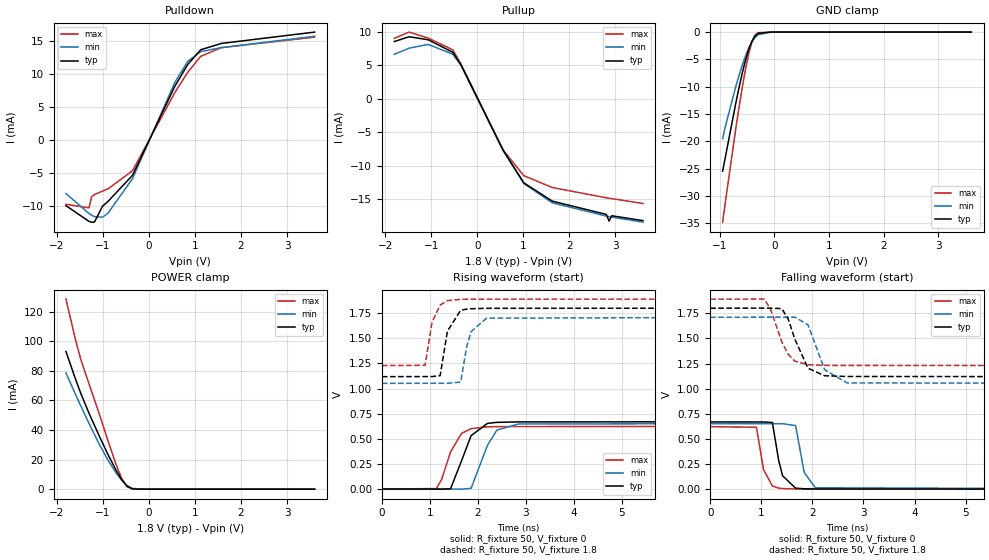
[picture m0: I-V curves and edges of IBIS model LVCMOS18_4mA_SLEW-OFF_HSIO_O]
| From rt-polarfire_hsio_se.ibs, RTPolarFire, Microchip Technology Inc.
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|   Model LVCMOS18_4mA_SLEW-OFF_HSIO_O
[Model]   LVCMOS18_4mA_SLEW-OFF_HSIO_O
Model_type   Output
Polarity   Non-Inverting
Enable   Active-High
Vmeas =   0.9
Cref =   5p
Rref =   1M
|   typ   min   max
C_comp_pullup   1.335e-12   1.335e-12   1.380e-12
C_comp_pulldown  1.335e-12   1.335e-12   1.380e-12
[Temperature Range]  25C   125C   -55C
[Voltage Range]  1.8   1.71   1.89
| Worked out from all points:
|   slope of the pulldown table from 0 to 0.27 V, typ, clamps not added: 66.5 ohm
|   slope of the pullup table from 0 to 0.27 V, typ, clamps not added: 70.9 ohm
|   GND clamp passes 1 mA (typ) near -0.37 V on its own axis
|   POWER clamp passes 1 mA (typ) near -0.43 V on its own axis
|   rising waveform, R_fixture 50, V_fixture 0: 20-80 % time 293ps typ, 300ps min, 297ps max; typ from 0 V to 0.669 V
|   rising waveform, R_fixture 50, V_fixture 1.8: 20-80 % time 171ps typ, 177ps min, 165ps max; typ from 1.12 V to 1.8 V
|   falling waveform, R_fixture 50, V_fixture 0: 20-80 % time 141ps typ, 145ps min, 133ps max; typ from 0.669 V to 0 V
|   falling waveform, R_fixture 50, V_fixture 1.8: 20-80 % time 296ps typ, 286ps min, 299ps max; typ from 1.8 V to 1.12 V
[GND Clamp]
| Voltage   I(typ)   I(min)   I(max)
-945mV    -25.47mA   -19.54mA   -34.82mA
-885.9mV  -22.44mA   -16.92mA   -30.49mA
-708.7mV  -13.24mA   -10.14mA   -17.96mA
-649.7mV  -10.37mA   -8.095mA   -14.06mA
-590.6mV  -7.705mA   -6.193mA   -10.39mA
-531.6mV  -5.322mA   -4.488mA   -7.054mA
-472.5mV  -3.308mA   -3.028mA   -4.171mA
-413.4mV  -1.757mA   -1.859mA   -1.935mA
-354.4mV  -739.5uA   -1.008mA   -580.7uA
-295.3mV  -232.3uA   -469.6uA   -100.4uA
-59.06mV  -489.8nA   -5.037uA   -176.4nA
3.6V      0A         0A         0A
[POWER Clamp]
| Voltage   I(typ)   I(min)   I(max)
-1.8V     93.11mA    78.62mA    128.6mA
-1.595V   74.64mA    64.3mA     101.3mA
-1.477V   64.73mA    56.26mA    87.68mA
-1.299V   51.32mA    44.43mA    71.22mA
-1.063V   35.01mA    29.59mA    49.65mA
-885.9mV  23.32mA    19.56mA    32.61mA
-708.7mV  12.62mA    10.87mA    16.4mA
-590.6mV  6.476mA    6.104mA    7.295mA
-472.5mV  1.932mA    2.452mA    1.539mA
-354.4mV  154uA      480.4uA    74.19uA
-59.06mV  800.7nA    2.877uA    466.9nA
3.6V      0A         0A         0A
[Pullup]
| Voltage   I(typ)   I(min)   I(max)
-1.8V     8.524mA    6.626mA    9.002mA
-1.477V   9.241mA    7.533mA    9.935mA
-1.063V   8.786mA    8.089mA    9.033mA
-531.6mV  6.927mA    6.646mA    7.296mA
-354.4mV  5.074mA    4.991mA    5.191mA
562.5mV   -7.703mA   -7.718mA   -7.67mA
1.012V    -12.57mA   -12.68mA   -11.51mA
1.631V    -15.31mA   -15.56mA   -13.27mA
2.804V    -17.29mA   -17.54mA   -14.81mA
2.863V    -18.28mA   -17.61mA   -14.87mA
2.922V    -17.49mA   -17.68mA   -14.93mA
3.6V      -18.22mA   -18.45mA   -15.66mA
[Pulldown]
| Voltage   I(typ)   I(min)   I(max)
-1.8V     -9.983mA   -8.14mA    -9.768mA
-1.299V   -12.37mA   -11.18mA   -10.32mA
-1.24V    -12.49mA   -11.44mA   -8.582mA
-1.181V   -12.47mA   -11.65mA   -8.302mA
-1.004V   -10.04mA   -11.73mA   -7.754mA
-885.9mV  -9.33mA    -11.1mA    -7.432mA
-354.4mV  -5.371mA   -5.881mA   -4.677mA
562.5mV   8.106mA    8.705mA    7.155mA
843.8mV   11.43mA    11.9mA     10.25mA
1.125V    13.67mA    13.39mA    12.67mA
1.575V    14.63mA    13.99mA    13.99mA
3.6V      16.35mA    15.72mA    15.58mA
[Ramp]
dV/dt_r   0.40141/0.293307n  0.391132/0.300125n  0.373348/0.296926n
dV/dt_f   0.408948/0.296334n  0.395259/0.285722n  0.396889/0.299047n
R_load = 50
[Rising Waveform]
R_fixture = 50
V_fixture = 0
V_fixture_min = 0
V_fixture_max = 0
| Time   V(typ)   V(min)   V(max)
0s        2.834uV    4.926uV    4.656uV
1.134ns   -858.8uV   -562.9uV   4.476mV
1.244ns   -1.435mV   -617.9uV   93.34mV
1.431ns   2.946mV    -711.6uV   369.2mV
1.659ns   280.3mV    -1.164mV   553.5mV
1.858ns   530.8mV    6.611mV    600.3mV
2.2ns     653.1mV    435.3mV    619.1mV
2.398ns   663.3mV    586.8mV    620.6mV
2.849ns   667.8mV    647.1mV    621.4mV
10ns      669mV      651.9mV    622.3mV
[Rising Waveform]
R_fixture = 50
V_fixture = 1.8
V_fixture_min = 1.71
V_fixture_max = 1.89
| Time   V(typ)   V(min)   V(max)
0s        1.118V     1.051V     1.228V
901ps     1.119V     1.052V     1.231V
1.046ns   1.119V     1.052V     1.66V
1.214ns   1.128V     1.052V     1.831V
1.365ns   1.57V      1.052V     1.875V
1.641ns   1.778V     1.064V     1.887V
1.766ns   1.79V      1.413V     1.888V
1.858ns   1.794V     1.566V     1.888V
2.181ns   1.798V     1.7V       1.889V
10ns      1.8V       1.71V      1.89V
[Falling Waveform]
R_fixture = 50
V_fixture = 0
V_fixture_min = 0
V_fixture_max = 0
| Time   V(typ)   V(min)   V(max)
0s        669mV      651.9mV    622.3mV
905ps     668.3mV    651.4mV    615.5mV
1.044ns   668.2mV    651.3mV    193.5mV
1.217ns   663.2mV    651.2mV    32.36mV
1.342ns   282.6mV    651.1mV    9.647mV
1.417ns   133.4mV    651.1mV    5.982mV
1.672ns   9.708mV    632.6mV    1.905mV
1.839ns   4.008mV    167.9mV    1.255mV
2.057ns   1.717mV    14mV       994uV
10ns      4.577uV    6.953uV    5.786uV
[Falling Waveform]
R_fixture = 50
V_fixture = 1.8
V_fixture_min = 1.71
V_fixture_max = 1.89
| Time   V(typ)   V(min)   V(max)
0s        1.8V       1.71V      1.89V
1.054ns   1.801V     1.711V     1.891V
1.18ns    1.801V     1.711V     1.794V
1.4ns     1.796V     1.711V     1.467V
1.525ns   1.695V     1.711V     1.343V
1.658ns   1.49V      1.711V     1.273V
1.915ns   1.203V     1.634V     1.238V
2.241ns   1.128V     1.187V     1.231V
2.677ns   1.121V     1.057V     1.23V
10ns      1.118V     1.051V     1.228V
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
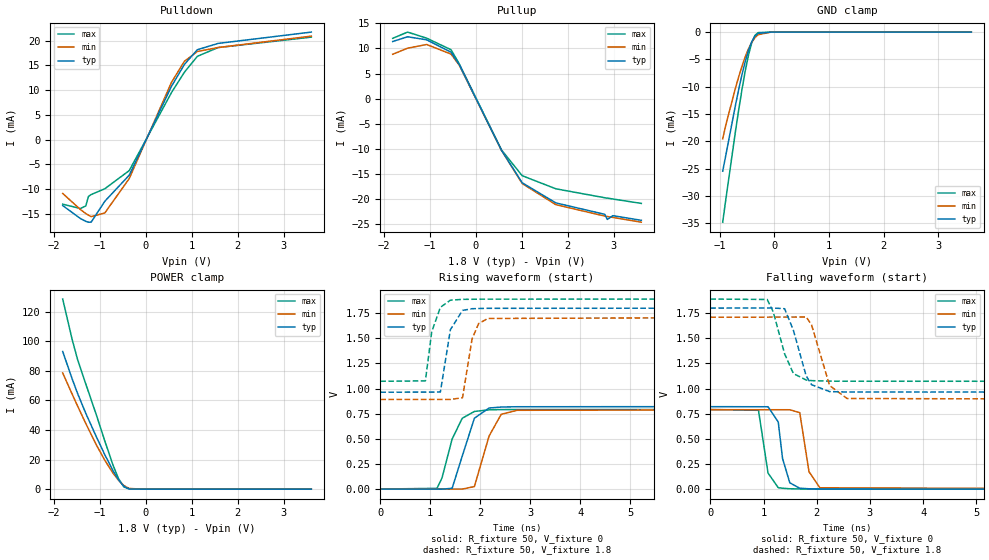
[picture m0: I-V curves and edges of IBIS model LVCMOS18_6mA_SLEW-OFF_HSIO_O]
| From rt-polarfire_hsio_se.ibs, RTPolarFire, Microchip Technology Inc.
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|   Model LVCMOS18_6mA_SLEW-OFF_HSIO_O
[Model]   LVCMOS18_6mA_SLEW-OFF_HSIO_O
Model_type   Output
Polarity   Non-Inverting
Enable   Active-High
Vmeas =   0.9
Cref =   5p
Rref =   1M
|   typ   min   max
C_comp_pullup   1.335e-12   1.335e-12   1.380e-12
C_comp_pulldown  1.335e-12   1.335e-12   1.380e-12
[Temperature Range]  25C   125C   -55C
[Voltage Range]  1.8   1.71   1.89
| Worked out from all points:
|   slope of the pulldown table from 0 to 0.27 V, typ, clamps not added: 50 ohm
|   slope of the pullup table from 0 to 0.27 V, typ, clamps not added: 53.2 ohm
|   GND clamp passes 1 mA (typ) near -0.37 V on its own axis
|   POWER clamp passes 1 mA (typ) near -0.43 V on its own axis
|   rising waveform, R_fixture 50, V_fixture 0: 20-80 % time 275ps typ, 279ps min, 286ps max; typ from 0 V to 0.82 V
|   rising waveform, R_fixture 50, V_fixture 1.8: 20-80 % time 170ps typ, 176ps min, 165ps max; typ from 0.964 V to 1.8 V
|   falling waveform, R_fixture 50, V_fixture 0: 20-80 % time 139ps typ, 141ps min, 131ps max; typ from 0.82 V to 0 V
|   falling waveform, R_fixture 50, V_fixture 1.8: 20-80 % time 262ps typ, 265ps min, 269ps max; typ from 1.8 V to 0.964 V
[GND Clamp]
| Voltage   I(typ)   I(min)   I(max)
-945mV    -25.47mA   -19.54mA   -34.82mA
-885.9mV  -22.44mA   -16.92mA   -30.49mA
-708.7mV  -13.24mA   -10.14mA   -17.96mA
-649.7mV  -10.37mA   -8.095mA   -14.06mA
-590.6mV  -7.705mA   -6.193mA   -10.39mA
-531.6mV  -5.322mA   -4.488mA   -7.054mA
-472.5mV  -3.308mA   -3.028mA   -4.171mA
-413.4mV  -1.757mA   -1.859mA   -1.935mA
-354.4mV  -739.5uA   -1.008mA   -580.7uA
-295.3mV  -232.3uA   -469.6uA   -100.4uA
-59.06mV  -489.8nA   -5.037uA   -176.4nA
3.6V      0A         0A         0A
[POWER Clamp]
| Voltage   I(typ)   I(min)   I(max)
-1.8V     93.11mA    78.62mA    128.6mA
-1.595V   74.64mA    64.3mA     101.3mA
-1.477V   64.73mA    56.26mA    87.68mA
-1.299V   51.32mA    44.43mA    71.22mA
-1.063V   35.01mA    29.59mA    49.65mA
-885.9mV  23.32mA    19.56mA    32.61mA
-708.7mV  12.62mA    10.87mA    16.4mA
-590.6mV  6.476mA    6.104mA    7.295mA
-472.5mV  1.932mA    2.452mA    1.539mA
-354.4mV  154uA      480.4uA    74.19uA
-59.06mV  800.7nA    2.877uA    466.9nA
3.6V      0A         0A         0A
[Pullup]
| Voltage   I(typ)   I(min)   I(max)
-1.8V     11.37mA    8.835mA    12.01mA
-1.477V   12.32mA    10.04mA    13.25mA
-1.063V   11.71mA    10.78mA    12.04mA
-531.6mV  9.235mA    8.86mA     9.725mA
-354.4mV  6.764mA    6.653mA    6.919mA
562.5mV   -10.27mA   -10.29mA   -10.22mA
1.012V    -16.76mA   -16.91mA   -15.35mA
1.744V    -20.77mA   -21.12mA   -17.96mA
2.804V    -23.04mA   -23.39mA   -19.74mA
2.863V    -24.06mA   -23.48mA   -19.82mA
2.981V    -23.31mA   -23.66mA   -19.99mA
3.6V      -24.24mA   -24.61mA   -20.87mA
[Pulldown]
| Voltage   I(typ)   I(min)   I(max)
-1.8V     -13.3mA    -10.85mA   -13.02mA
-1.417V   -15.91mA   -14.09mA   -13.9mA
-1.299V   -16.49mA   -14.91mA   -13.38mA
-1.24V    -16.66mA   -15.25mA   -11.45mA
-1.181V   -16.64mA   -15.53mA   -11.07mA
-885.9mV  -12.44mA   -14.8mA    -9.908mA
-354.4mV  -7.151mA   -7.834mA   -6.231mA
562.5mV   10.79mA    11.6mA     9.529mA
843.8mV   15.22mA    15.85mA    13.65mA
1.125V    18.19mA    17.83mA    16.86mA
1.575V    19.46mA    18.63mA    18.62mA
3.6V      21.75mA    20.93mA    20.73mA
[Ramp]
dV/dt_r   0.492094/0.274729n  0.474071/0.279483n  0.475189/0.286025n
dV/dt_f   0.501814/0.262317n  0.491173/0.265053n  0.490889/0.268969n
R_load = 50
[Rising Waveform]
R_fixture = 50
V_fixture = 0
V_fixture_min = 0
V_fixture_max = 0
| Time   V(typ)   V(min)   V(max)
0s        2.644uV    4.433uV    4.313uV
1.135ns   -889.7uV   -659.8uV   6.848mV
1.235ns   -1.315mV   -718.3uV   109.9mV
1.438ns   7.438mV    -837.1uV   496.9mV
1.64ns    326.7mV    -955.3uV   703.9mV
1.884ns   704.7mV    24.98mV    771.8mV
2.178ns   805.9mV    527.5mV    788.2mV
2.421ns   815.9mV    743.7mV    790.3mV
2.737ns   818.8mV    783.4mV    791mV
10ns      820.2mV    790.1mV    792mV
[Rising Waveform]
R_fixture = 50
V_fixture = 1.8
V_fixture_min = 1.71
V_fixture_max = 1.89
| Time   V(typ)   V(min)   V(max)
0s        963.6mV    891.3mV    1.072V
903ps     964.1mV    891.2mV    1.076V
1.03ns    964.1mV    891.2mV    1.564V
1.203ns   966mV      891.2mV    1.808V
1.404ns   1.586V     891.2mV    1.879V
1.646ns   1.777V     908.6mV    1.887V
1.838ns   1.794V     1.495V     1.888V
1.969ns   1.796V     1.646V     1.889V
2.153ns   1.798V     1.697V     1.889V
10ns      1.8V       1.71V      1.89V
[Falling Waveform]
R_fixture = 50
V_fixture = 0
V_fixture_min = 0
V_fixture_max = 0
| Time   V(typ)   V(min)   V(max)
0s        820.2mV    790.2mV    792mV
906ps     819.5mV    789.8mV    784mV
1.085ns   819.4mV    789.7mV    160.5mV
1.277ns   667.8mV    789.6mV    14.76mV
1.358ns   304.5mV    789.6mV    9.173mV
1.494ns   63.29mV    789.5mV    4.2mV
1.681ns   9.213mV    760.7mV    1.995mV
1.855ns   3.886mV    173mV      1.426mV
2.06ns    1.824mV    13.65mV    970.8uV
10ns      4.001uV    6.073uV    4.556uV
[Falling Waveform]
R_fixture = 50
V_fixture = 1.8
V_fixture_min = 1.71
V_fixture_max = 1.89
| Time   V(typ)   V(min)   V(max)
0s        1.8V       1.71V      1.89V
1.07ns    1.801V     1.71V      1.886V
1.182ns   1.801V     1.711V     1.764V
1.397ns   1.794V     1.711V     1.345V
1.561ns   1.581V     1.711V     1.15V
1.801ns   1.127V     1.712V     1.085V
1.902ns   1.039V     1.635V     1.079V
2.242ns   970mV      1.03V      1.074V
2.569ns   966mV      901.4mV    1.073V
10ns      963.6mV    891.3mV    1.072V
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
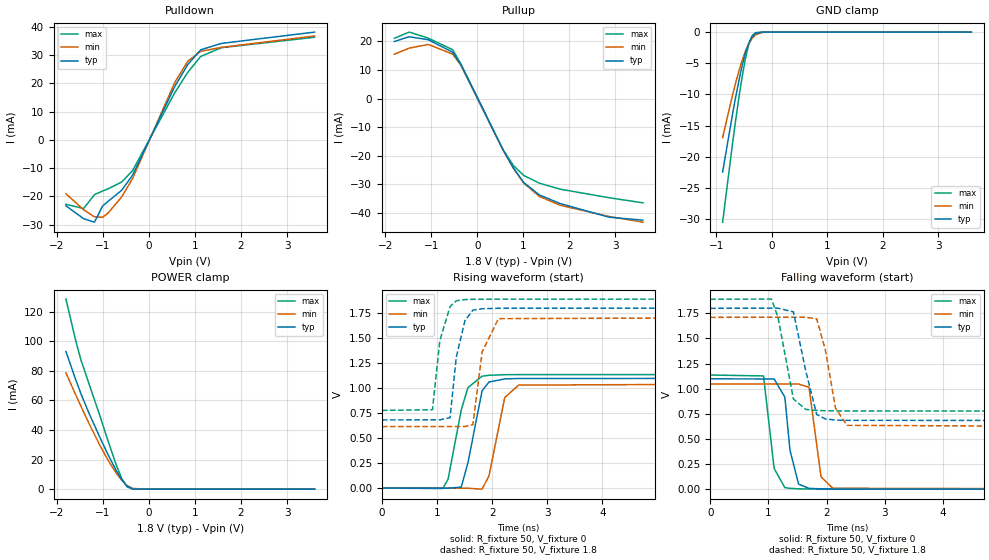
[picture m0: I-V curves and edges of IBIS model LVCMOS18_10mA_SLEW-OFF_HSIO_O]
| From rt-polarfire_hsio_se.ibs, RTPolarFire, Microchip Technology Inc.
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|   Model LVCMOS18_10mA_SLEW-OFF_HSIO_O
[Model]   LVCMOS18_10mA_SLEW-OFF_HSIO_O
Model_type   Output
Polarity   Non-Inverting
Enable   Active-High
Vmeas =   0.9
Cref =   5p
Rref =   1M
|   typ   min   max
C_comp_pullup   1.335e-12   1.335e-12   1.380e-12
C_comp_pulldown  1.335e-12   1.335e-12   1.380e-12
[Temperature Range]  25C   125C   -55C
[Voltage Range]  1.8   1.71   1.89
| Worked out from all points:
|   slope of the pulldown table from 0 to 0.27 V, typ, clamps not added: 28.6 ohm
|   slope of the pullup table from 0 to 0.27 V, typ, clamps not added: 30.4 ohm
|   GND clamp passes 1 mA (typ) near -0.37 V on its own axis
|   POWER clamp passes 1 mA (typ) near -0.43 V on its own axis
|   rising waveform, R_fixture 50, V_fixture 0: 20-80 % time 214ps typ, 219ps min, 240ps max; typ from 0 V to 1.1 V
|   rising waveform, R_fixture 50, V_fixture 1.8: 20-80 % time 168ps typ, 177ps min, 162ps max; typ from 0.682 V to 1.8 V
|   falling waveform, R_fixture 50, V_fixture 0: 20-80 % time 136ps typ, 131ps min, 128ps max; typ from 1.1 V to 0 V
|   falling waveform, R_fixture 50, V_fixture 1.8: 20-80 % time 204ps typ, 204ps min, 201ps max; typ from 1.8 V to 0.682 V
[GND Clamp]
| Voltage   I(typ)   I(min)   I(max)
-885.9mV  -22.44mA   -16.92mA   -30.49mA
-708.7mV  -13.24mA   -10.14mA   -17.96mA
-649.7mV  -10.37mA   -8.095mA   -14.06mA
-590.6mV  -7.705mA   -6.193mA   -10.39mA
-531.6mV  -5.322mA   -4.488mA   -7.054mA
-472.5mV  -3.308mA   -3.028mA   -4.171mA
-413.4mV  -1.757mA   -1.859mA   -1.935mA
-354.4mV  -739.5uA   -1.008mA   -580.7uA
-295.3mV  -232.3uA   -469.6uA   -100.4uA
-177.2mV  -12.01uA   -62.89uA   -1.688uA
-59.06mV  -489.8nA   -5.037uA   -176.4nA
3.6V      0A         0A         0A
[POWER Clamp]
| Voltage   I(typ)   I(min)   I(max)
-1.8V     93.11mA    78.62mA    128.6mA
-1.595V   74.64mA    64.3mA     101.3mA
-1.477V   64.73mA    56.26mA    87.68mA
-1.299V   51.32mA    44.43mA    71.22mA
-1.063V   35.01mA    29.59mA    49.65mA
-885.9mV  23.32mA    19.56mA    32.61mA
-708.7mV  12.62mA    10.87mA    16.4mA
-590.6mV  6.476mA    6.104mA    7.295mA
-472.5mV  1.932mA    2.452mA    1.539mA
-354.4mV  154uA      480.4uA    74.19uA
-59.06mV  800.7nA    2.877uA    466.9nA
3.6V      0A         0A         0A
[Pullup]
| Voltage   I(typ)   I(min)   I(max)
-1.8V     19.89mA    15.46mA    21.01mA
-1.477V   21.56mA    17.58mA    23.18mA
-1.063V   20.5mA     18.87mA    21.07mA
-531.6mV  16.16mA    15.5mA     17.02mA
-354.4mV  11.83mA    11.64mA    12.11mA
562.5mV   -17.97mA   -18mA      -17.89mA
787.5mV   -24.28mA   -24.39mA   -23.42mA
1.012V    -29.33mA   -29.58mA   -26.86mA
1.35V     -33.66mA   -34.16mA   -29.55mA
1.8V      -36.65mA   -37.26mA   -31.64mA
2.863V    -41.43mA   -41.17mA   -34.63mA
3.6V      -42.46mA   -43.17mA   -36.42mA
[Pulldown]
| Voltage   I(typ)   I(min)   I(max)
-1.8V     -23.31mA   -19.03mA   -22.78mA
-1.417V   -27.87mA   -24.7mA    -24.28mA
-1.181V   -29.1mA    -27.2mA    -19.36mA
-1.004V   -23.39mA   -27.37mA   -18.08mA
-885.9mV  -21.75mA   -25.88mA   -17.32mA
-590.6mV  -17.83mA   -20.19mA   -14.91mA
-354.4mV  -12.5mA    -13.7mA    -10.89mA
562.5mV   18.87mA    20.3mA     16.65mA
843.8mV   26.62mA    27.77mA    23.87mA
1.125V    31.84mA    31.3mA     29.49mA
1.575V    34.1mA     32.71mA    32.59mA
3.6V      38.11mA    36.73mA    36.29mA
[Ramp]
dV/dt_r   0.658922/0.213813n  0.628223/0.218901n  0.681794/0.239976n
dV/dt_f   0.670748/0.204446n  0.656902/0.204355n  0.667707/0.200974n
R_load = 50
[Rising Waveform]
R_fixture = 50
V_fixture = 0
V_fixture_min = 0
V_fixture_max = 0
| Time   V(typ)   V(min)   V(max)
0s        2.283uV    3.514uV    3.645uV
1.106ns   -434.6uV   -629.6uV   -3.435mV
1.201ns   -472.1uV   -684uV     90.45mV
1.439ns   10.04mV    -820.3uV   781.4mV
1.561ns   254.2mV    -890.1uV   1.005V
1.816ns   971.4mV    -10.12mV   1.119V
1.942ns   1.061V     121.6mV    1.128V
2.228ns   1.092V     905.6mV    1.134V
2.48ns    1.096V     1.03V      1.135V
10ns      1.098V     1.047V     1.136V
[Rising Waveform]
R_fixture = 50
V_fixture = 1.8
V_fixture_min = 1.71
V_fixture_max = 1.89
| Time   V(typ)   V(min)   V(max)
0s        682.1mV    615.1mV    777.1mV
917ps     682.7mV    615.7mV    783.7mV
1.052ns   682.8mV    615.8mV    1.477V
1.237ns   704.6mV    615.9mV    1.816V
1.349ns   1.309V     616mV      1.873V
1.507ns   1.675V     616.1mV    1.885V
1.65ns    1.779V     635.2mV    1.888V
1.819ns   1.794V     1.362V     1.888V
2.113ns   1.798V     1.694V     1.889V
10ns      1.8V       1.71V      1.89V
[Falling Waveform]
R_fixture = 50
V_fixture = 0
V_fixture_min = 0
V_fixture_max = 0
| Time   V(typ)   V(min)   V(max)
0s        1.098V     1.047V     1.136V
916ps     1.097V     1.047V     1.127V
1.098ns   1.097V     1.046V     206.6mV
1.282ns   916.9mV    1.046V     15.19mV
1.37ns    389.1mV    1.046V     8.193mV
1.518ns   49.98mV    1.046V     3.269mV
1.697ns   8.152mV    1.014V     2.002mV
1.904ns   2.7mV      121.6mV    1.338mV
2.106ns   1.578mV    8.953mV    973.5uV
10ns      3.433uV    4.527uV    4.326uV
[Falling Waveform]
R_fixture = 50
V_fixture = 1.8
V_fixture_min = 1.71
V_fixture_max = 1.89
| Time   V(typ)   V(min)   V(max)
0s        1.8V       1.71V      1.89V
1.052ns   1.801V     1.711V     1.892V
1.163ns   1.801V     1.711V     1.714V
1.429ns   1.765V     1.711V     897.9mV
1.64ns    1.18V      1.711V     794.1mV
1.829ns   743.2mV    1.695V     783.4mV
1.977ns   698.9mV    1.388V     780.7mV
2.153ns   688mV      805.5mV    779.1mV
2.349ns   685mV      635.1mV    778.3mV
10ns      682.1mV    615.1mV    777.1mV
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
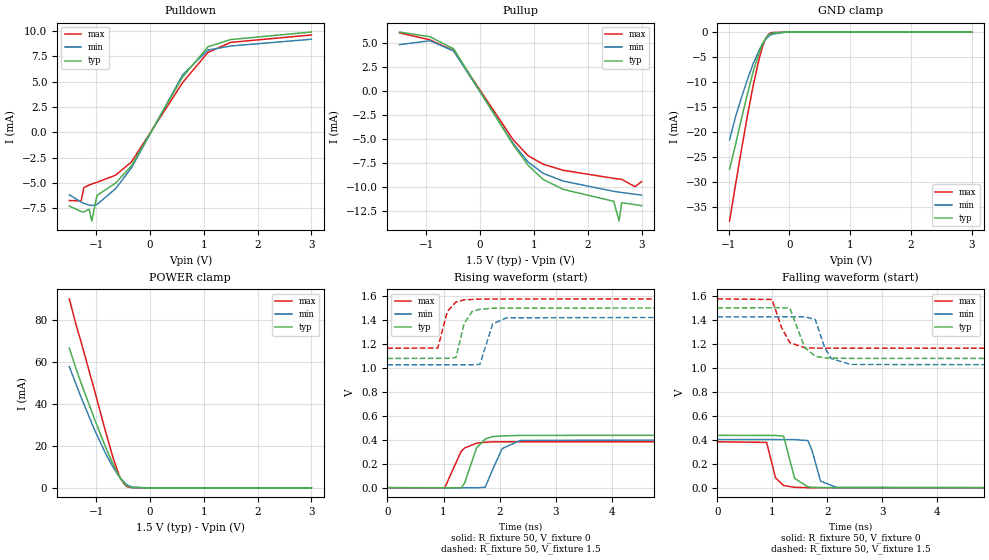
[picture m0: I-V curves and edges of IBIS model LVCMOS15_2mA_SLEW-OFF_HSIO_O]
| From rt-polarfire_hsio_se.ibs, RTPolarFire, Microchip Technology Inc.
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|   Model LVCMOS15_2mA_SLEW-OFF_HSIO_O
[Model]   LVCMOS15_2mA_SLEW-OFF_HSIO_O
Model_type   Output
Polarity   Non-Inverting
Enable   Active-High
Vmeas =   0.75
Cref =   5p
Rref =   1M
|   typ   min   max
C_comp_pullup   1.335e-12   1.335e-12   1.380e-12
C_comp_pulldown  1.335e-12   1.335e-12   1.380e-12
[Temperature Range]  25C   125C   -55C
[Voltage Range]  1.5   1.425   1.575
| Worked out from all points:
|   slope of the pulldown table from 0 to 0.225 V, typ, clamps not added: 105 ohm
|   slope of the pullup table from 0 to 0.225 V, typ, clamps not added: 106 ohm
|   GND clamp passes 1 mA (typ) near -0.37 V on its own axis
|   POWER clamp passes 1 mA (typ) near -0.43 V on its own axis
|   rising waveform, R_fixture 50, V_fixture 0: 20-80 % time 207ps typ, 213ps min, 212ps max; typ from 0 V to 0.438 V
|   rising waveform, R_fixture 50, V_fixture 1.5: 20-80 % time 141ps typ, 144ps min, 142ps max; typ from 1.08 V to 1.5 V
|   falling waveform, R_fixture 50, V_fixture 0: 20-80 % time 127ps typ, 132ps min, 115ps max; typ from 0.438 V to 0 V
|   falling waveform, R_fixture 50, V_fixture 1.5: 20-80 % time 195ps typ, 196ps min, 190ps max; typ from 1.5 V to 1.08 V
[GND Clamp]
| Voltage   I(typ)   I(min)   I(max)
-984.4mV  -27.37mA   -21.52mA   -37.7mA
-885.9mV  -22.43mA   -16.92mA   -30.48mA
-787.5mV  -17.27mA   -13.04mA   -23.4mA
-689.1mV  -12.26mA   -9.44mA    -16.62mA
-590.6mV  -7.7mA     -6.188mA   -10.38mA
-492.2mV  -3.93mA    -3.481mA   -5.066mA
-443mV    -2.467mA   -2.402mA   -2.955mA
-393.7mV  -1.355mA   -1.538mA   -1.375mA
-344.5mV  -621.9uA   -897uA     -448.3uA
-295.3mV  -232uA     -469.2uA   -100.1uA
-49.22mV  -334.5nA   -3.793uA   -95.68nA
3V        0A         0A         0A
[POWER Clamp]
| Voltage   I(typ)   I(min)   I(max)
-1.5V     66.64mA    57.8mA     90.1mA
-1.378V   57.06mA    49.6mA     78.07mA
-1.28V    49.9mA     43.13mA    69.49mA
-1.034V   32.99mA    27.83mA    46.7mA
-836.7mV  20.16mA    16.97mA    27.85mA
-689.1mV  11.42mA    9.956mA    14.55mA
-590.6mV  6.331mA    6.012mA    7.055mA
-541.4mV  4.184mA    4.318mA    4.125mA
-443mV    1.134mA    1.688mA    703.5uA
-344.5mV  93.53uA    432.5uA    21.45uA
-49.22mV  620.3nA    2.506uA    250nA
3V        0A         0A         0A
[Pullup]
| Voltage   I(typ)   I(min)   I(max)
-1.5V     6.18mA     4.859mA    6.094mA
-935.2mV  5.694mA    5.27mA     5.37mA
-492.2mV  4.426mA    4.2mA      4.229mA
609.4mV   -5.56mA    -5.419mA   -5.05mA
890.6mV   -7.739mA   -7.402mA   -6.741mA
1.172V    -9.231mA   -8.587mA   -7.636mA
1.549V    -10.27mA   -9.403mA   -8.272mA
2.484V    -11.51mA   -10.47mA   -9.113mA
2.583V    -13.57mA   -10.55mA   -9.182mA
2.632V    -11.66mA   -10.59mA   -9.217mA
2.878V    -11.86mA   -10.77mA   -9.983mA
3V        -11.96mA   -10.86mA   -9.459mA
[Pulldown]
| Voltage   I(typ)   I(min)   I(max)
-1.5V     -7.275mA   -6.165mA   -6.733mA
-1.28V    -7.812mA   -6.883mA   -6.77mA
-1.23V    -7.866mA   -7.008mA   -5.46mA
-1.132V   -7.585mA   -7.185mA   -5.202mA
-1.083V   -8.754mA   -7.219mA   -5.104mA
-984.4mV  -6.223mA   -7.118mA   -4.928mA
-639.8mV  -5.015mA   -5.561mA   -4.231mA
-344.5mV  -3.295mA   -3.502mA   -2.921mA
609.4mV   5.478mA    5.693mA    4.927mA
1.078V    8.442mA    8.118mA    7.888mA
1.5V      9.156mA    8.521mA    8.875mA
3V        9.898mA    9.184mA    9.609mA
[Ramp]
dV/dt_r   0.262503/0.206641n  0.241619/0.213308n  0.230354/0.211881n
dV/dt_f   0.253149/0.195296n  0.24003/0.195581n  0.247252/0.190015n
R_load = 50
[Rising Waveform]
R_fixture = 50
V_fixture = 0
V_fixture_min = 0
V_fixture_max = 0
| Time   V(typ)   V(min)   V(max)
0s        1.828uV    3.945uV    2.886uV
1.021ns   -815.1uV   -330.3uV   -631.2uV
1.314ns   -1.271mV   -426.3uV   303.6mV
1.376ns   39.81mV    -446.6uV   331.5mV
1.588ns   332.5mV    -516uV     371.4mV
1.741ns   406mV      3.314mV    378.6mV
1.87ns    425.8mV    147mV      382.5mV
2.043ns   432.2mV    326.2mV    382.8mV
2.369ns   436.3mV    394.4mV    383.3mV
10ns      437.5mV    402.7mV    383.9mV
[Rising Waveform]
R_fixture = 50
V_fixture = 1.5
V_fixture_min = 1.425
V_fixture_max = 1.575
| Time   V(typ)   V(min)   V(max)
0s        1.078V     1.025V     1.163V
898ps     1.079V     1.025V     1.165V
1.069ns   1.079V     1.025V     1.471V
1.221ns   1.086V     1.025V     1.549V
1.366ns   1.367V     1.025V     1.567V
1.507ns   1.469V     1.025V     1.57V
1.647ns   1.488V     1.029V     1.573V
1.874ns   1.497V     1.365V     1.574V
2.119ns   1.498V     1.417V     1.574V
10ns      1.5V       1.425V     1.575V
[Falling Waveform]
R_fixture = 50
V_fixture = 0
V_fixture_min = 0
V_fixture_max = 0
| Time   V(typ)   V(min)   V(max)
0s        437.5mV    402.7mV    383.9mV
895ps     436.8mV    402.3mV    378.9mV
1.056ns   436.6mV    402.2mV    83.72mV
1.203ns   431.2mV    402.2mV    19.36mV
1.404ns   78.46mV    402.1mV    4.495mV
1.645ns   8.743mV    393.9mV    1.562mV
1.72ns    4.849mV    312.2mV    1.152mV
1.876ns   2.366mV    55.73mV    772.1uV
2.163ns   1.039mV    4.457mV    745uV
10ns      3.065uV    5.321uV    3.238uV
[Falling Waveform]
R_fixture = 50
V_fixture = 1.5
V_fixture_min = 1.425
V_fixture_max = 1.575
| Time   V(typ)   V(min)   V(max)
0s        1.5V       1.425V     1.575V
992ps     1.501V     1.425V     1.57V
1.169ns   1.501V     1.426V     1.333V
1.318ns   1.497V     1.426V     1.21V
1.586ns   1.17V      1.426V     1.168V
1.779ns   1.097V     1.404V     1.165V
1.954ns   1.083V     1.164V     1.164V
2.074ns   1.081V     1.077V     1.164V
2.422ns   1.079V     1.028V     1.164V
10ns      1.078V     1.025V     1.163V
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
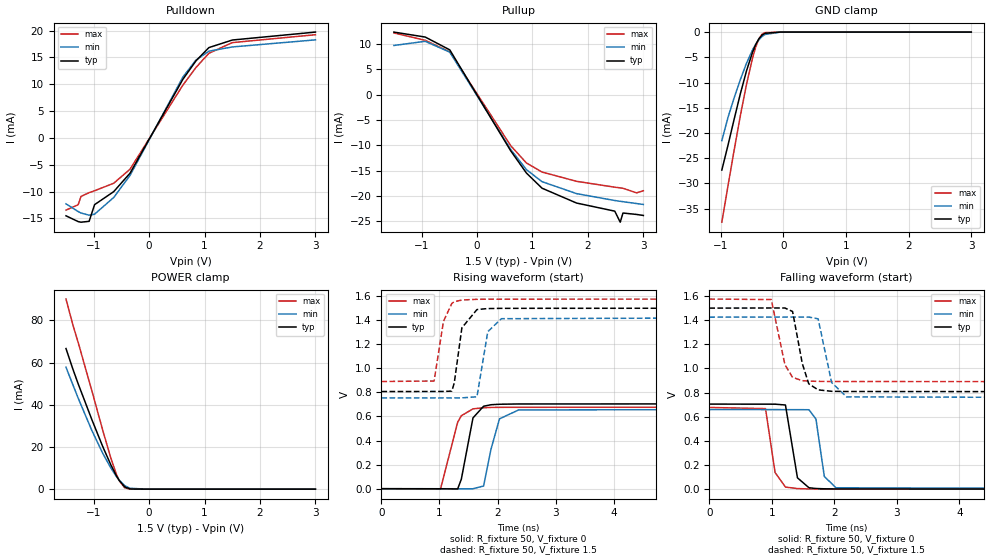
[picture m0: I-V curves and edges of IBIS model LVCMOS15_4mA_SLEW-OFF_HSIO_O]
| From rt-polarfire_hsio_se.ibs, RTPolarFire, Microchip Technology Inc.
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|   Model LVCMOS15_4mA_SLEW-OFF_HSIO_O
[Model]   LVCMOS15_4mA_SLEW-OFF_HSIO_O
Model_type   Output
Polarity   Non-Inverting
Enable   Active-High
Vmeas =   0.75
Cref =   5p
Rref =   1M
|   typ   min   max
C_comp_pullup   1.335e-12   1.335e-12   1.380e-12
C_comp_pulldown  1.335e-12   1.335e-12   1.380e-12
[Temperature Range]  25C   125C   -55C
[Voltage Range]  1.5   1.425   1.575
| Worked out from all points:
|   slope of the pulldown table from 0 to 0.225 V, typ, clamps not added: 52.7 ohm
|   slope of the pullup table from 0 to 0.225 V, typ, clamps not added: 52.8 ohm
|   GND clamp passes 1 mA (typ) near -0.37 V on its own axis
|   POWER clamp passes 1 mA (typ) near -0.43 V on its own axis
|   rising waveform, R_fixture 50, V_fixture 0: 20-80 % time 164ps typ, 178ps min, 191ps max; typ from 0 V to 0.705 V
|   rising waveform, R_fixture 50, V_fixture 1.5: 20-80 % time 125ps typ, 124ps min, 134ps max; typ from 0.807 V to 1.5 V
|   falling waveform, R_fixture 50, V_fixture 0: 20-80 % time 107ps typ, 106ps min, 104ps max; typ from 0.705 V to 0 V
|   falling waveform, R_fixture 50, V_fixture 1.5: 20-80 % time 151ps typ, 150ps min, 150ps max; typ from 1.5 V to 0.807 V
[GND Clamp]
| Voltage   I(typ)   I(min)   I(max)
-984.4mV  -27.37mA   -21.52mA   -37.7mA
-885.9mV  -22.43mA   -16.92mA   -30.48mA
-787.5mV  -17.27mA   -13.04mA   -23.4mA
-689.1mV  -12.26mA   -9.44mA    -16.62mA
-590.6mV  -7.7mA     -6.188mA   -10.38mA
-492.2mV  -3.93mA    -3.481mA   -5.066mA
-443mV    -2.467mA   -2.402mA   -2.955mA
-393.7mV  -1.355mA   -1.538mA   -1.375mA
-344.5mV  -621.9uA   -897uA     -448.3uA
-295.3mV  -232uA     -469.2uA   -100.1uA
-49.22mV  -334.5nA   -3.793uA   -95.68nA
3V        0A         0A         0A
[POWER Clamp]
| Voltage   I(typ)   I(min)   I(max)
-1.5V     66.64mA    57.8mA     90.1mA
-1.378V   57.06mA    49.6mA     78.07mA
-1.28V    49.9mA     43.13mA    69.49mA
-1.034V   32.99mA    27.83mA    46.7mA
-836.7mV  20.16mA    16.97mA    27.85mA
-689.1mV  11.42mA    9.956mA    14.55mA
-590.6mV  6.331mA    6.012mA    7.055mA
-541.4mV  4.184mA    4.318mA    4.125mA
-443mV    1.134mA    1.688mA    703.5uA
-344.5mV  93.53uA    432.5uA    21.45uA
-49.22mV  620.3nA    2.506uA    250nA
3V        0A         0A         0A
[Pullup]
| Voltage   I(typ)   I(min)   I(max)
-1.5V     12.36mA    9.717mA    12.19mA
-935.2mV  11.38mA    10.54mA    10.74mA
-492.2mV  8.849mA    8.399mA    8.457mA
609.4mV   -11.12mA   -10.84mA   -10.1mA
890.6mV   -15.47mA   -14.8mA    -13.48mA
1.172V    -18.46mA   -17.17mA   -15.27mA
1.795V    -21.39mA   -19.53mA   -17.1mA
2.484V    -22.99mA   -20.89mA   -18.26mA
2.583V    -25.17mA   -21.05mA   -18.4mA
2.632V    -23.36mA   -21.12mA   -18.47mA
2.878V    -23.64mA   -21.49mA   -19.38mA
3V        -23.84mA   -21.67mA   -18.96mA
[Pulldown]
| Voltage   I(typ)   I(min)   I(max)
-1.5V     -14.53mA   -12.3mA    -13.47mA
-1.28V    -15.61mA   -13.74mA   -12.46mA
-1.23V    -15.72mA   -14mA      -10.92mA
-1.083V   -15.56mA   -14.42mA   -10.21mA
-984.4mV  -12.45mA   -14.23mA   -9.857mA
-639.8mV  -10.03mA   -11.12mA   -8.463mA
-344.5mV  -6.581mA   -6.994mA   -5.838mA
609.4mV   10.93mA    11.35mA    9.846mA
843.8mV   14.35mA    14.5mA     13.11mA
1.078V    16.83mA    16.16mA    15.77mA
1.5V      18.24mA    16.95mA    17.76mA
3V        19.72mA    18.27mA    19.23mA
[Ramp]
dV/dt_r   0.422899/0.163829n  0.395776/0.178187n  0.40623/0.190688n
dV/dt_f   0.41579/0.151302n  0.402688/0.149868n  0.410802/0.149714n
R_load = 50
[Rising Waveform]
R_fixture = 50
V_fixture = 0
V_fixture_min = 0
V_fixture_max = 0
| Time   V(typ)   V(min)   V(max)
0s        1.706uV    3.25uV     2.624uV
1.017ns   -625.9uV   -471.9uV   -3.943mV
1.313ns   -2.092mV   -610.2uV   551.2mV
1.376ns   77.69mV    -639.6uV   605.5mV
1.577ns   587.7mV    -733.6uV   663.2mV
1.76ns    684.9mV    22.34mV    672.2mV
1.889ns   697.4mV    330.6mV    675mV
2.034ns   701.4mV    580mV      675.6mV
2.364ns   703.7mV    654.3mV    676.1mV
10ns      704.8mV    659.6mV    677.1mV
[Rising Waveform]
R_fixture = 50
V_fixture = 1.5
V_fixture_min = 1.425
V_fixture_max = 1.575
| Time   V(typ)   V(min)   V(max)
0s        807mV      753.8mV    890.3mV
907ps     807.6mV    754mV      894.5mV
1.069ns   807.7mV    754.1mV    1.39V
1.213ns   810.5mV    754.1mV    1.539V
1.255ns   879mV      754.1mV    1.553V
1.386ns   1.336V     754.2mV    1.567V
1.646ns   1.488V     763.5mV    1.573V
1.832ns   1.496V     1.304V     1.574V
2.066ns   1.498V     1.412V     1.574V
10ns      1.5V       1.425V     1.575V
[Falling Waveform]
R_fixture = 50
V_fixture = 0
V_fixture_min = 0
V_fixture_max = 0
| Time   V(typ)   V(min)   V(max)
0s        704.8mV    659.6mV    677mV
899ps     704.2mV    659.2mV    667.3mV
1.052ns   704.1mV    659.1mV    137.7mV
1.218ns   697.3mV    659mV      17.4mV
1.41ns    94mV       658.9mV    4.811mV
1.594ns   11.97mV    658mV      1.955mV
1.706ns   5.467mV    581.3mV    1.549mV
1.84ns    3.07mV     105.6mV    1.192mV
2.026ns   1.57mV     11.52mV    849.7uV
10ns      2.863uV    5.171uV    3.165uV
[Falling Waveform]
R_fixture = 50
V_fixture = 1.5
V_fixture_min = 1.425
V_fixture_max = 1.575
| Time   V(typ)   V(min)   V(max)
0s        1.5V       1.425V     1.575V
991ps     1.501V     1.426V     1.571V
1.209ns   1.501V     1.426V     1.032V
1.332ns   1.472V     1.426V     926mV
1.488ns   1.04V      1.426V     898.9mV
1.591ns   872.7mV    1.426V     895.1mV
1.741ns   822.8mV    1.411V     893.1mV
1.957ns   810.7mV    883.4mV    892.2mV
2.196ns   809mV      764.6mV    891.7mV
10ns      807mV      753.8mV    890.3mV
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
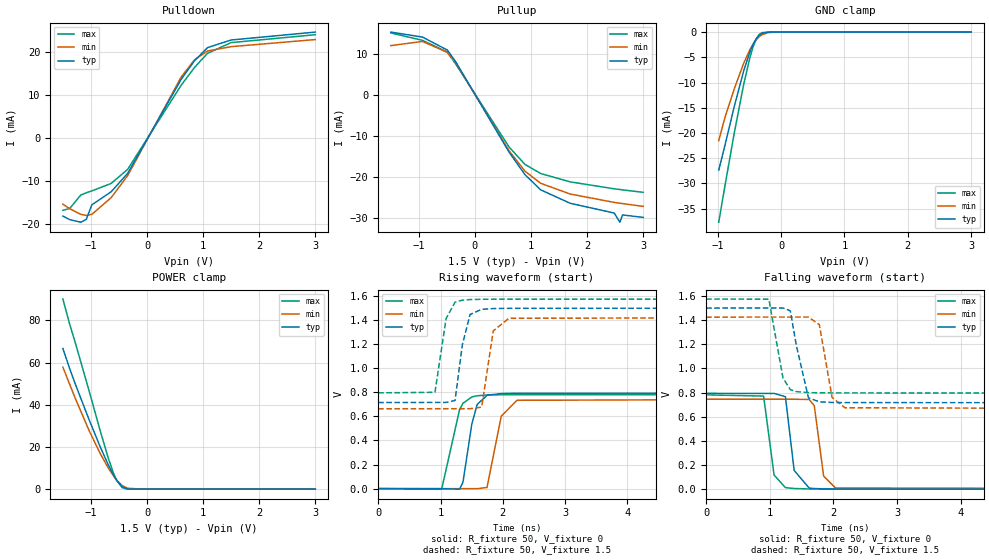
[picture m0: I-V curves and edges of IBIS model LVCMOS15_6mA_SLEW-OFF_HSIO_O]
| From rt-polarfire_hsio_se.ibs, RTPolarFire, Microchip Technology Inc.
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|   Model LVCMOS15_6mA_SLEW-OFF_HSIO_O
[Model]   LVCMOS15_6mA_SLEW-OFF_HSIO_O
Model_type   Output
Polarity   Non-Inverting
Enable   Active-High
Vmeas =   0.75
Cref =   5p
Rref =   1M
|   typ   min   max
C_comp_pullup   1.335e-12   1.335e-12   1.380e-12
C_comp_pulldown  1.335e-12   1.335e-12   1.380e-12
[Temperature Range]  25C   125C   -55C
[Voltage Range]  1.5   1.425   1.575
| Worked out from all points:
|   slope of the pulldown table from 0 to 0.225 V, typ, clamps not added: 42.2 ohm
|   slope of the pullup table from 0 to 0.225 V, typ, clamps not added: 42.2 ohm
|   GND clamp passes 1 mA (typ) near -0.37 V on its own axis
|   POWER clamp passes 1 mA (typ) near -0.43 V on its own axis
|   rising waveform, R_fixture 50, V_fixture 0: 20-80 % time 147ps typ, 156ps min, 177ps max; typ from 0 V to 0.794 V
|   rising waveform, R_fixture 50, V_fixture 1.5: 20-80 % time 120ps typ, 114ps min, 128ps max; typ from 0.715 V to 1.5 V
|   falling waveform, R_fixture 50, V_fixture 0: 20-80 % time 97.4ps typ, 100ps min, 98.9ps max; typ from 0.794 V to 0 V
|   falling waveform, R_fixture 50, V_fixture 1.5: 20-80 % time 133ps typ, 137ps min, 136ps max; typ from 1.5 V to 0.715 V
[GND Clamp]
| Voltage   I(typ)   I(min)   I(max)
-984.4mV  -27.37mA   -21.52mA   -37.7mA
-885.9mV  -22.43mA   -16.92mA   -30.48mA
-738.3mV  -14.72mA   -11.21mA   -19.96mA
-590.6mV  -7.7mA     -6.188mA   -10.38mA
-492.2mV  -3.93mA    -3.481mA   -5.066mA
-443mV    -2.467mA   -2.402mA   -2.955mA
-393.7mV  -1.355mA   -1.538mA   -1.375mA
-344.5mV  -621.9uA   -897uA     -448.3uA
-295.3mV  -232uA     -469.2uA   -100.1uA
-196.9mV  -20.29uA   -91.32uA   -3.19uA
-49.22mV  -334.5nA   -3.793uA   -95.68nA
3V        0A         0A         0A
[POWER Clamp]
| Voltage   I(typ)   I(min)   I(max)
-1.5V     66.64mA    57.8mA     90.1mA
-1.378V   57.06mA    49.6mA     78.07mA
-1.28V    49.9mA     43.13mA    69.49mA
-1.034V   32.99mA    27.83mA    46.7mA
-836.7mV  20.16mA    16.97mA    27.85mA
-689.1mV  11.42mA    9.956mA    14.55mA
-590.6mV  6.331mA    6.012mA    7.055mA
-541.4mV  4.184mA    4.318mA    4.125mA
-443mV    1.134mA    1.688mA    703.5uA
-344.5mV  93.53uA    432.5uA    21.45uA
-49.22mV  620.3nA    2.506uA    250nA
3V        0A         0A         0A
[Pullup]
| Voltage   I(typ)   I(min)   I(max)
-1.5V     15.45mA    12.15mA    15.24mA
-935.2mV  14.23mA    13.17mA    13.43mA
-492.2mV  11.06mA    10.5mA     10.57mA
-344.5mV  8.249mA    8.003mA    7.689mA
609.4mV   -13.89mA   -13.55mA   -12.62mA
890.6mV   -19.34mA   -18.5mA    -16.85mA
1.172V    -23.07mA   -21.47mA   -19.09mA
1.697V    -26.35mA   -24.09mA   -21.12mA
2.484V    -28.74mA   -26.14mA   -22.82mA
2.583V    -30.97mA   -26.33mA   -22.99mA
2.632V    -29.2mA    -26.43mA   -23.08mA
3V        -29.8mA    -27.11mA   -23.68mA
[Pulldown]
| Voltage   I(typ)   I(min)   I(max)
-1.5V     -18.17mA   -15.4mA    -16.84mA
-1.378V   -19.01mA   -16.46mA   -16.4mA
-1.181V   -19.6mA    -17.77mA   -13.28mA
-1.083V   -18.95mA   -18.04mA   -12.76mA
-984.4mV  -15.56mA   -17.78mA   -12.32mA
-639.8mV  -12.53mA   -13.89mA   -10.58mA
-344.5mV  -8.226mA   -8.742mA   -7.293mA
609.4mV   13.66mA    14.2mA     12.3mA
843.8mV   17.94mA    18.15mA    16.37mA
1.078V    21.04mA    20.25mA    19.71mA
1.5V      22.81mA    21.26mA    22.2mA
3V        24.65mA    22.91mA    24.04mA
[Ramp]
dV/dt_r   0.476308/0.146527n  0.447392/0.156415n  0.468728/0.177438n
dV/dt_f   0.470826/0.133009n  0.45688/0.137142n  0.46748/0.135758n
R_load = 50
[Rising Waveform]
R_fixture = 50
V_fixture = 0
V_fixture_min = 0
V_fixture_max = 0
| Time   V(typ)   V(min)   V(max)
0s        1.665uV    3.019uV    2.534uV
1.019ns   -567.5uV   -423.3uV   -3.944mV
1.306ns   -4.646mV   -543.4uV   655.7mV
1.361ns   54.26mV    -566.4uV   709mV
1.502ns   534.4mV    -625.4uV   761.6mV
1.588ns   698.8mV    -661.3uV   771.6mV
1.747ns   775.7mV    9.356mV    777.9mV
1.975ns   789.8mV    601.8mV    779.8mV
2.228ns   792.4mV    734mV      780.1mV
10ns      793.8mV    745.7mV    781.2mV
[Rising Waveform]
R_fixture = 50
V_fixture = 1.5
V_fixture_min = 1.425
V_fixture_max = 1.575
| Time   V(typ)   V(min)   V(max)
0s        715.3mV    663.5mV    795.9mV
911ps     715.9mV    663.8mV    800.1mV
1.09ns    716mV      663.9mV    1.413V
1.233ns   731.8mV    663.9mV    1.549V
1.351ns   1.197V     664mV      1.566V
1.475ns   1.447V     664mV      1.571V
1.661ns   1.49V      677.2mV    1.573V
1.846ns   1.496V     1.31V      1.574V
2.097ns   1.498V     1.415V     1.574V
10ns      1.5V       1.425V     1.575V
[Falling Waveform]
R_fixture = 50
V_fixture = 0
V_fixture_min = 0
V_fixture_max = 0
| Time   V(typ)   V(min)   V(max)
0s        793.9mV    745.7mV    781.2mV
903ps     793.2mV    745.2mV    771.4mV
1.068ns   793mV      745.1mV    117.2mV
1.246ns   766.2mV    745mV      12.7mV
1.383ns   155.6mV    744.9mV    5.472mV
1.619ns   9.107mV    743.4mV    1.861mV
1.7ns     5.316mV    691mV      1.603mV
1.846ns   2.554mV    108.7mV    1.267mV
2.031ns   1.61mV     10.39mV    882.3uV
10ns      2.92uV     4.781uV    3.699uV
[Falling Waveform]
R_fixture = 50
V_fixture = 1.5
V_fixture_min = 1.425
V_fixture_max = 1.575
| Time   V(typ)   V(min)   V(max)
0s        1.5V       1.425V     1.575V
986ps     1.501V     1.426V     1.574V
1.208ns   1.501V     1.426V     920.3mV
1.323ns   1.478V     1.426V     825.4mV
1.418ns   1.19V      1.426V     808.2mV
1.608ns   756.4mV    1.426V     799.9mV
1.779ns   724mV      1.363V     798.4mV
1.979ns   718.3mV    759.7mV    797.8mV
2.181ns   717.3mV    674.4mV    797.3mV
10ns      715.3mV    663.5mV    795.9mV
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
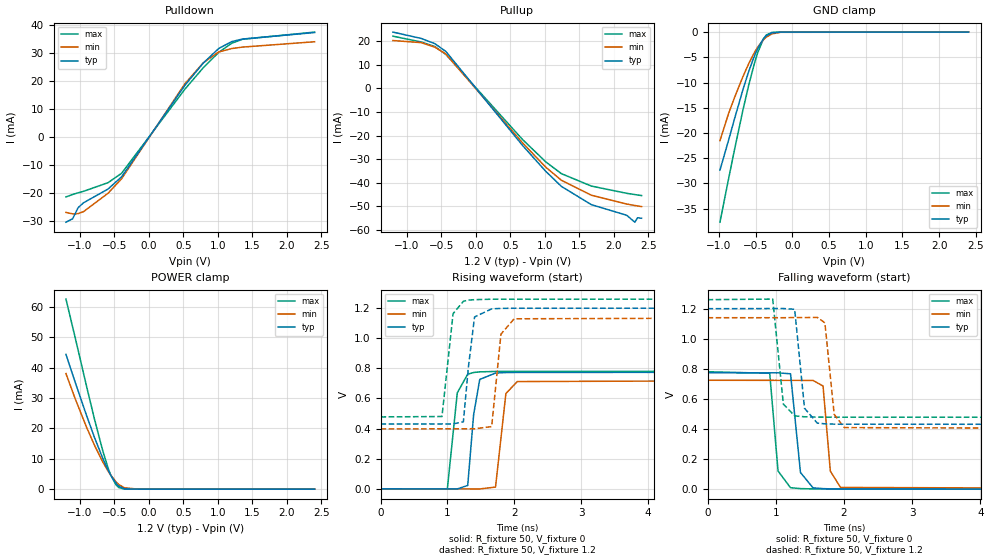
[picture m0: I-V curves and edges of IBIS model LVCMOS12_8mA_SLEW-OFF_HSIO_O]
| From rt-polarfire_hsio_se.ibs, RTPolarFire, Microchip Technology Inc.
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|   Model LVCMOS12_8mA_SLEW-OFF_HSIO_O
[Model]   LVCMOS12_8mA_SLEW-OFF_HSIO_O
Model_type   Output
Polarity   Non-Inverting
Enable   Active-High
Vmeas =   0.6
Cref =   5p
Rref =   1M
|   typ   min   max
C_comp_pullup   1.335e-12   1.335e-12   1.380e-12
C_comp_pulldown  1.335e-12   1.335e-12   1.380e-12
[Temperature Range]  25C   125C   -55C
[Voltage Range]  1.2   1.14   1.26
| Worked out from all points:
|   slope of the pulldown table from 0 to 0.18 V, typ, clamps not added: 27.1 ohm
|   slope of the pullup table from 0 to 0.18 V, typ, clamps not added: 27.2 ohm
|   GND clamp passes 1 mA (typ) near -0.37 V on its own axis
|   POWER clamp passes 1 mA (typ) near -0.44 V on its own axis
|   rising waveform, R_fixture 50, V_fixture 0: 20-80 % time 82.1ps typ, 88.1ps min, 92.1ps max; typ from 0 V to 0.774 V
|   rising waveform, R_fixture 50, V_fixture 1.2: 20-80 % time 79.7ps typ, 81.2ps min, 92ps max; typ from 0.43 V to 1.2 V
|   falling waveform, R_fixture 50, V_fixture 0: 20-80 % time 72ps typ, 71.1ps min, 70.6ps max; typ from 0.774 V to 0 V
|   falling waveform, R_fixture 50, V_fixture 1.2: 20-80 % time 83ps typ, 83.9ps min, 78.9ps max; typ from 1.2 V to 0.43 V
[GND Clamp]
| Voltage   I(typ)   I(min)   I(max)
-984.4mV  -27.36mA   -21.51mA   -37.68mA
-866.2mV  -21.39mA   -16.1mA    -29.03mA
-787.5mV  -17.26mA   -13.03mA   -23.38mA
-669.4mV  -11.29mA   -8.751mA   -15.31mA
-590.6mV  -7.694mA   -6.183mA   -10.37mA
-511.9mV  -4.598mA   -3.964mA   -6.023mA
-472.5mV  -3.303mA   -3.022mA   -4.164mA
-393.7mV  -1.354mA   -1.536mA   -1.373mA
-354.4mV  -738.1uA   -1.006mA   -579.2uA
-275.6mV  -148.2uA   -350.2uA   -51.36uA
-157.5mV  -6.952uA   -42.62uA   -774.1nA
2.4V      0A         0A         0A
[POWER Clamp]
| Voltage   I(typ)   I(min)   I(max)
-1.2V     44.33mA    38.01mA    62.52mA
-1.063V   34.96mA    29.56mA    49.5mA
-905.6mV  24.47mA    20.57mA    34.21mA
-787.5mV  17.03mA    14.47mA    23.07mA
-669.4mV  10.26mA    9.06mA     12.82mA
-590.6mV  6.299mA    5.966mA    6.995mA
-551.3mV  4.569mA    4.604mA    4.604mA
-472.5mV  1.839mA    2.331mA    1.325mA
-433.1mV  941.2uA    1.473mA    512.6uA
-354.4mV  127.4uA    466.4uA    28.07uA
-157.5mV  613.8nA    9.044uA    471.7nA
2.4V      0A         0A         0A
[Pullup]
| Voltage   I(typ)   I(min)   I(max)
-1.2V     23.79mA    20.22mA    22.06mA
-787.5mV  21.07mA    19.32mA    19.58mA
-590.6mV  18.85mA    17.36mA    17.65mA
-433.1mV  15.57mA    14.5mA     14.29mA
675mV     -24.15mA   -23.08mA   -21.65mA
1.012V    -35.15mA   -33.38mA   -31.15mA
1.239V    -41.55mA   -38.95mA   -36.15mA
1.673V    -49.28mA   -45.28mA   -41.4mA
2.184V    -53.76mA   -49.01mA   -44.47mA
2.303V    -56.7mA    -49.63mA   -45.01mA
2.342V    -54.83mA   -49.83mA   -45.18mA
2.4V      -55.03mA   -50.11mA   -45.43mA
[Pulldown]
| Voltage   I(typ)   I(min)   I(max)
-1.2V     -30.46mA   -26.97mA   -21.45mA
-1.103V   -29.23mA   -27.49mA   -20.56mA
-1.024V   -25.27mA   -27.4mA    -19.98mA
-945mV    -23.52mA   -26.68mA   -19.43mA
-590.6mV  -18.62mA   -20.13mA   -16.35mA
-393.7mV  -14.25mA   -14.94mA   -12.98mA
525mV     18.52mA    19.06mA    17.12mA
787.5mV   26.35mA    26.44mA    24.68mA
1.012V    31.57mA    30.33mA    30.18mA
1.2V      34.04mA    31.55mA    33.45mA
1.357V    34.95mA    32.07mA    34.86mA
2.4V      37.27mA    33.98mA    37.43mA
[Ramp]
dV/dt_r   0.464353/82.0884p  0.434435/88.0602p  0.468448/92.1205p
dV/dt_f   0.461868/83.0501p  0.445155/83.8688p  0.469595/78.8901p
R_load = 50
[Rising Waveform]
R_fixture = 50
V_fixture = 0
V_fixture_min = 0
V_fixture_max = 0
| Time   V(typ)   V(min)   V(max)
0s        1.22uV     2.136uV    1.693uV
999ps     -596.8uV   -608.2uV   -2.395mV
1.148ns   -685.9uV   -699.2uV   637.6mV
1.304ns   22.36mV    -794.5uV   761mV
1.392ns   490.6mV    -848.3uV   772.3mV
1.484ns   726.5mV    -904.5uV   776.6mV
1.72ns    768.6mV    11.49mV    779.4mV
1.875ns   772mV      632.8mV    779.7mV
2.045ns   772.9mV    712.2mV    780mV
10ns      773.9mV    724.1mV    780.7mV
[Rising Waveform]
R_fixture = 50
V_fixture = 1.2
V_fixture_min = 1.14
V_fixture_max = 1.26
| Time   V(typ)   V(min)   V(max)
0s        430.2mV    398mV      477.3mV
919ps     430.7mV    398.3mV    480.1mV
1.085ns   430.8mV    398.3mV    1.163V
1.239ns   445mV      398.3mV    1.245V
1.315ns   811.6mV    398.4mV    1.253V
1.406ns   1.141V     398.4mV    1.256V
1.662ns   1.195V     413.2mV    1.259V
1.801ns   1.198V     1.027V     1.259V
1.998ns   1.199V     1.129V     1.259V
10ns      1.2V       1.14V      1.26V
[Falling Waveform]
R_fixture = 50
V_fixture = 0
V_fixture_min = 0
V_fixture_max = 0
| Time   V(typ)   V(min)   V(max)
0s        773.9mV    724.1mV    780.7mV
912ps     773.5mV    723.6mV    770.6mV
1.034ns   773.4mV    723.5mV    120.6mV
1.217ns   767.2mV    723.4mV    9.583mV
1.363ns   110.6mV    723.3mV    3.732mV
1.547ns   8.856mV    723.2mV    1.762mV
1.694ns   3.51mV     685.6mV    1.096mV
1.801ns   2.105mV    119.9mV    1.007mV
1.95ns    1.196mV    11.38mV    883.4uV
10ns      1.896uV    3.757uV    2.216uV
[Falling Waveform]
R_fixture = 50
V_fixture = 1.2
V_fixture_min = 1.14
V_fixture_max = 1.26
| Time   V(typ)   V(min)   V(max)
0s        1.2V       1.14V      1.26V
956ps     1.201V     1.14V      1.264V
1.112ns   1.201V     1.14V      565.5mV
1.278ns   1.196V     1.141V     487.1mV
1.422ns   538.1mV    1.141V     481.2mV
1.61ns    439.1mV    1.142V     479.2mV
1.721ns   434.4mV    1.106V     479mV
1.857ns   432.4mV    498mV      478.7mV
2.005ns   431.9mV    409.4mV    478.5mV
10ns      430.2mV    398mV      477.3mV
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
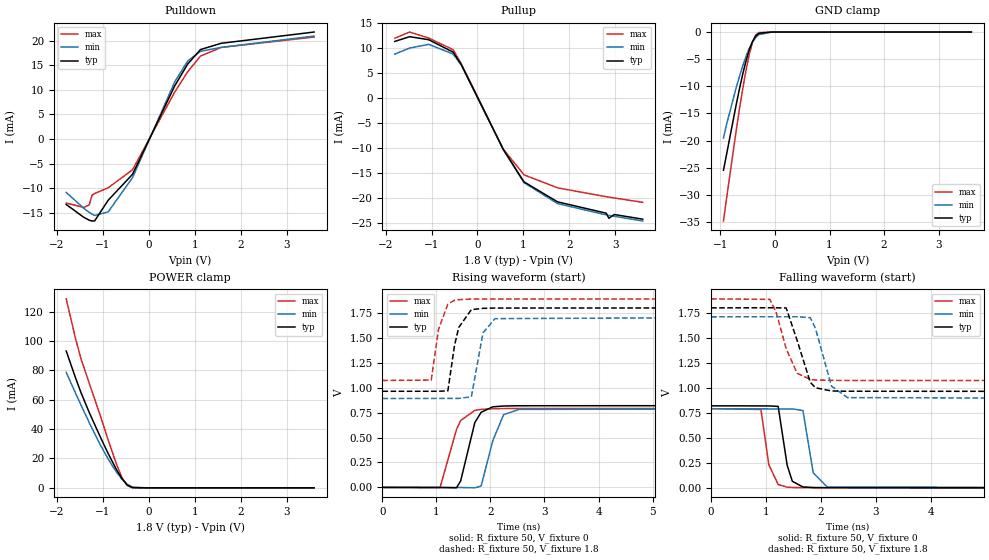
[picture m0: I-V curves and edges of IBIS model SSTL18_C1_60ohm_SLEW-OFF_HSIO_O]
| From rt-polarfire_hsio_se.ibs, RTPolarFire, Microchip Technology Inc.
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|   Model SSTL18_C1_60ohm_SLEW-OFF_HSIO_O
[Model]   SSTL18_C1_60ohm_SLEW-OFF_HSIO_O
Model_type   Output
Polarity   Non-Inverting
Enable   Active-High
Vmeas =   0.9
Cref =   5p
Rref =   50
Vref =   0.9
|   typ   min   max
C_comp_pullup   1.335e-12   1.335e-12   1.380e-12
C_comp_pulldown  1.335e-12   1.335e-12   1.380e-12
[Temperature Range]  25C   125C   -55C
[Voltage Range]  1.8   1.71   1.89
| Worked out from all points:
|   slope of the pulldown table from 0 to 0.27 V, typ, clamps not added: 50 ohm
|   slope of the pullup table from 0 to 0.27 V, typ, clamps not added: 53.2 ohm
|   GND clamp passes 1 mA (typ) near -0.37 V on its own axis
|   POWER clamp passes 1 mA (typ) near -0.43 V on its own axis
|   rising waveform, R_fixture 50, V_fixture 0: 20-80 % time 221ps typ, 224ps min, 232ps max; typ from 0 V to 0.82 V
|   rising waveform, R_fixture 50, V_fixture 1.8: 20-80 % time 161ps typ, 163ps min, 156ps max; typ from 0.964 V to 1.8 V
|   falling waveform, R_fixture 50, V_fixture 0: 20-80 % time 132ps typ, 133ps min, 132ps max; typ from 0.82 V to 0 V
|   falling waveform, R_fixture 50, V_fixture 1.8: 20-80 % time 237ps typ, 242ps min, 269ps max; typ from 1.8 V to 0.964 V
[GND Clamp]
| Voltage   I(typ)   I(min)   I(max)
-945mV    -25.47mA   -19.54mA   -34.82mA
-885.9mV  -22.44mA   -16.92mA   -30.49mA
-708.7mV  -13.24mA   -10.14mA   -17.96mA
-649.7mV  -10.37mA   -8.095mA   -14.06mA
-590.6mV  -7.705mA   -6.193mA   -10.39mA
-531.6mV  -5.322mA   -4.488mA   -7.054mA
-472.5mV  -3.308mA   -3.028mA   -4.171mA
-413.4mV  -1.757mA   -1.859mA   -1.935mA
-354.4mV  -739.5uA   -1.008mA   -580.7uA
-295.3mV  -232.3uA   -469.6uA   -100.4uA
-59.06mV  -489.8nA   -5.037uA   -176.4nA
3.6V      0A         0A         0A
[POWER Clamp]
| Voltage   I(typ)   I(min)   I(max)
-1.8V     93.11mA    78.62mA    128.6mA
-1.595V   74.64mA    64.3mA     101.3mA
-1.477V   64.73mA    56.26mA    87.68mA
-1.299V   51.32mA    44.43mA    71.22mA
-1.063V   35.01mA    29.59mA    49.65mA
-885.9mV  23.32mA    19.56mA    32.61mA
-708.7mV  12.62mA    10.87mA    16.4mA
-590.6mV  6.476mA    6.104mA    7.295mA
-472.5mV  1.932mA    2.452mA    1.539mA
-354.4mV  154uA      480.4uA    74.19uA
-59.06mV  800.7nA    2.877uA    466.9nA
3.6V      0A         0A         0A
[Pullup]
| Voltage   I(typ)   I(min)   I(max)
-1.8V     11.37mA    8.836mA    12.01mA
-1.477V   12.32mA    10.04mA    13.25mA
-1.063V   11.71mA    10.78mA    12.04mA
-531.6mV  9.235mA    8.86mA     9.725mA
-354.4mV  6.764mA    6.653mA    6.919mA
562.5mV   -10.27mA   -10.29mA   -10.22mA
1.012V    -16.76mA   -16.91mA   -15.35mA
1.744V    -20.77mA   -21.12mA   -17.96mA
2.804V    -23.04mA   -23.39mA   -19.74mA
2.863V    -24.06mA   -23.48mA   -19.82mA
2.981V    -23.31mA   -23.66mA   -19.99mA
3.6V      -24.24mA   -24.61mA   -20.87mA
[Pulldown]
| Voltage   I(typ)   I(min)   I(max)
-1.8V     -13.3mA    -10.85mA   -13.02mA
-1.417V   -15.91mA   -14.09mA   -13.9mA
-1.299V   -16.49mA   -14.91mA   -13.38mA
-1.24V    -16.66mA   -15.25mA   -11.45mA
-1.181V   -16.64mA   -15.53mA   -11.07mA
-885.9mV  -12.44mA   -14.8mA    -9.908mA
-354.4mV  -7.151mA   -7.834mA   -6.231mA
562.5mV   10.79mA    11.6mA     9.529mA
843.8mV   15.22mA    15.85mA    13.65mA
1.125V    18.19mA    17.83mA    16.86mA
1.575V    19.46mA    18.63mA    18.62mA
3.6V      21.75mA    20.93mA    20.73mA
[Ramp]
dV/dt_r   0.492097/0.221385n  0.474078/0.224193n  0.475197/0.232186n
dV/dt_f   0.501817/0.237243n  0.491177/0.242423n  0.490889/0.269n
R_load = 50
[Rising Waveform]
R_fixture = 50
V_fixture = 0
V_fixture_min = 0
V_fixture_max = 0
| Time   V(typ)   V(min)   V(max)
0s        2.644uV    4.433uV    4.313uV
1.066ns   -830.6uV   -614.3uV   -1.669mV
1.371ns   -4.033mV   -791.3uV   580.6mV
1.448ns   65.67mV    -836uV     670.5mV
1.71ns    649.9mV    -4.389mV   772.3mV
1.827ns   753mV      13.94mV    781.9mV
2.042ns   807.9mV    467.2mV    789.1mV
2.242ns   815.8mV    728.4mV    790.3mV
2.524ns   818.6mV    782mV      790.8mV
10ns      820.2mV    790.1mV    792mV
[Rising Waveform]
R_fixture = 50
V_fixture = 1.8
V_fixture_min = 1.71
V_fixture_max = 1.89
| Time   V(typ)   V(min)   V(max)
0s        963.6mV    891.3mV    1.072V
903ps     963.8mV    891.8mV    1.076V
1.038ns   963.8mV    891.9mV    1.585V
1.211ns   967.8mV    892mV      1.838V
1.333ns   1.42V      892mV      1.875V
1.412ns   1.603V     892.1mV    1.882V
1.646ns   1.782V     908.1mV    1.888V
1.861ns   1.795V     1.549V     1.888V
2.084ns   1.798V     1.692V     1.889V
10ns      1.8V       1.71V      1.89V
[Falling Waveform]
R_fixture = 50
V_fixture = 0
V_fixture_min = 0
V_fixture_max = 0
| Time   V(typ)   V(min)   V(max)
0s        820.2mV    790.2mV    792mV
909ps     819.5mV    789.8mV    783.8mV
1.053ns   819.4mV    789.7mV    230.8mV
1.223ns   814.4mV    789.7mV    33.65mV
1.387ns   225.8mV    789.6mV    6.746mV
1.481ns   65.48mV    789.6mV    3.996mV
1.674ns   9.13mV     773.2mV    2.028mV
1.862ns   3.498mV    150.9mV    1.361mV
2.116ns   1.643mV    8.988mV    881.8uV
10ns      3.992uV    6.295uV    5.503uV
[Falling Waveform]
R_fixture = 50
V_fixture = 1.8
V_fixture_min = 1.71
V_fixture_max = 1.89
| Time   V(typ)   V(min)   V(max)
0s        1.8V       1.71V      1.89V
1.071ns   1.801V     1.711V     1.885V
1.184ns   1.801V     1.711V     1.761V
1.369ns   1.799V     1.711V     1.391V
1.568ns   1.475V     1.711V     1.146V
1.808ns   1.056V     1.702V     1.085V
1.902ns   1.001V     1.596V     1.079V
2.195ns   969mV      1.018V     1.075V
2.485ns   966.1mV    902.4mV    1.074V
10ns      963.6mV    891.3mV    1.072V
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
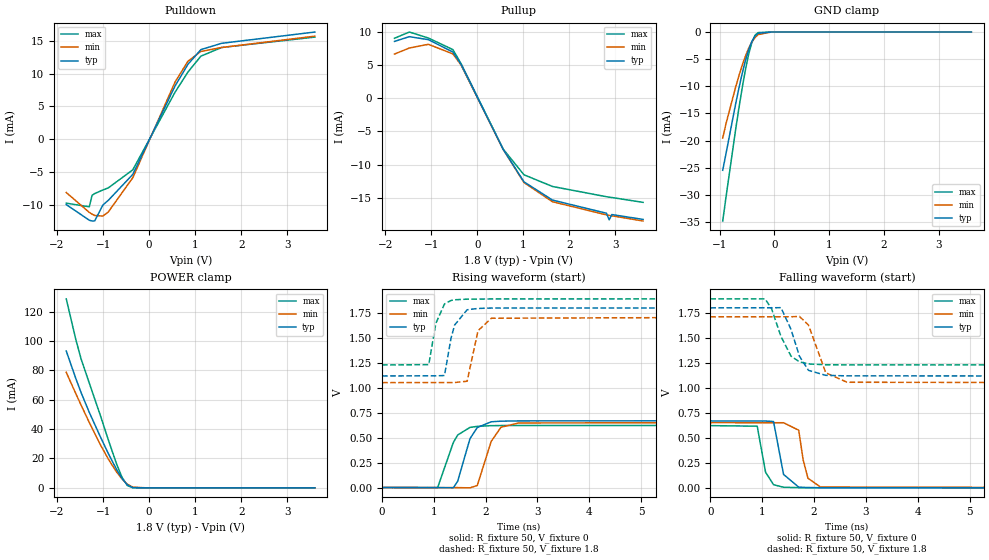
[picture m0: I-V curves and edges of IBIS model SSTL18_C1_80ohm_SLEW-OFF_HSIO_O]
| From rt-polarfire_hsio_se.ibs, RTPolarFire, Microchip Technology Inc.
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|   Model SSTL18_C1_80ohm_SLEW-OFF_HSIO_O
[Model]   SSTL18_C1_80ohm_SLEW-OFF_HSIO_O
Model_type   Output
Polarity   Non-Inverting
Enable   Active-High
Vmeas =   0.9
Cref =   5p
Rref =   50
Vref =   0.9
|   typ   min   max
C_comp_pullup   1.335e-12   1.335e-12   1.380e-12
C_comp_pulldown  1.335e-12   1.335e-12   1.380e-12
[Temperature Range]  25C   125C   -55C
[Voltage Range]  1.8   1.71   1.89
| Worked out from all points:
|   slope of the pulldown table from 0 to 0.27 V, typ, clamps not added: 66.5 ohm
|   slope of the pullup table from 0 to 0.27 V, typ, clamps not added: 70.9 ohm
|   GND clamp passes 1 mA (typ) near -0.37 V on its own axis
|   POWER clamp passes 1 mA (typ) near -0.43 V on its own axis
|   rising waveform, R_fixture 50, V_fixture 0: 20-80 % time 244ps typ, 250ps min, 241ps max; typ from 0 V to 0.669 V
|   rising waveform, R_fixture 50, V_fixture 1.8: 20-80 % time 162ps typ, 165ps min, 158ps max; typ from 1.12 V to 1.8 V
|   falling waveform, R_fixture 50, V_fixture 0: 20-80 % time 136ps typ, 139ps min, 133ps max; typ from 0.669 V to 0 V
|   falling waveform, R_fixture 50, V_fixture 1.8: 20-80 % time 269ps typ, 266ps min, 299ps max; typ from 1.8 V to 1.12 V
[GND Clamp]
| Voltage   I(typ)   I(min)   I(max)
-945mV    -25.47mA   -19.54mA   -34.82mA
-885.9mV  -22.44mA   -16.92mA   -30.49mA
-708.7mV  -13.24mA   -10.14mA   -17.96mA
-649.7mV  -10.37mA   -8.095mA   -14.06mA
-590.6mV  -7.705mA   -6.193mA   -10.39mA
-531.6mV  -5.322mA   -4.488mA   -7.054mA
-472.5mV  -3.308mA   -3.028mA   -4.171mA
-413.4mV  -1.757mA   -1.859mA   -1.935mA
-354.4mV  -739.5uA   -1.008mA   -580.7uA
-295.3mV  -232.3uA   -469.6uA   -100.4uA
-59.06mV  -489.8nA   -5.037uA   -176.4nA
3.6V      0A         0A         0A
[POWER Clamp]
| Voltage   I(typ)   I(min)   I(max)
-1.8V     93.11mA    78.62mA    128.6mA
-1.595V   74.64mA    64.3mA     101.3mA
-1.477V   64.73mA    56.26mA    87.68mA
-1.299V   51.32mA    44.43mA    71.22mA
-1.063V   35.01mA    29.59mA    49.65mA
-885.9mV  23.32mA    19.56mA    32.61mA
-708.7mV  12.62mA    10.87mA    16.4mA
-590.6mV  6.476mA    6.104mA    7.295mA
-472.5mV  1.932mA    2.452mA    1.539mA
-354.4mV  154uA      480.4uA    74.19uA
-59.06mV  800.7nA    2.877uA    466.9nA
3.6V      0A         0A         0A
[Pullup]
| Voltage   I(typ)   I(min)   I(max)
-1.8V     8.524mA    6.626mA    9.003mA
-1.477V   9.241mA    7.533mA    9.935mA
-1.063V   8.786mA    8.089mA    9.033mA
-531.6mV  6.927mA    6.646mA    7.296mA
-354.4mV  5.074mA    4.991mA    5.192mA
562.5mV   -7.703mA   -7.718mA   -7.67mA
1.012V    -12.57mA   -12.68mA   -11.51mA
1.631V    -15.31mA   -15.56mA   -13.27mA
2.804V    -17.29mA   -17.54mA   -14.81mA
2.863V    -18.28mA   -17.61mA   -14.87mA
2.922V    -17.49mA   -17.68mA   -14.93mA
3.6V      -18.22mA   -18.46mA   -15.66mA
[Pulldown]
| Voltage   I(typ)   I(min)   I(max)
-1.8V     -9.983mA   -8.14mA    -9.768mA
-1.299V   -12.37mA   -11.18mA   -10.32mA
-1.24V    -12.49mA   -11.44mA   -8.582mA
-1.181V   -12.47mA   -11.65mA   -8.302mA
-1.004V   -10.04mA   -11.73mA   -7.754mA
-885.9mV  -9.33mA    -11.1mA    -7.432mA
-354.4mV  -5.371mA   -5.881mA   -4.677mA
562.5mV   8.107mA    8.705mA    7.155mA
843.8mV   11.43mA    11.9mA     10.25mA
1.125V    13.67mA    13.39mA    12.67mA
1.575V    14.63mA    13.99mA    13.99mA
3.6V      16.35mA    15.72mA    15.58mA
[Ramp]
dV/dt_r   0.401415/0.244279n  0.391143/0.250193n  0.373356/0.241318n
dV/dt_f   0.408955/0.26874n  0.395263/0.265806n  0.3969/0.298837n
R_load = 50
[Rising Waveform]
R_fixture = 50
V_fixture = 0
V_fixture_min = 0
V_fixture_max = 0
| Time   V(typ)   V(min)   V(max)
0s        2.834uV    4.926uV    4.656uV
1.073ns   -839.1uV   -552.8uV   420.8uV
1.377ns   -2.273mV   -710.9uV   452.8mV
1.46ns    63.88mV    -754uV     526.4mV
1.697ns   489.5mV    -2.998mV   602.4mV
1.838ns   601.1mV    21.03mV    612.9mV
2.107ns   658.8mV    462.8mV    620.1mV
2.296ns   665mV      604.5mV    621mV
2.639ns   667.6mV    647mV      621.5mV
10ns      669mV      651.9mV    622.3mV
[Rising Waveform]
R_fixture = 50
V_fixture = 1.8
V_fixture_min = 1.71
V_fixture_max = 1.89
| Time   V(typ)   V(min)   V(max)
0s        1.118V     1.051V     1.228V
901ps     1.119V     1.052V     1.231V
1.038ns   1.119V     1.052V     1.644V
1.205ns   1.122V     1.052V     1.839V
1.331ns   1.496V     1.052V     1.874V
1.401ns   1.628V     1.052V     1.881V
1.642ns   1.781V     1.065V     1.887V
1.852ns   1.794V     1.571V     1.888V
2.11ns    1.798V     1.696V     1.889V
10ns      1.8V       1.71V      1.89V
[Falling Waveform]
R_fixture = 50
V_fixture = 0
V_fixture_min = 0
V_fixture_max = 0
| Time   V(typ)   V(min)   V(max)
0s        669mV      651.9mV    622.3mV
905ps     668.3mV    651.4mV    616.7mV
1.066ns   668.2mV    651.4mV    156.4mV
1.22ns    663.3mV    651.3mV    31.29mV
1.413ns   134.3mV    651.2mV    5.899mV
1.705ns   7.35mV     576.7mV    1.775mV
1.791ns   4.733mV    280.1mV    1.323mV
1.883ns   2.907mV    96.4mV     1.171mV
2.125ns   1.371mV    8.433mV    890.7uV
10ns      4.04uV     5.159uV    5.747uV
[Falling Waveform]
R_fixture = 50
V_fixture = 1.8
V_fixture_min = 1.71
V_fixture_max = 1.89
| Time   V(typ)   V(min)   V(max)
0s        1.8V       1.71V      1.89V
1.057ns   1.801V     1.71V      1.89V
1.183ns   1.801V     1.711V     1.79V
1.363ns   1.802V     1.711V     1.514V
1.556ns   1.586V     1.711V     1.318V
1.72ns    1.316V     1.714V     1.26V
1.894ns   1.175V     1.628V     1.239V
2.227ns   1.125V     1.151V     1.231V
2.637ns   1.12V      1.056V     1.23V
10ns      1.118V     1.051V     1.228V
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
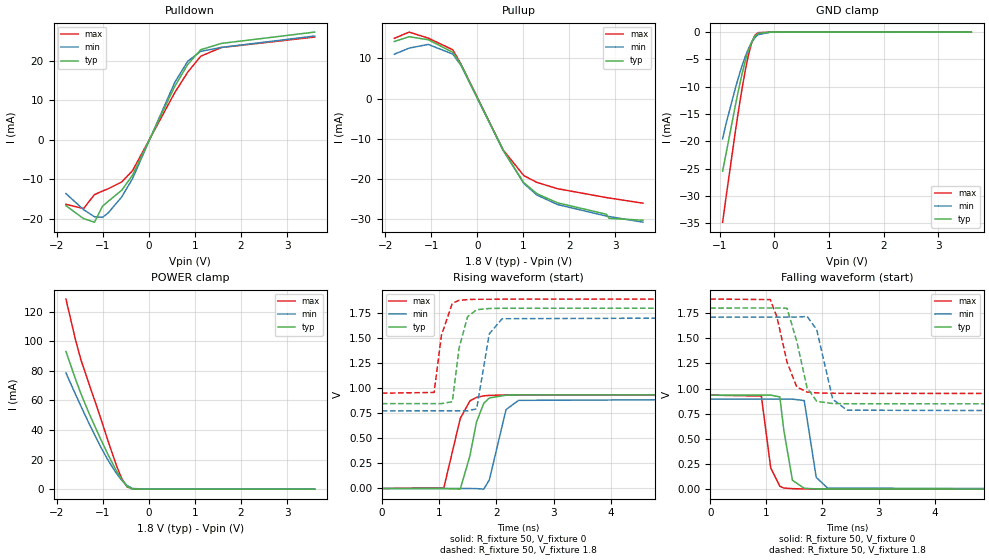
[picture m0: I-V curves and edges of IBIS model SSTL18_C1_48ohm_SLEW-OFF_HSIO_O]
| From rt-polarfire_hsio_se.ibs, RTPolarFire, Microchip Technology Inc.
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|   Model SSTL18_C1_48ohm_SLEW-OFF_HSIO_O
[Model]   SSTL18_C1_48ohm_SLEW-OFF_HSIO_O
Model_type   Output
Polarity   Non-Inverting
Enable   Active-High
Vmeas =   0.9
Cref =   5p
Rref =   50
Vref =   0.9
|   typ   min   max
C_comp_pullup   1.335e-12   1.335e-12   1.380e-12
C_comp_pulldown  1.335e-12   1.335e-12   1.380e-12
[Temperature Range]  25C   125C   -55C
[Voltage Range]  1.8   1.71   1.89
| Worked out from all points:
|   slope of the pulldown table from 0 to 0.27 V, typ, clamps not added: 40 ohm
|   slope of the pullup table from 0 to 0.27 V, typ, clamps not added: 42.5 ohm
|   GND clamp passes 1 mA (typ) near -0.37 V on its own axis
|   POWER clamp passes 1 mA (typ) near -0.43 V on its own axis
|   rising waveform, R_fixture 50, V_fixture 0: 20-80 % time 208ps typ, 208ps min, 222ps max; typ from 0 V to 0.936 V
|   rising waveform, R_fixture 50, V_fixture 1.8: 20-80 % time 159ps typ, 161ps min, 153ps max; typ from 0.847 V to 1.8 V
|   falling waveform, R_fixture 50, V_fixture 0: 20-80 % time 131ps typ, 131ps min, 131ps max; typ from 0.936 V to 0 V
|   falling waveform, R_fixture 50, V_fixture 1.8: 20-80 % time 216ps typ, 221ps min, 239ps max; typ from 1.8 V to 0.847 V
[GND Clamp]
| Voltage   I(typ)   I(min)   I(max)
-945mV    -25.47mA   -19.54mA   -34.82mA
-885.9mV  -22.44mA   -16.92mA   -30.49mA
-708.7mV  -13.24mA   -10.14mA   -17.96mA
-649.7mV  -10.37mA   -8.095mA   -14.06mA
-590.6mV  -7.705mA   -6.193mA   -10.39mA
-531.6mV  -5.322mA   -4.488mA   -7.054mA
-472.5mV  -3.308mA   -3.028mA   -4.171mA
-413.4mV  -1.757mA   -1.859mA   -1.935mA
-354.4mV  -739.5uA   -1.008mA   -580.7uA
-295.3mV  -232.3uA   -469.6uA   -100.4uA
-59.06mV  -489.8nA   -5.037uA   -176.4nA
3.6V      0A         0A         0A
[POWER Clamp]
| Voltage   I(typ)   I(min)   I(max)
-1.8V     93.11mA    78.62mA    128.6mA
-1.595V   74.64mA    64.3mA     101.3mA
-1.477V   64.73mA    56.26mA    87.68mA
-1.299V   51.32mA    44.43mA    71.22mA
-1.063V   35.01mA    29.59mA    49.65mA
-885.9mV  23.32mA    19.56mA    32.61mA
-708.7mV  12.62mA    10.87mA    16.4mA
-590.6mV  6.476mA    6.104mA    7.295mA
-472.5mV  1.932mA    2.452mA    1.539mA
-354.4mV  154uA      480.4uA    74.19uA
-59.06mV  800.7nA    2.877uA    466.9nA
3.6V      0A         0A         0A
[Pullup]
| Voltage   I(typ)   I(min)   I(max)
-1.8V     14.21mA    11.04mA    15mA
-1.477V   15.4mA     12.56mA    16.55mA
-1.063V   14.64mA    13.48mA    15.05mA
-531.6mV  11.54mA    11.08mA    12.16mA
-354.4mV  8.453mA    8.316mA    8.652mA
562.5mV   -12.83mA   -12.86mA   -12.78mA
1.012V    -20.95mA   -21.14mA   -19.19mA
1.294V    -23.67mA   -24mA      -20.87mA
1.744V    -25.97mA   -26.4mA    -22.45mA
2.804V    -28.8mA    -29.26mA   -24.66mA
2.863V    -29.84mA   -29.37mA   -24.76mA
3.6V      -30.3mA    -30.79mA   -26.06mA
[Pulldown]
| Voltage   I(typ)   I(min)   I(max)
-1.8V     -16.63mA   -13.58mA   -16.28mA
-1.417V   -19.89mA   -17.63mA   -17.35mA
-1.181V   -20.79mA   -19.42mA   -13.83mA
-1.004V   -16.72mA   -19.55mA   -12.92mA
-885.9mV  -15.55mA   -18.49mA   -12.38mA
-590.6mV  -12.74mA   -14.43mA   -10.65mA
-354.4mV  -8.939mA   -9.791mA   -7.787mA
562.5mV   13.49mA    14.5mA     11.91mA
843.8mV   19.02mA    19.82mA    17.07mA
1.125V    22.73mA    22.32mA    21.09mA
1.575V    24.33mA    23.32mA    23.3mA
3.6V      27.19mA    26.2mA     25.94mA
[Ramp]
dV/dt_r   0.561322/0.207829n  0.537473/0.207693n  0.560938/0.22177n
dV/dt_f   0.571986/0.216238n  0.561266/0.220725n  0.563382/0.239337n
R_load = 50
[Rising Waveform]
R_fixture = 50
V_fixture = 0
V_fixture_min = 0
V_fixture_max = 0
| Time   V(typ)   V(min)   V(max)
0s        2.497uV    4.055uV    4.043uV
1.082ns   -648.1uV   -316.8uV   6.393mV
1.369ns   -6.137mV   -401.9uV   699mV
1.538ns   327.5mV    -452uV     874.6mV
1.652ns   663.4mV    -1.103mV   908.8mV
1.78ns    850.4mV    -6.803mV   924.6mV
1.877ns   903.2mV    86.78mV    928.8mV
2.168ns   931.1mV    787.5mV    932.9mV
2.388ns   933.5mV    879.4mV    933.5mV
10ns      935.5mV    895.8mV    934.9mV
[Rising Waveform]
R_fixture = 50
V_fixture = 1.8
V_fixture_min = 1.71
V_fixture_max = 1.89
| Time   V(typ)   V(min)   V(max)
0s        846.7mV    774.5mV    951mV
912ps     846.8mV    774.8mV    958.3mV
1.04ns    846.8mV    774.8mV    1.529V
1.23ns    865.8mV    774.9mV    1.848V
1.348ns   1.401V     775mV      1.877V
1.496ns   1.713V     775mV      1.885V
1.655ns   1.784V     794.6mV    1.888V
1.875ns   1.796V     1.542V     1.888V
2.1ns     1.798V     1.694V     1.889V
10ns      1.8V       1.71V      1.89V
[Falling Waveform]
R_fixture = 50
V_fixture = 0
V_fixture_min = 0
V_fixture_max = 0
| Time   V(typ)   V(min)   V(max)
0s        935.6mV    895.8mV    934.9mV
912ps     935.1mV    895.4mV    926mV
1.079ns   935mV      895.3mV    211.2mV
1.241ns   917.1mV    895.2mV    29.06mV
1.312ns   587.4mV    895.2mV    11.24mV
1.466ns   88.26mV    895.1mV    5.107mV
1.676ns   9.205mV    881.1mV    2.127mV
1.89ns    2.492mV    117.2mV    1.379mV
2.093ns   1.643mV    10.33mV    1.05mV
10ns      3.234uV    5.632uV    4.653uV
[Falling Waveform]
R_fixture = 50
V_fixture = 1.8
V_fixture_min = 1.71
V_fixture_max = 1.89
| Time   V(typ)   V(min)   V(max)
0s        1.8V       1.71V      1.89V
1.07ns    1.801V     1.711V     1.885V
1.189ns   1.801V     1.711V     1.714V
1.369ns   1.799V     1.711V     1.264V
1.544ns   1.469V     1.711V     1.015V
1.728ns   1.006V     1.717V     966mV
1.899ns   873.4mV    1.586V     957.2mV
2.184ns   851.2mV    894mV      953.7mV
2.438ns   849.2mV    785.2mV    952.5mV
10ns      846.7mV    774.5mV    951mV
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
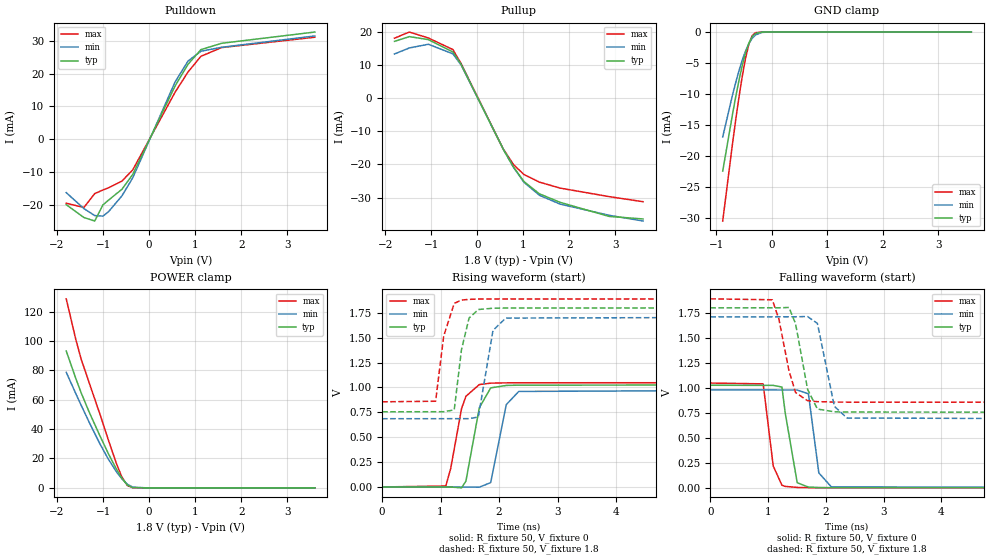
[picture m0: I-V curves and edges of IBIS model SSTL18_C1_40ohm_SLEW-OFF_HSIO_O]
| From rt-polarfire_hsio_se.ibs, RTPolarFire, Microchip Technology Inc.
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|   Model SSTL18_C1_40ohm_SLEW-OFF_HSIO_O
[Model]   SSTL18_C1_40ohm_SLEW-OFF_HSIO_O
Model_type   Output
Polarity   Non-Inverting
Enable   Active-High
Vmeas =   0.9
Cref =   5p
Rref =   50
Vref =   0.9
|   typ   min   max
C_comp_pullup   1.335e-12   1.335e-12   1.380e-12
C_comp_pulldown  1.335e-12   1.335e-12   1.380e-12
[Temperature Range]  25C   125C   -55C
[Voltage Range]  1.8   1.71   1.89
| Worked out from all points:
|   slope of the pulldown table from 0 to 0.27 V, typ, clamps not added: 33.3 ohm
|   slope of the pullup table from 0 to 0.27 V, typ, clamps not added: 35.4 ohm
|   GND clamp passes 1 mA (typ) near -0.37 V on its own axis
|   POWER clamp passes 1 mA (typ) near -0.43 V on its own axis
|   rising waveform, R_fixture 50, V_fixture 0: 20-80 % time 187ps typ, 186ps min, 208ps max; typ from 0 V to 1.03 V
|   rising waveform, R_fixture 50, V_fixture 1.8: 20-80 % time 156ps typ, 165ps min, 152ps max; typ from 0.755 V to 1.8 V
|   falling waveform, R_fixture 50, V_fixture 0: 20-80 % time 131ps typ, 126ps min, 129ps max; typ from 1.03 V to 0 V
|   falling waveform, R_fixture 50, V_fixture 1.8: 20-80 % time 198ps typ, 193ps min, 218ps max; typ from 1.8 V to 0.755 V
[GND Clamp]
| Voltage   I(typ)   I(min)   I(max)
-885.9mV  -22.44mA   -16.92mA   -30.49mA
-708.7mV  -13.24mA   -10.14mA   -17.96mA
-649.7mV  -10.37mA   -8.095mA   -14.06mA
-590.6mV  -7.705mA   -6.193mA   -10.39mA
-531.6mV  -5.322mA   -4.488mA   -7.054mA
-472.5mV  -3.308mA   -3.028mA   -4.171mA
-413.4mV  -1.757mA   -1.859mA   -1.935mA
-354.4mV  -739.5uA   -1.008mA   -580.7uA
-295.3mV  -232.3uA   -469.6uA   -100.4uA
-177.2mV  -12.01uA   -62.89uA   -1.688uA
-59.06mV  -489.8nA   -5.037uA   -176.4nA
3.6V      0A         0A         0A
[POWER Clamp]
| Voltage   I(typ)   I(min)   I(max)
-1.8V     93.11mA    78.62mA    128.6mA
-1.595V   74.64mA    64.3mA     101.3mA
-1.477V   64.73mA    56.26mA    87.68mA
-1.299V   51.32mA    44.43mA    71.22mA
-1.063V   35.01mA    29.59mA    49.65mA
-885.9mV  23.32mA    19.56mA    32.61mA
-708.7mV  12.62mA    10.87mA    16.4mA
-590.6mV  6.476mA    6.104mA    7.295mA
-472.5mV  1.932mA    2.452mA    1.539mA
-354.4mV  154uA      480.4uA    74.19uA
-59.06mV  800.7nA    2.877uA    466.9nA
3.6V      0A         0A         0A
[Pullup]
| Voltage   I(typ)   I(min)   I(max)
-1.8V     17.05mA    13.25mA    18.01mA
-1.477V   18.48mA    15.07mA    19.86mA
-1.063V   17.57mA    16.18mA    18.06mA
-531.6mV  13.85mA    13.29mA    14.59mA
-354.4mV  10.14mA    9.979mA    10.38mA
562.5mV   -15.4mA    -15.43mA   -15.33mA
787.5mV   -20.82mA   -20.9mA    -20.08mA
1.012V    -25.14mA   -25.36mA   -23.02mA
1.35V     -28.85mA   -29.28mA   -25.33mA
1.8V      -31.41mA   -31.94mA   -27.12mA
2.863V    -35.64mA   -35.3mA    -29.68mA
3.6V      -36.4mA    -37.02mA   -31.21mA
[Pulldown]
| Voltage   I(typ)   I(min)   I(max)
-1.8V     -19.98mA   -16.31mA   -19.53mA
-1.417V   -23.89mA   -21.17mA   -20.83mA
-1.181V   -24.96mA   -23.31mA   -16.6mA
-1.004V   -20.05mA   -23.46mA   -15.5mA
-885.9mV  -18.64mA   -22.18mA   -14.85mA
-590.6mV  -15.28mA   -17.3mA    -12.78mA
-354.4mV  -10.72mA   -11.75mA   -9.335mA
562.5mV   16.17mA    17.4mA     14.28mA
843.8mV   22.82mA    23.8mA     20.46mA
1.125V    27.3mA     26.81mA    25.27mA
1.575V    29.24mA    28.02mA    27.93mA
3.6V      32.67mA    31.47mA    31.09mA
[Ramp]
dV/dt_r   0.61537/0.186847n  0.58758/0.186377n  0.628961/0.208232n
dV/dt_f   0.62673/0.197632n  0.614627/0.193232n  0.620624/0.217863n
R_load = 50
[Rising Waveform]
R_fixture = 50
V_fixture = 0
V_fixture_min = 0
V_fixture_max = 0
| Time   V(typ)   V(min)   V(max)
0s        2.38uV     3.756uV    3.825uV
1.089ns   -738.7uV   -564.1uV   9.38mV
1.173ns   -795.8uV   -607.9uV   186.4mV
1.358ns   -8.972mV   -704.4uV   787.2mV
1.433ns   58.73mV    -743.5uV   911.2mV
1.662ns   796.6mV    -2.329mV   1.029V
1.856ns   995.5mV    43.7mV     1.043V
2.122ns   1.02V      827.1mV    1.046V
2.336ns   1.023V     959.9mV    1.047V
10ns      1.026V     979.3mV    1.048V
[Rising Waveform]
R_fixture = 50
V_fixture = 1.8
V_fixture_min = 1.71
V_fixture_max = 1.89
| Time   V(typ)   V(min)   V(max)
0s        755.4mV    685.6mV    855.6mV
915ps     756.1mV    686mV      861.3mV
1.053ns   756.2mV    686.1mV    1.515V
1.233ns   774.1mV    686.2mV    1.845V
1.357ns   1.38V      686.3mV    1.878V
1.486ns   1.696V     686.3mV    1.885V
1.645ns   1.783V     702.9mV    1.888V
1.895ns   1.796V     1.573V     1.889V
2.114ns   1.798V     1.697V     1.889V
10ns      1.8V       1.71V      1.89V
[Falling Waveform]
R_fixture = 50
V_fixture = 0
V_fixture_min = 0
V_fixture_max = 0
| Time   V(typ)   V(min)   V(max)
0s        1.026V     979.4mV    1.048V
915ps     1.025V     978.8mV    1.04V
1.089ns   1.025V     978.7mV    218.5mV
1.24ns    1.008V     978.6mV    26.19mV
1.296ns   751.5mV    978.6mV    14.61mV
1.504ns   51.33mV    978.4mV    4.109mV
1.698ns   7.516mV    940.6mV    2.006mV
1.878ns   2.937mV    149.8mV    1.522mV
2.094ns   1.582mV    9.782mV    980.1uV
10ns      3.459uV    5.154uV    4.27uV
[Falling Waveform]
R_fixture = 50
V_fixture = 1.8
V_fixture_min = 1.71
V_fixture_max = 1.89
| Time   V(typ)   V(min)   V(max)
0s        1.8V       1.71V      1.89V
1.073ns   1.801V     1.71V      1.881V
1.187ns   1.801V     1.711V     1.688V
1.362ns   1.804V     1.711V     1.169V
1.476ns   1.641V     1.711V     953.5mV
1.684ns   984.1mV    1.713V     871.3mV
1.854ns   788.2mV    1.644V     862mV
2.147ns   760.2mV    815.3mV    858.1mV
2.366ns   758mV      698.2mV    857.1mV
10ns      755.4mV    685.6mV    855.6mV
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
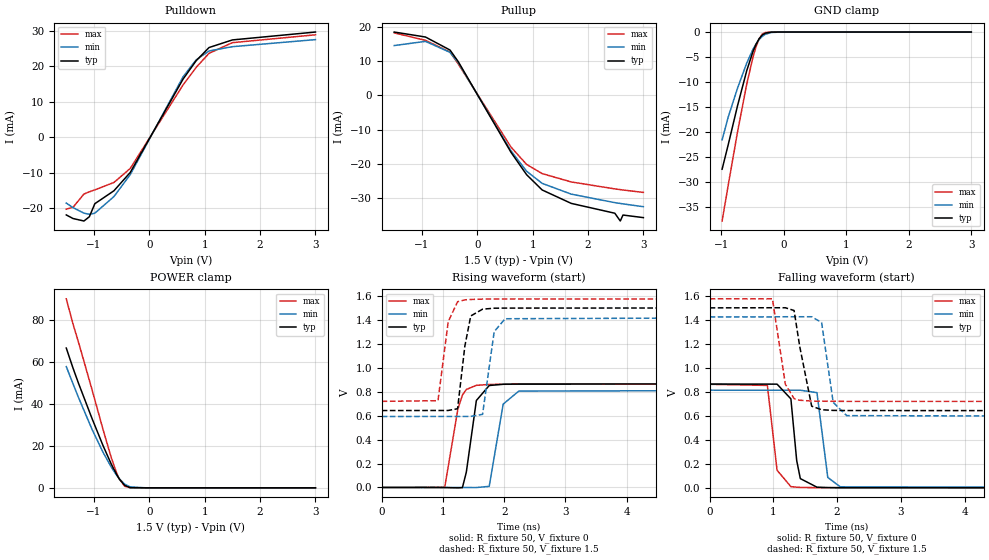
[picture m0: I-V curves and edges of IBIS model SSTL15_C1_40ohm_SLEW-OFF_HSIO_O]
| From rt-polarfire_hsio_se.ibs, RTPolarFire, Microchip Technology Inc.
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|   Model SSTL15_C1_40ohm_SLEW-OFF_HSIO_O
[Model]   SSTL15_C1_40ohm_SLEW-OFF_HSIO_O
Model_type   Output
Polarity   Non-Inverting
Enable   Active-High
Vmeas =   0.75
Cref =   5p
Rref =   50
Vref =   0.75
|   typ   min   max
C_comp_pullup   1.335e-12   1.335e-12   1.380e-12
C_comp_pulldown  1.335e-12   1.335e-12   1.380e-12
[Temperature Range]  25C   125C   -55C
[Voltage Range]  1.5   1.425   1.575
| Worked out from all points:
|   slope of the pulldown table from 0 to 0.225 V, typ, clamps not added: 35.2 ohm
|   slope of the pullup table from 0 to 0.225 V, typ, clamps not added: 35.2 ohm
|   GND clamp passes 1 mA (typ) near -0.37 V on its own axis
|   POWER clamp passes 1 mA (typ) near -0.43 V on its own axis
|   rising waveform, R_fixture 50, V_fixture 0: 20-80 % time 136ps typ, 145ps min, 162ps max; typ from 0 V to 0.865 V
|   rising waveform, R_fixture 50, V_fixture 1.5: 20-80 % time 113ps typ, 123ps min, 123ps max; typ from 0.642 V to 1.5 V
|   falling waveform, R_fixture 50, V_fixture 0: 20-80 % time 96ps typ, 88.5ps min, 94.7ps max; typ from 0.865 V to 0 V
|   falling waveform, R_fixture 50, V_fixture 1.5: 20-80 % time 123ps typ, 123ps min, 123ps max; typ from 1.5 V to 0.642 V
[GND Clamp]
| Voltage   I(typ)   I(min)   I(max)
-984.4mV  -27.37mA   -21.52mA   -37.7mA
-885.9mV  -22.43mA   -16.92mA   -30.48mA
-738.3mV  -14.72mA   -11.21mA   -19.96mA
-590.6mV  -7.7mA     -6.188mA   -10.38mA
-492.2mV  -3.93mA    -3.481mA   -5.066mA
-443mV    -2.467mA   -2.402mA   -2.955mA
-393.7mV  -1.355mA   -1.538mA   -1.375mA
-344.5mV  -621.9uA   -897uA     -448.3uA
-295.3mV  -232uA     -469.2uA   -100.1uA
-196.9mV  -20.29uA   -91.32uA   -3.19uA
-49.22mV  -334.5nA   -3.793uA   -95.68nA
3V        0A         0A         0A
[POWER Clamp]
| Voltage   I(typ)   I(min)   I(max)
-1.5V     66.64mA    57.8mA     90.1mA
-1.378V   57.06mA    49.6mA     78.07mA
-1.28V    49.9mA     43.13mA    69.49mA
-1.034V   32.99mA    27.83mA    46.7mA
-836.7mV  20.16mA    16.97mA    27.85mA
-689.1mV  11.42mA    9.956mA    14.55mA
-590.6mV  6.331mA    6.012mA    7.055mA
-541.4mV  4.184mA    4.318mA    4.125mA
-443mV    1.134mA    1.688mA    703.5uA
-344.5mV  93.53uA    432.5uA    21.45uA
-49.22mV  620.3nA    2.506uA    250nA
3V        0A         0A         0A
[Pullup]
| Voltage   I(typ)   I(min)   I(max)
-1.5V     18.54mA    14.58mA    18.29mA
-935.2mV  17.08mA    15.81mA    16.11mA
-492.2mV  13.27mA    12.6mA     12.68mA
-344.5mV  9.899mA    9.602mA    9.224mA
609.4mV   -16.67mA   -16.25mA   -15.14mA
890.6mV   -23.21mA   -22.2mA    -20.21mA
1.172V    -27.69mA   -25.76mA   -22.9mA
1.697V    -31.62mA   -28.91mA   -25.34mA
2.484V    -34.5mA    -31.4mA    -27.38mA
2.583V    -36.78mA   -31.64mA   -27.59mA
2.632V    -35.03mA   -31.76mA   -27.69mA
3V        -35.79mA   -32.59mA   -28.42mA
[Pulldown]
| Voltage   I(typ)   I(min)   I(max)
-1.5V     -21.82mA   -18.49mA   -20.2mA
-1.378V   -22.83mA   -19.76mA   -19.67mA
-1.181V   -23.53mA   -21.32mA   -15.94mA
-1.083V   -22.32mA   -21.64mA   -15.31mA
-984.4mV  -18.66mA   -21.33mA   -14.78mA
-639.8mV  -15.03mA   -16.66mA   -12.69mA
-344.5mV  -9.863mA   -10.48mA   -8.746mA
609.4mV   16.39mA    17.04mA    14.75mA
843.8mV   21.52mA    21.78mA    19.64mA
1.078V    25.26mA    24.3mA     23.64mA
1.5V      27.4mA     25.5mA     26.63mA
3V        29.62mA    27.49mA    28.84mA
[Ramp]
dV/dt_r   0.519086/0.136291n  0.488502/0.144831n  0.51781/0.161797n
dV/dt_f   0.514683/0.12276n  0.499258/0.122793n  0.513484/0.123433n
R_load = 50
[Rising Waveform]
R_fixture = 50
V_fixture = 0
V_fixture_min = 0
V_fixture_max = 0
| Time   V(typ)   V(min)   V(max)
0s        1.633uV    2.836uV    2.461uV
1.03ns    -638.4uV   -470uV     3.02mV
1.243ns   -3.165mV   -567.8uV   653mV
1.318ns   -1.07mV    -602.2uV   772.1mV
1.382ns   128.1mV    -631.6uV   818.3mV
1.546ns   726.3mV    -706.9uV   852.9mV
1.756ns   851.4mV    9.271mV    860.5mV
1.984ns   861.9mV    696mV      861.7mV
2.239ns   863.9mV    804.9mV    862.1mV
10ns      865.1mV    814.2mV    863mV
[Rising Waveform]
R_fixture = 50
V_fixture = 1.5
V_fixture_min = 1.425
V_fixture_max = 1.575
| Time   V(typ)   V(min)   V(max)
0s        642.2mV    592.9mV    719.2mV
919ps     642.9mV    593.1mV    724.5mV
1.086ns   643mV      593.2mV    1.384V
1.239ns   657.7mV    593.2mV    1.551V
1.358ns   1.181V     593.3mV    1.567V
1.454ns   1.432V     593.3mV    1.57V
1.647ns   1.489V     610.6mV    1.573V
1.837ns   1.497V     1.301V     1.574V
2.015ns   1.498V     1.409V     1.574V
10ns      1.5V       1.425V     1.575V
[Falling Waveform]
R_fixture = 50
V_fixture = 0
V_fixture_min = 0
V_fixture_max = 0
| Time   V(typ)   V(min)   V(max)
0s        865.2mV    814.2mV    863mV
906ps     864.4mV    813.8mV    853.7mV
1.058ns   864.3mV    813.7mV    146.8mV
1.275ns   741.6mV    813.6mV    9.969mV
1.366ns   228.2mV    813.6mV    5.839mV
1.423ns   77.08mV    813.5mV    3.595mV
1.684ns   5.54mV     793.5mV    1.685mV
1.854ns   2.334mV    86.79mV    1.171mV
2.051ns   1.43mV     7.978mV    893.3uV
10ns      2.632uV    4.35uV     3.262uV
[Falling Waveform]
R_fixture = 50
V_fixture = 1.5
V_fixture_min = 1.425
V_fixture_max = 1.575
| Time   V(typ)   V(min)   V(max)
0s        1.5V       1.425V     1.575V
985ps     1.501V     1.425V     1.575V
1.188ns   1.501V     1.426V     863.4mV
1.325ns   1.478V     1.426V     743.6mV
1.413ns   1.18V      1.426V     730.3mV
1.601ns   680.8mV    1.426V     723mV
1.757ns   650.9mV    1.378V     721.9mV
1.939ns   645.4mV    712mV      721.2mV
2.151ns   644.3mV    601.8mV    720.6mV
10ns      642.2mV    592.9mV    719.2mV
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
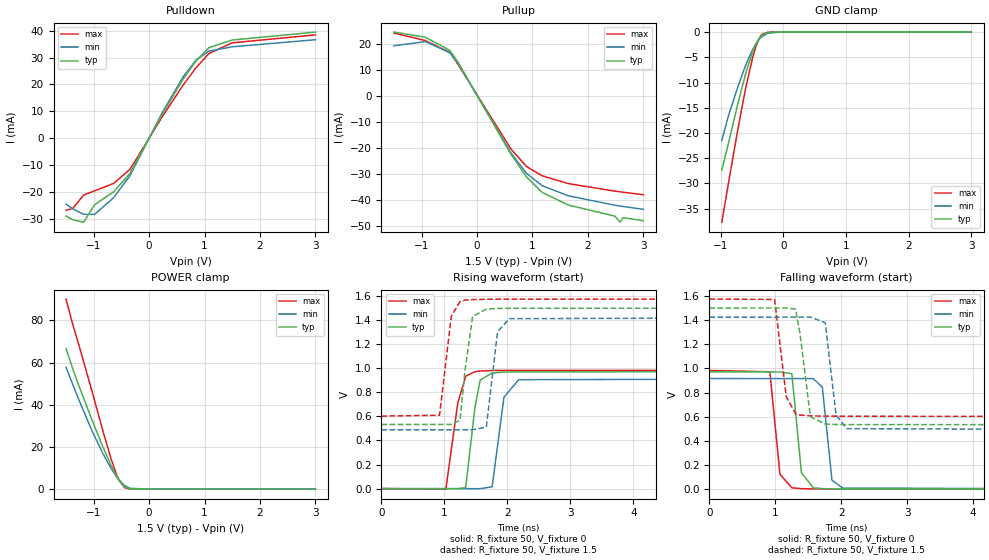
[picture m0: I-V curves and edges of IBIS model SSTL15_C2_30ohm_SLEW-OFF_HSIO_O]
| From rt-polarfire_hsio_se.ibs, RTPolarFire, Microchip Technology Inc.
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|   Model SSTL15_C2_30ohm_SLEW-OFF_HSIO_O
[Model]   SSTL15_C2_30ohm_SLEW-OFF_HSIO_O
Model_type   Output
Polarity   Non-Inverting
Enable   Active-High
Vmeas =   0.75
Cref =   5p
Rref =   50
Vref =   0.75
|   typ   min   max
C_comp_pullup   1.335e-12   1.335e-12   1.380e-12
C_comp_pulldown  1.335e-12   1.335e-12   1.380e-12
[Temperature Range]  25C   125C   -55C
[Voltage Range]  1.5   1.425   1.575
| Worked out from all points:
|   slope of the pulldown table from 0 to 0.225 V, typ, clamps not added: 26.4 ohm
|   slope of the pullup table from 0 to 0.225 V, typ, clamps not added: 26.4 ohm
|   GND clamp passes 1 mA (typ) near -0.37 V on its own axis
|   POWER clamp passes 1 mA (typ) near -0.43 V on its own axis
|   rising waveform, R_fixture 50, V_fixture 0: 20-80 % time 117ps typ, 124ps min, 139ps max; typ from 0 V to 0.972 V
|   rising waveform, R_fixture 50, V_fixture 1.5: 20-80 % time 111ps typ, 107ps min, 119ps max; typ from 0.533 V to 1.5 V
|   falling waveform, R_fixture 50, V_fixture 0: 20-80 % time 83.1ps typ, 82ps min, 87.3ps max; typ from 0.972 V to 0 V
|   falling waveform, R_fixture 50, V_fixture 1.5: 20-80 % time 105ps typ, 105ps min, 106ps max; typ from 1.5 V to 0.533 V
[GND Clamp]
| Voltage   I(typ)   I(min)   I(max)
-984.4mV  -27.37mA   -21.52mA   -37.7mA
-885.9mV  -22.43mA   -16.92mA   -30.48mA
-738.3mV  -14.72mA   -11.21mA   -19.96mA
-639.8mV  -9.903mA   -7.76mA    -13.42mA
-590.6mV  -7.7mA     -6.188mA   -10.38mA
-492.2mV  -3.93mA    -3.481mA   -5.066mA
-443mV    -2.467mA   -2.402mA   -2.955mA
-393.7mV  -1.355mA   -1.538mA   -1.375mA
-344.5mV  -621.9uA   -897uA     -448.3uA
-246.1mV  -72.57uA   -218.4uA   -18.4uA
-49.22mV  -334.5nA   -3.793uA   -95.68nA
3V        0A         0A         0A
[POWER Clamp]
| Voltage   I(typ)   I(min)   I(max)
-1.5V     66.64mA    57.8mA     90.1mA
-1.378V   57.06mA    49.6mA     78.07mA
-1.28V    49.9mA     43.13mA    69.49mA
-1.034V   32.99mA    27.83mA    46.7mA
-836.7mV  20.16mA    16.97mA    27.85mA
-689.1mV  11.42mA    9.956mA    14.55mA
-590.6mV  6.331mA    6.012mA    7.055mA
-541.4mV  4.184mA    4.318mA    4.125mA
-443mV    1.134mA    1.688mA    703.5uA
-344.5mV  93.53uA    432.5uA    21.45uA
-49.22mV  620.3nA    2.506uA    250nA
3V        0A         0A         0A
[Pullup]
| Voltage   I(typ)   I(min)   I(max)
-1.5V     24.72mA    19.44mA    24.38mA
-935.2mV  22.77mA    21.08mA    21.48mA
-492.2mV  17.69mA    16.8mA     16.91mA
-344.5mV  13.2mA     12.8mA     12.29mA
609.4mV   -22.23mA   -21.67mA   -20.19mA
890.6mV   -30.94mA   -29.6mA    -26.95mA
1.172V    -36.92mA   -34.34mA   -30.53mA
1.648V    -41.82mA   -38.26mA   -33.56mA
2.484V    -46.05mA   -41.86mA   -36.45mA
2.583V    -48.4mA    -42.18mA   -36.73mA
2.632V    -46.65mA   -42.34mA   -36.86mA
3V        -47.83mA   -43.44mA   -37.84mA
[Pulldown]
| Voltage   I(typ)   I(min)   I(max)
-1.5V     -29.1mA    -24.66mA   -26.94mA
-1.378V   -30.44mA   -26.35mA   -26.22mA
-1.181V   -31.37mA   -28.44mA   -21.24mA
-984.4mV  -24.86mA   -28.45mA   -19.7mA
-639.8mV  -20.03mA   -22.21mA   -16.91mA
-344.5mV  -13.14mA   -13.98mA   -11.65mA
234.4mV   8.875mA    9.433mA    7.89mA
609.4mV   21.84mA    22.71mA    19.65mA
843.8mV   28.69mA    29.04mA    26.16mA
1.078V    33.68mA    32.41mA    31.5mA
1.5V      36.55mA    34.02mA    35.5mA
3V        39.5mA     36.66mA    38.45mA
[Ramp]
dV/dt_r   0.583141/0.116851n  0.55004/0.123519n  0.590051/0.13934n
dV/dt_f   0.580324/0.105261n  0.562059/0.104943n  0.583377/0.106335n
R_load = 50
[Rising Waveform]
R_fixture = 50
V_fixture = 0
V_fixture_min = 0
V_fixture_max = 0
| Time   V(typ)   V(min)   V(max)
0s        1.583uV    2.561uV    2.349uV
1.023ns   -620.7uV   -369.7uV   -4.631mV
1.212ns   -735.6uV   -438.5uV   709.7mV
1.338ns   8.747mV    -484.3uV   933.8mV
1.486ns   678.5mV    -538.2uV   972.1mV
1.568ns   902mV      -568uV     977.1mV
1.758ns   960.6mV    14.84mV    981.3mV
1.946ns   968.3mV    759.6mV    982.1mV
2.179ns   970.3mV    904.6mV    982.3mV
10ns      971.9mV    916.7mV    983.4mV
[Rising Waveform]
R_fixture = 50
V_fixture = 1.5
V_fixture_min = 1.425
V_fixture_max = 1.575
| Time   V(typ)   V(min)   V(max)
0s        532.8mV    488.2mV    602.7mV
923ps     533.3mV    488.4mV    609.7mV
1.109ns   533.4mV    488.4mV    1.431V
1.248ns   568.1mV    488.5mV    1.555V
1.327ns   981.5mV    488.5mV    1.566V
1.448ns   1.43V      488.5mV    1.571V
1.666ns   1.492V     511.6mV    1.573V
1.844ns   1.497V     1.304V     1.574V
2.032ns   1.498V     1.412V     1.574V
10ns      1.5V       1.425V     1.575V
[Falling Waveform]
R_fixture = 50
V_fixture = 0
V_fixture_min = 0
V_fixture_max = 0
| Time   V(typ)   V(min)   V(max)
0s        971.9mV    916.8mV    983.4mV
917ps     971.2mV    916.2mV    972.6mV
1.07ns    971.1mV    916.1mV    123.9mV
1.25ns    957mV      916mV      11.28mV
1.396ns   135.9mV    915.9mV    4.405mV
1.577ns   10.8mV     915.8mV    2.044mV
1.713ns   4.609mV    843.9mV    1.546mV
1.859ns   2.245mV    73.82mV    1.244mV
2.022ns   1.472mV    8.88mV     906.5uV
10ns      2.616uV    3.333uV    3.013uV
[Falling Waveform]
R_fixture = 50
V_fixture = 1.5
V_fixture_min = 1.425
V_fixture_max = 1.575
| Time   V(typ)   V(min)   V(max)
0s        1.5V       1.425V     1.575V
989ps     1.501V     1.425V     1.572V
1.166ns   1.501V     1.426V     765.5mV
1.308ns   1.492V     1.426V     624.4mV
1.374ns   1.289V     1.426V     614.5mV
1.532ns   600.6mV    1.426V     607mV
1.757ns   539.2mV    1.379V     605.1mV
1.921ns   535.7mV    616mV      604.4mV
2.08ns    534.9mV    501.1mV    604mV
10ns      532.8mV    488.2mV    602.7mV
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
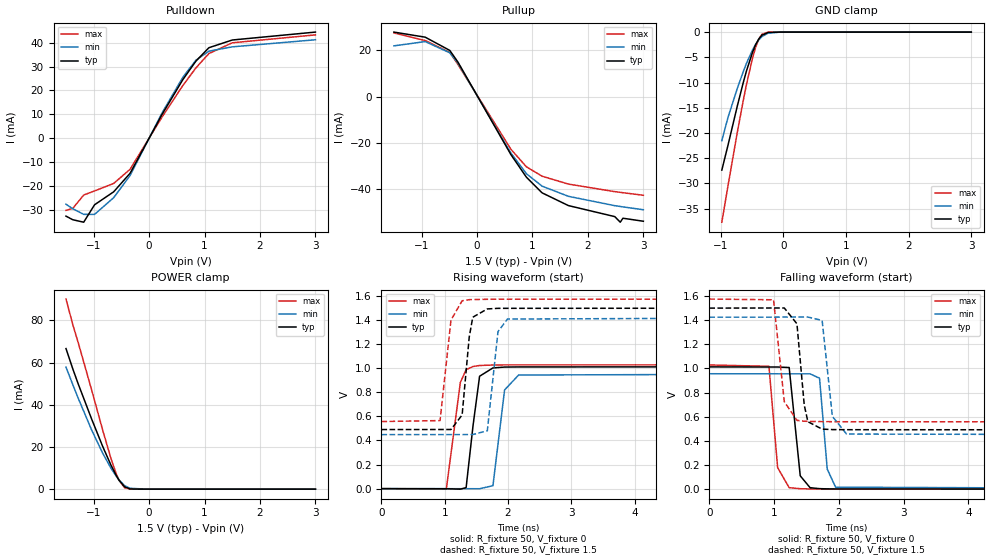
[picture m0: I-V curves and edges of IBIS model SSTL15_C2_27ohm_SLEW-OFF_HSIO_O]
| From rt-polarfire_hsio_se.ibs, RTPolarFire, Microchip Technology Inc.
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|   Model SSTL15_C2_27ohm_SLEW-OFF_HSIO_O
[Model]   SSTL15_C2_27ohm_SLEW-OFF_HSIO_O
Model_type   Output
Polarity   Non-Inverting
Enable   Active-High
Vmeas =   0.75
Cref =   5p
Rref =   50
Vref =   0.75
|   typ   min   max
C_comp_pullup   1.335e-12   1.335e-12   1.380e-12
C_comp_pulldown  1.335e-12   1.335e-12   1.380e-12
[Temperature Range]  25C   125C   -55C
[Voltage Range]  1.5   1.425   1.575
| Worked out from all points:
|   slope of the pulldown table from 0 to 0.225 V, typ, clamps not added: 23.5 ohm
|   slope of the pullup table from 0 to 0.225 V, typ, clamps not added: 23.5 ohm
|   GND clamp passes 1 mA (typ) near -0.37 V on its own axis
|   POWER clamp passes 1 mA (typ) near -0.43 V on its own axis
|   rising waveform, R_fixture 50, V_fixture 0: 20-80 % time 110ps typ, 119ps min, 130ps max; typ from 0 V to 1.01 V
|   rising waveform, R_fixture 50, V_fixture 1.5: 20-80 % time 108ps typ, 104ps min, 115ps max; typ from 0.491 V to 1.5 V
|   falling waveform, R_fixture 50, V_fixture 0: 20-80 % time 79.6ps typ, 77.2ps min, 83.9ps max; typ from 1.01 V to 0 V
|   falling waveform, R_fixture 50, V_fixture 1.5: 20-80 % time 97.7ps typ, 98.8ps min, 100ps max; typ from 1.5 V to 0.491 V
[GND Clamp]
| Voltage   I(typ)   I(min)   I(max)
-984.4mV  -27.37mA   -21.52mA   -37.7mA
-885.9mV  -22.43mA   -16.92mA   -30.48mA
-738.3mV  -14.72mA   -11.21mA   -19.96mA
-639.8mV  -9.903mA   -7.76mA    -13.42mA
-590.6mV  -7.7mA     -6.188mA   -10.38mA
-492.2mV  -3.93mA    -3.481mA   -5.066mA
-443mV    -2.467mA   -2.402mA   -2.955mA
-393.7mV  -1.355mA   -1.538mA   -1.375mA
-344.5mV  -621.9uA   -897uA     -448.3uA
-246.1mV  -72.57uA   -218.4uA   -18.4uA
-49.22mV  -334.5nA   -3.793uA   -95.68nA
3V        0A         0A         0A
[POWER Clamp]
| Voltage   I(typ)   I(min)   I(max)
-1.5V     66.64mA    57.8mA     90.1mA
-1.378V   57.06mA    49.6mA     78.07mA
-1.28V    49.9mA     43.13mA    69.49mA
-1.034V   32.99mA    27.83mA    46.7mA
-836.7mV  20.16mA    16.97mA    27.85mA
-689.1mV  11.42mA    9.956mA    14.55mA
-590.6mV  6.331mA    6.012mA    7.055mA
-541.4mV  4.184mA    4.318mA    4.125mA
-443mV    1.134mA    1.688mA    703.5uA
-344.5mV  93.53uA    432.5uA    21.45uA
-49.22mV  620.3nA    2.506uA    250nA
3V        0A         0A         0A
[Pullup]
| Voltage   I(typ)   I(min)   I(max)
-1.5V     27.81mA    21.87mA    27.43mA
-935.2mV  25.61mA    23.71mA    24.17mA
-492.2mV  19.9mA     18.89mA    19.02mA
-344.5mV  14.84mA    14.4mA     13.83mA
609.4mV   -25mA      -24.37mA   -22.71mA
890.6mV   -34.81mA   -33.3mA    -30.32mA
1.172V    -41.53mA   -38.64mA   -34.35mA
1.648V    -47.04mA   -43.04mA   -37.76mA
2.484V    -51.79mA   -47.07mA   -41.02mA
2.583V    -54.2mA    -47.42mA   -41.33mA
2.632V    -52.49mA   -47.6mA    -41.48mA
3V        -53.79mA   -48.83mA   -42.58mA
[Pulldown]
| Voltage   I(typ)   I(min)   I(max)
-1.5V     -32.73mA   -27.73mA   -30.31mA
-1.378V   -34.24mA   -29.64mA   -29.49mA
-1.181V   -35.27mA   -31.99mA   -23.89mA
-984.4mV  -27.96mA   -32mA      -22.16mA
-639.8mV  -22.53mA   -24.99mA   -19.02mA
-344.5mV  -14.78mA   -15.72mA   -13.1mA
234.4mV   9.981mA    10.61mA    8.87mA
609.4mV   24.56mA    25.54mA    22.09mA
843.8mV   32.26mA    32.64mA    29.42mA
1.078V    37.88mA    36.43mA    35.43mA
1.5V      41.11mA    38.24mA    39.94mA
3V        44.43mA    41.21mA    43.26mA
[Ramp]
dV/dt_r   0.607763/0.110433n  0.57379/0.118834n  0.617547/0.129917n
dV/dt_f   0.605499/97.7243p  0.585729/98.805p  0.6105/0.100284n
R_load = 50
[Rising Waveform]
R_fixture = 50
V_fixture = 0
V_fixture_min = 0
V_fixture_max = 0
| Time   V(typ)   V(min)   V(max)
0s        1.564uV    2.456uV    2.305uV
1.025ns   -776.2uV   -531.5uV   -4.426mV
1.247ns   -4.41mV    -647.2uV   882.4mV
1.338ns   8.574mV    -694.6uV   988.2mV
1.448ns   526.6mV    -751.9uV   1.015V
1.551ns   933.8mV    -805.5uV   1.023V
1.762ns   1.003V     24.42mV    1.027V
1.946ns   1.01V      820.1mV    1.028V
2.168ns   1.011V     944mV      1.028V
10ns      1.013V     956.3mV    1.029V
[Rising Waveform]
R_fixture = 50
V_fixture = 1.5
V_fixture_min = 1.425
V_fixture_max = 1.575
| Time   V(typ)   V(min)   V(max)
0s        490.8mV    448.7mV    557.5mV
926ps     491.3mV    449mV      565.4mV
1.099ns   491.3mV    449.1mV    1.4V
1.275ns   612.1mV    449.1mV    1.561V
1.387ns   1.259V     449.2mV    1.57V
1.443ns   1.424V     449.2mV    1.571V
1.673ns   1.493V     480.6mV    1.573V
1.842ns   1.498V     1.305V     1.574V
1.992ns   1.498V     1.409V     1.574V
10ns      1.5V       1.425V     1.575V
[Falling Waveform]
R_fixture = 50
V_fixture = 0
V_fixture_min = 0
V_fixture_max = 0
| Time   V(typ)   V(min)   V(max)
0s        1.013V     956.3mV    1.029V
920ps     1.012V     955.8mV    1.018V
1.054ns   1.012V     955.7mV    178.4mV
1.232ns   1.008V     955.6mV    12.31mV
1.403ns   110.7mV    955.5mV    3.747mV
1.555ns   12.18mV    955.4mV    2.007mV
1.701ns   4.355mV    919.3mV    1.434mV
1.82ns    2.459mV    165.9mV    1.187mV
1.949ns   1.568mV    16.29mV    963.8uV
10ns      2uV        3.583uV    2.957uV
[Falling Waveform]
R_fixture = 50
V_fixture = 1.5
V_fixture_min = 1.425
V_fixture_max = 1.575
| Time   V(typ)   V(min)   V(max)
0s        1.5V       1.425V     1.575V
991ps     1.501V     1.425V     1.569V
1.157ns   1.501V     1.426V     724.8mV
1.352ns   1.37V      1.426V     570mV
1.465ns   696.2mV    1.426V     562.9mV
1.521ns   559.1mV    1.426V     561.7mV
1.741ns   497.4mV    1.398V     559.8mV
1.899ns   493.7mV    603mV      559.1mV
2.118ns   492.7mV    456.5mV    558.6mV
10ns      490.8mV    448.7mV    557.5mV
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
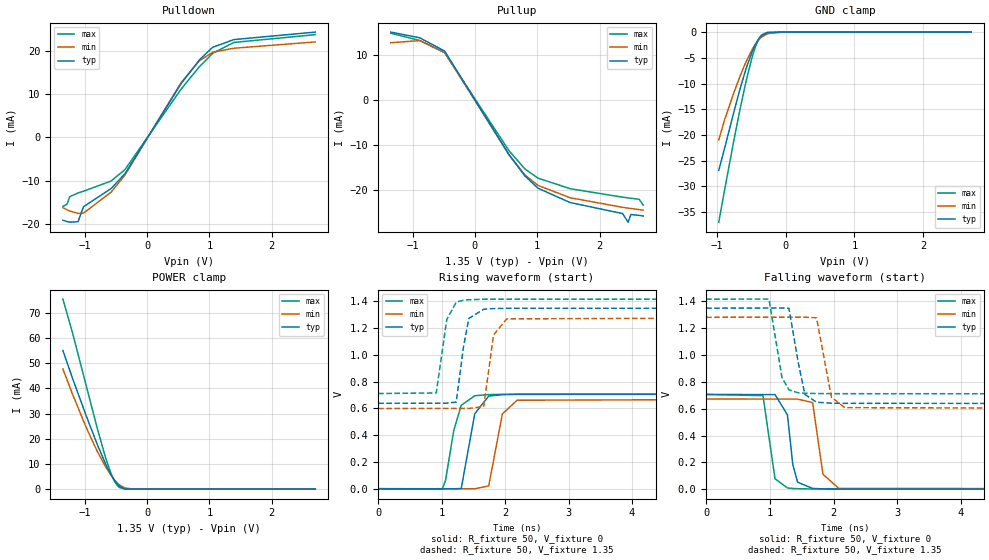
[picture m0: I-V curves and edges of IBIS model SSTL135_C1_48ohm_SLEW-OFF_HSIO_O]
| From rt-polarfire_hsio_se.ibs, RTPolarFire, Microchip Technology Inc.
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|   Model SSTL135_C1_48ohm_SLEW-OFF_HSIO_O
[Model]   SSTL135_C1_48ohm_SLEW-OFF_HSIO_O
Model_type   Output
Polarity   Non-Inverting
Enable   Active-High
Vmeas =   0.675
Cref =   5p
Rref =   50
Vref =   0.675
|   typ   min   max
C_comp_pullup   1.335e-12   1.335e-12   1.380e-12
C_comp_pulldown  1.335e-12   1.335e-12   1.380e-12
[Temperature Range]  25C   125C   -55C
[Voltage Range]  1.35   1.2825   1.4175
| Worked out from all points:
|   slope of the pulldown table from 0 to 0.203 V, typ, clamps not added: 42 ohm
|   slope of the pullup table from 0 to 0.203 V, typ, clamps not added: 42.9 ohm
|   GND clamp passes 1 mA (typ) near -0.37 V on its own axis
|   POWER clamp passes 1 mA (typ) near -0.43 V on its own axis
|   rising waveform, R_fixture 50, V_fixture 0: 20-80 % time 147ps typ, 152ps min, 169ps max; typ from 0 V to 0.706 V
|   rising waveform, R_fixture 50, V_fixture 1.35: 20-80 % time 108ps typ, 104ps min, 120ps max; typ from 0.638 V to 1.35 V
|   falling waveform, R_fixture 50, V_fixture 0: 20-80 % time 103ps typ, 105ps min, 102ps max; typ from 0.706 V to 0 V
|   falling waveform, R_fixture 50, V_fixture 1.35: 20-80 % time 125ps typ, 130ps min, 127ps max; typ from 1.35 V to 0.638 V
[GND Clamp]
| Voltage   I(typ)   I(min)   I(max)
-974.5mV  -26.9mA    -20.99mA   -36.97mA
-885.9mV  -22.43mA   -16.91mA   -30.47mA
-753mV    -15.48mA   -11.75mA   -20.97mA
-664.5mV  -11.06mA   -8.585mA   -15mA
-575.9mV  -7.072mA   -5.739mA   -9.511mA
-487.3mV  -3.767mA   -3.362mA   -4.833mA
-443mV    -2.466mA   -2.401mA   -2.954mA
-398.7mV  -1.449mA   -1.613mA   -1.504mA
-354.4mV  -738.4uA   -1.007mA   -579.6uA
-265.8mV  -117.5uA   -300.6uA   -36.61uA
-44.3mV   -274.4nA   -3.251uA   -69.5nA
2.7V      0A         0A         0A
[POWER Clamp]
| Voltage   I(typ)   I(min)   I(max)
-1.35V    55.07mA    47.72mA    75.49mA
-1.196V   44.05mA    37.75mA    62.13mA
-974.5mV  29.03mA    24.41mA    40.95mA
-797.3mV  17.68mA    14.97mA    24.06mA
-664.5mV  10.01mA    8.871mA    12.44mA
-575.9mV  5.63mA     5.451mA    6.064mA
-531.6mV  3.786mA    3.983mA    3.599mA
-487.3mV  2.262mA    2.712mA    1.789mA
-443mV    1.133mA    1.675mA    684.4uA
-354.4mV  127.5uA    473.3uA    30.46uA
-221.5mV  1.715uA    56.89uA    636.6nA
2.7V      0A         0A         0A
[Pullup]
| Voltage   I(typ)   I(min)   I(max)
-1.35V    15.04mA    12.67mA    14.78mA
-885.9mV  13.77mA    13.15mA    13.18mA
-487.3mV  10.84mA    10.55mA    10.45mA
548.4mV   -12.25mA   -12.26mA   -11.36mA
801.6mV   -16.95mA   -16.7mA    -15.39mA
1.012V    -19.67mA   -19.05mA   -17.43mA
1.527V    -22.85mA   -21.78mA   -19.77mA
2.369V    -25.31mA   -23.92mA   -21.66mA
2.457V    -27.22mA   -24.09mA   -21.82mA
2.502V    -25.52mA   -24.17mA   -21.9mA
2.635V    -25.71mA   -24.42mA   -22.13mA
2.7V      -25.84mA   -24.53mA   -23.41mA
[Pulldown]
| Voltage   I(typ)   I(min)   I(max)
-1.35V    -19.17mA   -16.29mA   -15.98mA
-1.285V   -19.49mA   -16.77mA   -15.5mA
-1.24V    -19.63mA   -17.05mA   -13.73mA
-1.107V   -19.5mA    -17.59mA   -12.88mA
-1.019V   -16.04mA   -17.53mA   -12.47mA
-575.9mV  -11.85mA   -12.68mA   -10.11mA
-354.4mV  -8.43mA    -8.749mA   -7.473mA
548.4mV   12.43mA    12.68mA    11.16mA
843.8mV   17.94mA    17.72mA    16.37mA
1.055V    20.81mA    19.66mA    19.42mA
1.394V    22.58mA    20.58mA    21.92mA
2.7V      24.31mA    22.04mA    23.72mA
[Ramp]
dV/dt_r   0.423838/0.146932n  0.403533/0.151581n  0.423762/0.169408n
dV/dt_f   0.426897/0.125151n  0.410013/0.130146n  0.423912/0.126696n
R_load = 50
[Rising Waveform]
R_fixture = 50
V_fixture = 0
V_fixture_min = 0
V_fixture_max = 0
| Time   V(typ)   V(min)   V(max)
0s        1.388uV    2.695uV    2.037uV
1.008ns   -579.9uV   -529.6uV   -3.505mV
1.061ns   -610.5uV   -557.6uV   60.42mV
1.191ns   -685.5uV   -626.2uV   434.7mV
1.309ns   1.649mV    -688.6uV   623.2mV
1.522ns   560mV      -801uV     694.5mV
1.742ns   692.3mV    21.31mV    703.4mV
1.957ns   702.8mV    558.2mV    705mV
2.188ns   705.1mV    661.1mV    705.3mV
10ns      706.4mV    672.6mV    706.3mV
[Rising Waveform]
R_fixture = 50
V_fixture = 1.35
V_fixture_min = 1.2825
V_fixture_max = 1.4175
| Time   V(typ)   V(min)   V(max)
0s        638.5mV    599.1mV    711mV
915ps     639.1mV    599.6mV    715.5mV
1.081ns   639.2mV    599.7mV    1.264V
1.23ns    647.2mV    599.8mV    1.394V
1.345ns   1.063V     599.9mV    1.409V
1.43ns    1.273V     599.9mV    1.412V
1.663ns   1.341V     614mV      1.416V
1.818ns   1.346V     1.148V     1.416V
2.025ns   1.348V     1.269V     1.416V
10ns      1.35V      1.282V     1.417V
[Falling Waveform]
R_fixture = 50
V_fixture = 0
V_fixture_min = 0
V_fixture_max = 0
| Time   V(typ)   V(min)   V(max)
0s        706.4mV    672.6mV    706.3mV
892ps     705.8mV    672.1mV    697.9mV
1.081ns   705.7mV    672mV      77.6mV
1.276ns   554.6mV    671.9mV    8.922mV
1.36ns    183.9mV    671.9mV    4.967mV
1.435ns   52.07mV    671.9mV    3.658mV
1.671ns   5.66mV     646mV      1.481mV
1.833ns   2.303mV    111.4mV    1.125mV
2.08ns    1.257mV    6.521mV    746uV
10ns      2.419uV    4.176uV    2.176uV
[Falling Waveform]
R_fixture = 50
V_fixture = 1.35
V_fixture_min = 1.2825
V_fixture_max = 1.4175
| Time   V(typ)   V(min)   V(max)
0s        1.35V      1.282V     1.417V
986ps     1.351V     1.283V     1.418V
1.19ns    1.351V     1.283V     833mV
1.299ns   1.35V      1.283V     740.9mV
1.443ns   950.6mV    1.283V     719.1mV
1.549ns   707.3mV    1.283V     715.4mV
1.732ns   648.7mV    1.278V     713.3mV
1.967ns   641.2mV    684.7mV    712.5mV
2.178ns   640.3mV    608mV      712.2mV
10ns      638.5mV    599.1mV    711mV
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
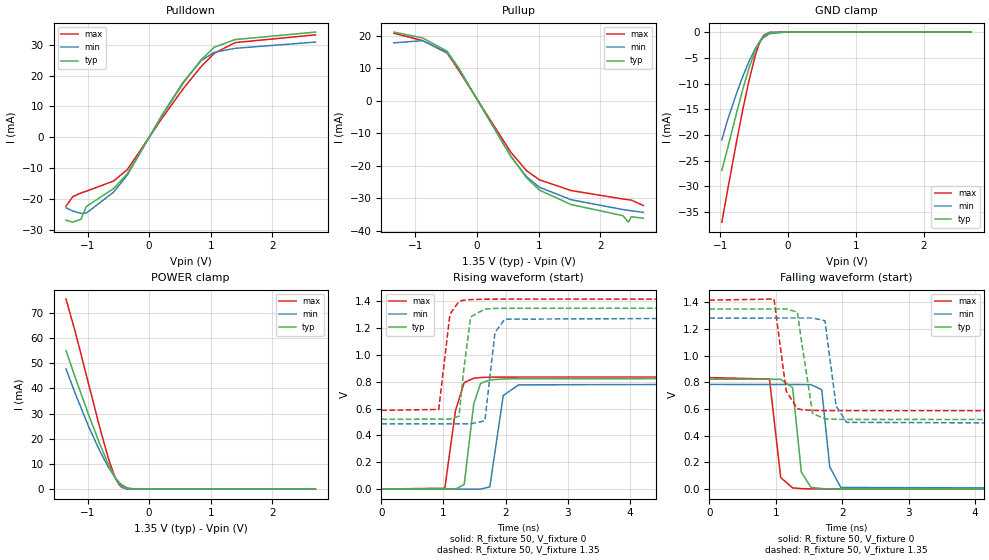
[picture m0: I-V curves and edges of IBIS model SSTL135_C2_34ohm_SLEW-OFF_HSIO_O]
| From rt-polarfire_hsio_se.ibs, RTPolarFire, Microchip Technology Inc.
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|   Model SSTL135_C2_34ohm_SLEW-OFF_HSIO_O
[Model]   SSTL135_C2_34ohm_SLEW-OFF_HSIO_O
Model_type   Output
Polarity   Non-Inverting
Enable   Active-High
Vmeas =   0.675
Cref =   5p
Rref =   50
Vref =   0.675
|   typ   min   max
C_comp_pullup   1.335e-12   1.335e-12   1.380e-12
C_comp_pulldown  1.335e-12   1.335e-12   1.380e-12
[Temperature Range]  25C   125C   -55C
[Voltage Range]  1.35   1.2825   1.4175
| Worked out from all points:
|   slope of the pulldown table from 0 to 0.203 V, typ, clamps not added: 30.1 ohm
|   slope of the pullup table from 0 to 0.203 V, typ, clamps not added: 30.7 ohm
|   GND clamp passes 1 mA (typ) near -0.37 V on its own axis
|   POWER clamp passes 1 mA (typ) near -0.43 V on its own axis
|   rising waveform, R_fixture 50, V_fixture 0: 20-80 % time 121ps typ, 127ps min, 142ps max; typ from 0 V to 0.824 V
|   rising waveform, R_fixture 50, V_fixture 1.35: 20-80 % time 97.1ps typ, 101ps min, 111ps max; typ from 0.521 V to 1.35 V
|   falling waveform, R_fixture 50, V_fixture 0: 20-80 % time 96.5ps typ, 88.6ps min, 91.3ps max; typ from 0.824 V to 0 V
|   falling waveform, R_fixture 50, V_fixture 1.35: 20-80 % time 107ps typ, 108ps min, 107ps max; typ from 1.35 V to 0.521 V
[GND Clamp]
| Voltage   I(typ)   I(min)   I(max)
-974.5mV  -26.9mA    -20.99mA   -36.97mA
-885.9mV  -22.43mA   -16.91mA   -30.47mA
-753mV    -15.48mA   -11.75mA   -20.97mA
-664.5mV  -11.06mA   -8.585mA   -15mA
-575.9mV  -7.072mA   -5.739mA   -9.511mA
-487.3mV  -3.767mA   -3.362mA   -4.833mA
-443mV    -2.466mA   -2.401mA   -2.954mA
-398.7mV  -1.449mA   -1.613mA   -1.504mA
-354.4mV  -738.4uA   -1.007mA   -579.6uA
-265.8mV  -117.5uA   -300.6uA   -36.61uA
-44.3mV   -274.4nA   -3.251uA   -69.5nA
2.7V      0A         0A         0A
[POWER Clamp]
| Voltage   I(typ)   I(min)   I(max)
-1.35V    55.07mA    47.72mA    75.49mA
-1.196V   44.05mA    37.75mA    62.13mA
-974.5mV  29.03mA    24.41mA    40.95mA
-797.3mV  17.68mA    14.97mA    24.06mA
-664.5mV  10.01mA    8.871mA    12.44mA
-575.9mV  5.63mA     5.451mA    6.064mA
-531.6mV  3.786mA    3.983mA    3.599mA
-487.3mV  2.262mA    2.712mA    1.789mA
-443mV    1.133mA    1.675mA    684.4uA
-354.4mV  127.5uA    473.3uA    30.46uA
-221.5mV  1.715uA    56.89uA    636.6nA
2.7V      0A         0A         0A
[Pullup]
| Voltage   I(typ)   I(min)   I(max)
-1.35V    21.05mA    17.74mA    20.68mA
-885.9mV  19.28mA    18.42mA    18.45mA
-487.3mV  15.17mA    14.76mA    14.62mA
-310.1mV  10.28mA    10.29mA    9.644mA
548.4mV   -17.15mA   -17.16mA   -15.9mA
801.6mV   -23.72mA   -23.38mA   -21.54mA
1.012V    -27.54mA   -26.67mA   -24.39mA
1.527V    -31.99mA   -30.5mA    -27.68mA
2.369V    -35.41mA   -33.53mA   -30.28mA
2.457V    -37.41mA   -33.77mA   -30.5mA
2.502V    -35.73mA   -33.89mA   -30.61mA
2.7V      -36.2mA    -34.39mA   -32.28mA
[Pulldown]
| Voltage   I(typ)   I(min)   I(max)
-1.35V    -26.85mA   -22.81mA   -22.34mA
-1.24V    -27.49mA   -23.87mA   -19.21mA
-1.107V   -26.54mA   -24.63mA   -18.02mA
-1.019V   -22.4mA    -24.53mA   -17.45mA
-575.9mV  -16.58mA   -17.74mA   -14.15mA
-354.4mV  -11.79mA   -12.24mA   -10.45mA
210.9mV   7.012mA    7.279mA    6.23mA
548.4mV   17.39mA    17.74mA    15.61mA
843.8mV   25.11mA    24.8mA     22.9mA
1.055V    29.14mA    27.51mA    27.17mA
1.394V    31.64mA    28.81mA    30.66mA
2.7V      34.07mA    30.84mA    33.18mA
[Ramp]
dV/dt_r   0.494545/0.121231n  0.470976/0.12674n  0.50187/0.141669n
dV/dt_f   0.497519/0.106713n  0.478022/0.108424n  0.498399/0.107316n
R_load = 50
[Rising Waveform]
R_fixture = 50
V_fixture = 0
V_fixture_min = 0
V_fixture_max = 0
| Time   V(typ)   V(min)   V(max)
0s        1.379uV    2.424uV    1.989uV
1.022ns   -833.9uV   -541uV     6.001mV
1.192ns   -972.8uV   -631.4uV   583.5mV
1.334ns   34.32mV    -706.9uV   793.6mV
1.487ns   633.8mV    -788.2uV   826.3mV
1.599ns   788.3mV    -847.8uV   832mV
1.747ns   814mV      16.4mV     834.3mV
1.963ns   821.4mV    697.7mV    835.3mV
2.211ns   823mV      777.2mV    835.5mV
10ns      824.2mV    785mV      836.5mV
[Rising Waveform]
R_fixture = 50
V_fixture = 1.35
V_fixture_min = 1.2825
V_fixture_max = 1.4175
| Time   V(typ)   V(min)   V(max)
0s        520.8mV    485.7mV    586.8mV
923ps     521.3mV    486.2mV    593.8mV
1.104ns   521.5mV    486.3mV    1.304V
1.25ns    543.3mV    486.4mV    1.4V
1.326ns   888.1mV    486.4mV    1.409V
1.438ns   1.284V     486.5mV    1.413V
1.667ns   1.343V     508.7mV    1.416V
1.83ns    1.347V     1.168V     1.416V
1.987ns   1.348V     1.267V     1.417V
10ns      1.35V      1.282V     1.417V
[Falling Waveform]
R_fixture = 50
V_fixture = 0
V_fixture_min = 0
V_fixture_max = 0
| Time   V(typ)   V(min)   V(max)
0s        824.2mV    785mV      836.4mV
905ps     823.6mV    784.5mV    825.4mV
1.075ns   823.4mV    784.4mV    86.66mV
1.254ns   760.7mV    784.3mV    9.613mV
1.385ns   128.2mV    784.2mV    4.166mV
1.529ns   14.2mV     784.1mV    2.233mV
1.692ns   4.282mV    745.2mV    1.45mV
1.813ns   2.297mV    166.8mV    1.223mV
1.979ns   1.521mV    12.83mV    911.5uV
10ns      2.102uV    4.144uV    2.76uV
[Falling Waveform]
R_fixture = 50
V_fixture = 1.35
V_fixture_min = 1.2825
V_fixture_max = 1.4175
| Time   V(typ)   V(min)   V(max)
0s        1.35V      1.282V     1.417V
973ps     1.351V     1.283V     1.425V
1.158ns   1.351V     1.283V     735.4mV
1.325ns   1.327V     1.283V     603.4mV
1.392ns   1.095V     1.283V     595.9mV
1.555ns   567.2mV    1.283V     590.3mV
1.74ns    527.8mV    1.263V     589.1mV
1.909ns   523.6mV    623.3mV    588.5mV
2.066ns   522.6mV    500.8mV    588.2mV
10ns      520.8mV    485.8mV    586.8mV
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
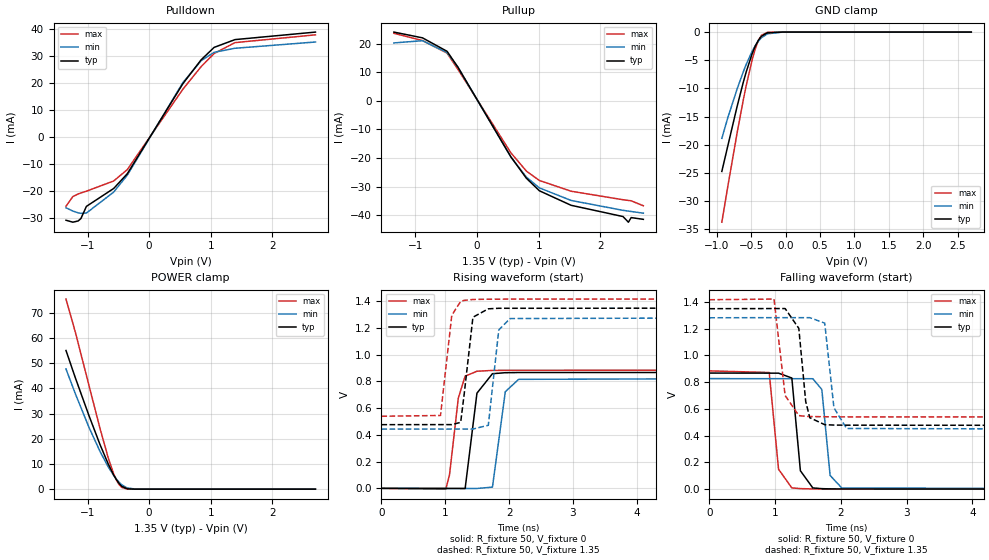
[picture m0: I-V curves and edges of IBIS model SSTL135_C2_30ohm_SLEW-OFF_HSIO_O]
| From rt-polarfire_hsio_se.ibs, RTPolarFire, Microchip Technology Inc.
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|   Model SSTL135_C2_30ohm_SLEW-OFF_HSIO_O
[Model]   SSTL135_C2_30ohm_SLEW-OFF_HSIO_O
Model_type   Output
Polarity   Non-Inverting
Enable   Active-High
Vmeas =   0.675
Cref =   5p
Rref =   50
Vref =   0.675
|   typ   min   max
C_comp_pullup   1.335e-12   1.335e-12   1.380e-12
C_comp_pulldown  1.335e-12   1.335e-12   1.380e-12
[Temperature Range]  25C   125C   -55C
[Voltage Range]  1.35   1.2825   1.4175
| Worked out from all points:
|   slope of the pulldown table from 0 to 0.203 V, typ, clamps not added: 26.3 ohm
|   slope of the pullup table from 0 to 0.203 V, typ, clamps not added: 26.8 ohm
|   GND clamp passes 1 mA (typ) near -0.37 V on its own axis
|   POWER clamp passes 1 mA (typ) near -0.43 V on its own axis
|   rising waveform, R_fixture 50, V_fixture 0: 20-80 % time 113ps typ, 118ps min, 134ps max; typ from 0 V to 0.868 V
|   rising waveform, R_fixture 50, V_fixture 1.35: 20-80 % time 98.7ps typ, 95.8ps min, 107ps max; typ from 0.477 V to 1.35 V
|   falling waveform, R_fixture 50, V_fixture 0: 20-80 % time 87.2ps typ, 84.1ps min, 90.8ps max; typ from 0.868 V to 0 V
|   falling waveform, R_fixture 50, V_fixture 1.35: 20-80 % time 101ps typ, 99.9ps min, 101ps max; typ from 1.35 V to 0.477 V
[GND Clamp]
| Voltage   I(typ)   I(min)   I(max)
-930.2mV  -24.71mA   -18.84mA   -33.71mA
-841.6mV  -20.1mA    -15.12mA   -27.26mA
-708.7mV  -13.23mA   -10.13mA   -17.94mA
-620.2mV  -8.998mA   -7.114mA   -12.18mA
-575.9mV  -7.072mA   -5.739mA   -9.511mA
-487.3mV  -3.767mA   -3.362mA   -4.833mA
-443mV    -2.466mA   -2.401mA   -2.954mA
-398.7mV  -1.449mA   -1.613mA   -1.504mA
-354.4mV  -738.4uA   -1.007mA   -579.6uA
-265.8mV  -117.5uA   -300.6uA   -36.61uA
-44.3mV   -274.4nA   -3.251uA   -69.5nA
2.7V      0A         0A         0A
[POWER Clamp]
| Voltage   I(typ)   I(min)   I(max)
-1.35V    55.07mA    47.72mA    75.49mA
-1.196V   44.05mA    37.75mA    62.13mA
-974.5mV  29.03mA    24.41mA    40.95mA
-797.3mV  17.68mA    14.97mA    24.06mA
-664.5mV  10.01mA    8.871mA    12.44mA
-575.9mV  5.63mA     5.451mA    6.064mA
-531.6mV  3.786mA    3.983mA    3.599mA
-487.3mV  2.262mA    2.712mA    1.789mA
-443mV    1.133mA    1.675mA    684.4uA
-354.4mV  127.5uA    473.3uA    30.46uA
-221.5mV  1.715uA    56.89uA    636.6nA
2.7V      0A         0A         0A
[Pullup]
| Voltage   I(typ)   I(min)   I(max)
-1.35V    24.06mA    20.27mA    23.64mA
-885.9mV  22.04mA    21.05mA    21.09mA
-487.3mV  17.34mA    16.87mA    16.71mA
-310.1mV  11.75mA    11.76mA    11.02mA
548.4mV   -19.59mA   -19.61mA   -18.17mA
801.6mV   -27.11mA   -26.72mA   -24.61mA
1.012V    -31.48mA   -30.47mA   -27.88mA
1.527V    -36.56mA   -34.86mA   -31.63mA
2.369V    -40.49mA   -38.32mA   -34.61mA
2.457V    -42.47mA   -38.59mA   -34.86mA
2.502V    -40.86mA   -38.73mA   -34.98mA
2.7V      -41.47mA   -39.31mA   -36.73mA
[Pulldown]
| Voltage   I(typ)   I(min)   I(max)
-1.35V    -30.69mA   -26.08mA   -25.52mA
-1.24V    -31.42mA   -27.29mA   -21.96mA
-1.152V   -30.96mA   -27.97mA   -20.96mA
-1.107V   -30.04mA   -28.15mA   -20.6mA
-1.019V   -25.57mA   -28.04mA   -19.94mA
-575.9mV  -18.94mA   -20.28mA   -16.17mA
-354.4mV  -13.47mA   -13.99mA   -11.94mA
548.4mV   19.87mA    20.28mA    17.83mA
843.8mV   28.69mA    28.36mA    26.16mA
1.055V    33.3mA     31.47mA    31.05mA
1.394V    36.18mA    32.97mA    35.06mA
2.7V      38.96mA    35.29mA    37.94mA
[Ramp]
dV/dt_r   0.521067/0.112898n  0.496233/0.117939n  0.530878/0.133918n
dV/dt_f   0.523964/0.100501n  0.503432/99.9274p  0.526733/0.10149n
R_load = 50
[Rising Waveform]
R_fixture = 50
V_fixture = 0
V_fixture_min = 0
V_fixture_max = 0
| Time   V(typ)   V(min)   V(max)
0s        1.375uV    2.322uV    1.97uV
1.008ns   -825.8uV   -550.6uV   -6.065mV
1.066ns   -873.4uV   -582.5uV   100.3mV
1.204ns   -986.7uV   -658.2uV   675.7mV
1.311ns   -1.471mV   -716.9uV   839.8mV
1.496ns   712.6mV    -818.4uV   876.7mV
1.739ns   858.3mV    9.205mV    882.9mV
1.94ns    865.7mV    723.5mV    883.5mV
2.149ns   867.1mV    816.1mV    883.9mV
10ns      868.4mV    827.1mV    884.8mV
[Rising Waveform]
R_fixture = 50
V_fixture = 1.35
V_fixture_min = 1.2825
V_fixture_max = 1.4175
| Time   V(typ)   V(min)   V(max)
0s        476.7mV    443.4mV    539.6mV
925ps     477.2mV    443.8mV    545.6mV
1.102ns   477.2mV    443.9mV    1.296V
1.241ns   494.2mV    443.9mV    1.4V
1.296ns   705.5mV    444mV      1.407V
1.433ns   1.281V     444mV      1.414V
1.674ns   1.344V     472.5mV    1.416V
1.838ns   1.348V     1.186V     1.416V
2.013ns   1.348V     1.271V     1.417V
10ns      1.35V      1.282V     1.417V
[Falling Waveform]
R_fixture = 50
V_fixture = 0
V_fixture_min = 0
V_fixture_max = 0
| Time   V(typ)   V(min)   V(max)
0s        868.5mV    827.1mV    884.8mV
910ps     867.9mV    826.5mV    872.7mV
1.052ns   867.8mV    826.5mV    148.9mV
1.254ns   831.5mV    826.3mV    9.405mV
1.384ns   137.9mV    826.3mV    4.099mV
1.573ns   9.225mV    826.1mV    1.847mV
1.71ns    3.838mV    745.7mV    1.399mV
1.836ns   2.156mV    102.5mV    1.192mV
2.014ns   1.405mV    8.694mV    900.6uV
10ns      2.191uV    3.888uV    3.022uV
[Falling Waveform]
R_fixture = 50
V_fixture = 1.35
V_fixture_min = 1.2825
V_fixture_max = 1.4175
| Time   V(typ)   V(min)   V(max)
0s        1.35V      1.282V     1.417V
983ps     1.351V     1.283V     1.422V
1.152ns   1.351V     1.283V     700.6mV
1.36ns    1.203V     1.283V     550.5mV
1.465ns   655.7mV    1.283V     544.7mV
1.527ns   534.5mV    1.283V     543.3mV
1.754ns   482.4mV    1.242V     541.7mV
1.894ns   479.5mV    609.2mV    541.3mV
2.086ns   478.5mV    453.9mV    540.7mV
10ns      476.7mV    443.4mV    539.6mV
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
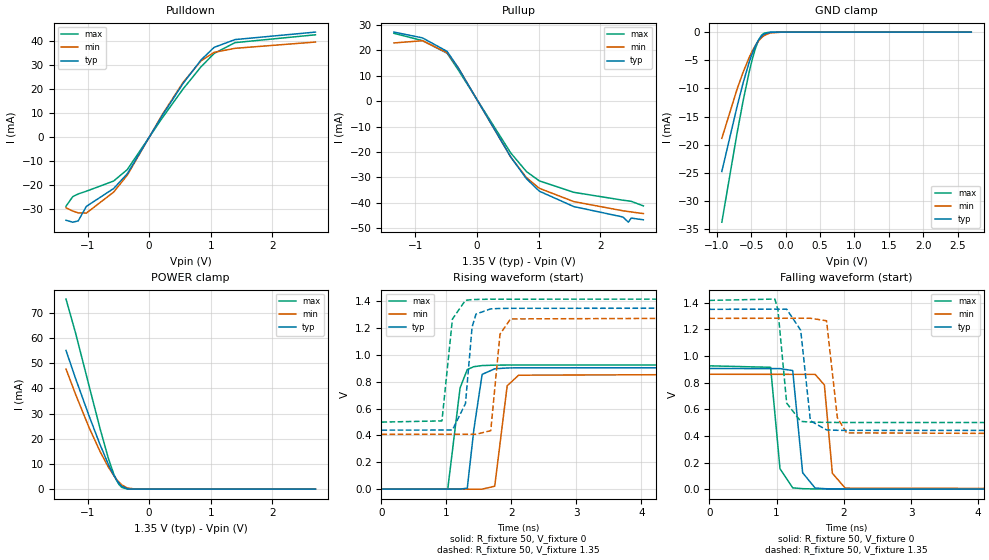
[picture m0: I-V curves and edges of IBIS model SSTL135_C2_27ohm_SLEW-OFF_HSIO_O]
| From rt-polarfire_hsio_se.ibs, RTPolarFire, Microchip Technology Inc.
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|   Model SSTL135_C2_27ohm_SLEW-OFF_HSIO_O
[Model]   SSTL135_C2_27ohm_SLEW-OFF_HSIO_O
Model_type   Output
Polarity   Non-Inverting
Enable   Active-High
Vmeas =   0.675
Cref =   5p
Rref =   50
Vref =   0.675
|   typ   min   max
C_comp_pullup   1.335e-12   1.335e-12   1.380e-12
C_comp_pulldown  1.335e-12   1.335e-12   1.380e-12
[Temperature Range]  25C   125C   -55C
[Voltage Range]  1.35   1.2825   1.4175
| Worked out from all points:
|   slope of the pulldown table from 0 to 0.203 V, typ, clamps not added: 23.4 ohm
|   slope of the pullup table from 0 to 0.203 V, typ, clamps not added: 23.9 ohm
|   GND clamp passes 1 mA (typ) near -0.37 V on its own axis
|   POWER clamp passes 1 mA (typ) near -0.43 V on its own axis
|   rising waveform, R_fixture 50, V_fixture 0: 20-80 % time 107ps typ, 111ps min, 123ps max; typ from 0 V to 0.906 V
|   rising waveform, R_fixture 50, V_fixture 1.35: 20-80 % time 95ps typ, 86.6ps min, 103ps max; typ from 0.439 V to 1.35 V
|   falling waveform, R_fixture 50, V_fixture 0: 20-80 % time 83.4ps typ, 82.4ps min, 87.7ps max; typ from 0.906 V to 0 V
|   falling waveform, R_fixture 50, V_fixture 1.35: 20-80 % time 95.1ps typ, 97ps min, 95.6ps max; typ from 1.35 V to 0.439 V
[GND Clamp]
| Voltage   I(typ)   I(min)   I(max)
-930.2mV  -24.71mA   -18.84mA   -33.71mA
-708.7mV  -13.23mA   -10.13mA   -17.94mA
-620.2mV  -8.998mA   -7.114mA   -12.18mA
-531.6mV  -5.316mA   -4.482mA   -7.044mA
-487.3mV  -3.767mA   -3.362mA   -4.833mA
-443mV    -2.466mA   -2.401mA   -2.954mA
-398.7mV  -1.449mA   -1.613mA   -1.504mA
-354.4mV  -738.4uA   -1.007mA   -579.6uA
-310.1mV  -318.4uA   -576.7uA   -161.6uA
-221.5mV  -38.75uA   -142.9uA   -7.637uA
-44.3mV   -274.4nA   -3.251uA   -69.5nA
2.7V      0A         0A         0A
[POWER Clamp]
| Voltage   I(typ)   I(min)   I(max)
-1.35V    55.07mA    47.72mA    75.49mA
-1.196V   44.05mA    37.75mA    62.13mA
-974.5mV  29.03mA    24.41mA    40.95mA
-797.3mV  17.68mA    14.97mA    24.06mA
-664.5mV  10.01mA    8.871mA    12.44mA
-575.9mV  5.63mA     5.451mA    6.064mA
-531.6mV  3.786mA    3.983mA    3.599mA
-487.3mV  2.262mA    2.712mA    1.789mA
-443mV    1.133mA    1.675mA    684.4uA
-354.4mV  127.5uA    473.3uA    30.46uA
-221.5mV  1.715uA    56.89uA    636.6nA
2.7V      0A         0A         0A
[Pullup]
| Voltage   I(typ)   I(min)   I(max)
-1.35V    27.07mA    22.81mA    26.59mA
-885.9mV  24.79mA    23.68mA    23.72mA
-487.3mV  19.51mA    18.98mA    18.8mA
-310.1mV  13.21mA    13.23mA    12.4mA
548.4mV   -22.04mA   -22.06mA   -20.44mA
801.6mV   -30.5mA    -30.06mA   -27.69mA
1.012V    -35.41mA   -34.28mA   -31.36mA
1.571V    -41.44mA   -39.49mA   -35.84mA
2.369V    -45.54mA   -43.09mA   -38.94mA
2.457V    -47.57mA   -43.39mA   -39.22mA
2.502V    -45.96mA   -43.54mA   -39.36mA
2.7V      -46.63mA   -44.19mA   -41.18mA
[Pulldown]
| Voltage   I(typ)   I(min)   I(max)
-1.35V    -34.53mA   -29.34mA   -28.69mA
-1.24V    -35.34mA   -30.69mA   -24.69mA
-1.152V   -34.81mA   -31.46mA   -23.58mA
-1.019V   -28.75mA   -31.54mA   -22.43mA
-575.9mV  -21.31mA   -22.8mA    -18.19mA
-354.4mV  -15.15mA   -15.74mA   -13.42mA
210.9mV   9.007mA    9.358mA    8.001mA
548.4mV   22.34mA    22.8mA     20.05mA
843.8mV   32.26mA    31.89mA    29.42mA
1.055V    37.46mA    35.38mA    34.91mA
1.394V    40.7mA     37.06mA    39.43mA
2.7V      43.82mA    39.68mA    42.69mA
[Ramp]
dV/dt_r   0.543411/0.106968n  0.517475/0.110649n  0.555498/0.12294n
dV/dt_f   0.546308/95.1117p  0.52465/97.028p  0.550933/95.5937p
R_load = 50
[Rising Waveform]
R_fixture = 50
V_fixture = 0
V_fixture_min = 0
V_fixture_max = 0
| Time   V(typ)   V(min)   V(max)
0s        1.372uV    2.236uV    1.954uV
1.021ns   -680.2uV   -545uV     2.332mV
1.21ns    -806.4uV   -646.3uV   754.7mV
1.321ns   7.099mV    -705.8uV   891.4mV
1.422ns   443.9mV    -760uV     912.8mV
1.549ns   855.2mV    -828.1uV   921mV
1.743ns   897.1mV    21.36mV    924.1mV
1.935ns   903.1mV    770.7mV    924.8mV
2.111ns   904.3mV    849.2mV    924.9mV
10ns      905.7mV    862.5mV    925.8mV
[Rising Waveform]
R_fixture = 50
V_fixture = 1.35
V_fixture_min = 1.2825
V_fixture_max = 1.4175
| Time   V(typ)   V(min)   V(max)
0s        439.5mV    408.1mV    499.3mV
931ps     440.2mV    408.5mV    508.3mV
1.092ns   440.3mV    408.5mV    1.268V
1.293ns   637.8mV    408.6mV    1.408V
1.395ns   1.209V     408.7mV    1.413V
1.455ns   1.305V     408.7mV    1.414V
1.682ns   1.344V     435.5mV    1.416V
1.824ns   1.347V     1.155V     1.416V
1.987ns   1.348V     1.269V     1.416V
10ns      1.35V      1.282V     1.417V
[Falling Waveform]
R_fixture = 50
V_fixture = 0
V_fixture_min = 0
V_fixture_max = 0
| Time   V(typ)   V(min)   V(max)
0s        905.7mV    862.5mV    925.8mV
911ps     905mV      862mV      914.8mV
1.051ns   904.9mV    861.9mV    153.3mV
1.24ns    890.3mV    861.8mV    9.969mV
1.388ns   122.9mV    861.8mV    3.624mV
1.573ns   8.775mV    861.7mV    1.731mV
1.711ns   3.69mV     782.7mV    1.39mV
1.83ns    2.066mV    119.3mV    1.096mV
2.021ns   1.282mV    7.722mV    745.6uV
10ns      2.222uV    3.818uV    2.69uV
[Falling Waveform]
R_fixture = 50
V_fixture = 1.35
V_fixture_min = 1.2825
V_fixture_max = 1.4175
| Time   V(typ)   V(min)   V(max)
0s        1.35V      1.282V     1.417V
975ps     1.351V     1.283V     1.427V
1.02ns    1.351V     1.283V     1.346V
1.15ns    1.351V     1.283V     646.2mV
1.359ns   1.193V     1.283V     509.1mV
1.503ns   513.4mV    1.283V     503.1mV
1.743ns   444.9mV    1.264V     501.3mV
1.904ns   441.9mV    537.1mV    500.8mV
2.041ns   441.3mV    422.7mV    500.5mV
10ns      439.5mV    408mV      499.3mV
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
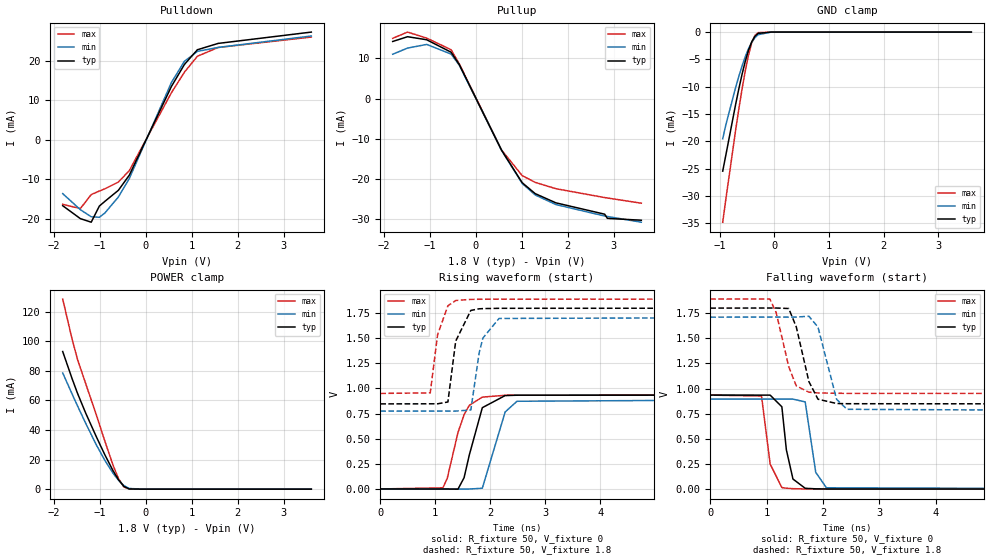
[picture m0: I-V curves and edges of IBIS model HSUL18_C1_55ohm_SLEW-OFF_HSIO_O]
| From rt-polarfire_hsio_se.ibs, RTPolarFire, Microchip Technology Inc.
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|   Model HSUL18_C1_55ohm_SLEW-OFF_HSIO_O
[Model]   HSUL18_C1_55ohm_SLEW-OFF_HSIO_O
Model_type   Output
Polarity   Non-Inverting
Enable   Active-High
Vmeas =   0.9
Cref =   5p
Rref =   50
Vref =   0.9
|   typ   min   max
C_comp_pullup   1.335e-12   1.335e-12   1.380e-12
C_comp_pulldown  1.335e-12   1.335e-12   1.380e-12
[Temperature Range]  25C   125C   -55C
[Voltage Range]  1.8   1.71   1.89
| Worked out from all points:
|   slope of the pulldown table from 0 to 0.27 V, typ, clamps not added: 40 ohm
|   slope of the pullup table from 0 to 0.27 V, typ, clamps not added: 42.5 ohm
|   GND clamp passes 1 mA (typ) near -0.37 V on its own axis
|   POWER clamp passes 1 mA (typ) near -0.43 V on its own axis
|   rising waveform, R_fixture 50, V_fixture 0: 20-80 % time 253ps typ, 256ps min, 275ps max; typ from 0 V to 0.936 V
|   rising waveform, R_fixture 50, V_fixture 1.8: 20-80 % time 170ps typ, 175ps min, 163ps max; typ from 0.847 V to 1.8 V
|   falling waveform, R_fixture 50, V_fixture 0: 20-80 % time 137ps typ, 138ps min, 130ps max; typ from 0.936 V to 0 V
|   falling waveform, R_fixture 50, V_fixture 1.8: 20-80 % time 241ps typ, 244ps min, 241ps max; typ from 1.8 V to 0.847 V
[GND Clamp]
| Voltage   I(typ)   I(min)   I(max)
-945mV    -25.47mA   -19.54mA   -34.82mA
-885.9mV  -22.44mA   -16.92mA   -30.49mA
-708.7mV  -13.24mA   -10.14mA   -17.96mA
-649.7mV  -10.37mA   -8.095mA   -14.06mA
-590.6mV  -7.705mA   -6.193mA   -10.39mA
-531.6mV  -5.322mA   -4.488mA   -7.054mA
-472.5mV  -3.308mA   -3.028mA   -4.171mA
-413.4mV  -1.757mA   -1.859mA   -1.935mA
-354.4mV  -739.5uA   -1.008mA   -580.7uA
-295.3mV  -232.3uA   -469.6uA   -100.4uA
-59.06mV  -489.8nA   -5.037uA   -176.4nA
3.6V      0A         0A         0A
[POWER Clamp]
| Voltage   I(typ)   I(min)   I(max)
-1.8V     93.11mA    78.62mA    128.6mA
-1.595V   74.64mA    64.3mA     101.3mA
-1.477V   64.73mA    56.26mA    87.68mA
-1.299V   51.32mA    44.43mA    71.22mA
-1.063V   35.01mA    29.59mA    49.65mA
-885.9mV  23.32mA    19.56mA    32.61mA
-708.7mV  12.62mA    10.87mA    16.4mA
-590.6mV  6.476mA    6.104mA    7.295mA
-472.5mV  1.932mA    2.452mA    1.539mA
-354.4mV  154uA      480.4uA    74.19uA
-59.06mV  800.7nA    2.877uA    466.9nA
3.6V      0A         0A         0A
[Pullup]
| Voltage   I(typ)   I(min)   I(max)
-1.8V     14.21mA    11.04mA    15mA
-1.477V   15.4mA     12.56mA    16.55mA
-1.063V   14.64mA    13.48mA    15.05mA
-531.6mV  11.54mA    11.08mA    12.16mA
-354.4mV  8.453mA    8.316mA    8.652mA
562.5mV   -12.83mA   -12.86mA   -12.78mA
1.012V    -20.95mA   -21.14mA   -19.19mA
1.294V    -23.67mA   -24mA      -20.87mA
1.744V    -25.97mA   -26.4mA    -22.45mA
2.804V    -28.8mA    -29.26mA   -24.66mA
2.863V    -29.84mA   -29.37mA   -24.76mA
3.6V      -30.3mA    -30.79mA   -26.06mA
[Pulldown]
| Voltage   I(typ)   I(min)   I(max)
-1.8V     -16.63mA   -13.58mA   -16.28mA
-1.417V   -19.89mA   -17.63mA   -17.35mA
-1.181V   -20.79mA   -19.42mA   -13.83mA
-1.004V   -16.72mA   -19.55mA   -12.92mA
-885.9mV  -15.55mA   -18.49mA   -12.38mA
-590.6mV  -12.74mA   -14.43mA   -10.65mA
-354.4mV  -8.939mA   -9.791mA   -7.787mA
562.5mV   13.49mA    14.5mA     11.91mA
843.8mV   19.02mA    19.82mA    17.07mA
1.125V    22.73mA    22.32mA    21.09mA
1.575V    24.33mA    23.32mA    23.3mA
3.6V      27.19mA    26.2mA     25.94mA
[Ramp]
dV/dt_r   0.561316/0.252913n  0.537467/0.256327n  0.560928/0.274704n
dV/dt_f   0.571987/0.241065n  0.561263/0.243673n  0.563385/0.240506n
R_load = 50
[Rising Waveform]
R_fixture = 50
V_fixture = 0
V_fixture_min = 0
V_fixture_max = 0
| Time   V(typ)   V(min)   V(max)
0s        2.497uV    4.055uV    4.043uV
1.139ns   -703.8uV   -443.3uV   11.29mV
1.218ns   -752.8uV   -474.3uV   105.9mV
1.413ns   -2.078mV   -550.9uV   561mV
1.524ns   111.7mV    -594.5uV   739mV
1.62ns    339.6mV    -632.2uV   833mV
1.856ns   809mV      7.38mV     914.1mV
2.271ns   929.4mV    766.1mV    932.2mV
2.487ns   933mV      872.8mV    933.3mV
10ns      935.5mV    895.8mV    934.9mV
[Rising Waveform]
R_fixture = 50
V_fixture = 1.8
V_fixture_min = 1.71
V_fixture_max = 1.89
| Time   V(typ)   V(min)   V(max)
0s        846.7mV    774.5mV    951mV
909ps     847.4mV    774.9mV    956.1mV
1.042ns   847.5mV    774.9mV    1.535V
1.23ns    865.9mV    775mV      1.823V
1.372ns   1.472V     775mV      1.876V
1.647ns   1.777V     785.9mV    1.887V
1.798ns   1.793V     1.354V     1.888V
1.867ns   1.795V     1.502V     1.888V
2.16ns    1.798V     1.697V     1.889V
10ns      1.8V       1.71V      1.89V
[Falling Waveform]
R_fixture = 50
V_fixture = 0
V_fixture_min = 0
V_fixture_max = 0
| Time   V(typ)   V(min)   V(max)
0s        935.6mV    895.8mV    934.9mV
909ps     935.1mV    895.3mV    926.4mV
1.062ns   935mV      895.2mV    250.9mV
1.27ns    819mV      895.1mV    15.71mV
1.35ns    391.3mV    895.1mV    9.517mV
1.467ns   100.7mV    895mV      5.078mV
1.684ns   8.802mV    867.8mV    2.063mV
1.871ns   3.343mV    167.5mV    1.393mV
2.061ns   1.769mV    13.64mV    1.098mV
10ns      4.439uV    5.632uV    5.008uV
[Falling Waveform]
R_fixture = 50
V_fixture = 1.8
V_fixture_min = 1.71
V_fixture_max = 1.89
| Time   V(typ)   V(min)   V(max)
0s        1.8V       1.71V      1.89V
1.058ns   1.801V     1.711V     1.89V
1.171ns   1.801V     1.711V     1.752V
1.392ns   1.796V     1.711V     1.217V
1.526ns   1.613V     1.711V     1.027V
1.75ns    1.069V     1.719V     964mV
1.911ns   894.3mV    1.611V     956.9mV
2.241ns   851.8mV    893.4mV    953.3mV
2.426ns   849.6mV    793.8mV    952.4mV
10ns      846.7mV    774.5mV    951mV
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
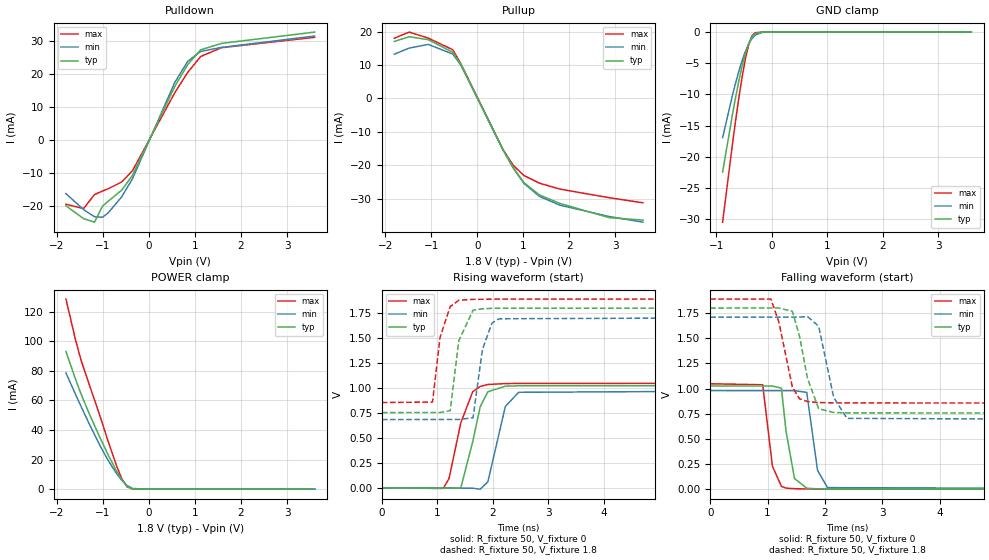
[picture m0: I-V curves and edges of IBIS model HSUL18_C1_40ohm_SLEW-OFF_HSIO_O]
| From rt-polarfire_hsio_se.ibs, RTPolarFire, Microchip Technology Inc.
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|   Model HSUL18_C1_40ohm_SLEW-OFF_HSIO_O
[Model]   HSUL18_C1_40ohm_SLEW-OFF_HSIO_O
Model_type   Output
Polarity   Non-Inverting
Enable   Active-High
Vmeas =   0.9
Cref =   5p
Rref =   50
Vref =   0.9
|   typ   min   max
C_comp_pullup   1.335e-12   1.335e-12   1.380e-12
C_comp_pulldown  1.335e-12   1.335e-12   1.380e-12
[Temperature Range]  25C   125C   -55C
[Voltage Range]  1.8   1.71   1.89
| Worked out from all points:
|   slope of the pulldown table from 0 to 0.27 V, typ, clamps not added: 33.3 ohm
|   slope of the pullup table from 0 to 0.27 V, typ, clamps not added: 35.4 ohm
|   GND clamp passes 1 mA (typ) near -0.37 V on its own axis
|   POWER clamp passes 1 mA (typ) near -0.43 V on its own axis
|   rising waveform, R_fixture 50, V_fixture 0: 20-80 % time 230ps typ, 232ps min, 258ps max; typ from 0 V to 1.03 V
|   rising waveform, R_fixture 50, V_fixture 1.8: 20-80 % time 169ps typ, 178ps min, 162ps max; typ from 0.755 V to 1.8 V
|   falling waveform, R_fixture 50, V_fixture 0: 20-80 % time 138ps typ, 132ps min, 129ps max; typ from 1.03 V to 0 V
|   falling waveform, R_fixture 50, V_fixture 1.8: 20-80 % time 221ps typ, 221ps min, 219ps max; typ from 1.8 V to 0.755 V
[GND Clamp]
| Voltage   I(typ)   I(min)   I(max)
-885.9mV  -22.44mA   -16.92mA   -30.49mA
-708.7mV  -13.24mA   -10.14mA   -17.96mA
-649.7mV  -10.37mA   -8.095mA   -14.06mA
-590.6mV  -7.705mA   -6.193mA   -10.39mA
-531.6mV  -5.322mA   -4.488mA   -7.054mA
-472.5mV  -3.308mA   -3.028mA   -4.171mA
-413.4mV  -1.757mA   -1.859mA   -1.935mA
-354.4mV  -739.5uA   -1.008mA   -580.7uA
-295.3mV  -232.3uA   -469.6uA   -100.4uA
-177.2mV  -12.01uA   -62.89uA   -1.688uA
-59.06mV  -489.8nA   -5.037uA   -176.4nA
3.6V      0A         0A         0A
[POWER Clamp]
| Voltage   I(typ)   I(min)   I(max)
-1.8V     93.11mA    78.62mA    128.6mA
-1.595V   74.64mA    64.3mA     101.3mA
-1.477V   64.73mA    56.26mA    87.68mA
-1.299V   51.32mA    44.43mA    71.22mA
-1.063V   35.01mA    29.59mA    49.65mA
-885.9mV  23.32mA    19.56mA    32.61mA
-708.7mV  12.62mA    10.87mA    16.4mA
-590.6mV  6.476mA    6.104mA    7.295mA
-472.5mV  1.932mA    2.452mA    1.539mA
-354.4mV  154uA      480.4uA    74.19uA
-59.06mV  800.7nA    2.877uA    466.9nA
3.6V      0A         0A         0A
[Pullup]
| Voltage   I(typ)   I(min)   I(max)
-1.8V     17.05mA    13.25mA    18.01mA
-1.477V   18.48mA    15.07mA    19.86mA
-1.063V   17.57mA    16.18mA    18.06mA
-531.6mV  13.85mA    13.29mA    14.59mA
-354.4mV  10.14mA    9.979mA    10.38mA
562.5mV   -15.4mA    -15.43mA   -15.33mA
787.5mV   -20.82mA   -20.9mA    -20.08mA
1.012V    -25.14mA   -25.36mA   -23.02mA
1.35V     -28.85mA   -29.28mA   -25.33mA
1.8V      -31.41mA   -31.94mA   -27.12mA
2.863V    -35.64mA   -35.3mA    -29.68mA
3.6V      -36.4mA    -37.01mA   -31.21mA
[Pulldown]
| Voltage   I(typ)   I(min)   I(max)
-1.8V     -19.98mA   -16.31mA   -19.53mA
-1.417V   -23.89mA   -21.16mA   -20.83mA
-1.181V   -24.96mA   -23.31mA   -16.6mA
-1.004V   -20.05mA   -23.46mA   -15.5mA
-885.9mV  -18.64mA   -22.18mA   -14.85mA
-590.6mV  -15.28mA   -17.3mA    -12.78mA
-354.4mV  -10.72mA   -11.75mA   -9.335mA
562.5mV   16.17mA    17.4mA     14.28mA
843.8mV   22.82mA    23.8mA     20.46mA
1.125V    27.3mA     26.81mA    25.27mA
1.575V    29.24mA    28.02mA    27.93mA
3.6V      32.67mA    31.47mA    31.09mA
[Ramp]
dV/dt_r   0.615373/0.229559n  0.587583/0.231665n  0.628941/0.258203n
dV/dt_f   0.626727/0.220526n  0.614625/0.221337n  0.620625/0.218793n
R_load = 50
[Rising Waveform]
R_fixture = 50
V_fixture = 0
V_fixture_min = 0
V_fixture_max = 0
| Time   V(typ)   V(min)   V(max)
0s        2.38uV     3.756uV    3.825uV
1.108ns   -758.4uV   -650.8uV   -2.721mV
1.212ns   -829.8uV   -712.3uV   96.25mV
1.425ns   3.307mV    -838.1uV   653.8mV
1.64ns    465.8mV    -1.127mV   964mV
1.775ns   814.1mV    -10.32mV   1.017V
1.913ns   963.8mV    62.86mV    1.036V
2.228ns   1.019V     816.5mV    1.045V
2.468ns   1.023V     958.1mV    1.047V
10ns      1.026V     979.3mV    1.048V
[Rising Waveform]
R_fixture = 50
V_fixture = 1.8
V_fixture_min = 1.71
V_fixture_max = 1.89
| Time   V(typ)   V(min)   V(max)
0s        755.4mV    685.6mV    855.6mV
914ps     756.1mV    686.1mV    860.7mV
1.05ns    756.2mV    686.2mV    1.507V
1.233ns   774.4mV    686.3mV    1.815V
1.388ns   1.473V     686.4mV    1.878V
1.645ns   1.778V     703.4mV    1.887V
1.815ns   1.793V     1.388V     1.888V
1.987ns   1.797V     1.65V      1.889V
2.116ns   1.798V     1.693V     1.889V
10ns      1.8V       1.71V      1.89V
[Falling Waveform]
R_fixture = 50
V_fixture = 0
V_fixture_min = 0
V_fixture_max = 0
| Time   V(typ)   V(min)   V(max)
0s        1.026V     979.4mV    1.048V
915ps     1.025V     978.9mV    1.038V
1.084ns   1.025V     978.8mV    228.5mV
1.241ns   1.004V     978.8mV    28.34mV
1.321ns   576.4mV    978.7mV    10.35mV
1.469ns   106mV      978.7mV    4.903mV
1.682ns   9.04mV     962.3mV    2.112mV
1.87ns    3.221mV    187.3mV    1.548mV
2.043ns   1.881mV    15.33mV    1.08mV
10ns      3.582uV    5.045uV    4.578uV
[Falling Waveform]
R_fixture = 50
V_fixture = 1.8
V_fixture_min = 1.71
V_fixture_max = 1.89
| Time   V(typ)   V(min)   V(max)
0s        1.8V       1.71V      1.89V
1.058ns   1.801V     1.711V     1.89V
1.197ns   1.801V     1.711V     1.661V
1.431ns   1.768V     1.711V     1.016V
1.556ns   1.522V     1.711V     898.7mV
1.697ns   1.098V     1.715V     870mV
1.89ns    799.9mV    1.62V      861.2mV
2.152ns   762.3mV    911.5mV    858.1mV
2.383ns   758.5mV    703.9mV    857.1mV
10ns      755.4mV    685.6mV    855.6mV
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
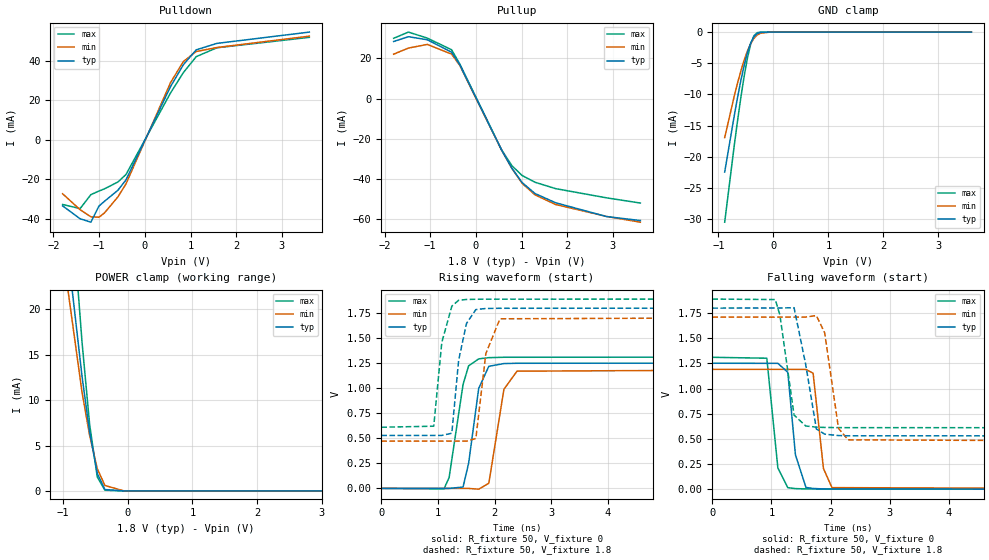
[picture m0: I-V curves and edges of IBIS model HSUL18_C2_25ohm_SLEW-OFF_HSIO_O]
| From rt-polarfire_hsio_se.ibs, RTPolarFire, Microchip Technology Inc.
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|   Model HSUL18_C2_25ohm_SLEW-OFF_HSIO_O
[Model]   HSUL18_C2_25ohm_SLEW-OFF_HSIO_O
Model_type   Output
Polarity   Non-Inverting
Enable   Active-High
Vmeas =   0.9
Cref =   5p
Rref =   50
Vref =   0.9
|   typ   min   max
C_comp_pullup   1.335e-12   1.335e-12   1.380e-12
C_comp_pulldown  1.335e-12   1.335e-12   1.380e-12
[Temperature Range]  25C   125C   -55C
[Voltage Range]  1.8   1.71   1.89
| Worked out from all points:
|   slope of the pulldown table from 0 to 0.27 V, typ, clamps not added: 20 ohm
|   slope of the pullup table from 0 to 0.27 V, typ, clamps not added: 21.3 ohm
|   GND clamp passes 1 mA (typ) near -0.37 V on its own axis
|   POWER clamp passes 1 mA (typ) near -0.43 V on its own axis
|   rising waveform, R_fixture 50, V_fixture 0: 20-80 % time 179ps typ, 187ps min, 203ps max; typ from 0 V to 1.25 V
|   rising waveform, R_fixture 50, V_fixture 1.8: 20-80 % time 166ps typ, 173ps min, 159ps max; typ from 0.528 V to 1.8 V
|   falling waveform, R_fixture 50, V_fixture 0: 20-80 % time 131ps typ, 126ps min, 126ps max; typ from 1.25 V to 0 V
|   falling waveform, R_fixture 50, V_fixture 1.8: 20-80 % time 170ps typ, 172ps min, 171ps max; typ from 1.8 V to 0.528 V
[GND Clamp]
| Voltage   I(typ)   I(min)   I(max)
-885.9mV  -22.44mA   -16.92mA   -30.49mA
-708.7mV  -13.24mA   -10.14mA   -17.96mA
-649.7mV  -10.37mA   -8.095mA   -14.06mA
-590.6mV  -7.705mA   -6.193mA   -10.39mA
-531.6mV  -5.322mA   -4.488mA   -7.054mA
-472.5mV  -3.308mA   -3.028mA   -4.171mA
-413.4mV  -1.757mA   -1.859mA   -1.935mA
-354.4mV  -739.5uA   -1.008mA   -580.7uA
-295.3mV  -232.3uA   -469.6uA   -100.4uA
-236.2mV  -56.73uA   -185.1uA   -13.11uA
-59.06mV  -489.8nA   -5.037uA   -176.4nA
3.6V      0A         0A         0A
[POWER Clamp]
| Voltage   I(typ)   I(min)   I(max)
-1.8V     93.11mA    78.61mA    128.6mA
-1.713V   85.12mA    72.5mA     116.7mA
-1.536V   69.6mA     60.25mA    94.32mA
-1.477V   64.73mA    56.22mA    87.68mA
-1.358V   55.61mA    48.31mA    76.35mA
-1.004V   31.04mA    26.13mA    43.96mA
-708.7mV  12.62mA    10.87mA    16.4mA
-590.6mV  6.476mA    6.104mA    7.295mA
-472.5mV  1.932mA    2.452mA    1.539mA
-354.4mV  154uA      598.2uA    74.19uA
-59.06mV  800.7nA    2.877uA    466.9nA
3.6V      0A         0A         0A
[Pullup]
| Voltage   I(typ)   I(min)   I(max)
-1.8V     28.42mA    22.1mA     30.02mA
-1.477V   30.81mA    25.15mA    33.11mA
-1.063V   29.29mA    26.96mA    30.1mA
-531.6mV  23.08mA    22.15mA    24.3mA
-354.4mV  16.9mA     16.53mA    17.29mA
562.5mV   -25.66mA   -25.71mA   -25.55mA
787.5mV   -34.69mA   -34.83mA   -33.45mA
1.012V    -41.89mA   -42.26mA   -38.36mA
1.294V    -47.33mA   -47.99mA   -41.72mA
1.744V    -51.93mA   -52.8mA    -44.89mA
2.863V    -58.83mA   -58.77mA   -49.5mA
3.6V      -60.8mA    -61.62mA   -52.08mA
[Pulldown]
| Voltage   I(typ)   I(min)   I(max)
-1.8V     -33.34mA   -27.21mA   -32.63mA
-1.417V   -39.84mA   -35.29mA   -34.71mA
-1.181V   -41.58mA   -38.86mA   -27.65mA
-1.004V   -33.4mA    -39.08mA   -25.83mA
-885.9mV  -31.06mA   -36.95mA   -24.75mA
-590.6mV  -25.46mA   -28.82mA   -21.28mA
-413.4mV  -20.23mA   -22.25mA   -17.5mA
562.5mV   26.94mA    28.96mA    23.75mA
843.8mV   38.03mA    39.63mA    34.04mA
1.125V    45.52mA    44.66mA    42.08mA
1.575V    48.76mA    46.68mA    46.54mA
3.6V      54.48mA    52.43mA    51.82mA
[Ramp]
dV/dt_r   0.751089/0.178842n  0.714691/0.18663n  0.786452/0.202576n
dV/dt_f   0.763086/0.169686n  0.743241/0.172496n  0.767779/0.171069n
R_load = 50
[Rising Waveform]
R_fixture = 50
V_fixture = 0
V_fixture_min = 0
V_fixture_max = 0
| Time   V(typ)   V(min)   V(max)
0s        2.078uV    3.004uV    3.254uV
1.105ns   -408.5uV   -461.4uV   -5.449mV
1.196ns   -442.3uV   -499.6uV   107.8mV
1.442ns   13.41mV    -603uV     1.037V
1.54ns    249.5mV    -644.2uV   1.223V
1.718ns   997.7mV    -7.867mV   1.293V
1.897ns   1.219V     51.43mV    1.305V
2.163ns   1.246V     989.2mV    1.309V
2.394ns   1.249V     1.17V      1.309V
10ns      1.252V     1.191V     1.311V
[Rising Waveform]
R_fixture = 50
V_fixture = 1.8
V_fixture_min = 1.71
V_fixture_max = 1.89
| Time   V(typ)   V(min)   V(max)
0s        528.2mV    471.2mV    610.4mV
925ps     528.5mV    471.8mV    620.7mV
1.067ns   528.6mV    471.8mV    1.457V
1.244ns   550.7mV    471.9mV    1.819V
1.364ns   1.279V     472mV      1.878V
1.504ns   1.648V     472.1mV    1.886V
1.668ns   1.785V     497.6mV    1.888V
1.844ns   1.796V     1.345V     1.889V
2.093ns   1.798V     1.693V     1.889V
10ns      1.8V       1.71V      1.89V
[Falling Waveform]
R_fixture = 50
V_fixture = 0
V_fixture_min = 0
V_fixture_max = 0
| Time   V(typ)   V(min)   V(max)
0s        1.252V     1.191V     1.311V
921ps     1.251V     1.191V     1.302V
1.108ns   1.251V     1.191V     211mV
1.276ns   1.162V     1.191V     14.78mV
1.405ns   341.4mV    1.19V      5.518mV
1.583ns   17.19mV    1.19V      2.673mV
1.704ns   6.805mV    1.153V     1.712mV
1.879ns   2.514mV    205.3mV    1.378mV
2.023ns   1.681mV    15.28mV    1.114mV
10ns      2.882uV    3.888uV    3.886uV
[Falling Waveform]
R_fixture = 50
V_fixture = 1.8
V_fixture_min = 1.71
V_fixture_max = 1.89
| Time   V(typ)   V(min)   V(max)
0s        1.8V       1.71V      1.89V
1.064ns   1.801V     1.71V      1.885V
1.142ns   1.801V     1.711V     1.732V
1.382ns   1.804V     1.711V     736.4mV
1.579ns   1.239V     1.711V     628.1mV
1.759ns   598.5mV    1.726V     616.6mV
1.9ns     547mV      1.554V     613.6mV
2.133ns   532.9mV    604.7mV    611.9mV
2.295ns   530.7mV    490.5mV    611.5mV
10ns      528.2mV    471.2mV    610.4mV
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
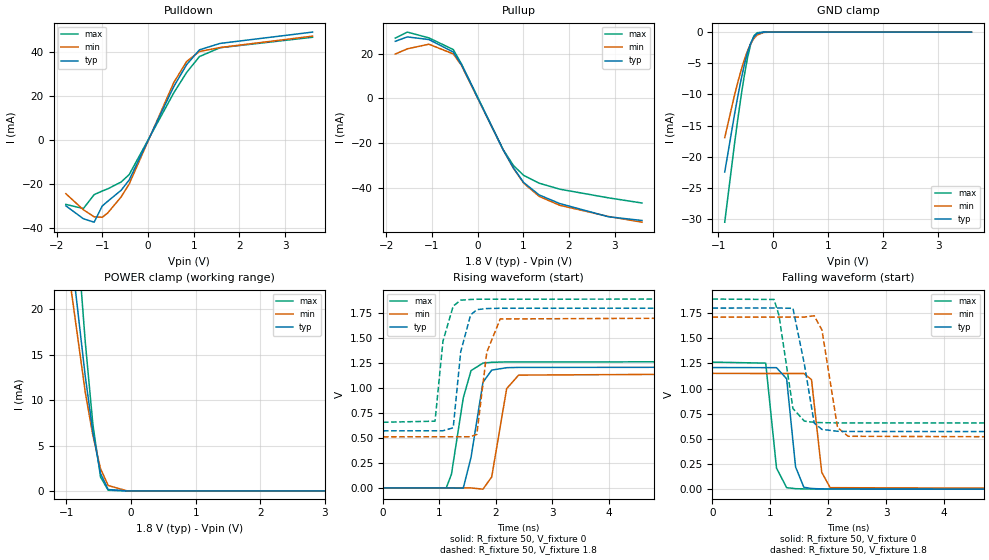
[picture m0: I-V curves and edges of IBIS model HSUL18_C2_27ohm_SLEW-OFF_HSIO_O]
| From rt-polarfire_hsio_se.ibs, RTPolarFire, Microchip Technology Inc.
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|   Model HSUL18_C2_27ohm_SLEW-OFF_HSIO_O
[Model]   HSUL18_C2_27ohm_SLEW-OFF_HSIO_O
Model_type   Output
Polarity   Non-Inverting
Enable   Active-High
Vmeas =   0.9
Cref =   5p
Rref =   50
Vref =   0.9
|   typ   min   max
C_comp_pullup   1.335e-12   1.335e-12   1.380e-12
C_comp_pulldown  1.335e-12   1.335e-12   1.380e-12
[Temperature Range]  25C   125C   -55C
[Voltage Range]  1.8   1.71   1.89
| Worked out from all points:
|   slope of the pulldown table from 0 to 0.27 V, typ, clamps not added: 22.2 ohm
|   slope of the pullup table from 0 to 0.27 V, typ, clamps not added: 23.6 ohm
|   GND clamp passes 1 mA (typ) near -0.37 V on its own axis
|   POWER clamp passes 1 mA (typ) near -0.43 V on its own axis
|   rising waveform, R_fixture 50, V_fixture 0: 20-80 % time 191ps typ, 197ps min, 214ps max; typ from 0 V to 1.21 V
|   rising waveform, R_fixture 50, V_fixture 1.8: 20-80 % time 168ps typ, 173ps min, 160ps max; typ from 0.571 V to 1.8 V
|   falling waveform, R_fixture 50, V_fixture 0: 20-80 % time 130ps typ, 128ps min, 127ps max; typ from 1.21 V to 0 V
|   falling waveform, R_fixture 50, V_fixture 1.8: 20-80 % time 182ps typ, 180ps min, 180ps max; typ from 1.8 V to 0.571 V
[GND Clamp]
| Voltage   I(typ)   I(min)   I(max)
-885.9mV  -22.44mA   -16.92mA   -30.49mA
-708.7mV  -13.24mA   -10.14mA   -17.96mA
-649.7mV  -10.37mA   -8.095mA   -14.06mA
-590.6mV  -7.705mA   -6.193mA   -10.39mA
-531.6mV  -5.322mA   -4.488mA   -7.054mA
-472.5mV  -3.308mA   -3.028mA   -4.171mA
-413.4mV  -1.757mA   -1.859mA   -1.935mA
-354.4mV  -739.5uA   -1.008mA   -580.7uA
-295.3mV  -232.3uA   -469.6uA   -100.4uA
-177.2mV  -12.01uA   -62.89uA   -1.688uA
-59.06mV  -489.8nA   -5.037uA   -176.4nA
3.6V      0A         0A         0A
[POWER Clamp]
| Voltage   I(typ)   I(min)   I(max)
-1.8V     93.11mA    78.62mA    128.6mA
-1.595V   74.64mA    64.3mA     101.3mA
-1.536V   69.6mA     60.25mA    94.19mA
-1.417V   60.07mA    52.24mA    81.84mA
-1.181V   43.06mA    36.84mA    60.84mA
-1.004V   31.04mA    26.13mA    43.96mA
-708.7mV  12.62mA    10.87mA    16.4mA
-590.6mV  6.476mA    6.104mA    7.295mA
-472.5mV  1.932mA    2.452mA    1.539mA
-354.4mV  154uA      598.2uA    74.19uA
-59.06mV  800.7nA    2.877uA    466.9nA
3.6V      0A         0A         0A
[Pullup]
| Voltage   I(typ)   I(min)   I(max)
-1.8V     25.58mA    19.88mA    27.01mA
-1.536V   27.54mA    22.2mA     29.7mA
-1.063V   26.36mA    24.27mA    27.09mA
-531.6mV  20.77mA    19.93mA    21.88mA
-354.4mV  15.21mA    14.88mA    15.56mA
562.5mV   -23.09mA   -23.14mA   -23mA
787.5mV   -31.22mA   -31.35mA   -30.11mA
1.012V    -37.71mA   -38.03mA   -34.53mA
1.35V     -43.27mA   -43.91mA   -38mA
1.8V      -47.12mA   -47.9mA    -40.68mA
2.863V    -53.03mA   -52.9mA    -44.55mA
3.6V      -54.7mA    -55.47mA   -46.87mA
[Pulldown]
| Voltage   I(typ)   I(min)   I(max)
-1.8V     -29.98mA   -24.46mA   -29.31mA
-1.417V   -35.84mA   -31.75mA   -31.22mA
-1.181V   -37.41mA   -34.96mA   -24.89mA
-1.004V   -30.06mA   -35.17mA   -23.24mA
-885.9mV  -27.95mA   -33.26mA   -22.27mA
-590.6mV  -22.91mA   -25.94mA   -19.16mA
-413.4mV  -18.21mA   -20.03mA   -15.76mA
562.5mV   24.25mA    26.06mA    21.39mA
843.8mV   34.22mA    35.66mA    30.66mA
1.125V    40.95mA    40.18mA    37.9mA
1.575V    43.86mA    41.99mA    41.9mA
3.6V      49.01mA    47.16mA    46.66mA
[Ramp]
dV/dt_r   0.725257/0.191401n  0.690399/0.196542n  0.757695/0.213902n
dV/dt_f   0.737266/0.181623n  0.719218/0.180117n  0.739665/0.180342n
R_load = 50
[Rising Waveform]
R_fixture = 50
V_fixture = 0
V_fixture_min = 0
V_fixture_max = 0
| Time   V(typ)   V(min)   V(max)
0s        2.136uV    3.147uV    3.364uV
1.122ns   -513.9uV   -324.5uV   1.388mV
1.213ns   -555.7uV   -351.1uV   136.6mV
1.422ns   -1.925mV   -412.1uV   899.8mV
1.56ns    306.2mV    -452.4uV   1.174V
1.771ns   1.057V     -12.65mV   1.249V
1.926ns   1.179V     109.7mV    1.257V
2.191ns   1.203V     993.6mV    1.261V
2.403ns   1.206V     1.129V     1.261V
10ns      1.209V     1.151V     1.263V
[Rising Waveform]
R_fixture = 50
V_fixture = 1.8
V_fixture_min = 1.71
V_fixture_max = 1.89
| Time   V(typ)   V(min)   V(max)
0s        571.2mV    511.3mV    657.2mV
922ps     571.9mV    511.6mV    667.8mV
1.063ns   572mV      511.7mV    1.47V
1.244ns   601.8mV    511.8mV    1.82V
1.377ns   1.362V     511.8mV    1.879V
1.552ns   1.731V     511.9mV    1.886V
1.663ns   1.784V     536.4mV    1.888V
1.839ns   1.795V     1.358V     1.889V
2.077ns   1.798V     1.691V     1.889V
10ns      1.8V       1.71V      1.89V
[Falling Waveform]
R_fixture = 50
V_fixture = 0
V_fixture_min = 0
V_fixture_max = 0
| Time   V(typ)   V(min)   V(max)
0s        1.209V     1.151V     1.263V
920ps     1.208V     1.15V      1.253V
1.106ns   1.208V     1.15V      209.7mV
1.281ns   1.097V     1.15V      14.79mV
1.435ns   221.2mV    1.15V      4.916mV
1.578ns   18.66mV    1.15V      2.674mV
1.71ns    6.908mV    1.089V     1.921mV
1.887ns   2.433mV    167.1mV    1.349mV
2.032ns   1.747mV    14.87mV    1.097mV
10ns      2.882uV    4.292uV    3.983uV
[Falling Waveform]
R_fixture = 50
V_fixture = 1.8
V_fixture_min = 1.71
V_fixture_max = 1.89
| Time   V(typ)   V(min)   V(max)
0s        1.8V       1.71V      1.89V
1.064ns   1.801V     1.711V     1.886V
1.148ns   1.801V     1.711V     1.73V
1.39ns    1.798V     1.711V     801.4mV
1.587ns   1.242V     1.711V     676.5mV
1.756ns   657.6mV    1.724V     664.4mV
1.89ns    594mV      1.583V     661.2mV
2.159ns   575.7mV    612.9mV    658.7mV
2.341ns   573.5mV    525.9mV    658.5mV
10ns      571.2mV    511.3mV    657.2mV
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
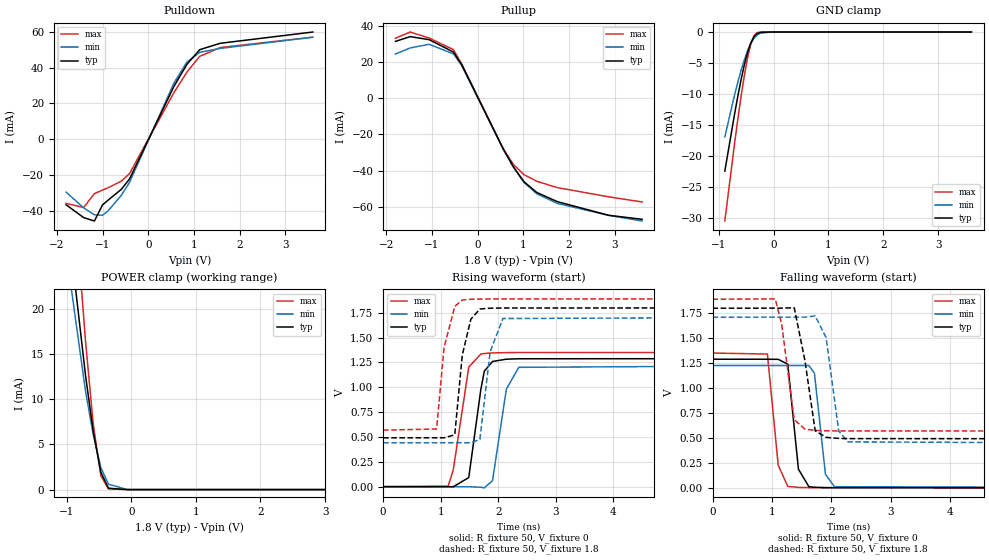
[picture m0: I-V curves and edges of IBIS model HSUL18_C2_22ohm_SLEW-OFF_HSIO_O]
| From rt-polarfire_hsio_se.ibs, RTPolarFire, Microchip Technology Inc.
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|   Model HSUL18_C2_22ohm_SLEW-OFF_HSIO_O
[Model]   HSUL18_C2_22ohm_SLEW-OFF_HSIO_O
Model_type   Output
Polarity   Non-Inverting
Enable   Active-High
Vmeas =   0.9
Cref =   5p
Rref =   50
Vref =   0.9
|   typ   min   max
C_comp_pullup   1.335e-12   1.335e-12   1.380e-12
C_comp_pulldown  1.335e-12   1.335e-12   1.380e-12
[Temperature Range]  25C   125C   -55C
[Voltage Range]  1.8   1.71   1.89
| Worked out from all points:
|   slope of the pulldown table from 0 to 0.27 V, typ, clamps not added: 18.2 ohm
|   slope of the pullup table from 0 to 0.27 V, typ, clamps not added: 19.3 ohm
|   GND clamp passes 1 mA (typ) near -0.37 V on its own axis
|   POWER clamp passes 1 mA (typ) near -0.43 V on its own axis
|   rising waveform, R_fixture 50, V_fixture 0: 20-80 % time 172ps typ, 178ps min, 194ps max; typ from 0 V to 1.29 V
|   rising waveform, R_fixture 50, V_fixture 1.8: 20-80 % time 166ps typ, 169ps min, 159ps max; typ from 0.491 V to 1.8 V
|   falling waveform, R_fixture 50, V_fixture 0: 20-80 % time 128ps typ, 126ps min, 125ps max; typ from 1.29 V to 0 V
|   falling waveform, R_fixture 50, V_fixture 1.8: 20-80 % time 163ps typ, 162ps min, 161ps max; typ from 1.8 V to 0.491 V
[GND Clamp]
| Voltage   I(typ)   I(min)   I(max)
-885.9mV  -22.44mA   -16.92mA   -30.49mA
-708.7mV  -13.24mA   -10.14mA   -17.96mA
-649.7mV  -10.37mA   -8.095mA   -14.06mA
-590.6mV  -7.705mA   -6.193mA   -10.39mA
-531.6mV  -5.322mA   -4.488mA   -7.054mA
-472.5mV  -3.308mA   -3.028mA   -4.171mA
-413.4mV  -1.757mA   -1.859mA   -1.935mA
-354.4mV  -739.5uA   -1.008mA   -580.7uA
-295.3mV  -232.3uA   -469.6uA   -100.4uA
-236.2mV  -56.73uA   -185.1uA   -13.11uA
-59.06mV  -489.8nA   -5.037uA   -176.4nA
3.6V      0A         0A         0A
[POWER Clamp]
| Voltage   I(typ)   I(min)   I(max)
-1.8V     93.11mA    78.61mA    128.6mA
-1.713V   85.12mA    72.5mA     116.7mA
-1.536V   69.6mA     60.25mA    94.32mA
-1.477V   64.73mA    56.22mA    87.68mA
-1.358V   55.61mA    48.31mA    76.35mA
-1.004V   31.04mA    26.13mA    43.96mA
-708.7mV  12.62mA    10.87mA    16.4mA
-590.6mV  6.476mA    6.104mA    7.295mA
-472.5mV  1.932mA    2.452mA    1.539mA
-354.4mV  154uA      598.2uA    74.19uA
-59.06mV  800.7nA    2.877uA    466.9nA
3.6V      0A         0A         0A
[Pullup]
| Voltage   I(typ)   I(min)   I(max)
-1.8V     31.26mA    24.31mA    33.02mA
-1.477V   33.89mA    27.66mA    36.42mA
-1.063V   32.21mA    29.66mA    33.11mA
-531.6mV  25.39mA    24.36mA    26.73mA
-354.4mV  18.59mA    18.18mA    19.02mA
562.5mV   -28.22mA   -28.28mA   -28.1mA
787.5mV   -38.15mA   -38.31mA   -36.8mA
1.012V    -46.08mA   -46.48mA   -42.19mA
1.294V    -52.06mA   -52.79mA   -45.9mA
1.744V    -57.12mA   -58.08mA   -49.38mA
2.863V    -64.62mA   -64.66mA   -54.44mA
3.6V      -66.86mA   -67.8mA    -57.28mA
[Pulldown]
| Voltage   I(typ)   I(min)   I(max)
-1.8V     -36.67mA   -29.59mA   -35.89mA
-1.417V   -43.81mA   -38.37mA   -38.16mA
-1.181V   -45.72mA   -42.24mA   -30.41mA
-1.004V   -36.73mA   -42.49mA   -28.41mA
-885.9mV  -34.16mA   -40.17mA   -27.22mA
-590.6mV  -28mA      -31.32mA   -23.41mA
-413.4mV  -22.25mA   -24.18mA   -19.25mA
562.5mV   29.62mA    31.47mA    26.13mA
843.8mV   41.81mA    43.07mA    37.46mA
1.125V    50.03mA    48.55mA    46.31mA
1.575V    53.6mA     50.74mA    51.23mA
3.6V      59.89mA    56.98mA    57.02mA
[Ramp]
dV/dt_r   0.77347/0.172325n  0.735783/0.177776n  0.810855/0.194416n
dV/dt_f   0.785211/0.16326n  0.761135/0.162348n  0.792495/0.161333n
R_load = 50
[Rising Waveform]
R_fixture = 50
V_fixture = 0
V_fixture_min = 0
V_fixture_max = 0
| Time   V(typ)   V(min)   V(max)
0s        2.028uV    2.896uV    3.156uV
1.128ns   -621.7uV   -494.6uV   3.533mV
1.218ns   -1.291mV   -534.3uV   168.8mV
1.487ns   91.6mV     -652.9uV   1.204V
1.697ns   978.6mV    -5.821mV   1.334V
1.757ns   1.162V     -12.03mV   1.34V
1.9ns     1.26V      60.67mV    1.346V
2.14ns    1.283V     981.1mV    1.349V
2.356ns   1.287V     1.201V     1.35V
10ns      1.289V     1.226V     1.351V
[Rising Waveform]
R_fixture = 50
V_fixture = 1.8
V_fixture_min = 1.71
V_fixture_max = 1.89
| Time   V(typ)   V(min)   V(max)
0s        491.3mV    441.4mV    569.2mV
928ps     492mV      441.8mV    579.8mV
1.058ns   492.1mV    441.9mV    1.401V
1.244ns   521.7mV    442mV      1.814V
1.374ns   1.323V     442mV      1.879V
1.523ns   1.685V     442.1mV    1.886V
1.68ns    1.788V     475.1mV    1.888V
1.858ns   1.796V     1.357V     1.889V
2.08ns    1.798V     1.692V     1.889V
10ns      1.8V       1.71V      1.89V
[Falling Waveform]
R_fixture = 50
V_fixture = 0
V_fixture_min = 0
V_fixture_max = 0
| Time   V(typ)   V(min)   V(max)
0s        1.289V     1.226V     1.351V
925ps     1.289V     1.226V     1.341V
1.107ns   1.288V     1.226V     227.2mV
1.268ns   1.24V      1.226V     14.85mV
1.448ns   187mV      1.226V     4.47mV
1.624ns   11.51mV    1.226V     2.241mV
1.717ns   5.827mV    1.15V      1.687mV
1.903ns   2.391mV    135.5mV    1.273mV
2.056ns   1.463mV    11.5mV     1.028mV
10ns      2.765uV    3.995uV    3.726uV
[Falling Waveform]
R_fixture = 50
V_fixture = 1.8
V_fixture_min = 1.71
V_fixture_max = 1.89
| Time   V(typ)   V(min)   V(max)
0s        1.8V       1.71V      1.89V
1.057ns   1.801V     1.711V     1.894V
1.163ns   1.801V     1.711V     1.648V
1.377ns   1.805V     1.711V     683.9mV
1.557ns   1.276V     1.711V     588.2mV
1.73ns    571.8mV    1.723V     575.9mV
1.914ns   506mV      1.507V     571.9mV
2.127ns   495.6mV    568.7mV    570.6mV
2.285ns   493.5mV    460.3mV    570.3mV
10ns      491.3mV    441.4mV    569.2mV
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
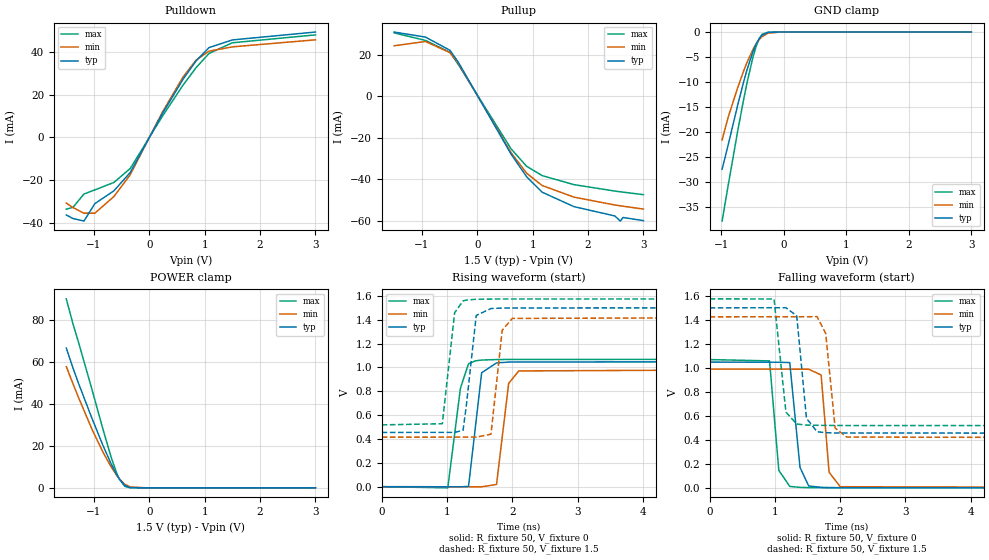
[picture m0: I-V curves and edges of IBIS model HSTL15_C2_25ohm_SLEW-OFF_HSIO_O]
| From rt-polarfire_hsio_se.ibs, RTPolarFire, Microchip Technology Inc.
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|   Model HSTL15_C2_25ohm_SLEW-OFF_HSIO_O
[Model]   HSTL15_C2_25ohm_SLEW-OFF_HSIO_O
Model_type   Output
Polarity   Non-Inverting
Enable   Active-High
Vmeas =   0.75
Cref =   5p
Rref =   50
Vref =   0.75
|   typ   min   max
C_comp_pullup   1.335e-12   1.335e-12   1.380e-12
C_comp_pulldown  1.335e-12   1.335e-12   1.380e-12
[Temperature Range]  25C   125C   -55C
[Voltage Range]  1.5   1.425   1.575
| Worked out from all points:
|   slope of the pulldown table from 0 to 0.225 V, typ, clamps not added: 21.1 ohm
|   slope of the pullup table from 0 to 0.225 V, typ, clamps not added: 21.1 ohm
|   GND clamp passes 1 mA (typ) near -0.37 V on its own axis
|   POWER clamp passes 1 mA (typ) near -0.43 V on its own axis
|   rising waveform, R_fixture 50, V_fixture 0: 20-80 % time 104ps typ, 113ps min, 121ps max; typ from 0 V to 1.05 V
|   rising waveform, R_fixture 50, V_fixture 1.5: 20-80 % time 102ps typ, 99.1ps min, 111ps max; typ from 0.455 V to 1.5 V
|   falling waveform, R_fixture 50, V_fixture 0: 20-80 % time 79.1ps typ, 75.2ps min, 82.7ps max; typ from 1.05 V to 0 V
|   falling waveform, R_fixture 50, V_fixture 1.5: 20-80 % time 94.7ps typ, 93.1ps min, 95.1ps max; typ from 1.5 V to 0.455 V
[GND Clamp]
| Voltage   I(typ)   I(min)   I(max)
-984.4mV  -27.37mA   -21.52mA   -37.7mA
-885.9mV  -22.43mA   -16.92mA   -30.48mA
-738.3mV  -14.72mA   -11.21mA   -19.96mA
-639.8mV  -9.903mA   -7.76mA    -13.42mA
-590.6mV  -7.7mA     -6.188mA   -10.38mA
-492.2mV  -3.93mA    -3.481mA   -5.066mA
-443mV    -2.467mA   -2.402mA   -2.955mA
-393.7mV  -1.355mA   -1.538mA   -1.375mA
-344.5mV  -621.9uA   -897uA     -448.3uA
-246.1mV  -72.57uA   -218.4uA   -18.4uA
-49.22mV  -334.5nA   -3.793uA   -95.68nA
3V        0A         0A         0A
[POWER Clamp]
| Voltage   I(typ)   I(min)   I(max)
-1.5V     66.64mA    57.8mA     90.1mA
-1.378V   57.06mA    49.6mA     78.07mA
-1.28V    49.9mA     43.13mA    69.49mA
-1.034V   32.99mA    27.83mA    46.7mA
-836.7mV  20.16mA    16.97mA    27.85mA
-689.1mV  11.42mA    9.956mA    14.55mA
-590.6mV  6.331mA    6.012mA    7.055mA
-541.4mV  4.184mA    4.318mA    4.125mA
-443mV    1.134mA    1.688mA    703.5uA
-344.5mV  93.53uA    432.5uA    21.45uA
-49.22mV  620.3nA    2.506uA    250nA
3V        0A         0A         0A
[Pullup]
| Voltage   I(typ)   I(min)   I(max)
-1.5V     30.9mA     24.3mA     30.48mA
-935.2mV  28.46mA    26.35mA    26.86mA
-492.2mV  22.12mA    20.99mA    21.13mA
-344.5mV  16.49mA    16mA       15.37mA
609.4mV   -27.78mA   -27.08mA   -25.23mA
890.6mV   -38.67mA   -36.99mA   -33.68mA
1.172V    -46.14mA   -42.93mA   -38.16mA
1.746V    -53.09mA   -48.51mA   -42.51mA
2.484V    -57.56mA   -52.29mA   -45.59mA
2.583V    -60mA      -52.68mA   -45.94mA
2.632V    -58.31mA   -52.88mA   -46.11mA
3V        -59.79mA   -54.25mA   -47.32mA
[Pulldown]
| Voltage   I(typ)   I(min)   I(max)
-1.5V     -36.38mA   -30.81mA   -33.67mA
-1.378V   -38.06mA   -32.93mA   -32.76mA
-1.181V   -39.21mA   -35.54mA   -26.55mA
-984.4mV  -31.07mA   -35.54mA   -24.62mA
-639.8mV  -25.04mA   -27.75mA   -21.13mA
-344.5mV  -16.42mA   -17.45mA   -14.56mA
234.4mV   11.09mA    11.77mA    9.855mA
609.4mV   27.3mA     28.35mA    24.55mA
843.8mV   35.86mA    36.24mA    32.69mA
1.078V    42.11mA    40.44mA    39.36mA
1.5V      45.7mA     42.45mA    44.37mA
3V        49.4mA     45.75mA    48.06mA
[Ramp]
dV/dt_r   0.628807/0.104295n  0.593937/0.113048n  0.641103/0.120889n
dV/dt_f   0.627018/94.7273p  0.60589/93.0964p  0.63394/95.1171p
R_load = 50
[Rising Waveform]
R_fixture = 50
V_fixture = 0
V_fixture_min = 0
V_fixture_max = 0
| Time   V(typ)   V(min)   V(max)
0s        1.548uV    2.367uV    2.268uV
1.012ns   -720.8uV   -585.3uV   -9.68mV
1.206ns   -859.3uV   -697.9uV   826.4mV
1.33ns    2.681mV    -769.9uV   1.031V
1.434ns   495.2mV    -830.3uV   1.055V
1.531ns   955.6mV    -886.7uV   1.062V
1.759ns   1.038V     18.65mV    1.066V
1.945ns   1.045V     866.5mV    1.067V
2.1ns     1.046V     970.8mV    1.067V
10ns      1.048V     989.9mV    1.069V
[Rising Waveform]
R_fixture = 50
V_fixture = 1.5
V_fixture_min = 1.425
V_fixture_max = 1.575
| Time   V(typ)   V(min)   V(max)
0s        455mV      415.2mV    518.4mV
928ps     455.5mV    415.4mV    527.8mV
1.117ns   455.6mV    415.4mV    1.459V
1.246ns   473.4mV    415.5mV    1.558V
1.294ns   670.5mV    415.5mV    1.564V
1.448ns   1.436V     415.5mV    1.572V
1.674ns   1.494V     440.5mV    1.573V
1.846ns   1.498V     1.312V     1.574V
2.001ns   1.499V     1.411V     1.574V
10ns      1.5V       1.425V     1.575V
[Falling Waveform]
R_fixture = 50
V_fixture = 0
V_fixture_min = 0
V_fixture_max = 0
| Time   V(typ)   V(min)   V(max)
0s        1.048V     989.9mV    1.069V
918ps     1.047V     989.4mV    1.058V
1.06ns    1.047V     989.3mV    146.3mV
1.228ns   1.044V     989.2mV    11.92mV
1.385ns   170.6mV    989.1mV    3.991mV
1.518ns   15.81mV    989mV      2.255mV
1.709ns   4.132mV    940.7mV    1.481mV
1.831ns   2.157mV    130mV      1.217mV
2.002ns   1.331mV    9.349mV    848uV
10ns      2.281uV    2.555uV    2.761uV
[Falling Waveform]
R_fixture = 50
V_fixture = 1.5
V_fixture_min = 1.425
V_fixture_max = 1.575
| Time   V(typ)   V(min)   V(max)
0s        1.5V       1.425V     1.575V
987ps     1.501V     1.426V     1.574V
1.169ns   1.501V     1.426V     631.1mV
1.335ns   1.434V     1.426V     531.6mV
1.484ns   579.6mV    1.426V     523.1mV
1.647ns   467.7mV    1.427V     521.2mV
1.779ns   459.6mV    1.287V     520.4mV
1.924ns   457.5mV    497.8mV    519.8mV
2.101ns   456.8mV    423.2mV    519.4mV
10ns      455mV      415.1mV    518.4mV
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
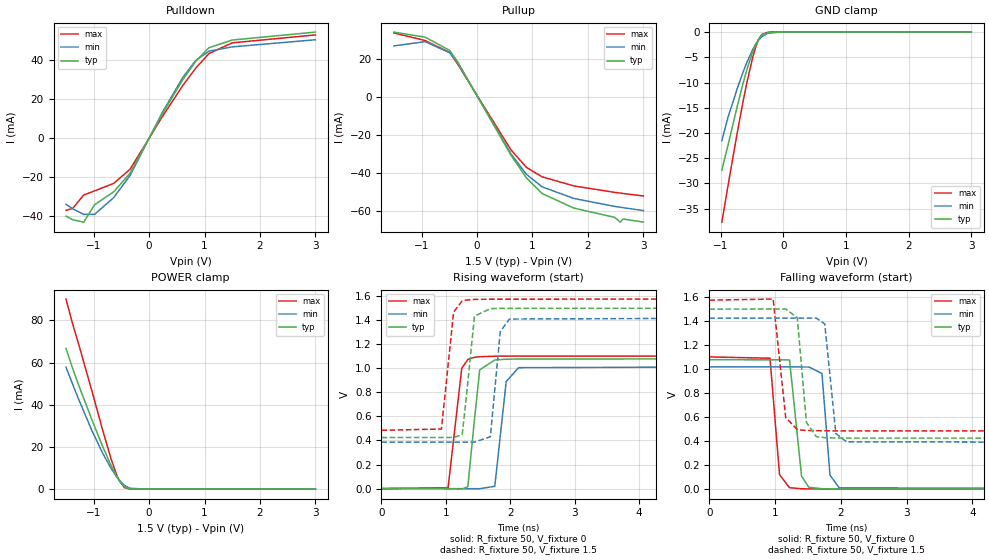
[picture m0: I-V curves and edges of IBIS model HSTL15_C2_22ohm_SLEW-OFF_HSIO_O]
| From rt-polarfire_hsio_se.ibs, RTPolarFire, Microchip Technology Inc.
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|   Model HSTL15_C2_22ohm_SLEW-OFF_HSIO_O
[Model]   HSTL15_C2_22ohm_SLEW-OFF_HSIO_O
Model_type   Output
Polarity   Non-Inverting
Enable   Active-High
Vmeas =   0.75
Cref =   5p
Rref =   50
Vref =   0.75
|   typ   min   max
C_comp_pullup   1.335e-12   1.335e-12   1.380e-12
C_comp_pulldown  1.335e-12   1.335e-12   1.380e-12
[Temperature Range]  25C   125C   -55C
[Voltage Range]  1.5   1.425   1.575
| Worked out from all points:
|   slope of the pulldown table from 0 to 0.225 V, typ, clamps not added: 19.2 ohm
|   slope of the pullup table from 0 to 0.225 V, typ, clamps not added: 19.2 ohm
|   GND clamp passes 1 mA (typ) near -0.37 V on its own axis
|   POWER clamp passes 1 mA (typ) near -0.43 V on its own axis
|   rising waveform, R_fixture 50, V_fixture 0: 20-80 % time 99.5ps typ, 108ps min, 115ps max; typ from 0 V to 1.08 V
|   rising waveform, R_fixture 50, V_fixture 1.5: 20-80 % time 99.7ps typ, 94.6ps min, 109ps max; typ from 0.424 V to 1.5 V
|   falling waveform, R_fixture 50, V_fixture 0: 20-80 % time 76.7ps typ, 72.7ps min, 79.7ps max; typ from 1.08 V to 0 V
|   falling waveform, R_fixture 50, V_fixture 1.5: 20-80 % time 88.6ps typ, 88.1ps min, 91.1ps max; typ from 1.5 V to 0.424 V
[GND Clamp]
| Voltage   I(typ)   I(min)   I(max)
-984.4mV  -27.37mA   -21.52mA   -37.7mA
-885.9mV  -22.43mA   -16.92mA   -30.48mA
-738.3mV  -14.72mA   -11.21mA   -19.96mA
-639.8mV  -9.903mA   -7.76mA    -13.42mA
-590.6mV  -7.7mA     -6.188mA   -10.38mA
-492.2mV  -3.93mA    -3.481mA   -5.066mA
-443mV    -2.467mA   -2.402mA   -2.955mA
-393.7mV  -1.355mA   -1.538mA   -1.375mA
-344.5mV  -621.9uA   -897uA     -448.3uA
-246.1mV  -72.57uA   -218.4uA   -18.4uA
-49.22mV  -334.5nA   -3.793uA   -95.68nA
3V        0A         0A         0A
[POWER Clamp]
| Voltage   I(typ)   I(min)   I(max)
-1.5V     66.64mA    57.8mA     90.1mA
-1.378V   57.06mA    49.6mA     78.07mA
-1.28V    49.9mA     43.13mA    69.49mA
-1.034V   32.99mA    27.83mA    46.7mA
-836.7mV  20.16mA    16.97mA    27.85mA
-689.1mV  11.42mA    9.956mA    14.55mA
-590.6mV  6.331mA    6.012mA    7.055mA
-541.4mV  4.184mA    4.318mA    4.125mA
-443mV    1.134mA    1.688mA    703.5uA
-344.5mV  93.53uA    432.5uA    21.45uA
-49.22mV  620.3nA    2.506uA    250nA
3V        0A         0A         0A
[Pullup]
| Voltage   I(typ)   I(min)   I(max)
-1.5V     33.99mA    26.73mA    33.53mA
-935.2mV  31.31mA    28.98mA    29.54mA
-492.2mV  24.33mA    23.09mA    23.25mA
-344.5mV  18.14mA    17.6mA     16.9mA
609.4mV   -30.56mA   -29.79mA   -27.75mA
890.6mV   -42.54mA   -40.69mA   -37.05mA
1.172V    -50.75mA   -47.22mA   -41.98mA
1.746V    -58.4mA    -53.36mA   -46.76mA
2.484V    -63.3mA    -57.53mA   -50.16mA
2.583V    -65.81mA   -57.96mA   -50.54mA
2.632V    -64.15mA   -58.18mA   -50.73mA
3V        -65.74mA   -59.69mA   -52.06mA
[Pulldown]
| Voltage   I(typ)   I(min)   I(max)
-1.5V     -40.02mA   -33.91mA   -37.04mA
-1.378V   -41.86mA   -36.24mA   -36.03mA
-1.181V   -43.12mA   -39.11mA   -29.2mA
-984.4mV  -34.17mA   -39.1mA    -27.08mA
-639.8mV  -27.54mA   -30.53mA   -23.24mA
-344.5mV  -18.06mA   -19.2mA    -16.01mA
234.4mV   12.2mA     12.95mA    10.84mA
609.4mV   30.01mA    31.2mA     27mA
843.8mV   39.43mA    39.89mA    35.95mA
1.078V    46.3mA     44.53mA    43.29mA
1.5V      50.26mA    46.75mA    48.82mA
3V        54.32mA    50.39mA    52.87mA
[Ramp]
dV/dt_r   0.647117/99.5141p  0.611526/0.108097n  0.66148/0.114553n
dV/dt_f   0.645607/88.6439p  0.623328/88.0893p  0.654311/91.0932p
R_load = 50
[Rising Waveform]
R_fixture = 50
V_fixture = 0
V_fixture_min = 0
V_fixture_max = 0
| Time   V(typ)   V(min)   V(max)
0s        1.534uV    2.289uV    2.234uV
1.034ns   -523.7uV   -564.2uV   7.331mV
1.246ns   -4.789mV   -680.3uV   999mV
1.341ns   16.71mV    -732.4uV   1.073V
1.435ns   528.7mV    -783.9uV   1.09V
1.525ns   986.5mV    -833.2uV   1.096V
1.759ns   1.069V     18.75mV    1.1V
1.936ns   1.075V     889.3mV    1.101V
2.129ns   1.077V     1.005V     1.101V
10ns      1.079V     1.019V     1.102V
[Rising Waveform]
R_fixture = 50
V_fixture = 1.5
V_fixture_min = 1.425
V_fixture_max = 1.575
| Time   V(typ)   V(min)   V(max)
0s        424mV      386.1mV    484.5mV
931ps     424.5mV    386.4mV    494.8mV
1.12ns    424.6mV    386.5mV    1.467V
1.253ns   448.7mV    386.5mV    1.56V
1.303ns   688.8mV    386.5mV    1.566V
1.444ns   1.433V     386.6mV    1.572V
1.69ns    1.495V     430.6mV    1.574V
1.844ns   1.498V     1.305V     1.574V
1.985ns   1.498V     1.409V     1.574V
10ns      1.5V       1.425V     1.575V
[Falling Waveform]
R_fixture = 50
V_fixture = 0
V_fixture_min = 0
V_fixture_max = 0
| Time   V(typ)   V(min)   V(max)
0s        1.079V     1.019V     1.102V
922ps     1.078V     1.019V     1.091V
1.067ns   1.078V     1.019V     120.7mV
1.219ns   1.077V     1.019V     12.35mV
1.402ns   107.9mV    1.018V     3.362mV
1.513ns   15.66mV    1.018V     2.191mV
1.712ns   3.681mV    963.5mV    1.426mV
1.834ns   2.117mV    117mV      1.183mV
1.975ns   1.409mV    11.08mV    901.1uV
10ns      2.269uV    3.194uV    2.835uV
[Falling Waveform]
R_fixture = 50
V_fixture = 1.5
V_fixture_min = 1.425
V_fixture_max = 1.575
| Time   V(typ)   V(min)   V(max)
0s        1.5V       1.425V     1.575V
970ps     1.501V     1.426V     1.584V
1.161ns   1.501V     1.426V     597.3mV
1.337ns   1.428V     1.426V     495.9mV
1.476ns   555.4mV    1.426V     488.9mV
1.626ns   437.6mV    1.426V     487.2mV
1.755ns   428.9mV    1.376V     486.4mV
1.923ns   426.4mV    463.4mV    485.7mV
2.086ns   425.8mV    394.7mV    485.4mV
10ns      424mV      386.1mV    484.5mV
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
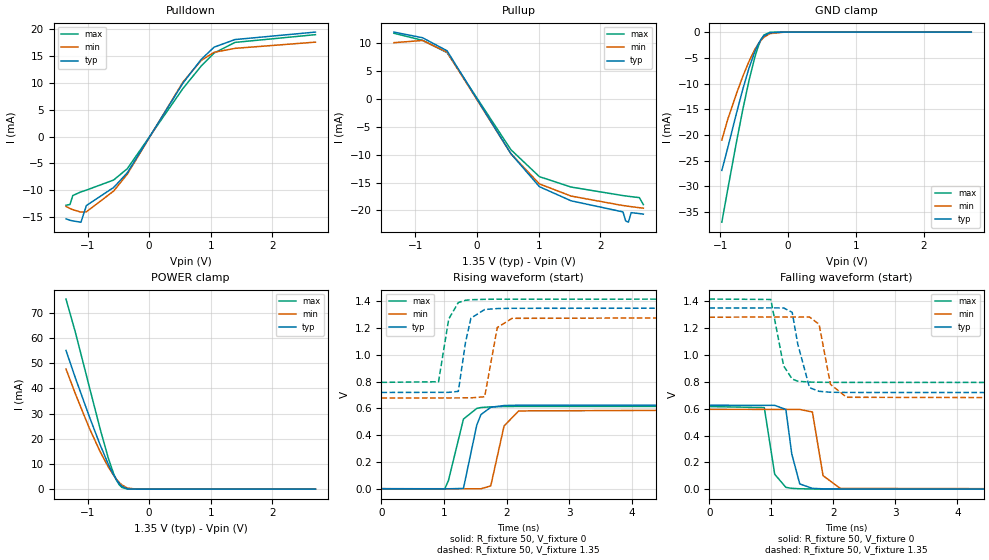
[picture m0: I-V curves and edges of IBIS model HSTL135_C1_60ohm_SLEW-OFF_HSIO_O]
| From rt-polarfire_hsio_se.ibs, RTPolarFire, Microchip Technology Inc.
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|   Model HSTL135_C1_60ohm_SLEW-OFF_HSIO_O
[Model]   HSTL135_C1_60ohm_SLEW-OFF_HSIO_O
Model_type   Output
Polarity   Non-Inverting
Enable   Active-High
Vmeas =   0.675
Cref =   5p
Rref =   50
Vref =   0.675
|   typ   min   max
C_comp_pullup   1.335e-12   1.335e-12   1.380e-12
C_comp_pulldown  1.335e-12   1.335e-12   1.380e-12
[Temperature Range]  25C   125C   -55C
[Voltage Range]  1.35   1.2825   1.4175
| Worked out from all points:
|   slope of the pulldown table from 0 to 0.203 V, typ, clamps not added: 52.6 ohm
|   slope of the pullup table from 0 to 0.203 V, typ, clamps not added: 53.7 ohm
|   GND clamp passes 1 mA (typ) near -0.37 V on its own axis
|   POWER clamp passes 1 mA (typ) near -0.43 V on its own axis
|   rising waveform, R_fixture 50, V_fixture 0: 20-80 % time 162ps typ, 168ps min, 187ps max; typ from 0 V to 0.625 V
|   rising waveform, R_fixture 50, V_fixture 1.35: 20-80 % time 115ps typ, 115ps min, 126ps max; typ from 0.719 V to 1.35 V
|   falling waveform, R_fixture 50, V_fixture 0: 20-80 % time 111ps typ, 109ps min, 107ps max; typ from 0.625 V to 0 V
|   falling waveform, R_fixture 50, V_fixture 1.35: 20-80 % time 141ps typ, 144ps min, 139ps max; typ from 1.35 V to 0.719 V
[GND Clamp]
| Voltage   I(typ)   I(min)   I(max)
-974.5mV  -26.9mA    -20.99mA   -36.97mA
-885.9mV  -22.43mA   -16.91mA   -30.47mA
-753mV    -15.48mA   -11.75mA   -20.97mA
-664.5mV  -11.06mA   -8.585mA   -15mA
-575.9mV  -7.072mA   -5.739mA   -9.511mA
-487.3mV  -3.767mA   -3.362mA   -4.833mA
-443mV    -2.466mA   -2.401mA   -2.954mA
-398.7mV  -1.449mA   -1.613mA   -1.504mA
-354.4mV  -738.4uA   -1.007mA   -579.6uA
-265.8mV  -117.5uA   -300.6uA   -36.61uA
-44.3mV   -274.4nA   -3.251uA   -69.5nA
2.7V      0A         0A         0A
[POWER Clamp]
| Voltage   I(typ)   I(min)   I(max)
-1.35V    55.07mA    47.72mA    75.49mA
-1.196V   44.05mA    37.75mA    62.13mA
-974.5mV  29.03mA    24.41mA    40.95mA
-797.3mV  17.68mA    14.97mA    24.06mA
-664.5mV  10.01mA    8.871mA    12.44mA
-575.9mV  5.63mA     5.451mA    6.064mA
-531.6mV  3.786mA    3.983mA    3.599mA
-487.3mV  2.262mA    2.712mA    1.789mA
-443mV    1.133mA    1.675mA    684.4uA
-354.4mV  127.5uA    473.3uA    30.46uA
-221.5mV  1.715uA    56.89uA    636.6nA
2.7V      0A         0A         0A
[Pullup]
| Voltage   I(typ)   I(min)   I(max)
-1.35V    12.03mA    10.13mA    11.82mA
-885.9mV  11.02mA    10.52mA    10.55mA
-487.3mV  8.673mA    8.437mA    8.356mA
548.4mV   -9.801mA   -9.806mA   -9.086mA
1.012V    -15.74mA   -15.24mA   -13.94mA
1.527V    -18.28mA   -17.43mA   -15.81mA
2.369V    -20.27mA   -19.13mA   -17.34mA
2.413V    -21.9mA    -19.19mA   -17.4mA
2.457V    -22.12mA   -19.26mA   -17.47mA
2.502V    -20.41mA   -19.33mA   -17.53mA
2.635V    -20.57mA   -19.52mA   -17.71mA
2.7V      -20.67mA   -19.61mA   -18.96mA
[Pulldown]
| Voltage   I(typ)   I(min)   I(max)
-1.35V    -15.33mA   -13.02mA   -12.79mA
-1.285V   -15.59mA   -13.4mA    -12.65mA
-1.24V    -15.71mA   -13.62mA   -10.99mA
-1.107V   -15.95mA   -14.07mA   -10.3mA
-1.019V   -12.85mA   -14.02mA   -9.978mA
-575.9mV  -9.481mA   -10.15mA   -8.093mA
-354.4mV  -6.744mA   -7.002mA   -5.982mA
548.4mV   9.945mA    10.14mA    8.936mA
843.8mV   14.35mA    14.16mA    13.11mA
1.055V    16.65mA    15.69mA    15.55mA
1.394V    18.06mA    16.42mA    17.53mA
2.7V      19.45mA    17.58mA    18.97mA
[Ramp]
dV/dt_r   0.375216/0.161936n  0.357033/0.167842n  0.369417/0.186893n
dV/dt_f   0.378451/0.141165n  0.362711/0.143501n  0.373706/0.13851n
R_load = 50
[Rising Waveform]
R_fixture = 50
V_fixture = 0
V_fixture_min = 0
V_fixture_max = 0
| Time   V(typ)   V(min)   V(max)
0s        1.395uV    2.882uV    2.07uV
1.008ns   -803.1uV   -398uV     -3.502mV
1.069ns   -851.8uV   -422.2uV   60.5mV
1.309ns   2.219mV    -517.7uV   520.1mV
1.522ns   476.2mV    -602.4uV   599.9mV
1.588ns   553.3mV    -628.6uV   606.5mV
1.745ns   608.2mV    20.8mV     611.7mV
1.957ns   621.4mV    468.1mV    614.2mV
2.19ns    624mV      581.2mV    614.8mV
10ns      625.4mV    595.1mV    615.7mV
[Rising Waveform]
R_fixture = 50
V_fixture = 1.35
V_fixture_min = 1.2825
V_fixture_max = 1.4175
| Time   V(typ)   V(min)   V(max)
0s        719.2mV    677.9mV    794.6mV
911ps     719.9mV    678.4mV    799.1mV
1.074ns   720mV      678.5mV    1.268V
1.227ns   727.2mV    678.6mV    1.391V
1.343ns   1.096V     678.7mV    1.408V
1.428ns   1.274V     678.7mV    1.412V
1.648ns   1.339V     687mV      1.415V
1.849ns   1.346V     1.204V     1.416V
2.084ns   1.348V     1.273V     1.416V
10ns      1.35V      1.282V     1.417V
[Falling Waveform]
R_fixture = 50
V_fixture = 0
V_fixture_min = 0
V_fixture_max = 0
| Time   V(typ)   V(min)   V(max)
0s        625.4mV    595.1mV    615.7mV
886ps     624.9mV    594.7mV    608.3mV
1.054ns   624.8mV    594.6mV    111.2mV
1.234ns   594.1mV    594.6mV    13.52mV
1.329ns   262.8mV    594.5mV    6.084mV
1.458ns   38.99mV    594.5mV    3.043mV
1.662ns   5.945mV    575mV      1.491mV
1.834ns   2.568mV    100.5mV    1.132mV
2.112ns   1.274mV    5.478mV    819.7uV
10ns      2.484uV    4.471uV    3.29uV
[Falling Waveform]
R_fixture = 50
V_fixture = 1.35
V_fixture_min = 1.2825
V_fixture_max = 1.4175
| Time   V(typ)   V(min)   V(max)
0s        1.35V      1.282V     1.417V
991ps     1.351V     1.283V     1.414V
1.198ns   1.351V     1.283V     918.5mV
1.336ns   1.318V     1.283V     821.1mV
1.426ns   1.082V     1.283V     804.6mV
1.616ns   756.3mV    1.283V     798.1mV
1.77ns    729.4mV    1.229V     796.9mV
1.953ns   722.4mV    781.6mV    796.2mV
2.213ns   720.9mV    684.9mV    795.8mV
10ns      719.2mV    677.9mV    794.6mV
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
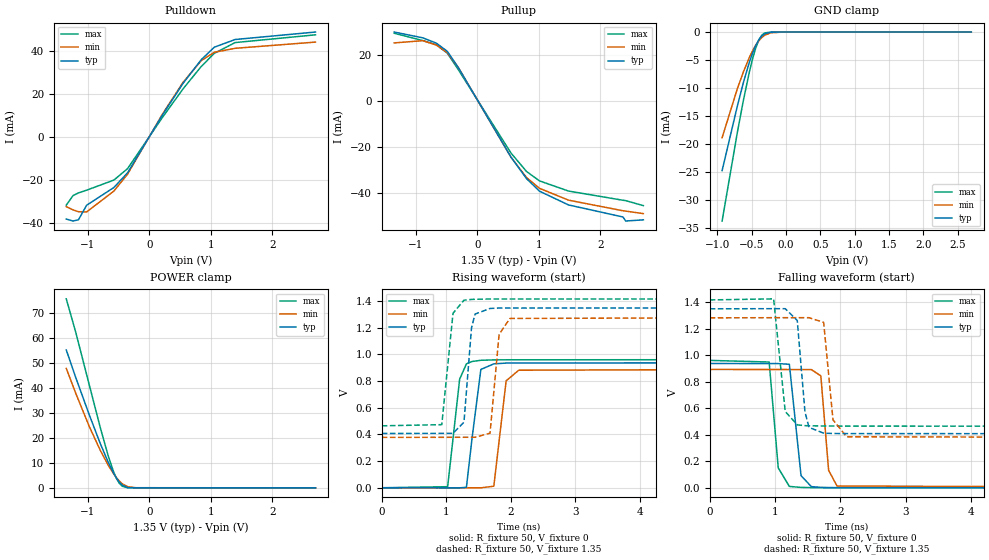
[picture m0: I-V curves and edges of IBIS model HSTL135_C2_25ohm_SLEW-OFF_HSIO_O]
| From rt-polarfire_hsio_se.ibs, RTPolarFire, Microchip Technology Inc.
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|   Model HSTL135_C2_25ohm_SLEW-OFF_HSIO_O
[Model]   HSTL135_C2_25ohm_SLEW-OFF_HSIO_O
Model_type   Output
Polarity   Non-Inverting
Enable   Active-High
Vmeas =   0.675
Cref =   5p
Rref =   50
Vref =   0.675
|   typ   min   max
C_comp_pullup   1.335e-12   1.335e-12   1.380e-12
C_comp_pulldown  1.335e-12   1.335e-12   1.380e-12
[Temperature Range]  25C   125C   -55C
[Voltage Range]  1.35   1.2825   1.4175
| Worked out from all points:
|   slope of the pulldown table from 0 to 0.203 V, typ, clamps not added: 21.1 ohm
|   slope of the pullup table from 0 to 0.203 V, typ, clamps not added: 21.5 ohm
|   GND clamp passes 1 mA (typ) near -0.37 V on its own axis
|   POWER clamp passes 1 mA (typ) near -0.43 V on its own axis
|   rising waveform, R_fixture 50, V_fixture 0: 20-80 % time 101ps typ, 104ps min, 117ps max; typ from 0 V to 0.938 V
|   rising waveform, R_fixture 50, V_fixture 1.35: 20-80 % time 88.9ps typ, 87.8ps min, 99.2ps max; typ from 0.407 V to 1.35 V
|   falling waveform, R_fixture 50, V_fixture 0: 20-80 % time 82.7ps typ, 76.1ps min, 86.7ps max; typ from 0.938 V to 0 V
|   falling waveform, R_fixture 50, V_fixture 1.35: 20-80 % time 90.5ps typ, 90.6ps min, 91.1ps max; typ from 1.35 V to 0.407 V
[GND Clamp]
| Voltage   I(typ)   I(min)   I(max)
-930.2mV  -24.71mA   -18.84mA   -33.71mA
-708.7mV  -13.23mA   -10.13mA   -17.94mA
-620.2mV  -8.998mA   -7.114mA   -12.18mA
-531.6mV  -5.316mA   -4.482mA   -7.044mA
-487.3mV  -3.767mA   -3.362mA   -4.833mA
-443mV    -2.466mA   -2.401mA   -2.954mA
-398.7mV  -1.449mA   -1.613mA   -1.504mA
-354.4mV  -738.4uA   -1.007mA   -579.6uA
-310.1mV  -318.4uA   -576.7uA   -161.6uA
-221.5mV  -38.75uA   -142.9uA   -7.637uA
-44.3mV   -274.4nA   -3.251uA   -69.5nA
2.7V      0A         0A         0A
[POWER Clamp]
| Voltage   I(typ)   I(min)   I(max)
-1.35V    55.07mA    47.72mA    75.49mA
-1.196V   44.05mA    37.75mA    62.13mA
-974.5mV  29.03mA    24.41mA    40.95mA
-797.3mV  17.68mA    14.97mA    24.06mA
-664.5mV  10.01mA    8.871mA    12.44mA
-575.9mV  5.63mA     5.451mA    6.064mA
-531.6mV  3.786mA    3.983mA    3.599mA
-487.3mV  2.262mA    2.712mA    1.789mA
-443mV    1.133mA    1.675mA    684.4uA
-354.4mV  127.5uA    473.3uA    30.46uA
-221.5mV  1.715uA    56.89uA    636.6nA
2.7V      0A         0A         0A
[Pullup]
| Voltage   I(typ)   I(min)   I(max)
-1.35V    30.08mA    25.34mA    29.55mA
-885.9mV  27.55mA    26.31mA    26.36mA
-664.5mV  25.23mA    24.4mA     24.48mA
-487.3mV  21.68mA    21.09mA    20.88mA
-310.1mV  14.68mA    14.7mA     13.77mA
548.4mV   -24.49mA   -24.5mA    -22.71mA
801.6mV   -33.88mA   -33.4mA    -30.76mA
1.012V    -39.34mA   -38.09mA   -34.84mA
1.483V    -45.33mA   -43.24mA   -39.27mA
2.369V    -50.59mA   -47.87mA   -43.29mA
2.413V    -52.34mA   -48.04mA   -43.45mA
2.7V      -51.83mA   -49.1mA    -45.63mA
[Pulldown]
| Voltage   I(typ)   I(min)   I(max)
-1.35V    -38.38mA   -32.59mA   -31.87mA
-1.24V    -39.28mA   -34.1mA    -27.43mA
-1.152V   -38.7mA    -34.95mA   -26.2mA
-1.019V   -31.93mA   -35.04mA   -24.92mA
-575.9mV  -23.67mA   -25.33mA   -20.21mA
-354.4mV  -16.83mA   -17.47mA   -14.91mA
210.9mV   10.01mA    10.39mA    8.889mA
548.4mV   24.83mA    25.32mA    22.28mA
843.8mV   35.86mA    35.4mA     32.69mA
1.055V    41.64mA    39.28mA    38.79mA
1.394V    45.24mA    41.14mA    43.81mA
2.7V      48.72mA    44.04mA    47.42mA
[Ramp]
dV/dt_r   0.562621/0.100554n  0.535709/0.104478n  0.57662/0.117074n
dV/dt_f   0.565503/90.481p  0.542694/90.5939p  0.571749/91.1035p
R_load = 50
[Rising Waveform]
R_fixture = 50
V_fixture = 0
V_fixture_min = 0
V_fixture_max = 0
| Time   V(typ)   V(min)   V(max)
0s        1.369uV    2.163uV    1.941uV
1.022ns   -505.2uV   -429.9uV   8.024mV
1.208ns   -597.3uV   -508.5uV   814.5mV
1.313ns   3.624mV    -552.9uV   929.5mV
1.402ns   378.1mV    -590.5uV   947.5mV
1.537ns   887.5mV    -647.6uV   956.2mV
1.738ns   929.5mV    11.75mV    959.3mV
1.929ns   935.2mV    802.3mV    959.9mV
2.125ns   936.3mV    881.9mV    960.1mV
10ns      937.7mV    892.9mV    961mV
[Rising Waveform]
R_fixture = 50
V_fixture = 1.35
V_fixture_min = 1.2825
V_fixture_max = 1.4175
| Time   V(typ)   V(min)   V(max)
0s        407.5mV    378mV      464.6mV
931ps     407.9mV    378.5mV    473.4mV
1.105ns   408mV      378.6mV    1.309V
1.275ns   492.1mV    378.7mV    1.407V
1.392ns   1.2V       378.8mV    1.413V
1.447ns   1.303V     378.8mV    1.414V
1.679ns   1.345V     409.3mV    1.416V
1.82ns    1.348V     1.151V     1.416V
1.987ns   1.348V     1.27V      1.416V
10ns      1.35V      1.282V     1.417V
[Falling Waveform]
R_fixture = 50
V_fixture = 0
V_fixture_min = 0
V_fixture_max = 0
| Time   V(typ)   V(min)   V(max)
0s        937.7mV    892.9mV    961.1mV
911ps     937.1mV    892.3mV    948.7mV
1.05ns    937mV      892.2mV    150.6mV
1.22ns    931.8mV    892.1mV    10.83mV
1.399ns   92.04mV    892mV      3.236mV
1.557ns   9.229mV    891.9mV    1.763mV
1.702ns   3.467mV    844.2mV    1.328mV
1.821ns   2.034mV    132.4mV    990.6uV
1.95ns    1.364mV    13.77mV    826.5uV
10ns      2.123uV    3.106uV    2.463uV
[Falling Waveform]
R_fixture = 50
V_fixture = 1.35
V_fixture_min = 1.2825
V_fixture_max = 1.4175
| Time   V(typ)   V(min)   V(max)
0s        1.35V      1.282V     1.417V
979ps     1.351V     1.283V     1.425V
1.157ns   1.351V     1.283V     576mV
1.341ns   1.262V     1.283V     475mV
1.459ns   573.6mV    1.283V     469mV
1.52ns    455.9mV    1.283V     467.9mV
1.745ns   412.4mV    1.248V     466.5mV
1.888ns   409.9mV    512.7mV    466mV
2.098ns   409.1mV    385mV      465.5mV
10ns      407.5mV    378mV      464.6mV
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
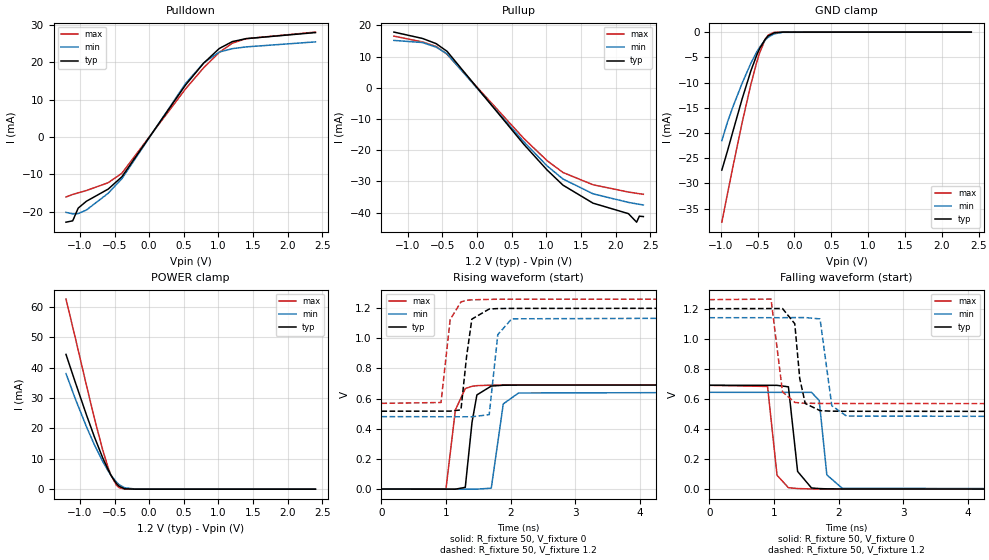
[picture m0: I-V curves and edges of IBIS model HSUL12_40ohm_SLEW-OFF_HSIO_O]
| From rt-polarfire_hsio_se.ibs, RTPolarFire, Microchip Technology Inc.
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|   Model HSUL12_40ohm_SLEW-OFF_HSIO_O
[Model]   HSUL12_40ohm_SLEW-OFF_HSIO_O
Model_type   Output
Polarity   Non-Inverting
Enable   Active-High
Vmeas =   0.6
Cref =   5p
Rref =   50
Vref =   0.6
|   typ   min   max
C_comp_pullup   1.335e-12   1.335e-12   1.380e-12
C_comp_pulldown  1.335e-12   1.335e-12   1.380e-12
[Temperature Range]  25C   125C   -55C
[Voltage Range]  1.2   1.14   1.26
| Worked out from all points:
|   slope of the pulldown table from 0 to 0.18 V, typ, clamps not added: 36.1 ohm
|   slope of the pullup table from 0 to 0.18 V, typ, clamps not added: 36.2 ohm
|   GND clamp passes 1 mA (typ) near -0.37 V on its own axis
|   POWER clamp passes 1 mA (typ) near -0.44 V on its own axis
|   rising waveform, R_fixture 50, V_fixture 0: 20-80 % time 94.4ps typ, 101ps min, 107ps max; typ from 0 V to 0.691 V
|   rising waveform, R_fixture 50, V_fixture 1.2: 20-80 % time 88.5ps typ, 85.5ps min, 97.9ps max; typ from 0.516 V to 1.2 V
|   falling waveform, R_fixture 50, V_fixture 0: 20-80 % time 81.3ps typ, 82.6ps min, 78.6ps max; typ from 0.691 V to 0 V
|   falling waveform, R_fixture 50, V_fixture 1.2: 20-80 % time 96.4ps typ, 99.4ps min, 93.1ps max; typ from 1.2 V to 0.516 V
[GND Clamp]
| Voltage   I(typ)   I(min)   I(max)
-984.4mV  -27.36mA   -21.51mA   -37.68mA
-905.6mV  -23.44mA   -17.74mA   -31.9mA
-826.9mV  -19.32mA   -14.54mA   -26.19mA
-708.7mV  -13.22mA   -10.13mA   -17.93mA
-590.6mV  -7.694mA   -6.183mA   -10.37mA
-511.9mV  -4.598mA   -3.964mA   -6.023mA
-472.5mV  -3.303mA   -3.022mA   -4.164mA
-393.7mV  -1.354mA   -1.536mA   -1.373mA
-354.4mV  -738.1uA   -1.006mA   -579.2uA
-275.6mV  -148.2uA   -350.2uA   -51.36uA
-157.5mV  -6.952uA   -42.62uA   -774.1nA
2.4V      0A         0A         0A
[POWER Clamp]
| Voltage   I(typ)   I(min)   I(max)
-1.2V     44.33mA    38.01mA    62.52mA
-1.063V   34.96mA    29.56mA    49.5mA
-905.6mV  24.47mA    20.57mA    34.21mA
-787.5mV  17.03mA    14.47mA    23.07mA
-669.4mV  10.26mA    9.06mA     12.82mA
-590.6mV  6.299mA    5.966mA    6.995mA
-551.3mV  4.569mA    4.604mA    4.604mA
-472.5mV  1.839mA    2.331mA    1.325mA
-433.1mV  941.2uA    1.473mA    512.6uA
-354.4mV  127.4uA    466.4uA    28.07uA
-196.9mV  963.6nA    26.23uA    495.2nA
2.4V      0A         0A         0A
[Pullup]
| Voltage   I(typ)   I(min)   I(max)
-1.2V     17.84mA    15.17mA    16.55mA
-787.5mV  15.8mA     14.49mA    14.69mA
-590.6mV  14.14mA    13.02mA    13.24mA
-433.1mV  11.68mA    10.88mA    10.72mA
675mV     -18.11mA   -17.31mA   -16.24mA
1.012V    -26.36mA   -25.04mA   -23.37mA
1.239V    -31.17mA   -29.21mA   -27.12mA
1.673V    -36.95mA   -33.95mA   -31.06mA
2.184V    -40.31mA   -36.71mA   -33.39mA
2.303V    -43.05mA   -37.17mA   -33.8mA
2.342V    -41.13mA   -37.32mA   -33.93mA
2.4V      -41.25mA   -37.53mA   -34.11mA
[Pulldown]
| Voltage   I(typ)   I(min)   I(max)
-1.2V     -22.85mA   -20.22mA   -16.09mA
-1.103V   -22.48mA   -20.62mA   -15.42mA
-1.024V   -19.08mA   -20.55mA   -14.99mA
-905.6mV  -17.24mA   -19.59mA   -14.37mA
-590.6mV  -13.98mA   -15.1mA    -12.27mA
-393.7mV  -10.69mA   -11.2mA    -9.745mA
525mV     13.89mA    14.29mA    12.85mA
787.5mV   19.77mA    19.82mA    18.53mA
1.012V    23.67mA    22.72mA    22.64mA
1.2V      25.52mA    23.63mA    25.09mA
1.397V    26.31mA    24.1mA     26.3mA
2.4V      27.94mA    25.45mA    28.07mA
[Ramp]
dV/dt_r   0.414402/94.363p  0.386478/0.101319n  0.414497/0.107487n
dV/dt_f   0.410251/96.3675p  0.395937/99.36p  0.415001/93.1008p
R_load = 50
[Rising Waveform]
R_fixture = 50
V_fixture = 0
V_fixture_min = 0
V_fixture_max = 0
| Time   V(typ)   V(min)   V(max)
0s        1.197uV    2.32uV     1.682uV
1ns       -779uV     -525.1uV   1.498mV
1.146ns   -892.9uV   -602.1uV   524.7mV
1.299ns   11.03mV    -682.8uV   666.5mV
1.404ns   443.8mV    -738.2uV   681.4mV
1.479ns   624.1mV    -777.8uV   685.5mV
1.702ns   683mV      5.707mV    689.2mV
1.888ns   688.4mV    564.6mV    689.8mV
2.126ns   689.6mV    637.2mV    689.9mV
10ns      690.7mV    644.1mV    690.8mV
[Rising Waveform]
R_fixture = 50
V_fixture = 1.2
V_fixture_min = 1.14
V_fixture_max = 1.26
| Time   V(typ)   V(min)   V(max)
0s        516.2mV    480.1mV    568.3mV
923ps     516.6mV    479.5mV    573.8mV
1.065ns   516.7mV    479.4mV    1.124V
1.232ns   525mV      479.3mV    1.241V
1.319ns   877.7mV    479.3mV    1.252V
1.401ns   1.127V     479.2mV    1.255V
1.67ns    1.194V     493.3mV    1.258V
1.803ns   1.197V     1.024V     1.259V
2.019ns   1.198V     1.129V     1.259V
10ns      1.2V       1.14V      1.26V
[Falling Waveform]
R_fixture = 50
V_fixture = 0
V_fixture_min = 0
V_fixture_max = 0
| Time   V(typ)   V(min)   V(max)
0s        690.7mV    644.1mV    690.8mV
900ps     690.4mV    643.9mV    682.9mV
1.047ns   690.3mV    643.8mV    92.24mV
1.223ns   680.5mV    643.8mV    9.752mV
1.365ns   117.8mV    643.7mV    4.092mV
1.58ns    7.931mV    643.5mV    1.543mV
1.699ns   3.938mV    589.3mV    1.237mV
1.817ns   2.244mV    95.13mV    940uV
2.056ns   1.181mV    5.637mV    666.4uV
10ns      2.181uV    3.714uV    2.461uV
[Falling Waveform]
R_fixture = 50
V_fixture = 1.2
V_fixture_min = 1.14
V_fixture_max = 1.26
| Time   V(typ)   V(min)   V(max)
0s        1.2V       1.14V      1.26V
954ps     1.201V     1.14V      1.264V
1.131ns   1.201V     1.14V      647.3mV
1.321ns   1.1V       1.141V     576.9mV
1.398ns   735.6mV    1.141V     573.3mV
1.483ns   569.5mV    1.141V     571.6mV
1.712ns   522.1mV    1.132V     570.1mV
1.894ns   518.5mV    554.8mV    569.7mV
2.122ns   517.8mV    486mV      569.3mV
10ns      516.2mV    480.1mV    568.3mV
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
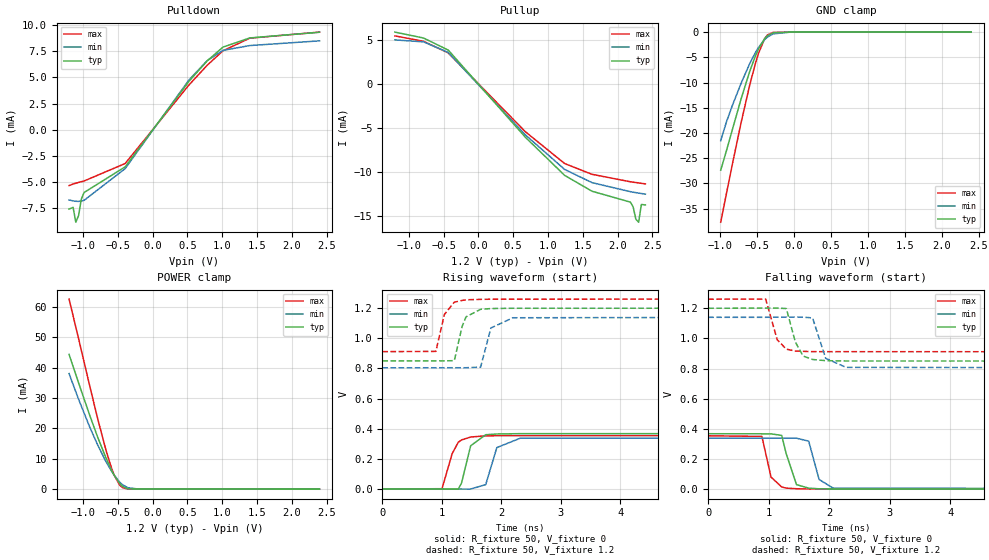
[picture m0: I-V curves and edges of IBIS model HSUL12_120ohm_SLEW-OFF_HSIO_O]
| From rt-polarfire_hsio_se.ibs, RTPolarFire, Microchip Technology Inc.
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|   Model HSUL12_120ohm_SLEW-OFF_HSIO_O
[Model]   HSUL12_120ohm_SLEW-OFF_HSIO_O
Model_type   Output
Polarity   Non-Inverting
Enable   Active-High
Vmeas =   0.6
Cref =   5p
Rref =   50
Vref =   0.6
|   typ   min   max
C_comp_pullup   1.335e-12   1.335e-12   1.380e-12
C_comp_pulldown  1.335e-12   1.335e-12   1.380e-12
[Temperature Range]  25C   125C   -55C
[Voltage Range]  1.2   1.14   1.26
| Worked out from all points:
|   slope of the pulldown table from 0 to 0.18 V, typ, clamps not added: 108 ohm
|   slope of the pullup table from 0 to 0.18 V, typ, clamps not added: 109 ohm
|   GND clamp passes 1 mA (typ) near -0.37 V on its own axis
|   POWER clamp passes 1 mA (typ) near -0.44 V on its own axis
|   rising waveform, R_fixture 50, V_fixture 0: 20-80 % time 144ps typ, 153ps min, 160ps max; typ from 0 V to 0.368 V
|   rising waveform, R_fixture 50, V_fixture 1.2: 20-80 % time 127ps typ, 130ps min, 130ps max; typ from 0.85 V to 1.2 V
|   falling waveform, R_fixture 50, V_fixture 0: 20-80 % time 118ps typ, 125ps min, 108ps max; typ from 0.368 V to 0 V
|   falling waveform, R_fixture 50, V_fixture 1.2: 20-80 % time 147ps typ, 156ps min, 145ps max; typ from 1.2 V to 0.85 V
[GND Clamp]
| Voltage   I(typ)   I(min)   I(max)
-984.4mV  -27.36mA   -21.51mA   -37.68mA
-905.6mV  -23.44mA   -17.74mA   -31.9mA
-826.9mV  -19.32mA   -14.54mA   -26.19mA
-708.7mV  -13.22mA   -10.13mA   -17.93mA
-590.6mV  -7.694mA   -6.183mA   -10.37mA
-511.9mV  -4.598mA   -3.964mA   -6.023mA
-472.5mV  -3.303mA   -3.022mA   -4.164mA
-393.7mV  -1.354mA   -1.536mA   -1.373mA
-354.4mV  -738.1uA   -1.006mA   -579.2uA
-275.6mV  -148.2uA   -350.2uA   -51.36uA
-39.38mV  -223.3nA   -2.753uA   -49.96nA
2.4V      0A         0A         0A
[POWER Clamp]
| Voltage   I(typ)   I(min)   I(max)
-1.2V     44.33mA    38.01mA    62.52mA
-1.063V   34.96mA    29.56mA    49.5mA
-905.6mV  24.47mA    20.57mA    34.21mA
-787.5mV  17.03mA    14.47mA    23.07mA
-669.4mV  10.26mA    9.06mA     12.82mA
-590.6mV  6.299mA    5.966mA    6.995mA
-551.3mV  4.569mA    4.604mA    4.604mA
-472.5mV  1.839mA    2.331mA    1.325mA
-433.1mV  941.2uA    1.473mA    512.6uA
-354.4mV  127.4uA    466.4uA    28.07uA
-196.9mV  963.6nA    26.23uA    495.2nA
2.4V      0A         0A         0A
[Pullup]
| Voltage   I(typ)   I(min)   I(max)
-1.2V     5.947mA    5.056mA    5.514mA
-787.5mV  5.268mA    4.832mA    4.894mA
-433.1mV  3.895mA    3.628mA    3.573mA
675mV     -6.042mA   -5.774mA   -5.415mA
1.239V    -10.39mA   -9.71mA    -9.042mA
1.633V    -12.2mA    -11.22mA   -10.27mA
2.184V    -13.44mA   -12.25mA   -11.12mA
2.224V    -13.98mA   -12.31mA   -11.17mA
2.263V    -15.39mA   -12.36mA   -11.21mA
2.303V    -15.73mA   -12.41mA   -11.25mA
2.342V    -13.71mA   -12.46mA   -11.3mA
2.4V      -13.76mA   -12.53mA   -11.36mA
[Pulldown]
| Voltage   I(typ)   I(min)   I(max)
-1.2V     -7.622mA   -6.744mA   -5.368mA
-1.142V   -7.458mA   -6.84mA    -5.223mA
-1.103V   -8.88mA    -6.876mA   -5.142mA
-1.063V   -8.243mA   -6.884mA   -5.067mA
-1.024V   -6.679mA   -6.855mA   -4.997mA
-984.4mV  -6.034mA   -6.786mA   -4.928mA
-393.7mV  -3.572mA   -3.742mA   -3.254mA
525mV     4.644mA    4.777mA    4.293mA
787.5mV   6.607mA    6.626mA    6.187mA
1.012V    7.912mA    7.599mA    7.559mA
1.397V    8.793mA    8.061mA    8.768mA
2.4V      9.338mA    8.513mA    9.353mA
[Ramp]
dV/dt_r   0.220678/0.144317n  0.203217/0.152957n  0.21248/0.159574n
dV/dt_f   0.210281/0.146668n  0.201568/0.155924n  0.209298/0.144623n
R_load = 50
[Rising Waveform]
R_fixture = 50
V_fixture = 0
V_fixture_min = 0
V_fixture_max = 0
| Time   V(typ)   V(min)   V(max)
0s        1.11uV     3.055uV    1.64uV
1.003ns   -552.8uV   -438.5uV   1.358mV
1.173ns   -646.6uV   -513.4uV   233.1mV
1.276ns   -1.593mV   -558.7uV   309.5mV
1.331ns   38.44mV    -582.9uV   325mV
1.485ns   286.6mV    -650.7uV   344.5mV
1.738ns   359.6mV    28.58mV    352.4mV
1.925ns   364.7mV    274.1mV    353.1mV
2.317ns   366.8mV    336.4mV    353.5mV
10ns      367.8mV    338.7mV    354.1mV
[Rising Waveform]
R_fixture = 50
V_fixture = 1.2
V_fixture_min = 1.14
V_fixture_max = 1.26
| Time   V(typ)   V(min)   V(max)
0s        849.5mV    804mV      911.1mV
900ps     850.1mV    804.2mV    912.7mV
1.043ns   850.1mV    804.2mV    1.158V
1.21ns    851.1mV    804.3mV    1.239V
1.341ns   1.078V     804.3mV    1.251V
1.407ns   1.142V     804.3mV    1.255V
1.652ns   1.192V     808.2mV    1.258V
1.825ns   1.197V     1.068V     1.259V
2.197ns   1.199V     1.136V     1.259V
10ns      1.2V       1.14V      1.26V
[Falling Waveform]
R_fixture = 50
V_fixture = 0
V_fixture_min = 0
V_fixture_max = 0
| Time   V(typ)   V(min)   V(max)
0s        367.8mV    338.7mV    354.1mV
887ps     367.2mV    338.2mV    349.9mV
1.038ns   367mV      338.1mV    80.15mV
1.215ns   356.5mV    338mV      14.56mV
1.286ns   238.4mV    338mV      6.863mV
1.459ns   30.03mV    337.9mV    2.842mV
1.66ns    6.799mV    318.6mV    1.166mV
1.832ns   2.441mV    64.19mV    1.014mV
2.062ns   829.1uV    7.66mV     809.9uV
10ns      620.3nV    4.565uV    3.199uV
[Falling Waveform]
R_fixture = 50
V_fixture = 1.2
V_fixture_min = 1.14
V_fixture_max = 1.26
| Time   V(typ)   V(min)   V(max)
0s        1.2V       1.14V      1.26V
949ps     1.201V     1.14V      1.261V
1.141ns   1.201V     1.141V     990.7mV
1.291ns   1.198V     1.141V     928.8mV
1.439ns   976.8mV    1.141V     916.1mV
1.567ns   883.2mV    1.141V     914.3mV
1.724ns   860.2mV    1.136V     912.2mV
1.94ns    852.3mV    868.3mV    912.1mV
2.276ns   850.3mV    808mV      912mV
10ns      849.5mV    804mV      911.2mV
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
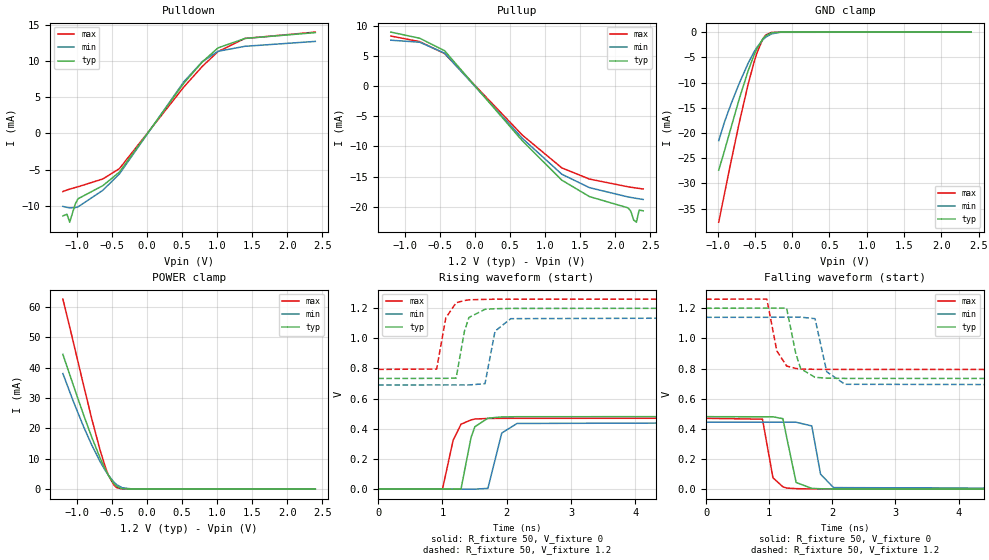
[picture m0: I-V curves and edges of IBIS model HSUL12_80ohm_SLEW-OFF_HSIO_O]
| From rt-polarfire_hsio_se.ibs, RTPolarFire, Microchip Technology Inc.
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|   Model HSUL12_80ohm_SLEW-OFF_HSIO_O
[Model]   HSUL12_80ohm_SLEW-OFF_HSIO_O
Model_type   Output
Polarity   Non-Inverting
Enable   Active-High
Vmeas =   0.6
Cref =   5p
Rref =   50
Vref =   0.6
|   typ   min   max
C_comp_pullup   1.335e-12   1.335e-12   1.380e-12
C_comp_pulldown  1.335e-12   1.335e-12   1.380e-12
[Temperature Range]  25C   125C   -55C
[Voltage Range]  1.2   1.14   1.26
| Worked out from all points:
|   slope of the pulldown table from 0 to 0.18 V, typ, clamps not added: 72 ohm
|   slope of the pullup table from 0 to 0.18 V, typ, clamps not added: 72.4 ohm
|   GND clamp passes 1 mA (typ) near -0.37 V on its own axis
|   POWER clamp passes 1 mA (typ) near -0.44 V on its own axis
|   rising waveform, R_fixture 50, V_fixture 0: 20-80 % time 129ps typ, 138ps min, 141ps max; typ from 0 V to 0.481 V
|   rising waveform, R_fixture 50, V_fixture 1.2: 20-80 % time 113ps typ, 114ps min, 123ps max; typ from 0.733 V to 1.2 V
|   falling waveform, R_fixture 50, V_fixture 0: 20-80 % time 105ps typ, 109ps min, 99.7ps max; typ from 0.481 V to 0 V
|   falling waveform, R_fixture 50, V_fixture 1.2: 20-80 % time 132ps typ, 135ps min, 127ps max; typ from 1.2 V to 0.733 V
[GND Clamp]
| Voltage   I(typ)   I(min)   I(max)
-984.4mV  -27.36mA   -21.51mA   -37.68mA
-905.6mV  -23.44mA   -17.74mA   -31.9mA
-826.9mV  -19.32mA   -14.54mA   -26.19mA
-708.7mV  -13.22mA   -10.13mA   -17.93mA
-590.6mV  -7.694mA   -6.183mA   -10.37mA
-511.9mV  -4.598mA   -3.964mA   -6.023mA
-472.5mV  -3.303mA   -3.022mA   -4.164mA
-393.7mV  -1.354mA   -1.536mA   -1.373mA
-354.4mV  -738.1uA   -1.006mA   -579.2uA
-275.6mV  -148.2uA   -350.2uA   -51.36uA
-157.5mV  -6.952uA   -42.62uA   -774.1nA
2.4V      0A         0A         0A
[POWER Clamp]
| Voltage   I(typ)   I(min)   I(max)
-1.2V     44.33mA    38.01mA    62.52mA
-1.063V   34.96mA    29.56mA    49.5mA
-905.6mV  24.47mA    20.57mA    34.21mA
-787.5mV  17.03mA    14.47mA    23.07mA
-669.4mV  10.26mA    9.06mA     12.82mA
-590.6mV  6.299mA    5.966mA    6.995mA
-551.3mV  4.569mA    4.604mA    4.604mA
-472.5mV  1.839mA    2.331mA    1.325mA
-433.1mV  941.2uA    1.473mA    512.6uA
-354.4mV  127.4uA    466.4uA    28.07uA
-196.9mV  963.6nA    26.23uA    495.2nA
2.4V      0A         0A         0A
[Pullup]
| Voltage   I(typ)   I(min)   I(max)
-1.2V     8.924mA    7.583mA    8.272mA
-787.5mV  7.902mA    7.247mA    7.341mA
-433.1mV  5.841mA    5.441mA    5.361mA
675mV     -9.059mA   -8.659mA   -8.123mA
1.239V    -15.59mA   -14.61mA   -13.56mA
1.633V    -18.31mA   -16.83mA   -15.41mA
2.184V    -20.18mA   -18.37mA   -16.69mA
2.224V    -20.75mA   -18.45mA   -16.76mA
2.263V    -22.18mA   -18.53mA   -16.83mA
2.303V    -22.55mA   -18.61mA   -16.89mA
2.342V    -20.56mA   -18.68mA   -16.96mA
2.4V      -20.66mA   -18.79mA   -17.05mA
[Pulldown]
| Voltage   I(typ)   I(min)   I(max)
-1.2V     -11.43mA   -10.11mA   -8.053mA
-1.142V   -11.2mA    -10.25mA   -7.837mA
-1.103V   -12.3mA    -10.31mA   -7.715mA
-1.024V   -9.787mA   -10.28mA   -7.498mA
-984.4mV  -9.054mA   -10.18mA   -7.394mA
-630mV    -7.237mA   -7.877mA   -6.308mA
-393.7mV  -5.356mA   -5.612mA   -4.878mA
525mV     6.959mA    7.16mA     6.435mA
787.5mV   9.899mA    9.929mA    9.275mA
1.012V    11.85mA    11.38mA    11.34mA
1.397V    13.16mA    12.07mA    13.16mA
2.4V      13.97mA    12.75mA    14.04mA
[Ramp]
dV/dt_r   0.288514/0.12946n  0.266929/0.137941n  0.281977/0.140815n
dV/dt_f   0.280002/0.131721n  0.269928/0.1348n  0.279928/0.127469n
R_load = 50
[Rising Waveform]
R_fixture = 50
V_fixture = 0
V_fixture_min = 0
V_fixture_max = 0
| Time   V(typ)   V(min)   V(max)
0s        1.141uV    2.792uV    1.654uV
1.001ns   -730.6uV   -517uV     902.6uV
1.166ns   -851.2uV   -602.7uV   323.6mV
1.289ns   1.167mV    -666.6uV   430.2mV
1.445ns   342.6mV    -747.6uV   458.3mV
1.505ns   413.4mV    -778.8uV   464.5mV
1.707ns   469.8mV    4.335mV    467.9mV
1.923ns   478.4mV    371.8mV    469mV
2.16ns    479.7mV    434.8mV    469.1mV
10ns      480.9mV    444.9mV    470mV
[Rising Waveform]
R_fixture = 50
V_fixture = 1.2
V_fixture_min = 1.14
V_fixture_max = 1.26
| Time   V(typ)   V(min)   V(max)
0s        733.3mV    690.1mV    793.4mV
909ps     734mV      690.2mV    795.8mV
1.052ns   734.1mV    690.2mV    1.135V
1.213ns   736.2mV    690.2mV    1.236V
1.341ns   1.045V     690.2mV    1.25V
1.412ns   1.138V     690.2mV    1.255V
1.662ns   1.192V     698.9mV    1.258V
1.818ns   1.196V     1.047V     1.259V
2.062ns   1.198V     1.13V      1.259V
10ns      1.2V       1.14V      1.26V
[Falling Waveform]
R_fixture = 50
V_fixture = 0
V_fixture_min = 0
V_fixture_max = 0
| Time   V(typ)   V(min)   V(max)
0s        480.9mV    444.9mV    470mV
893ps     480.1mV    444.3mV    464.2mV
1.059ns   480mV      444.2mV    75.36mV
1.216ns   467.8mV    444.1mV    15.61mV
1.276ns   344.3mV    444.1mV    7.359mV
1.426ns   44.61mV    444mV      3.396mV
1.674ns   5.148mV    419.3mV    1.373mV
1.813ns   2.809mV    99.29mV    915.4uV
2.02ns    1.212mV    10.31mV    755.1uV
10ns      2.079uV    4.799uV    2.665uV
[Falling Waveform]
R_fixture = 50
V_fixture = 1.2
V_fixture_min = 1.14
V_fixture_max = 1.26
| Time   V(typ)   V(min)   V(max)
0s        1.2V       1.14V      1.26V
962ps     1.201V     1.14V      1.261V
1.12ns    1.201V     1.141V     917.4mV
1.275ns   1.201V     1.141V     816.8mV
1.422ns   896.8mV    1.141V     800.8mV
1.499ns   798.7mV    1.141V     796.4mV
1.725ns   742mV      1.131V     795mV
1.911ns   736.1mV    778.7mV    794.7mV
2.199ns   734.7mV    695.7mV    794.3mV
10ns      733.3mV    690.1mV    793.4mV
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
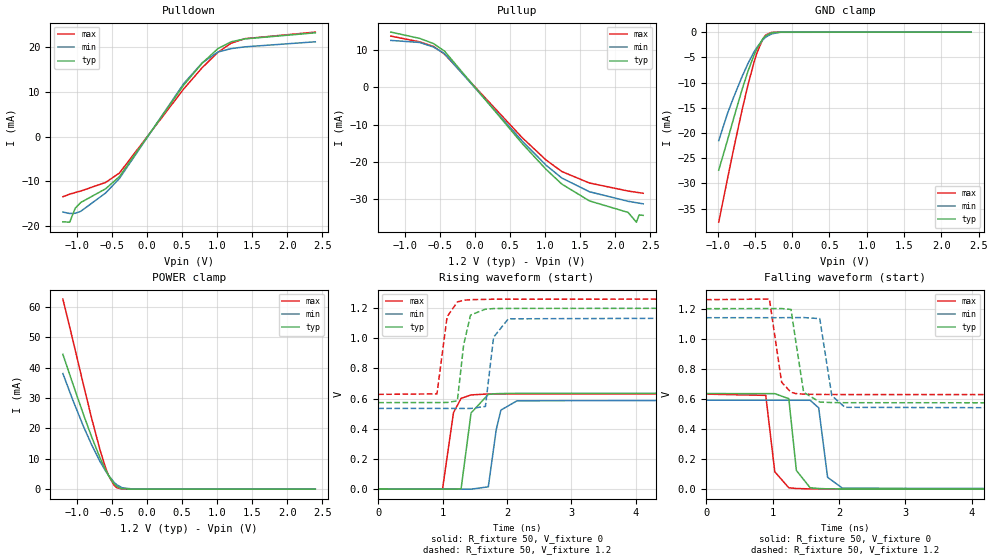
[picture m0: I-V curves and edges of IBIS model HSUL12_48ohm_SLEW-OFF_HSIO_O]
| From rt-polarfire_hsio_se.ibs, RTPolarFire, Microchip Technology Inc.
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|   Model HSUL12_48ohm_SLEW-OFF_HSIO_O
[Model]   HSUL12_48ohm_SLEW-OFF_HSIO_O
Model_type   Output
Polarity   Non-Inverting
Enable   Active-High
Vmeas =   0.6
Cref =   5p
Rref =   50
Vref =   0.6
|   typ   min   max
C_comp_pullup   1.335e-12   1.335e-12   1.380e-12
C_comp_pulldown  1.335e-12   1.335e-12   1.380e-12
[Temperature Range]  25C   125C   -55C
[Voltage Range]  1.2   1.14   1.26
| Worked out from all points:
|   slope of the pulldown table from 0 to 0.18 V, typ, clamps not added: 43.3 ohm
|   slope of the pullup table from 0 to 0.18 V, typ, clamps not added: 43.4 ohm
|   GND clamp passes 1 mA (typ) near -0.37 V on its own axis
|   POWER clamp passes 1 mA (typ) near -0.44 V on its own axis
|   rising waveform, R_fixture 50, V_fixture 0: 20-80 % time 102ps typ, 111ps min, 114ps max; typ from 0 V to 0.636 V
|   rising waveform, R_fixture 50, V_fixture 1.2: 20-80 % time 97.3ps typ, 93.6ps min, 106ps max; typ from 0.573 V to 1.2 V
|   falling waveform, R_fixture 50, V_fixture 0: 20-80 % time 84.1ps typ, 88.3ps min, 85ps max; typ from 0.636 V to 0 V
|   falling waveform, R_fixture 50, V_fixture 1.2: 20-80 % time 103ps typ, 110ps min, 103ps max; typ from 1.2 V to 0.573 V
[GND Clamp]
| Voltage   I(typ)   I(min)   I(max)
-984.4mV  -27.36mA   -21.51mA   -37.68mA
-866.2mV  -21.39mA   -16.1mA    -29.03mA
-787.5mV  -17.26mA   -13.03mA   -23.38mA
-669.4mV  -11.29mA   -8.751mA   -15.31mA
-590.6mV  -7.694mA   -6.183mA   -10.37mA
-511.9mV  -4.598mA   -3.964mA   -6.023mA
-472.5mV  -3.303mA   -3.022mA   -4.164mA
-393.7mV  -1.354mA   -1.536mA   -1.373mA
-354.4mV  -738.1uA   -1.006mA   -579.2uA
-275.6mV  -148.2uA   -350.2uA   -51.36uA
-157.5mV  -6.952uA   -42.62uA   -774.1nA
2.4V      0A         0A         0A
[POWER Clamp]
| Voltage   I(typ)   I(min)   I(max)
-1.2V     44.33mA    38.01mA    62.52mA
-1.063V   34.96mA    29.56mA    49.5mA
-905.6mV  24.47mA    20.57mA    34.21mA
-787.5mV  17.03mA    14.47mA    23.07mA
-669.4mV  10.26mA    9.06mA     12.82mA
-590.6mV  6.299mA    5.966mA    6.995mA
-551.3mV  4.569mA    4.604mA    4.604mA
-472.5mV  1.839mA    2.331mA    1.325mA
-433.1mV  941.2uA    1.473mA    512.6uA
-354.4mV  127.4uA    466.4uA    28.07uA
-196.9mV  963.6nA    26.23uA    495.2nA
2.4V      0A         0A         0A
[Pullup]
| Voltage   I(typ)   I(min)   I(max)
-1.2V     14.87mA    12.64mA    13.79mA
-787.5mV  13.17mA    12.08mA    12.24mA
-590.6mV  11.78mA    10.85mA    11.03mA
-433.1mV  9.734mA    9.067mA    8.93mA
675mV     -15.1mA    -14.43mA   -13.53mA
1.012V    -21.97mA   -20.87mA   -19.47mA
1.239V    -25.98mA   -24.35mA   -22.6mA
1.633V    -30.5mA    -28.04mA   -25.69mA
2.184V    -33.59mA   -30.6mA    -27.84mA
2.303V    -36.22mA   -30.98mA   -28.18mA
2.342V    -34.27mA   -31.1mA    -28.29mA
2.4V      -34.38mA   -31.28mA   -28.44mA
[Pulldown]
| Voltage   I(typ)   I(min)   I(max)
-1.2V     -19.04mA   -16.85mA   -13.42mA
-1.103V   -19.12mA   -17.18mA   -12.85mA
-1.024V   -15.99mA   -17.13mA   -12.49mA
-945mV    -14.71mA   -16.68mA   -12.15mA
-590.6mV  -11.65mA   -12.59mA   -10.23mA
-393.7mV  -8.917mA   -9.342mA   -8.126mA
525mV     11.58mA    11.92mA    10.72mA
787.5mV   16.47mA    16.53mA    15.45mA
1.012V    19.71mA    18.95mA    18.88mA
1.2V      21.23mA    19.71mA    20.92mA
1.397V    21.88mA    20.1mA     21.93mA
2.4V      23.24mA    21.23mA    23.4mA
[Ramp]
dV/dt_r   0.381439/0.102304n  0.35501/0.111197n  0.37921/0.113896n
dV/dt_f   0.37603/0.103114n  0.363155/0.109921n  0.37919/0.102534n
R_load = 50
[Rising Waveform]
R_fixture = 50
V_fixture = 0
V_fixture_min = 0
V_fixture_max = 0
| Time   V(typ)   V(min)   V(max)
0s        1.182uV    2.443uV    1.675uV
1ns       -553.1uV   -528.5uV   1.022mV
1.17ns    -647.3uV   -618.8uV   506.9mV
1.288ns   1.259mV    -681.5uV   601.4mV
1.443ns   504.8mV    -763.8uV   624.4mV
1.711ns   627.8mV    14.81mV    630.5mV
1.834ns   632.5mV    393.7mV    630.8mV
1.906ns   633.4mV    523.3mV    630.9mV
2.157ns   634.8mV    585.3mV    631.4mV
10ns      635.7mV    591.7mV    632mV
[Rising Waveform]
R_fixture = 50
V_fixture = 1.2
V_fixture_min = 1.14
V_fixture_max = 1.26
| Time   V(typ)   V(min)   V(max)
0s        573.3mV    534.7mV    628mV
913ps     573.9mV    534.6mV    631.1mV
1.071ns   574.1mV    534.5mV    1.143V
1.23ns    585mV      534.5mV    1.241V
1.328ns   956.8mV    534.5mV    1.252V
1.435ns   1.154V     534.5mV    1.256V
1.666ns   1.193V     548.1mV    1.258V
1.793ns   1.197V     1.007V     1.259V
2.022ns   1.198V     1.129V     1.259V
10ns      1.2V       1.14V      1.26V
[Falling Waveform]
R_fixture = 50
V_fixture = 0
V_fixture_min = 0
V_fixture_max = 0
| Time   V(typ)   V(min)   V(max)
0s        635.7mV    591.7mV    632mV
898ps     635.1mV    591.3mV    623.6mV
1.034ns   635mV      591.3mV    115.6mV
1.245ns   601.8mV    591.2mV    8.977mV
1.359ns   124.4mV    591.2mV    4.476mV
1.566ns   9.509mV    591.1mV    1.739mV
1.695ns   4.332mV    540.7mV    1.217mV
1.829ns   2.213mV    78.68mV    996.7uV
2.053ns   1.245mV    6.547mV    634.9uV
10ns      3.159uV    3.904uV    2.206uV
[Falling Waveform]
R_fixture = 50
V_fixture = 1.2
V_fixture_min = 1.14
V_fixture_max = 1.26
| Time   V(typ)   V(min)   V(max)
0s        1.2V       1.14V      1.26V
953ps     1.201V     1.14V      1.264V
1.137ns   1.201V     1.14V      710.8mV
1.278ns   1.195V     1.141V     644.2mV
1.349ns   986.6mV    1.141V     635.6mV
1.468ns   644.3mV    1.141V     631.8mV
1.711ns   579.2mV    1.134V     629.8mV
1.892ns   575.7mV    622.1mV    629.4mV
2.09ns    574.9mV    544.2mV    629mV
10ns      573.3mV    534.7mV    628mV
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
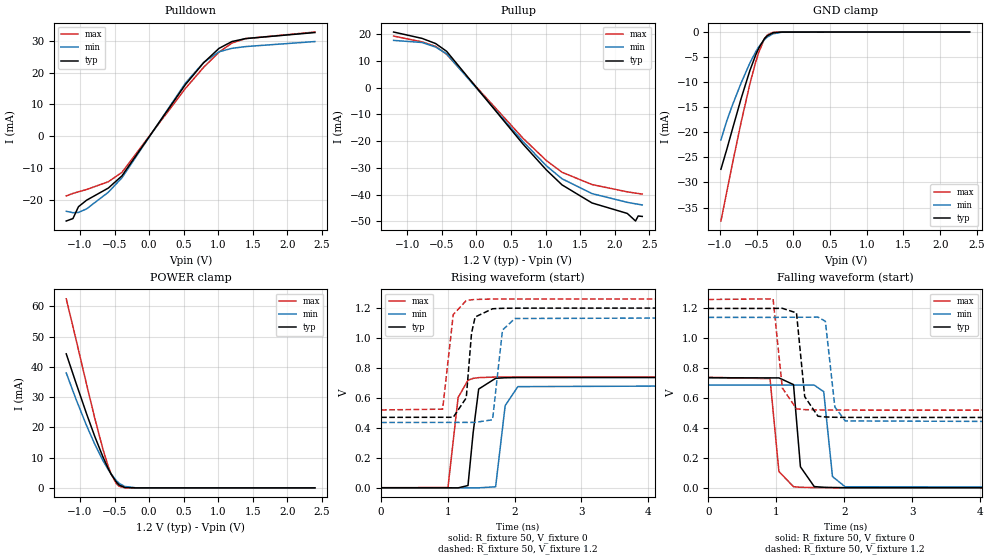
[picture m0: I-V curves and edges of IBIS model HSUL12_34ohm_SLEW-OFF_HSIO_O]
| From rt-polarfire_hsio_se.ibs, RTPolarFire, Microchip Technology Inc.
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|   Model HSUL12_34ohm_SLEW-OFF_HSIO_O
[Model]   HSUL12_34ohm_SLEW-OFF_HSIO_O
Model_type   Output
Polarity   Non-Inverting
Enable   Active-High
Vmeas =   0.6
Cref =   5p
Rref =   50
Vref =   0.6
|   typ   min   max
C_comp_pullup   1.335e-12   1.335e-12   1.380e-12
C_comp_pulldown  1.335e-12   1.335e-12   1.380e-12
[Temperature Range]  25C   125C   -55C
[Voltage Range]  1.2   1.14   1.26
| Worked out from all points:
|   slope of the pulldown table from 0 to 0.18 V, typ, clamps not added: 30.9 ohm
|   slope of the pullup table from 0 to 0.18 V, typ, clamps not added: 31 ohm
|   GND clamp passes 1 mA (typ) near -0.37 V on its own axis
|   POWER clamp passes 1 mA (typ) near -0.44 V on its own axis
|   rising waveform, R_fixture 50, V_fixture 0: 20-80 % time 86.8ps typ, 93.6ps min, 98.5ps max; typ from 0 V to 0.736 V
|   rising waveform, R_fixture 50, V_fixture 1.2: 20-80 % time 83.7ps typ, 85.6ps min, 95.4ps max; typ from 0.469 V to 1.2 V
|   falling waveform, R_fixture 50, V_fixture 0: 20-80 % time 76ps typ, 74.2ps min, 73.2ps max; typ from 0.736 V to 0 V
|   falling waveform, R_fixture 50, V_fixture 1.2: 20-80 % time 88.5ps typ, 91ps min, 84.6ps max; typ from 1.2 V to 0.469 V
[GND Clamp]
| Voltage   I(typ)   I(min)   I(max)
-984.4mV  -27.36mA   -21.51mA   -37.68mA
-905.6mV  -23.44mA   -17.74mA   -31.9mA
-826.9mV  -19.32mA   -14.54mA   -26.19mA
-708.7mV  -13.22mA   -10.13mA   -17.93mA
-590.6mV  -7.694mA   -6.183mA   -10.37mA
-511.9mV  -4.598mA   -3.964mA   -6.023mA
-472.5mV  -3.303mA   -3.022mA   -4.164mA
-393.7mV  -1.354mA   -1.536mA   -1.373mA
-354.4mV  -738.1uA   -1.006mA   -579.2uA
-275.6mV  -148.2uA   -350.2uA   -51.36uA
-157.5mV  -6.952uA   -42.62uA   -774.1nA
2.4V      0A         0A         0A
[POWER Clamp]
| Voltage   I(typ)   I(min)   I(max)
-1.2V     44.33mA    38.01mA    62.52mA
-1.063V   34.96mA    29.56mA    49.5mA
-905.6mV  24.47mA    20.57mA    34.21mA
-787.5mV  17.03mA    14.47mA    23.07mA
-669.4mV  10.26mA    9.06mA     12.82mA
-590.6mV  6.299mA    5.966mA    6.995mA
-551.3mV  4.569mA    4.604mA    4.604mA
-472.5mV  1.839mA    2.331mA    1.325mA
-433.1mV  941.2uA    1.473mA    512.6uA
-354.4mV  127.4uA    466.4uA    28.07uA
-196.9mV  963.6nA    26.23uA    495.2nA
2.4V      0A         0A         0A
[Pullup]
| Voltage   I(typ)   I(min)   I(max)
-1.2V     20.82mA    17.69mA    19.31mA
-787.5mV  18.44mA    16.91mA    17.13mA
-590.6mV  16.5mA     15.19mA    15.44mA
-433.1mV  13.63mA    12.69mA    12.5mA
675mV     -21.13mA   -20.2mA    -18.94mA
1.012V    -30.76mA   -29.21mA   -27.26mA
1.239V    -36.36mA   -34.08mA   -31.64mA
1.673V    -43.12mA   -39.62mA   -36.24mA
2.184V    -47.04mA   -42.89mA   -38.96mA
2.303V    -49.87mA   -43.44mA   -39.43mA
2.342V    -47.98mA   -43.61mA   -39.58mA
2.4V      -48.16mA   -43.86mA   -39.8mA
[Pulldown]
| Voltage   I(typ)   I(min)   I(max)
-1.2V     -26.66mA   -23.6mA    -18.77mA
-1.103V   -25.88mA   -24.05mA   -17.99mA
-1.024V   -22.18mA   -23.98mA   -17.48mA
-905.6mV  -20.12mA   -22.85mA   -16.76mA
-590.6mV  -16.3mA    -17.61mA   -14.31mA
-393.7mV  -12.47mA   -13.07mA   -11.37mA
525mV     16.2mA     16.68mA    14.99mA
787.5mV   23.05mA    23.14mA    21.61mA
1.012V    27.6mA     26.54mA    26.41mA
1.2V      29.75mA    27.61mA    29.27mA
1.397V    30.67mA    28.16mA    30.67mA
2.4V      32.57mA    29.74mA    32.73mA
[Ramp]
dV/dt_r   0.441644/86.7812p  0.412613/93.5641p  0.443808/98.4942p
dV/dt_f   0.438311/88.4934p  0.422862/91.0134p  0.44465/84.6356p
R_load = 50
[Rising Waveform]
R_fixture = 50
V_fixture = 0
V_fixture_min = 0
V_fixture_max = 0
| Time   V(typ)   V(min)   V(max)
0s        1.209uV    2.219uV    1.689uV
1.001ns   -700.3uV   -513.7uV   1.786mV
1.153ns   -806.8uV   -592uV     601.7mV
1.301ns   14.68mV    -668.3uV   717.3mV
1.379ns   370.3mV    -708.5uV   729.6mV
1.461ns   658.3mV    -750.8uV   734.5mV
1.715ns   729.9mV    6.406mV    738.5mV
1.858ns   733.6mV    547.8mV    738.6mV
2.049ns   734.9mV    674.5mV    738.8mV
10ns      736.1mV    687.7mV    739.7mV
[Rising Waveform]
R_fixture = 50
V_fixture = 1.2
V_fixture_min = 1.14
V_fixture_max = 1.26
| Time   V(typ)   V(min)   V(max)
0s        469.5mV    435.2mV    518.9mV
921ps     470mV      435.7mV    524.2mV
1.08ns    470mV      435.7mV    1.155V
1.275ns   599.7mV    435.8mV    1.249V
1.354ns   1.031V     435.9mV    1.254V
1.408ns   1.139V     435.9mV    1.256V
1.669ns   1.194V     453.5mV    1.259V
1.818ns   1.197V     1.052V     1.259V
2.004ns   1.198V     1.129V     1.259V
10ns      1.2V       1.14V      1.26V
[Falling Waveform]
R_fixture = 50
V_fixture = 0
V_fixture_min = 0
V_fixture_max = 0
| Time   V(typ)   V(min)   V(max)
0s        736.1mV    687.7mV    739.7mV
906ps     735.5mV    687.4mV    730.4mV
1.037ns   735.4mV    687.3mV    109.5mV
1.252ns   690.6mV    687.3mV    7.574mV
1.354ns   140.7mV    687.2mV    3.922mV
1.557ns   8.582mV    687.2mV    1.58mV
1.697ns   3.652mV    643.2mV    1.243mV
1.826ns   2.069mV    75.41mV    1.062mV
2.013ns   1.204mV    7.286mV    799.8uV
10ns      2.227uV    3.307uV    2.427uV
[Falling Waveform]
R_fixture = 50
V_fixture = 1.2
V_fixture_min = 1.14
V_fixture_max = 1.26
| Time   V(typ)   V(min)   V(max)
0s        1.2V       1.14V      1.26V
951ps     1.2V       1.14V      1.264V
1.087ns   1.201V     1.141V     668.7mV
1.296ns   1.17V      1.141V     528.2mV
1.417ns   610mV      1.141V     523.1mV
1.612ns   479mV      1.142V     521.1mV
1.721ns   474.1mV    1.114V     520.6mV
1.861ns   471.9mV    541mV      520.2mV
2.014ns   471.2mV    447.6mV    520mV
10ns      469.5mV    435.2mV    518.9mV
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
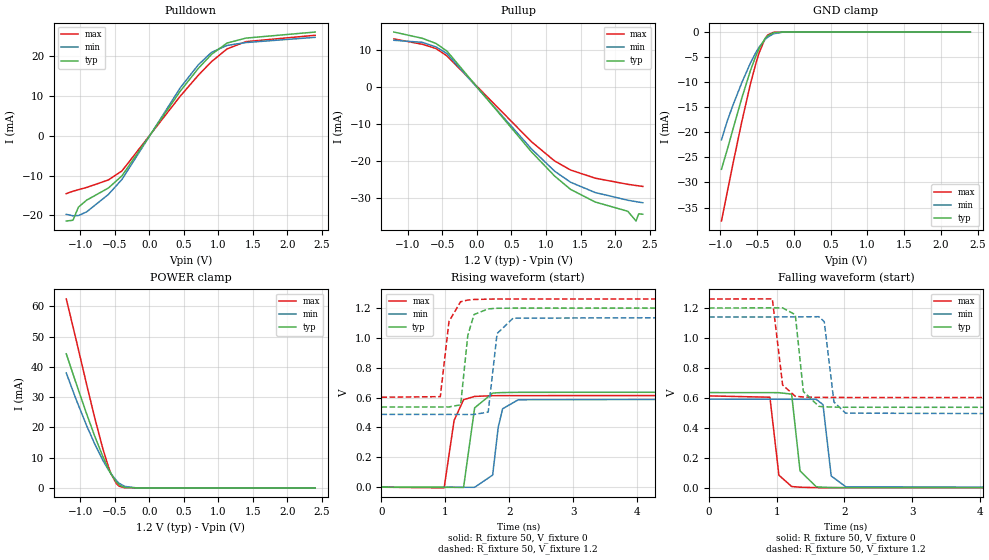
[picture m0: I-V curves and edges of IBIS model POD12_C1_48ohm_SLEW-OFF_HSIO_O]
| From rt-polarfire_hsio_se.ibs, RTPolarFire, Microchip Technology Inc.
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|   Model POD12_C1_48ohm_SLEW-OFF_HSIO_O
[Model]   POD12_C1_48ohm_SLEW-OFF_HSIO_O
Model_type   Output
Polarity   Non-Inverting
Enable   Active-High
Vmeas =   0.84
Cref =   5p
Rref =   50
Vref =   0.84
|   typ   min   max
C_comp_pullup   1.335e-12   1.335e-12   1.380e-12
C_comp_pulldown  1.335e-12   1.335e-12   1.380e-12
[Temperature Range]  25C   125C   -55C
[Voltage Range]  1.2   1.14   1.26
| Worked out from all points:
|   slope of the pulldown table from 0 to 0.18 V, typ, clamps not added: 38.5 ohm
|   slope of the pullup table from 0 to 0.18 V, typ, clamps not added: 43.4 ohm
|   GND clamp passes 1 mA (typ) near -0.37 V on its own axis
|   POWER clamp passes 1 mA (typ) near -0.44 V on its own axis
|   rising waveform, R_fixture 50, V_fixture 0: 20-80 % time 104ps typ, 108ps min, 115ps max; typ from 0 V to 0.636 V
|   rising waveform, R_fixture 50, V_fixture 1.2: 20-80 % time 93.9ps typ, 91.2ps min, 101ps max; typ from 0.536 V to 1.2 V
|   falling waveform, R_fixture 50, V_fixture 0: 20-80 % time 71.8ps typ, 79.4ps min, 70.4ps max; typ from 0.636 V to 0 V
|   falling waveform, R_fixture 50, V_fixture 1.2: 20-80 % time 87.3ps typ, 93.8ps min, 85.7ps max; typ from 1.2 V to 0.536 V
[GND Clamp]
| Voltage   I(typ)   I(min)   I(max)
-984.4mV  -27.36mA   -21.51mA   -37.68mA
-905.6mV  -23.44mA   -17.74mA   -31.9mA
-826.9mV  -19.32mA   -14.54mA   -26.19mA
-708.7mV  -13.22mA   -10.13mA   -17.93mA
-590.6mV  -7.694mA   -6.183mA   -10.37mA
-511.9mV  -4.598mA   -3.964mA   -6.023mA
-472.5mV  -3.303mA   -3.022mA   -4.164mA
-393.7mV  -1.354mA   -1.536mA   -1.373mA
-354.4mV  -738.1uA   -1.006mA   -579.2uA
-275.6mV  -148.2uA   -350.2uA   -51.36uA
-157.5mV  -6.952uA   -42.62uA   -774.1nA
2.4V      0A         0A         0A
[POWER Clamp]
| Voltage   I(typ)   I(min)   I(max)
-1.2V     44.33mA    38.01mA    62.52mA
-1.063V   34.96mA    29.56mA    49.5mA
-905.6mV  24.47mA    20.57mA    34.21mA
-787.5mV  17.03mA    14.47mA    23.07mA
-669.4mV  10.26mA    9.06mA     12.82mA
-590.6mV  6.299mA    5.966mA    6.995mA
-551.3mV  4.569mA    4.604mA    4.604mA
-472.5mV  1.839mA    2.331mA    1.325mA
-433.1mV  941.2uA    1.473mA    512.6uA
-354.4mV  127.4uA    466.4uA    28.07uA
-196.9mV  963.6nA    26.23uA    495.2nA
2.4V      0A         0A         0A
[Pullup]
| Voltage   I(typ)   I(min)   I(max)
-1.2V     14.87mA    12.64mA    13.02mA
-787.5mV  13.17mA    12.08mA    11.56mA
-590.6mV  11.78mA    10.85mA    10.42mA
-433.1mV  9.734mA    9.067mA    8.434mA
787.5mV   -17.46mA   -16.67mA   -14.74mA
1.125V    -24.06mA   -22.74mA   -19.98mA
1.357V    -27.68mA   -25.75mA   -22.44mA
1.712V    -31.08mA   -28.52mA   -24.64mA
2.184V    -33.59mA   -30.6mA    -26.3mA
2.303V    -36.22mA   -30.98mA   -26.62mA
2.342V    -34.27mA   -31.1mA    -26.72mA
2.4V      -34.38mA   -31.28mA   -26.87mA
[Pulldown]
| Voltage   I(typ)   I(min)   I(max)
-1.2V     -21.42mA   -19.73mA   -14.53mA
-1.103V   -21.23mA   -20.11mA   -13.92mA
-1.024V   -17.93mA   -20.05mA   -13.53mA
-905.6mV  -16.17mA   -19.12mA   -12.97mA
-590.6mV  -13.11mA   -14.73mA   -11.08mA
-393.7mV  -10.03mA   -10.93mA   -8.8mA
450mV     11.3mA     12.15mA    10.04mA
712.5mV   17.06mA    17.96mA    15.33mA
900mV     20.52mA    21.03mA    18.69mA
1.125V    23.38mA    22.79mA    21.91mA
1.397V    24.63mA    23.51mA    23.74mA
2.4V      26.16mA    24.83mA    25.34mA
[Ramp]
dV/dt_r   0.381439/0.10407n  0.355013/0.107598n  0.368077/0.115375n
dV/dt_f   0.398258/87.2498p  0.391503/93.772p  0.39492/85.726p
R_load = 50
[Rising Waveform]
R_fixture = 50
V_fixture = 0
V_fixture_min = 0
V_fixture_max = 0
| Time   V(typ)   V(min)   V(max)
0s        1.192uV    2.337uV    1.678uV
981ps     -782.8uV   -518.5uV   -4.306mV
1.137ns   -907.4uV   -601.3uV   446.6mV
1.285ns   -1.266mV   -679.9uV   585.6mV
1.458ns   530.8mV    -771.8uV   607.3mV
1.74ns    629.5mV    81.38mV    612mV
1.827ns   632.1mV    401.9mV    612.5mV
1.896ns   633.1mV    524.8mV    612.7mV
2.141ns   634.7mV    585.2mV    612.7mV
10ns      635.7mV    591.7mV    613.5mV
[Rising Waveform]
R_fixture = 50
V_fixture = 1.2
V_fixture_min = 1.14
V_fixture_max = 1.26
| Time   V(typ)   V(min)   V(max)
0s        536.2mV    487.4mV    601.8mV
921ps     536.8mV    486.9mV    605.8mV
1.057ns   536.9mV    486.8mV    1.11V
1.239ns   551.1mV    486.7mV    1.241V
1.351ns   1.015V     486.6mV    1.252V
1.448ns   1.155V     486.6mV    1.256V
1.67ns    1.193V     502.6mV    1.258V
1.809ns   1.197V     1.028V     1.259V
2.06ns    1.198V     1.131V     1.259V
10ns      1.2V       1.14V      1.26V
[Falling Waveform]
R_fixture = 50
V_fixture = 0
V_fixture_min = 0
V_fixture_max = 0
| Time   V(typ)   V(min)   V(max)
0s        635.7mV    591.7mV    613.5mV
899ps     635.2mV    591.3mV    604.7mV
1.032ns   635.1mV    591.2mV    84.54mV
1.22ns    625.4mV    591.1mV    8.87mV
1.344ns   113.8mV    591.1mV    4.198mV
1.583ns   6.861mV    590.8mV    1.45mV
1.683ns   3.772mV    554.9mV    1.218mV
1.804ns   2.176mV    79.31mV    1.096mV
2.021ns   1.206mV    6.698mV    877.5uV
10ns      2.225uV    3.521uV    2.384uV
[Falling Waveform]
R_fixture = 50
V_fixture = 1.2
V_fixture_min = 1.14
V_fixture_max = 1.26
| Time   V(typ)   V(min)   V(max)
0s        1.2V       1.14V      1.26V
935ps     1.201V     1.14V      1.261V
1.087ns   1.201V     1.141V     686mV
1.274ns   1.155V     1.141V     611.1mV
1.393ns   642.8mV    1.141V     606.2mV
1.622ns   543.8mV    1.142V     603.8mV
1.701ns   540.8mV    1.109V     603.5mV
1.845ns   538.6mV    573.1mV    603.3mV
2.015ns   537.8mV    498.5mV    603mV
10ns      536.2mV    487.4mV    601.8mV
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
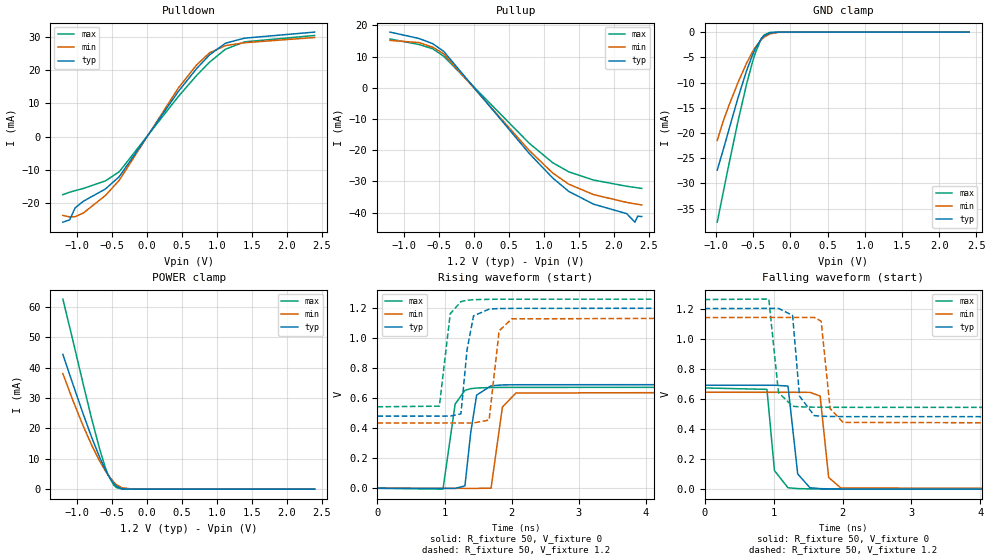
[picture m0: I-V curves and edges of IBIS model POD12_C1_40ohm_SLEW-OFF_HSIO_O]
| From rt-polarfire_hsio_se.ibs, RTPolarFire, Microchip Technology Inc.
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|   Model POD12_C1_40ohm_SLEW-OFF_HSIO_O
[Model]   POD12_C1_40ohm_SLEW-OFF_HSIO_O
Model_type   Output
Polarity   Non-Inverting
Enable   Active-High
Vmeas =   0.84
Cref =   5p
Rref =   50
Vref =   0.84
|   typ   min   max
C_comp_pullup   1.335e-12   1.335e-12   1.380e-12
C_comp_pulldown  1.335e-12   1.335e-12   1.380e-12
[Temperature Range]  25C   125C   -55C
[Voltage Range]  1.2   1.14   1.26
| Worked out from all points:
|   slope of the pulldown table from 0 to 0.18 V, typ, clamps not added: 32.1 ohm
|   slope of the pullup table from 0 to 0.18 V, typ, clamps not added: 36.2 ohm
|   GND clamp passes 1 mA (typ) near -0.37 V on its own axis
|   POWER clamp passes 1 mA (typ) near -0.44 V on its own axis
|   rising waveform, R_fixture 50, V_fixture 0: 20-80 % time 94.8ps typ, 97.9ps min, 105ps max; typ from 0 V to 0.691 V
|   rising waveform, R_fixture 50, V_fixture 1.2: 20-80 % time 88.1ps typ, 87ps min, 95.3ps max; typ from 0.48 V to 1.2 V
|   falling waveform, R_fixture 50, V_fixture 0: 20-80 % time 66.1ps typ, 73.8ps min, 64.5ps max; typ from 0.691 V to 0 V
|   falling waveform, R_fixture 50, V_fixture 1.2: 20-80 % time 78.1ps typ, 85.3ps min, 78ps max; typ from 1.2 V to 0.48 V
[GND Clamp]
| Voltage   I(typ)   I(min)   I(max)
-984.4mV  -27.36mA   -21.51mA   -37.68mA
-905.6mV  -23.44mA   -17.74mA   -31.9mA
-826.9mV  -19.32mA   -14.54mA   -26.19mA
-708.7mV  -13.22mA   -10.13mA   -17.93mA
-590.6mV  -7.694mA   -6.183mA   -10.37mA
-511.9mV  -4.598mA   -3.964mA   -6.023mA
-472.5mV  -3.303mA   -3.022mA   -4.164mA
-393.7mV  -1.354mA   -1.536mA   -1.373mA
-354.4mV  -738.1uA   -1.006mA   -579.2uA
-275.6mV  -148.2uA   -350.2uA   -51.36uA
-157.5mV  -6.952uA   -42.62uA   -774.1nA
2.4V      0A         0A         0A
[POWER Clamp]
| Voltage   I(typ)   I(min)   I(max)
-1.2V     44.33mA    38.01mA    62.52mA
-1.063V   34.96mA    29.56mA    49.5mA
-905.6mV  24.47mA    20.57mA    34.21mA
-787.5mV  17.03mA    14.47mA    23.07mA
-669.4mV  10.26mA    9.06mA     12.82mA
-590.6mV  6.299mA    5.966mA    6.995mA
-551.3mV  4.569mA    4.604mA    4.604mA
-472.5mV  1.839mA    2.331mA    1.325mA
-433.1mV  941.2uA    1.473mA    512.6uA
-354.4mV  127.4uA    466.4uA    28.07uA
-196.9mV  963.6nA    26.23uA    495.2nA
2.4V      0A         0A         0A
[Pullup]
| Voltage   I(typ)   I(min)   I(max)
-1.2V     17.84mA    15.17mA    15.63mA
-787.5mV  15.8mA     14.49mA    13.87mA
-590.6mV  14.14mA    13.02mA    12.5mA
-433.1mV  11.68mA    10.88mA    10.12mA
787.5mV   -20.95mA   -20mA      -17.7mA
1.125V    -28.86mA   -27.28mA   -23.98mA
1.357V    -33.21mA   -30.89mA   -26.93mA
1.712V    -37.29mA   -34.22mA   -29.56mA
2.184V    -40.31mA   -36.71mA   -31.54mA
2.303V    -43.05mA   -37.17mA   -31.92mA
2.342V    -41.13mA   -37.32mA   -32.05mA
2.4V      -41.25mA   -37.53mA   -32.22mA
[Pulldown]
| Voltage   I(typ)   I(min)   I(max)
-1.2V     -25.71mA   -23.67mA   -17.43mA
-1.103V   -25.01mA   -24.13mA   -16.7mA
-1.024V   -21.4mA    -24.06mA   -16.23mA
-905.6mV  -19.39mA   -22.93mA   -15.56mA
-590.6mV  -15.72mA   -17.67mA   -13.29mA
-393.7mV  -12.03mA   -13.11mA   -10.56mA
450mV     13.55mA    14.58mA    12.04mA
712.5mV   20.46mA    21.56mA    18.39mA
900mV     24.63mA    25.24mA    22.42mA
1.125V    28.08mA    27.36mA    26.28mA
1.397V    29.6mA     28.23mA    28.49mA
2.4V      31.43mA    29.81mA    30.41mA
[Ramp]
dV/dt_r   0.414403/94.7878p  0.386474/97.8654p  0.403502/0.104619n
dV/dt_f   0.431775/78.0534p  0.42334/85.3169p  0.430452/78.0053p
R_load = 50
[Rising Waveform]
R_fixture = 50
V_fixture = 0
V_fixture_min = 0
V_fixture_max = 0
| Time   V(typ)   V(min)   V(max)
0s        1.206uV    2.218uV    1.685uV
976ps     -621.4uV   -532.5uV   -5.992mV
1.157ns   -736.9uV   -631.6uV   560.3mV
1.303ns   15.8mV     -711.6uV   652mV
1.389ns   370.1mV    -758.7uV   663.3mV
1.477ns   620.1mV    -806.9uV   667.6mV
1.692ns   682.6mV    491.1uV    670.9mV
1.861ns   688.1mV    540.7mV    671.7mV
2.062ns   689.5mV    634mV      671.7mV
10ns      690.7mV    644.1mV    672.5mV
[Rising Waveform]
R_fixture = 50
V_fixture = 1.2
V_fixture_min = 1.14
V_fixture_max = 1.26
| Time   V(typ)   V(min)   V(max)
0s        480.4mV    434.4mV    542.6mV
922ps     480.7mV    434.8mV    546.7mV
1.084ns   480.8mV    434.9mV    1.162V
1.243ns   495.2mV    434.9mV    1.243V
1.335ns   923.6mV    435mV      1.252V
1.431ns   1.148V     435mV      1.256V
1.663ns   1.193V     454.3mV    1.258V
1.812ns   1.197V     1.048V     1.259V
2ns       1.198V     1.128V     1.259V
10ns      1.2V       1.14V      1.26V
[Falling Waveform]
R_fixture = 50
V_fixture = 0
V_fixture_min = 0
V_fixture_max = 0
| Time   V(typ)   V(min)   V(max)
0s        690.7mV    644.1mV    672.5mV
904ps     690.3mV    643.6mV    663mV
1.013ns   690.3mV    643.5mV    123.3mV
1.209ns   684.9mV    643.4mV    9.287mV
1.35ns    101.2mV    643.3mV    3.897mV
1.527ns   9.647mV    643.2mV    1.687mV
1.675ns   3.6mV      619.1mV    1.175mV
1.799ns   2.106mV    77.59mV    914.9uV
1.976ns   1.314mV    7.827mV    750.3uV
10ns      -1.008uV   3.327uV    2.471uV
[Falling Waveform]
R_fixture = 50
V_fixture = 1.2
V_fixture_min = 1.14
V_fixture_max = 1.26
| Time   V(typ)   V(min)   V(max)
0s        1.2V       1.14V      1.26V
931ps     1.201V     1.141V     1.263V
1.071ns   1.201V     1.141V     641.9mV
1.276ns   1.154V     1.141V     551mV
1.376ns   618.3mV    1.141V     547.1mV
1.59ns    488.8mV    1.141V     544.6mV
1.69ns    484.8mV    1.116V     544.3mV
1.82ns    482.8mV    535.2mV    544.1mV
2.008ns   482mV      443.6mV    543.8mV
10ns      480.4mV    434.4mV    542.6mV
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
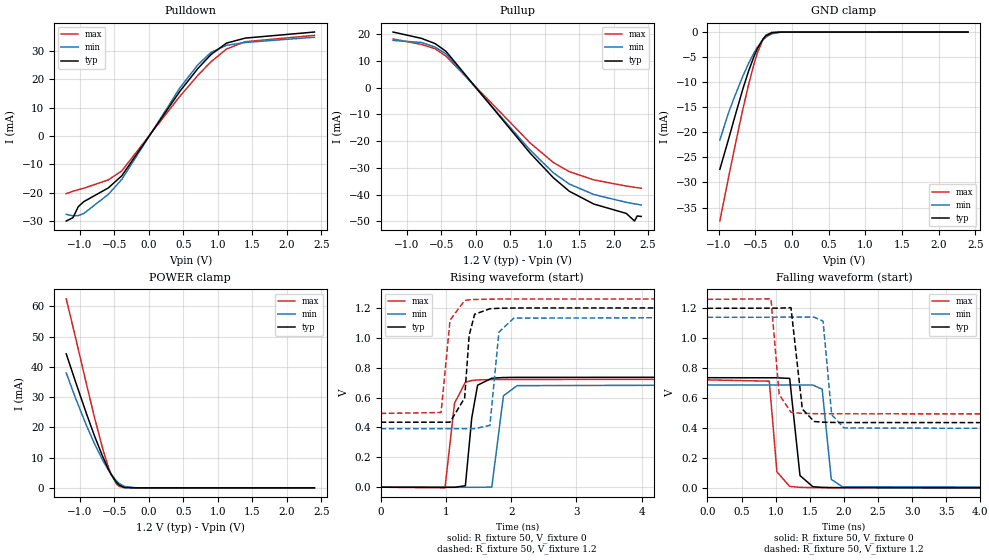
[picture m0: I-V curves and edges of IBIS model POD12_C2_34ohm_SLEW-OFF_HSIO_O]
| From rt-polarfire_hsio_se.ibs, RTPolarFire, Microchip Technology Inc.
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|   Model POD12_C2_34ohm_SLEW-OFF_HSIO_O
[Model]   POD12_C2_34ohm_SLEW-OFF_HSIO_O
Model_type   Output
Polarity   Non-Inverting
Enable   Active-High
Vmeas =   0.84
Cref =   5p
Rref =   50
Vref =   0.84
|   typ   min   max
C_comp_pullup   1.335e-12   1.335e-12   1.380e-12
C_comp_pulldown  1.335e-12   1.335e-12   1.380e-12
[Temperature Range]  25C   125C   -55C
[Voltage Range]  1.2   1.14   1.26
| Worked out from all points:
|   slope of the pulldown table from 0 to 0.18 V, typ, clamps not added: 27.5 ohm
|   slope of the pullup table from 0 to 0.18 V, typ, clamps not added: 31 ohm
|   GND clamp passes 1 mA (typ) near -0.37 V on its own axis
|   POWER clamp passes 1 mA (typ) near -0.44 V on its own axis
|   rising waveform, R_fixture 50, V_fixture 0: 20-80 % time 88.1ps typ, 89.5ps min, 97.7ps max; typ from 0 V to 0.736 V
|   rising waveform, R_fixture 50, V_fixture 1.2: 20-80 % time 79.6ps typ, 81.7ps min, 89.1ps max; typ from 0.435 V to 1.2 V
|   falling waveform, R_fixture 50, V_fixture 0: 20-80 % time 61.7ps typ, 68.1ps min, 60.1ps max; typ from 0.736 V to 0 V
|   falling waveform, R_fixture 50, V_fixture 1.2: 20-80 % time 71.9ps typ, 78ps min, 71.5ps max; typ from 1.2 V to 0.435 V
[GND Clamp]
| Voltage   I(typ)   I(min)   I(max)
-984.4mV  -27.36mA   -21.51mA   -37.68mA
-866.2mV  -21.39mA   -16.1mA    -29.03mA
-787.5mV  -17.26mA   -13.03mA   -23.38mA
-669.4mV  -11.29mA   -8.751mA   -15.31mA
-590.6mV  -7.694mA   -6.183mA   -10.37mA
-511.9mV  -4.598mA   -3.964mA   -6.023mA
-472.5mV  -3.303mA   -3.022mA   -4.164mA
-393.7mV  -1.354mA   -1.536mA   -1.373mA
-354.4mV  -738.1uA   -1.006mA   -579.2uA
-275.6mV  -148.2uA   -350.2uA   -51.36uA
-157.5mV  -6.952uA   -42.62uA   -774.1nA
2.4V      0A         0A         0A
[POWER Clamp]
| Voltage   I(typ)   I(min)   I(max)
-1.2V     44.33mA    38.01mA    62.52mA
-1.063V   34.96mA    29.56mA    49.5mA
-905.6mV  24.47mA    20.57mA    34.21mA
-787.5mV  17.03mA    14.47mA    23.07mA
-669.4mV  10.26mA    9.06mA     12.82mA
-590.6mV  6.299mA    5.966mA    6.995mA
-551.3mV  4.569mA    4.604mA    4.604mA
-472.5mV  1.839mA    2.331mA    1.325mA
-433.1mV  941.2uA    1.473mA    512.6uA
-354.4mV  127.4uA    466.4uA    28.07uA
-196.9mV  963.6nA    26.23uA    495.2nA
2.4V      0A         0A         0A
[Pullup]
| Voltage   I(typ)   I(min)   I(max)
-1.2V     20.82mA    17.69mA    18.23mA
-787.5mV  18.44mA    16.91mA    16.18mA
-590.6mV  16.5mA     15.19mA    14.58mA
-433.1mV  13.63mA    12.69mA    11.81mA
787.5mV   -24.44mA   -23.33mA   -20.64mA
1.125V    -33.67mA   -31.83mA   -27.97mA
1.357V    -38.74mA   -36.04mA   -31.42mA
1.712V    -43.52mA   -39.95mA   -34.48mA
2.184V    -47.04mA   -42.89mA   -36.8mA
2.303V    -49.87mA   -43.44mA   -37.25mA
2.342V    -47.98mA   -43.61mA   -37.39mA
2.4V      -48.16mA   -43.86mA   -37.6mA
[Pulldown]
| Voltage   I(typ)   I(min)   I(max)
-1.2V     -29.99mA   -27.63mA   -20.34mA
-1.103V   -28.83mA   -28.16mA   -19.49mA
-1.024V   -24.89mA   -28.07mA   -18.94mA
-945mV    -23.16mA   -27.33mA   -18.42mA
-590.6mV  -18.34mA   -20.62mA   -15.5mA
-393.7mV  -14.03mA   -15.3mA    -12.31mA
450mV     15.8mA     17.01mA    14.05mA
712.5mV   23.87mA    25.17mA    21.45mA
900mV     28.72mA    29.47mA    26.16mA
1.125V    32.74mA    31.96mA    30.66mA
1.397V    34.51mA    32.97mA    33.24mA
2.4V      36.65mA    34.82mA    35.47mA
[Ramp]
dV/dt_r   0.441646/88.149p  0.412612/89.4974p  0.433047/97.7081p
dV/dt_f   0.459061/71.9289p  0.449085/78.038p  0.459806/71.481p
R_load = 50
[Rising Waveform]
R_fixture = 50
V_fixture = 0
V_fixture_min = 0
V_fixture_max = 0
| Time   V(typ)   V(min)   V(max)
0s        1.218uV    2.121uV    1.691uV
986ps     -475.8uV   -406.2uV   -4.159mV
1.132ns   -546.5uV   -466.6uV   561.6mV
1.298ns   9.89mV     -535.3uV   702.3mV
1.396ns   464mV      -575.9uV   713.8mV
1.485ns   682.4mV    -612.8uV   717.6mV
1.703ns   729.2mV    990.9uV    720.3mV
1.881ns   733.9mV    611.2mV    720.9mV
2.091ns   735mV      679.6mV    721.1mV
10ns      736.1mV    687.7mV    721.7mV
[Rising Waveform]
R_fixture = 50
V_fixture = 1.2
V_fixture_min = 1.14
V_fixture_max = 1.26
| Time   V(typ)   V(min)   V(max)
0s        434.9mV    391.5mV    493.7mV
926ps     435mV      391.6mV    499.7mV
1.063ns   435mV      391.6mV    1.118V
1.287ns   597mV      391.6mV    1.249V
1.356ns   1.016V     391.6mV    1.254V
1.44ns    1.157V     391.6mV    1.256V
1.674ns   1.194V     413.9mV    1.258V
1.812ns   1.197V     1.038V     1.259V
2.041ns   1.199V     1.131V     1.259V
10ns      1.2V       1.14V      1.26V
[Falling Waveform]
R_fixture = 50
V_fixture = 0
V_fixture_min = 0
V_fixture_max = 0
| Time   V(typ)   V(min)   V(max)
0s        736.1mV    687.7mV    721.7mV
906ps     735.6mV    687.4mV    713mV
1.018ns   735.5mV    687.4mV    107.2mV
1.205ns   731.3mV    687.3mV    9.024mV
1.356ns   81.95mV    687.3mV    3.535mV
1.545ns   7.558mV    687.2mV    1.541mV
1.681ns   3.214mV    659mV      1.1mV
1.815ns   1.883mV    56.03mV    837.5uV
1.977ns   1.192mV    7.213mV    817.4uV
10ns      1.248uV    3.325uV    6.545uV
[Falling Waveform]
R_fixture = 50
V_fixture = 1.2
V_fixture_min = 1.14
V_fixture_max = 1.26
| Time   V(typ)   V(min)   V(max)
0s        1.2V       1.14V      1.26V
931ps     1.201V     1.14V      1.263V
1.051ns   1.201V     1.141V     624.5mV
1.224ns   1.204V     1.141V     505.1mV
1.39ns    526.9mV    1.141V     497.4mV
1.562ns   443.7mV    1.141V     495.8mV
1.694ns   438.8mV    1.114V     495.2mV
1.82ns    437.1mV    488.9mV    495mV
2ns       436.5mV    400.2mV    494.7mV
10ns      434.9mV    391.5mV    493.6mV
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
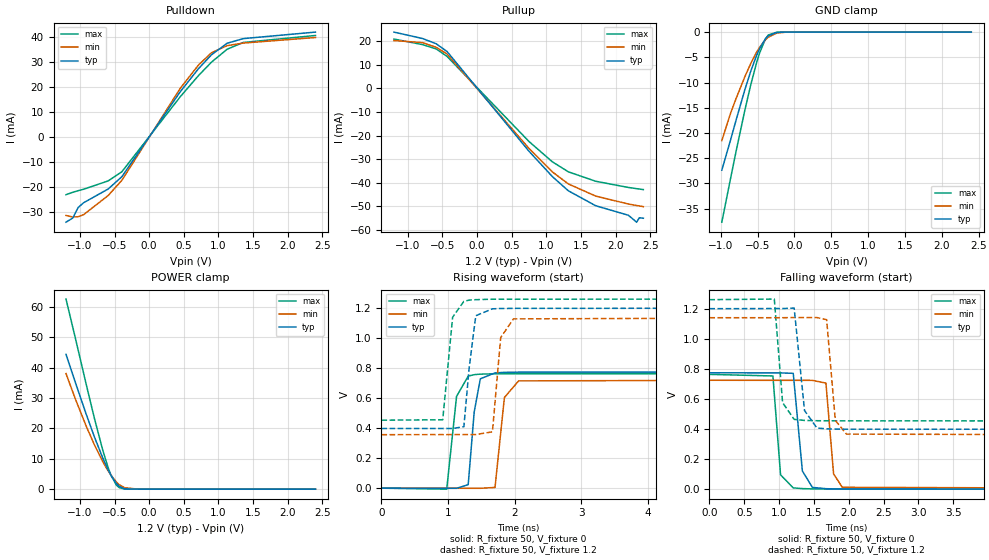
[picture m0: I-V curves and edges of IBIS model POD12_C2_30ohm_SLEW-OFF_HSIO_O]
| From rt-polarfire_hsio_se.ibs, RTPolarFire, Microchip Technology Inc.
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|   Model POD12_C2_30ohm_SLEW-OFF_HSIO_O
[Model]   POD12_C2_30ohm_SLEW-OFF_HSIO_O
Model_type   Output
Polarity   Non-Inverting
Enable   Active-High
Vmeas =   0.84
Cref =   5p
Rref =   50
Vref =   0.84
|   typ   min   max
C_comp_pullup   1.335e-12   1.335e-12   1.380e-12
C_comp_pulldown  1.335e-12   1.335e-12   1.380e-12
[Temperature Range]  25C   125C   -55C
[Voltage Range]  1.2   1.14   1.26
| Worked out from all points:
|   slope of the pulldown table from 0 to 0.18 V, typ, clamps not added: 24.1 ohm
|   slope of the pullup table from 0 to 0.18 V, typ, clamps not added: 27.2 ohm
|   GND clamp passes 1 mA (typ) near -0.37 V on its own axis
|   POWER clamp passes 1 mA (typ) near -0.44 V on its own axis
|   rising waveform, R_fixture 50, V_fixture 0: 20-80 % time 81.6ps typ, 84.8ps min, 89.2ps max; typ from 0 V to 0.774 V
|   rising waveform, R_fixture 50, V_fixture 1.2: 20-80 % time 78.3ps typ, 75.9ps min, 84.3ps max; typ from 0.397 V to 1.2 V
|   falling waveform, R_fixture 50, V_fixture 0: 20-80 % time 57.3ps typ, 65.6ps min, 56.1ps max; typ from 0.774 V to 0 V
|   falling waveform, R_fixture 50, V_fixture 1.2: 20-80 % time 67.4ps typ, 73.3ps min, 66.4ps max; typ from 1.2 V to 0.397 V
[GND Clamp]
| Voltage   I(typ)   I(min)   I(max)
-984.4mV  -27.36mA   -21.51mA   -37.68mA
-866.2mV  -21.39mA   -16.1mA    -29.03mA
-787.5mV  -17.26mA   -13.03mA   -23.38mA
-669.4mV  -11.29mA   -8.751mA   -15.31mA
-590.6mV  -7.694mA   -6.183mA   -10.37mA
-511.9mV  -4.598mA   -3.964mA   -6.023mA
-472.5mV  -3.303mA   -3.022mA   -4.164mA
-393.7mV  -1.354mA   -1.536mA   -1.373mA
-354.4mV  -738.1uA   -1.006mA   -579.2uA
-236.2mV  -56.59uA   -184.9uA   -12.91uA
-118.1mV  -2.32uA    -19.01uA   -220.7nA
2.4V      0A         0A         0A
[POWER Clamp]
| Voltage   I(typ)   I(min)   I(max)
-1.2V     44.33mA    38.01mA    62.52mA
-1.063V   34.96mA    29.56mA    49.5mA
-905.6mV  24.47mA    20.57mA    34.21mA
-787.5mV  17.03mA    14.47mA    23.07mA
-669.4mV  10.26mA    9.06mA     12.82mA
-590.6mV  6.299mA    5.966mA    6.995mA
-551.3mV  4.569mA    4.604mA    4.604mA
-472.5mV  1.839mA    2.331mA    1.325mA
-433.1mV  941.2uA    1.473mA    512.6uA
-354.4mV  127.4uA    466.4uA    28.07uA
-157.5mV  613.8nA    9.044uA    471.7nA
2.4V      0A         0A         0A
[Pullup]
| Voltage   I(typ)   I(min)   I(max)
-1.2V     23.79mA    20.22mA    20.84mA
-787.5mV  21.07mA    19.32mA    18.49mA
-590.6mV  18.85mA    17.36mA    16.67mA
-433.1mV  15.57mA    14.5mA     13.49mA
750mV     -26.68mA   -25.48mA   -22.55mA
1.087V    -37.4mA    -35.41mA   -31.15mA
1.318V    -43.42mA   -40.5mA    -35.38mA
1.712V    -49.73mA   -45.65mA   -39.37mA
2.184V    -53.76mA   -49.01mA   -41.99mA
2.303V    -56.7mA    -49.63mA   -42.5mA
2.342V    -54.83mA   -49.83mA   -42.66mA
2.4V      -55.03mA   -50.11mA   -42.9mA
[Pulldown]
| Voltage   I(typ)   I(min)   I(max)
-1.2V     -34.26mA   -31.57mA   -23.24mA
-1.103V   -32.62mA   -32.18mA   -22.27mA
-1.024V   -28.36mA   -32.07mA   -21.64mA
-945mV    -26.45mA   -31.23mA   -21.05mA
-590.6mV  -20.95mA   -23.55mA   -17.71mA
-393.7mV  -16.03mA   -17.48mA   -14.06mA
450mV     18.06mA    19.43mA    16.04mA
712.5mV   27.27mA    28.73mA    24.5mA
900mV     32.82mA    33.64mA    29.87mA
1.125V    37.43mA    36.48mA    35.03mA
1.357V    39.29mA    37.51mA    37.76mA
2.4V      41.91mA    39.74mA    40.55mA
[Ramp]
dV/dt_r   0.464353/81.5672p  0.434441/84.8061p  0.457946/89.1724p
dV/dt_f   0.481633/67.3724p  0.470091/73.3305p  0.484123/66.3651p
R_load = 50
[Rising Waveform]
R_fixture = 50
V_fixture = 0
V_fixture_min = 0
V_fixture_max = 0
| Time   V(typ)   V(min)   V(max)
0s        1.228uV    2.041uV    1.696uV
981ps     -650.8uV   -519.9uV   -6.548mV
1.129ns   -749.2uV   -598.6uV   611.6mV
1.304ns   23.53mV    -691.7uV   746.6mV
1.394ns   507.3mV    -739.6uV   756.3mV
1.486ns   728.5mV    -788.6uV   759.8mV
1.707ns   768.2mV    5.093mV    762.1mV
1.848ns   771.7mV    604.2mV    762.2mV
2.062ns   773mV      714.9mV    762.4mV
10ns      773.9mV    724.1mV    763.2mV
[Rising Waveform]
R_fixture = 50
V_fixture = 1.2
V_fixture_min = 1.14
V_fixture_max = 1.26
| Time   V(typ)   V(min)   V(max)
0s        397.3mV    356.5mV    453.1mV
921ps     397.6mV    357mV      455.9mV
1.07ns    397.7mV    357.1mV    1.139V
1.239ns   409.7mV    357.2mV    1.245V
1.318ns   800.4mV    357.2mV    1.253V
1.418ns   1.149V     357.3mV    1.256V
1.668ns   1.195V     375.4mV    1.259V
1.792ns   1.197V     1.003V     1.259V
1.984ns   1.198V     1.128V     1.259V
10ns      1.2V       1.14V      1.26V
[Falling Waveform]
R_fixture = 50
V_fixture = 0
V_fixture_min = 0
V_fixture_max = 0
| Time   V(typ)   V(min)   V(max)
0s        773.9mV    724.1mV    763.2mV
912ps     773.2mV    723.7mV    752.7mV
1.022ns   773.1mV    723.7mV    95.09mV
1.204ns   770.1mV    723.6mV    8.568mV
1.335ns   120.8mV    723.6mV    3.768mV
1.479ns   11.79mV    723.5mV    1.832mV
1.673ns   3.178mV    705.1mV    1.073mV
1.783ns   1.939mV    100.9mV    989.5uV
1.908ns   1.196mV    12.34mV    895.1uV
10ns      330.5nV    3.195uV    2.21uV
[Falling Waveform]
R_fixture = 50
V_fixture = 1.2
V_fixture_min = 1.14
V_fixture_max = 1.26
| Time   V(typ)   V(min)   V(max)
0s        1.2V       1.14V      1.26V
932ps     1.201V     1.14V      1.264V
1.051ns   1.201V     1.14V      575.4mV
1.217ns   1.204V     1.141V     464.2mV
1.366ns   522.7mV    1.141V     457.1mV
1.544ns   406.6mV    1.141V     455.1mV
1.683ns   400.9mV    1.127V     454.8mV
1.808ns   399.4mV    456.3mV    454.5mV
1.969ns   398.8mV    366.1mV    454.2mV
10ns      397.3mV    356.5mV    453.1mV
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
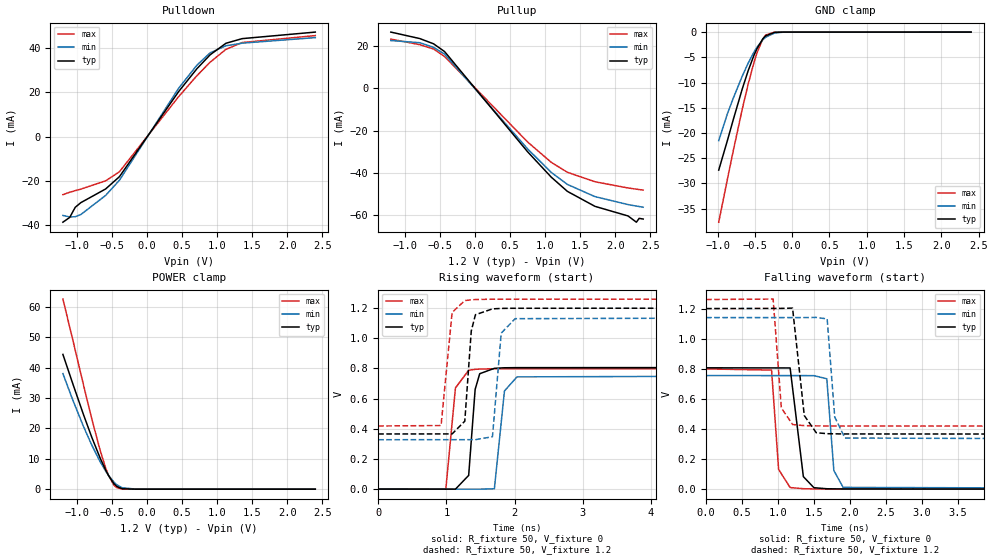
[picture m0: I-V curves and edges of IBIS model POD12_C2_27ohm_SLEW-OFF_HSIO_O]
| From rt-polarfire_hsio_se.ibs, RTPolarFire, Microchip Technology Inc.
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|   Model POD12_C2_27ohm_SLEW-OFF_HSIO_O
[Model]   POD12_C2_27ohm_SLEW-OFF_HSIO_O
Model_type   Output
Polarity   Non-Inverting
Enable   Active-High
Vmeas =   0.84
Cref =   5p
Rref =   50
Vref =   0.84
|   typ   min   max
C_comp_pullup   1.335e-12   1.335e-12   1.380e-12
C_comp_pulldown  1.335e-12   1.335e-12   1.380e-12
[Temperature Range]  25C   125C   -55C
[Voltage Range]  1.2   1.14   1.26
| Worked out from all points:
|   slope of the pulldown table from 0 to 0.18 V, typ, clamps not added: 21.4 ohm
|   slope of the pullup table from 0 to 0.18 V, typ, clamps not added: 24.1 ohm
|   GND clamp passes 1 mA (typ) near -0.37 V on its own axis
|   POWER clamp passes 1 mA (typ) near -0.44 V on its own axis
|   rising waveform, R_fixture 50, V_fixture 0: 20-80 % time 76.6ps typ, 78.6ps min, 85.8ps max; typ from 0 V to 0.806 V
|   rising waveform, R_fixture 50, V_fixture 1.2: 20-80 % time 76.7ps typ, 70.6ps min, 81.6ps max; typ from 0.365 V to 1.2 V
|   falling waveform, R_fixture 50, V_fixture 0: 20-80 % time 53.4ps typ, 61.9ps min, 52.8ps max; typ from 0.806 V to 0 V
|   falling waveform, R_fixture 50, V_fixture 1.2: 20-80 % time 63.3ps typ, 68.1ps min, 62.4ps max; typ from 1.2 V to 0.365 V
[GND Clamp]
| Voltage   I(typ)   I(min)   I(max)
-984.4mV  -27.36mA   -21.51mA   -37.68mA
-866.2mV  -21.39mA   -16.1mA    -29.03mA
-787.5mV  -17.26mA   -13.03mA   -23.38mA
-669.4mV  -11.29mA   -8.751mA   -15.31mA
-590.6mV  -7.694mA   -6.183mA   -10.37mA
-511.9mV  -4.598mA   -3.964mA   -6.023mA
-472.5mV  -3.303mA   -3.022mA   -4.164mA
-393.7mV  -1.354mA   -1.536mA   -1.373mA
-354.4mV  -738.1uA   -1.006mA   -579.2uA
-236.2mV  -56.59uA   -184.9uA   -12.91uA
-118.1mV  -2.32uA    -19.01uA   -220.7nA
2.4V      0A         0A         0A
[POWER Clamp]
| Voltage   I(typ)   I(min)   I(max)
-1.2V     44.33mA    38.01mA    62.52mA
-1.063V   34.96mA    29.56mA    49.5mA
-905.6mV  24.47mA    20.57mA    34.21mA
-787.5mV  17.03mA    14.47mA    23.07mA
-669.4mV  10.26mA    9.06mA     12.82mA
-590.6mV  6.299mA    5.966mA    6.995mA
-551.3mV  4.569mA    4.604mA    4.604mA
-472.5mV  1.839mA    2.331mA    1.325mA
-433.1mV  941.2uA    1.473mA    512.6uA
-354.4mV  127.4uA    466.4uA    28.07uA
-157.5mV  613.8nA    9.044uA    471.7nA
2.4V      0A         0A         0A
[Pullup]
| Voltage   I(typ)   I(min)   I(max)
-1.2V     26.77mA    22.75mA    23.44mA
-787.5mV  23.7mA     21.74mA    20.8mA
-590.6mV  21.21mA    19.53mA    18.75mA
-433.1mV  17.52mA    16.32mA    15.18mA
750mV     -30.02mA   -28.66mA   -25.37mA
1.087V    -42.07mA   -39.83mA   -35.05mA
1.318V    -48.85mA   -45.56mA   -39.8mA
1.712V    -55.98mA   -51.36mA   -44.3mA
2.184V    -60.54mA   -55.14mA   -47.25mA
2.303V    -63.5mA    -55.85mA   -47.82mA
2.342V    -61.68mA   -56.07mA   -48.01mA
2.4V      -62mA      -56.39mA   -48.27mA
[Pulldown]
| Voltage   I(typ)   I(min)   I(max)
-1.2V     -38.56mA   -35.51mA   -26.14mA
-1.103V   -36.42mA   -36.2mA    -25.05mA
-1.024V   -31.85mA   -36.08mA   -24.34mA
-945mV    -29.76mA   -35.13mA   -23.67mA
-590.6mV  -23.57mA   -26.49mA   -19.92mA
-393.7mV  -18.03mA   -19.65mA   -15.82mA
450mV     20.32mA    21.84mA    18.04mA
712.5mV   30.7mA     32.31mA    27.56mA
900mV     36.95mA    37.83mA    33.6mA
1.125V    42.14mA    41.03mA    39.4mA
1.357V    44.24mA    42.19mA    42.47mA
2.4V      47.19mA    44.7mA     45.61mA
[Ramp]
dV/dt_r   0.483708/76.5964p  0.453072/78.6045p  0.479402/85.7719p
dV/dt_f   0.500829/63.301p  0.487662/68.1117p  0.504952/62.35p
R_load = 50
[Rising Waveform]
R_fixture = 50
V_fixture = 0
V_fixture_min = 0
V_fixture_max = 0
| Time   V(typ)   V(min)   V(max)
0s        1.236uV    1.975uV    1.7uV
992ps     -594.3uV   -470.5uV   11.21uV
1.133ns   -678.9uV   -537.6uV   670.9mV
1.327ns   90.63mV    -630uV     787.5mV
1.422ns   661.2mV    -675.3uV   793.8mV
1.489ns   764.9mV    -707.2uV   795.8mV
1.704ns   800.7mV    1.973mV    797.7mV
1.852ns   804.3mV    650.9mV    797.9mV
2.036ns   805.2mV    744mV      798.3mV
10ns      806.2mV    755.1mV    799mV
[Rising Waveform]
R_fixture = 50
V_fixture = 1.2
V_fixture_min = 1.14
V_fixture_max = 1.26
| Time   V(typ)   V(min)   V(max)
0s        365.3mV    327.2mV    418.4mV
922ps     365.6mV    327.4mV    421.1mV
1.084ns   365.7mV    327.4mV    1.171V
1.27ns    450.2mV    327.5mV    1.25V
1.365ns   1.048V     327.5mV    1.255V
1.426ns   1.156V     327.5mV    1.257V
1.676ns   1.195V     347.1mV    1.259V
1.804ns   1.198V     1.034V     1.259V
2.009ns   1.199V     1.13V      1.259V
10ns      1.2V       1.14V      1.26V
[Falling Waveform]
R_fixture = 50
V_fixture = 0
V_fixture_min = 0
V_fixture_max = 0
| Time   V(typ)   V(min)   V(max)
0s        806.2mV    755.1mV    799mV
910ps     805.5mV    754.6mV    791.1mV
1.008ns   805.4mV    754.6mV    131.3mV
1.168ns   805.3mV    754.5mV    10.77mV
1.352ns   83.3mV     754.4mV    3.076mV
1.499ns   9.631mV    754.3mV    1.571mV
1.678ns   2.836mV    733.4mV    1.182mV
1.776ns   1.882mV    123.9mV    969.2uV
1.905ns   1.283mV    11.73mV    689.1uV
10ns      1.913uV    3.053uV    2.099uV
[Falling Waveform]
R_fixture = 50
V_fixture = 1.2
V_fixture_min = 1.14
V_fixture_max = 1.26
| Time   V(typ)   V(min)   V(max)
0s        1.2V       1.14V      1.26V
932ps     1.201V     1.14V      1.263V
1.046ns   1.201V     1.14V      539.7mV
1.202ns   1.203V     1.14V      429.7mV
1.365ns   489.1mV    1.14V      422.1mV
1.531ns   374.9mV    1.141V     420.4mV
1.683ns   368.7mV    1.131V     420mV
1.788ns   367.5mV    479.5mV    419.8mV
1.93ns    366.8mV    339.8mV    419.4mV
10ns      365.3mV    327.2mV    418.4mV
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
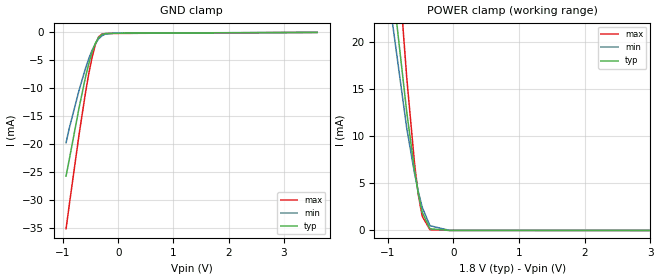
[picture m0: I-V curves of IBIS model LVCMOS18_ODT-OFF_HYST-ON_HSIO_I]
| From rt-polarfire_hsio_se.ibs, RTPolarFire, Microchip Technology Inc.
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|   Model LVCMOS18_ODT-OFF_HYST-ON_HSIO_I
[Model]   LVCMOS18_ODT-OFF_HYST-ON_HSIO_I
Model_type   Input
Vinl =   0.63
Vinh =   1.17
|   typ   min   max
C_comp_pullup   1.335e-12   1.335e-12   1.380e-12
C_comp_pulldown  1.335e-12   1.335e-12   1.380e-12
[Model Spec]
Vinh+   0.990   0.941   1.040
Vinh-   0.990   0.941   1.040
Vinl+   0.810   0.770   0.851
Vinl-   0.810   0.770   0.851
[Temperature Range]  25C   125C   -55C
[Voltage Range]  1.8   1.71   1.89
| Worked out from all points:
|   GND clamp passes 1 mA (typ) near -0.36 V on its own axis
|   POWER clamp passes 1 mA (typ) near -0.43 V on its own axis
[GND Clamp]
| Voltage   I(typ)   I(min)   I(max)
-945mV    -25.64mA   -19.68mA   -35.03mA
-885.9mV  -22.62mA   -17.06mA   -30.7mA
-708.7mV  -13.41mA   -10.29mA   -18.16mA
-590.6mV  -7.869mA   -6.334mA   -10.59mA
-531.6mV  -5.486mA   -4.627mA   -7.255mA
-472.5mV  -3.471mA   -3.166mA   -4.373mA
-413.4mV  -1.919mA   -1.995mA   -2.137mA
-354.4mV  -899.8uA   -1.144mA   -780.3uA
-295.3mV  -390.3uA   -603uA     -297.2uA
-236.2mV  -211.8uA   -316uA     -206.4uA
-59.06mV  -146uA     -127.3uA   -182.2uA
3.6V      0A         0A         0A
[POWER Clamp]
| Voltage   I(typ)   I(min)   I(max)
-1.8V     93.14mA    78.64mA    128.6mA
-1.595V   74.67mA    64.33mA    101.3mA
-1.417V   60.1mA     52.26mA    81.76mA
-1.181V   43.1mA     36.95mA    60.82mA
-1.004V   31.09mA    26.19mA    43.97mA
-708.7mV  12.66mA    10.93mA    16.36mA
-590.6mV  6.471mA    6.139mA    7.229mA
-531.6mV  3.924mA    4.133mA    3.799mA
-472.5mV  1.945mA    2.472mA    1.513mA
-354.4mV  180.5uA    510.3uA    87.9uA
-59.06mV  7.629uA    10.67uA    9.814uA
3.6V      0A         0A         0A
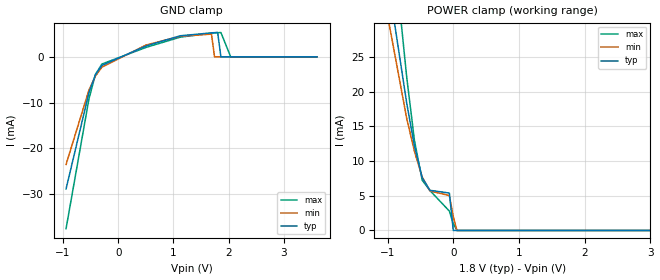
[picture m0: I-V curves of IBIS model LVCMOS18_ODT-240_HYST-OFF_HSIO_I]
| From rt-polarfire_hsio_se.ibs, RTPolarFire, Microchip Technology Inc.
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|   Model LVCMOS18_ODT-240_HYST-OFF_HSIO_I
[Model]   LVCMOS18_ODT-240_HYST-OFF_HSIO_I
Model_type   Input
Vinl =   0.63
Vinh =   1.17
|   typ   min   max
C_comp_pullup   1.335e-12   1.335e-12   1.380e-12
C_comp_pulldown  1.335e-12   1.335e-12   1.380e-12
[Temperature Range]  25C   125C   -55C
[Voltage Range]  1.8   1.71   1.89
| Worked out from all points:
|   GND clamp passes 1 mA (typ) near -0.17 V on its own axis
|   POWER clamp passes 1 mA (typ) near -0.01 V on its own axis
[GND Clamp]
| Voltage   I(typ)   I(min)   I(max)
-945mV    -28.84mA   -23.5mA    -37.53mA
-531.6mV  -7.854mA   -7.291mA   -9.238mA
-413.4mV  -3.908mA   -4.196mA   -3.838mA
-295.3mV  -1.866mA   -2.234mA   -1.56mA
506.2mV   2.389mA    2.594mA    2.08mA
1.125V    4.609mA    4.513mA    4.313mA
1.688V    5.241mA    4.969mA    5.146mA
1.744V    5.292mA    0A         5.204mA
1.8V      5.343mA    0A         5.261mA
1.859V    0A         0A         5.321mA
2.036V    0A         0A         0A
3.6V      0A         0A         0A
[POWER Clamp]
| Voltage   I(typ)   I(min)   I(max)
-1.8V     98.61mA    83.85mA    133.9mA
-1.595V   80.06mA    69.44mA    106.5mA
-1.417V   65.46mA    57.34mA    87mA
-1.004V   36.77mA    31.23mA    49.85mA
-708.7mV  18.41mA    16.19mA    22.17mA
-590.6mV  12.18mA    11.41mA    13mA
-472.5mV  7.61mA     7.706mA    7.244mA
-354.4mV  5.792mA    5.7mA      5.753mA
-59.06mV  5.396mA    5.031mA    2.795mA
0V        0A         2.005mA    960.6uA
56.25mV   0A         0A         0A
3.6V      0A         0A         0A
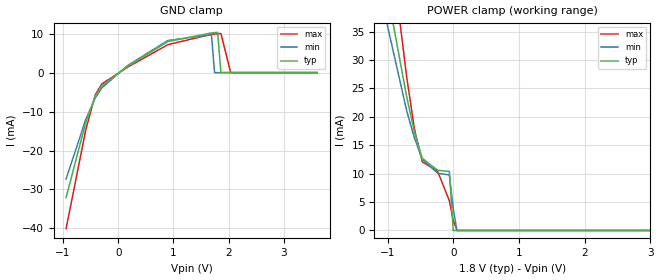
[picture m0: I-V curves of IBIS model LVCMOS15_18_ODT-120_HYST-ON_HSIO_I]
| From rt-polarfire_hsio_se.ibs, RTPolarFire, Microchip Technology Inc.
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|   Model LVCMOS15_18_ODT-120_HYST-ON_HSIO_I
[Model]   LVCMOS15_18_ODT-120_HYST-ON_HSIO_I
Model_type   Input
Vinl =   0.525
Vinh =   0.975
|   typ   min   max
C_comp_pullup   1.335e-12   1.335e-12   1.380e-12
C_comp_pulldown  1.335e-12   1.335e-12   1.380e-12
[Model Spec]
Vinh+   0.780   NA   NA
Vinh-   0.780   NA   NA
Vinl+   0.720   NA   NA
Vinl-   0.720   NA   NA
[Temperature Range]  25C   125C   -55C
[Voltage Range]  1.8   1.71   1.89
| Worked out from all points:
|   GND clamp passes 1 mA (typ) near -0.09 V on its own axis
|   POWER clamp passes 1 mA (typ) near -0.01 V on its own axis
[GND Clamp]
| Voltage   I(typ)   I(min)   I(max)
-945mV    -32.06mA   -27.32mA   -40.06mA
-590.6mV  -12.93mA   -12.08mA   -14.81mA
-413.4mV  -5.934mA   -6.424mA   -5.59mA
-295.3mV  -3.381mA   -3.896mA   -2.877mA
168.8mV   1.625mA    1.805mA    1.385mA
900mV     7.988mA    8.249mA    7.181mA
1.688V    10.18mA    9.697mA    9.818mA
1.744V    10.25mA    0A         9.894mA
1.8V      10.32mA    0A         9.969mA
1.859V    0A         0A         10.05mA
2.036V    0A         0A         0A
3.6V      0A         0A         0A
[POWER Clamp]
| Voltage   I(typ)   I(min)   I(max)
-1.8V     104.1mA    89.07mA    139.1mA
-1.595V   85.45mA    74.58mA    111.6mA
-1.417V   70.79mA    62.41mA    92.07mA
-1.004V   42mA       36.2mA     54.82mA
-708.7mV  23.56mA    21.09mA    27.07mA
-590.6mV  17.31mA    16.29mA    17.88mA
-472.5mV  12.71mA    12.56mA    12.1mA
-236.2mV  10.6mA     10.07mA    10.39mA
-59.06mV  10.39mA    9.781mA    5.219mA
0V        0A         3.902mA    1.794mA
56.25mV   0A         0A         0A
3.6V      0A         0A         0A
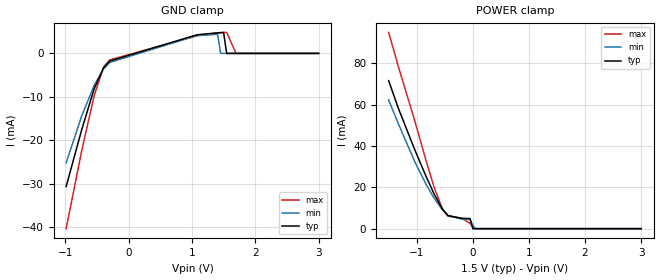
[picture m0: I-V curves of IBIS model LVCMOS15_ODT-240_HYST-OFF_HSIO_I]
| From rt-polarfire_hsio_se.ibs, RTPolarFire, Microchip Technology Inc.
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|   Model LVCMOS15_ODT-240_HYST-OFF_HSIO_I
[Model]   LVCMOS15_ODT-240_HYST-OFF_HSIO_I
Model_type   Input
Vinl =   0.525
Vinh =   0.975
|   typ   min   max
C_comp_pullup   1.335e-12   1.335e-12   1.380e-12
C_comp_pulldown  1.335e-12   1.335e-12   1.380e-12
[Temperature Range]  25C   125C   -55C
[Voltage Range]  1.5   1.425   1.575
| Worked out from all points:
|   GND clamp passes 1 mA (typ) near -0.18 V on its own axis
|   POWER clamp passes 1 mA (typ) near -0.01 V on its own axis
[GND Clamp]
| Voltage   I(typ)   I(min)   I(max)
-984.4mV  -30.62mA   -25.19mA   -40.32mA
-738.3mV  -17.53mA   -14.35mA   -22.34mA
-541.4mV  -8.093mA   -7.342mA   -9.674mA
-393.7mV  -3.301mA   -3.589mA   -3.124mA
-295.3mV  -1.761mA   -2.076mA   -1.483mA
1.078V    4.278mA    4.103mA    4.035mA
1.406V    4.737mA    4.391mA    4.67mA
1.453V    4.782mA    0A         4.726mA
1.5V      4.826mA    0A         4.779mA
1.549V    0A         0A         4.832mA
1.697V    0A         0A         0A
3V        0A         0A         0A
[POWER Clamp]
| Voltage   I(typ)   I(min)   I(max)
-1.5V     71.65mA    62.4mA     95.03mA
-1.329V   58.42mA    50.92mA    78.69mA
-1.034V   38.16mA    32.41mA    52.16mA
-836.7mV  25.53mA    21.61mA    33.3mA
-689.1mV  16.76mA    14.73mA    19.99mA
-541.4mV  9.477mA    9.092mA    9.516mA
-443mV    6.353mA    6.411mA    6.011mA
-196.9mV  5.004mA    4.579mA    5.062mA
-49.22mV  4.871mA    4.442mA    2.533mA
0V        0A         1.77mA     870.6uA
46.88mV   0A         0A         0A
3V        0A         0A         0A
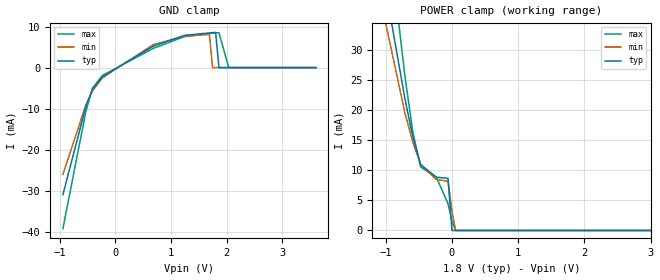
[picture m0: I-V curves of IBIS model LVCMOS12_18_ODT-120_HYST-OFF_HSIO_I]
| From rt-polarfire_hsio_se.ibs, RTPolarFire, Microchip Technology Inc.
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|   Model LVCMOS12_18_ODT-120_HYST-OFF_HSIO_I
[Model]   LVCMOS12_18_ODT-120_HYST-OFF_HSIO_I
Model_type   Input
Vinl =   0.42
Vinh =   0.78
|   typ   min   max
C_comp_pullup   1.335e-12   1.335e-12   1.380e-12
C_comp_pulldown  1.335e-12   1.335e-12   1.380e-12
[Temperature Range]  25C   125C   -55C
[Voltage Range]  1.8   1.71   1.89
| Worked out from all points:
|   GND clamp passes 1 mA (typ) near -0.10 V on its own axis
|   POWER clamp passes 1 mA (typ) near -0.01 V on its own axis
[GND Clamp]
| Voltage   I(typ)   I(min)   I(max)
-945mV    -30.96mA   -26.02mA   -39.25mA
-531.6mV  -9.43mA    -9.064mA   -10.62mA
-413.4mV  -5.238mA   -5.666mA   -5.028mA
-236.2mV  -2.192mA   -2.514mA   -1.927mA
675mV     5.2mA      5.567mA    4.656mA
1.238V    7.862mA    7.635mA    7.556mA
1.688V    8.456mA    8.092mA    8.311mA
1.744V    8.519mA    0A         8.382mA
1.8V      8.58mA     0A         8.451mA
1.859V    0A         0A         8.523mA
2.036V    0A         0A         0A
3.6V      0A         0A         0A
[POWER Clamp]
| Voltage   I(typ)   I(min)   I(max)
-1.8V     102.2mA    87.29mA    137.4mA
-1.595V   83.57mA    72.83mA    110mA
-1.417V   68.93mA    60.69mA    90.44mA
-1.004V   40.18mA    34.51mA    53.22mA
-708.7mV  21.76mA    19.43mA    25.49mA
-590.6mV  15.52mA    14.63mA    16.31mA
-472.5mV  10.93mA    10.91mA    10.53mA
-236.2mV  8.84mA     8.44mA     8.844mA
-59.06mV  8.645mA    8.169mA    4.437mA
0V        0A         3.258mA    1.525mA
56.25mV   0A         0A         0A
3.6V      0A         0A         0A
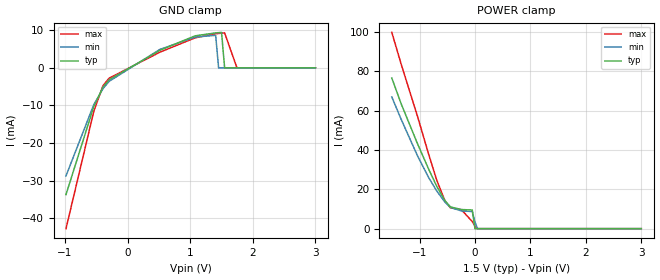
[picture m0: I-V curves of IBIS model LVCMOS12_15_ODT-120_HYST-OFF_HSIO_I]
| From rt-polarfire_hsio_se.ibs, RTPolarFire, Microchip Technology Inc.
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|   Model LVCMOS12_15_ODT-120_HYST-OFF_HSIO_I
[Model]   LVCMOS12_15_ODT-120_HYST-OFF_HSIO_I
Model_type   Input
Vinl =   0.42
Vinh =   0.78
|   typ   min   max
C_comp_pullup   1.335e-12   1.335e-12   1.380e-12
C_comp_pulldown  1.335e-12   1.335e-12   1.380e-12
[Temperature Range]  25C   125C   -55C
[Voltage Range]  1.5   1.425   1.575
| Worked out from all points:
|   GND clamp passes 1 mA (typ) near -0.09 V on its own axis
|   POWER clamp passes 1 mA (typ) near -0.01 V on its own axis
[GND Clamp]
| Voltage   I(typ)   I(min)   I(max)
-984.4mV  -33.72mA   -28.75mA   -42.79mA
-541.4mV  -10.38mA   -9.832mA   -11.64mA
-393.7mV  -5.14mA    -5.549mA   -4.751mA
-295.3mV  -3.19mA    -3.598mA   -2.749mA
515.6mV   4.659mA    4.89mA     4.156mA
1.078V    8.508mA    8.179mA    7.977mA
1.406V    9.291mA    8.642mA    9.057mA
1.453V    9.357mA    0A         9.138mA
1.5V      9.42mA     0A         9.213mA
1.549V    0A         0A         9.288mA
1.746V    0A         0A         0A
3V        0A         0A         0A
[POWER Clamp]
| Voltage   I(typ)   I(min)   I(max)
-1.5V     76.62mA    66.99mA    99.85mA
-1.329V   63.35mA    55.48mA    83.48mA
-1.034V   43.03mA    36.9mA     56.92mA
-836.7mV  30.36mA    26.07mA    37.98mA
-689.1mV  21.55mA    19.16mA    24.64mA
-541.4mV  14.23mA    13.49mA    14.13mA
-443mV    11.08mA    10.79mA    10.61mA
-246.1mV  9.728mA    9.032mA    9.658mA
-49.22mV  9.484mA    8.714mA    3.642mA
0V        0A         3.477mA    1.252mA
46.88mV   0A         0A         0A
3V        0A         0A         0A
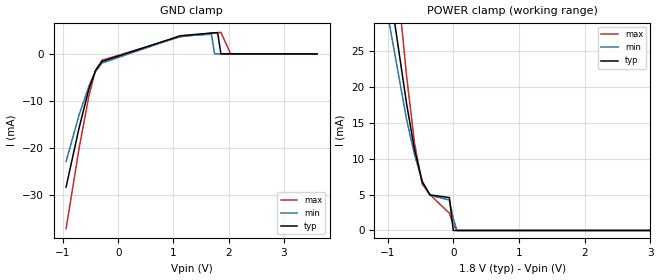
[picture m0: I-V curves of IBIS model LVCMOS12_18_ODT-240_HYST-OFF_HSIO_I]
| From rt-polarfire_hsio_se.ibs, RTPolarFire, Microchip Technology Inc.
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|   Model LVCMOS12_18_ODT-240_HYST-OFF_HSIO_I
[Model]   LVCMOS12_18_ODT-240_HYST-OFF_HSIO_I
Model_type   Input
Vinl =   0.42
Vinh =   0.78
|   typ   min   max
C_comp_pullup   1.335e-12   1.335e-12   1.380e-12
C_comp_pulldown  1.335e-12   1.335e-12   1.380e-12
[Temperature Range]  25C   125C   -55C
[Voltage Range]  1.8   1.71   1.89
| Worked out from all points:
|   GND clamp passes 1 mA (typ) near -0.20 V on its own axis
|   POWER clamp passes 1 mA (typ) near -0.01 V on its own axis
[GND Clamp]
| Voltage   I(typ)   I(min)   I(max)
-945mV    -28.29mA   -22.85mA   -37.13mA
-708.7mV  -15.69mA   -12.95mA   -20.05mA
-531.6mV  -7.441mA   -6.834mA   -8.914mA
-413.4mV  -3.56mA    -3.817mA   -3.558mA
-295.3mV  -1.606mA   -1.951mA   -1.35mA
1.125V    3.844mA    3.756mA    3.64mA
1.688V    4.423mA    4.173mA    4.396mA
1.744V    4.471mA    0A         4.451mA
1.8V      4.518mA    0A         4.506mA
1.859V    0A         0A         4.563mA
2.036V    0A         0A         0A
3.6V      0A         0A         0A
[POWER Clamp]
| Voltage   I(typ)   I(min)   I(max)
-1.8V     97.7mA     82.97mA    133.1mA
-1.595V   79.17mA    68.58mA    105.7mA
-1.417V   64.58mA    56.49mA    86.19mA
-1.004V   35.91mA    30.39mA    49.05mA
-708.7mV  17.55mA    15.37mA    21.38mA
-590.6mV  11.33mA    10.59mA    12.22mA
-472.5mV  6.764mA    6.89mA     6.464mA
-354.4mV  4.951mA    4.888mA    4.977mA
-59.06mV  4.569mA    4.231mA    2.405mA
0V        0A         1.685mA    826.8uA
56.25mV   0A         0A         0A
3.6V      0A         0A         0A
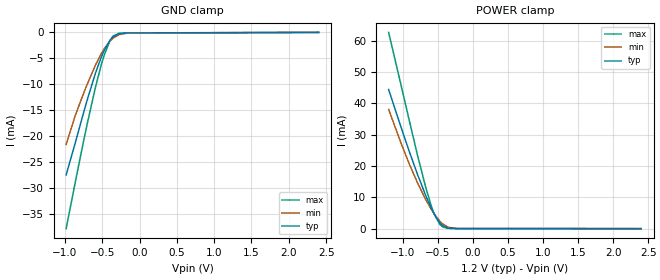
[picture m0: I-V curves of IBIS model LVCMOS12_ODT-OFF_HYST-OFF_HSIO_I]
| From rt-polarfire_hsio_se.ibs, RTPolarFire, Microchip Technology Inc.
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|   Model LVCMOS12_ODT-OFF_HYST-OFF_HSIO_I
[Model]   LVCMOS12_ODT-OFF_HYST-OFF_HSIO_I
Model_type   Input
Vinl =   0.42
Vinh =   0.78
|   typ   min   max
C_comp_pullup   1.335e-12   1.335e-12   1.380e-12
C_comp_pulldown  1.335e-12   1.335e-12   1.380e-12
[Temperature Range]  25C   125C   -55C
[Voltage Range]  1.2   1.14   1.26
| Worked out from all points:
|   GND clamp passes 1 mA (typ) near -0.36 V on its own axis
|   POWER clamp passes 1 mA (typ) near -0.43 V on its own axis
[GND Clamp]
| Voltage   I(typ)   I(min)   I(max)
-984.4mV  -27.48mA   -21.61mA   -37.84mA
-866.2mV  -21.51mA   -16.2mA    -29.18mA
-787.5mV  -17.37mA   -13.13mA   -23.53mA
-708.7mV  -13.34mA   -10.23mA   -18.07mA
-590.6mV  -7.803mA   -6.275mA   -10.51mA
-511.9mV  -4.705mA   -4.054mA   -6.156mA
-472.5mV  -3.409mA   -3.11mA    -4.296mA
-393.7mV  -1.457mA   -1.622mA   -1.503mA
-354.4mV  -839.6uA   -1.091mA   -706.5uA
-275.6mV  -246.1uA   -432.1uA   -174.2uA
-157.5mV  -98.85uA   -119.2uA   -116.5uA
2.4V      0A         0A         0A
[POWER Clamp]
| Voltage   I(typ)   I(min)   I(max)
-1.2V     44.39mA    38.04mA    62.6mA
-1.024V   32.39mA    27.3mA     45.84mA
-905.6mV  24.61mA    20.64mA    34.47mA
-787.5mV  17.24mA    14.56mA    23.33mA
-669.4mV  10.45mA    9.189mA    13.02mA
-590.6mV  6.448mA    6.097mA    7.153mA
-551.3mV  4.699mA    4.725mA    4.739mA
-472.5mV  1.932mA    2.425mA    1.415mA
-433.1mV  1.018mA    1.554mA    584.3uA
-354.4mV  175.4uA    471.4uA    73.11uA
-236.2mV  26.92uA    64.45uA    28.65uA
2.4V      0A         0A         0A
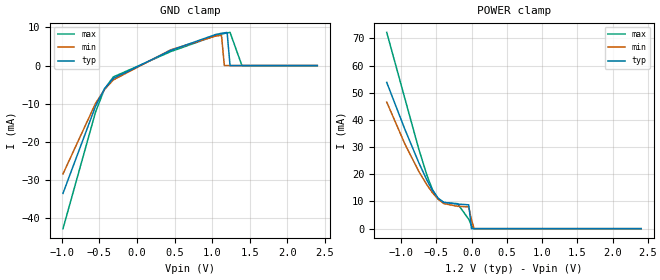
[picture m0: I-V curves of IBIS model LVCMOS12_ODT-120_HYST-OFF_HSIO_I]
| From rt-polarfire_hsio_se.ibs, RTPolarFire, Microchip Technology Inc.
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|   Model LVCMOS12_ODT-120_HYST-OFF_HSIO_I
[Model]   LVCMOS12_ODT-120_HYST-OFF_HSIO_I
Model_type   Input
Vinl =   0.42
Vinh =   0.78
|   typ   min   max
C_comp_pullup   1.335e-12   1.335e-12   1.380e-12
C_comp_pulldown  1.335e-12   1.335e-12   1.380e-12
[Temperature Range]  25C   125C   -55C
[Voltage Range]  1.2   1.14   1.26
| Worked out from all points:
|   GND clamp passes 1 mA (typ) near -0.10 V on its own axis
|   POWER clamp passes 1 mA (typ) near -0.00 V on its own axis
[GND Clamp]
| Voltage   I(typ)   I(min)   I(max)
-984.4mV  -33.5mA    -28.39mA   -42.75mA
-551.3mV  -10.65mA   -9.913mA   -12.19mA
-433.1mV  -6.137mA   -6.32mA    -6.168mA
-315mV    -3.378mA   -3.765mA   -2.978mA
450mV     3.989mA    4.133mA    3.665mA
1.05V     8.16mA     7.763mA    7.862mA
1.125V    8.456mA    7.916mA    8.245mA
1.163V    8.575mA    0A         8.412mA
1.2V      8.676mA    0A         8.561mA
1.239V    0A         0A         8.697mA
1.397V    0A         0A         0A
2.4V      0A         0A         0A
[POWER Clamp]
| Voltage   I(typ)   I(min)   I(max)
-1.2V     53.78mA    46.54mA    72.18mA
-945mV    36.65mA    31.24mA    48.02mA
-748.1mV  24.37mA    21.14mA    29.43mA
-630mV    17.77mA    16.06mA    19.54mA
-551.3mV  14.05mA    13.16mA    14.28mA
-472.5mV  11.22mA    10.81mA    10.9mA
-393.7mV  9.684mA    9.239mA    9.619mA
-196.9mV  9.037mA    8.222mA    9.182mA
-39.38mV  8.766mA    8.002mA    3.458mA
0V        0A         3.191mA    1.189mA
37.5mV    0A         0A         0A
2.4V      0A         0A         0A
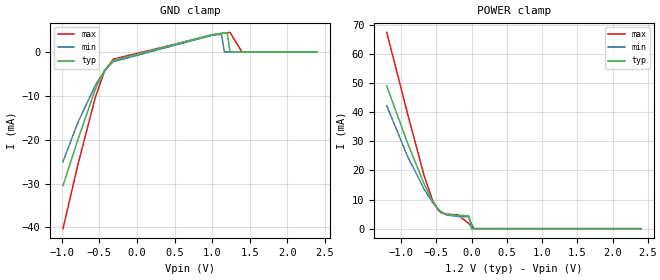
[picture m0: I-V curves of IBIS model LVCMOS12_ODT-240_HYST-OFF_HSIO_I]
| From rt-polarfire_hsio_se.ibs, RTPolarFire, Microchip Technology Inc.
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|   Model LVCMOS12_ODT-240_HYST-OFF_HSIO_I
[Model]   LVCMOS12_ODT-240_HYST-OFF_HSIO_I
Model_type   Input
Vinl =   0.42
Vinh =   0.78
|   typ   min   max
C_comp_pullup   1.335e-12   1.335e-12   1.380e-12
C_comp_pulldown  1.335e-12   1.335e-12   1.380e-12
[Temperature Range]  25C   125C   -55C
[Voltage Range]  1.2   1.14   1.26
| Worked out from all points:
|   GND clamp passes 1 mA (typ) near -0.19 V on its own axis
|   POWER clamp passes 1 mA (typ) near -0.01 V on its own axis
[GND Clamp]
| Voltage   I(typ)   I(min)   I(max)
-984.4mV  -30.49mA   -25mA      -40.28mA
-787.5mV  -20.05mA   -16.13mA   -25.79mA
-551.3mV  -8.406mA   -7.509mA   -10.2mA
-433.1mV  -4.218mA   -4.303mA   -4.431mA
-315mV    -1.904mA   -2.226mA   -1.631mA
1.012V    4.01mA     3.85mA     3.872mA
1.125V    4.264mA    3.991mA    4.199mA
1.163V    4.329mA    0A         4.293mA
1.2V      4.386mA    0A         4.378mA
1.239V    0A         0A         4.458mA
1.397V    0A         0A         0A
2.4V      0A         0A         0A
[POWER Clamp]
| Voltage   I(typ)   I(min)   I(max)
-1.2V     49.08mA    42.28mA    67.49mA
-905.6mV  29.48mA    24.86mA    39.59mA
-669.4mV  15.29mA    13.51mA    18.07mA
-551.3mV  9.497mA    9.026mA    9.741mA
-472.5mV  6.698mA    6.701mA    6.385mA
-433.1mV  5.767mA    5.815mA    5.534mA
-354.4mV  4.883mA    4.701mA    4.969mA
-196.9mV  4.61mA     4.194mA    4.769mA
-39.38mV  4.439mA    4.043mA    1.789mA
0V        0A         1.611mA    615.1uA
37.5mV    0A         0A         0A
2.4V      0A         0A         0A
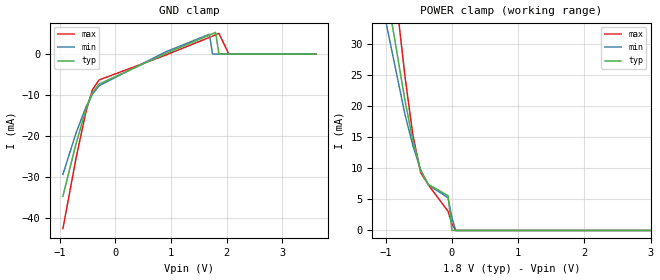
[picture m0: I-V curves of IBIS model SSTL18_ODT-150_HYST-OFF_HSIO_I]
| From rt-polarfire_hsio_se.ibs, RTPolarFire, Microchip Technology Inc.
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|   Model SSTL18_ODT-150_HYST-OFF_HSIO_I
[Model]   SSTL18_ODT-150_HYST-OFF_HSIO_I
Model_type   Input
Vinl =   0.775
Vinh =   1.025
|   typ   min   max
C_comp_pullup   1.335e-12   1.335e-12   1.380e-12
C_comp_pulldown  1.335e-12   1.335e-12   1.380e-12
[Temperature Range]  25C   125C   -55C
[Voltage Range]  1.8   1.71   1.89
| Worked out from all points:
|   POWER clamp passes 1 mA (typ) near -0.01 V on its own axis
[GND Clamp]
| Voltage   I(typ)   I(min)   I(max)
-945mV    -34.59mA   -29.29mA   -42.51mA
-708.7mV  -21.82mA   -19.2mA    -25.31mA
-531.6mV  -13.42mA   -12.9mA    -14.08mA
-413.4mV  -9.422mA   -9.744mA   -8.645mA
-295.3mV  -7.318mA   -7.714mA   -6.321mA
900mV     91.53uA    521.4uA    -266.3uA
1.688V    4.635mA    4.814mA    4.05mA
1.744V    4.95mA     0A         4.369mA
1.8V      5.266mA    0A         4.692mA
1.859V    0A         0A         5.033mA
2.036V    0A         0A         0A
3.6V      0A         0A         0A
[POWER Clamp]
| Voltage   I(typ)   I(min)   I(max)
-1.8V     101.4mA    86.05mA    136.9mA
-1.595V   83.08mA    71.85mA    109.7mA
-1.417V   68.53mA    59.89mA    90.24mA
-1.004V   39.52mA    33.89mA    52.61mA
-708.7mV  20.9mA     18.62mA    24.72mA
-590.6mV  14.5mA     13.67mA    15.38mA
-472.5mV  9.653mA    9.709mA    9.309mA
-354.4mV  7.385mA    7.302mA    7.315mA
-59.06mV  5.599mA    5.264mA    3.082mA
0V        0A         2.05mA     1.059mA
56.25mV   0A         0A         0A
3.6V      0A         0A         0A
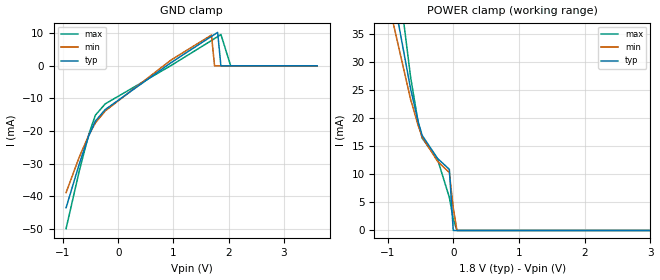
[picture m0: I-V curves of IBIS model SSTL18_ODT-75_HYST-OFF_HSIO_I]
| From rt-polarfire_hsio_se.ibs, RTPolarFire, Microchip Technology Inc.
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|   Model SSTL18_ODT-75_HYST-OFF_HSIO_I
[Model]   SSTL18_ODT-75_HYST-OFF_HSIO_I
Model_type   Input
Vinl =   0.775
Vinh =   1.025
|   typ   min   max
C_comp_pullup   1.335e-12   1.335e-12   1.380e-12
C_comp_pulldown  1.335e-12   1.335e-12   1.380e-12
[Temperature Range]  25C   125C   -55C
[Voltage Range]  1.8   1.71   1.89
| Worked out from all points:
|   POWER clamp passes 1 mA (typ) near -0.01 V on its own axis
[GND Clamp]
| Voltage   I(typ)   I(min)   I(max)
-945mV    -43.56mA   -38.92mA   -49.97mA
-708.7mV  -30.26mA   -28.12mA   -32.45mA
-531.6mV  -21.38mA   -21.19mA   -20.9mA
-413.4mV  -16.94mA   -17.51mA   -15.14mA
-236.2mV  -13.42mA   -13.84mA   -11.68mA
956.3mV   969.6uA    1.78mA     91.73uA
1.688V    9.044mA    9.436mA    7.756mA
1.744V    9.643mA    0A         8.359mA
1.8V      10.25mA    0A         8.969mA
1.859V    0A         0A         9.616mA
2.036V    0A         0A         0A
3.6V      0A         0A         0A
[POWER Clamp]
| Voltage   I(typ)   I(min)   I(max)
-1.8V     109.8mA    93.48mA    145.1mA
-1.595V   91.49mA    79.4mA     118.1mA
-1.477V   81.62mA    71.45mA    104.6mA
-1.004V   47.65mA    41.55mA    60.58mA
-649.7mV  25.25mA    23.37mA    27.36mA
-531.6mV  19.24mA    18.62mA    19.11mA
-472.5mV  16.91mA    16.63mA    16.42mA
-236.2mV  12.78mA    12.26mA    12.56mA
-59.06mV  10.88mA    10.3mA     5.876mA
0V        0A         4.013mA    2.02mA
56.25mV   0A         0A         0A
3.6V      0A         0A         0A
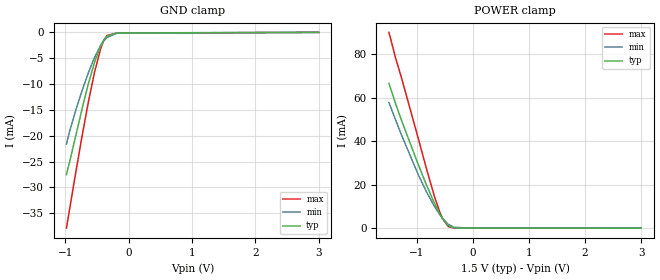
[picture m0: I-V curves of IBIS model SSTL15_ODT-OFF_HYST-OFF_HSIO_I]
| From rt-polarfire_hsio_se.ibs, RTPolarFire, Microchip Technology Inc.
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|   Model SSTL15_ODT-OFF_HYST-OFF_HSIO_I
[Model]   SSTL15_ODT-OFF_HYST-OFF_HSIO_I
Model_type   Input
Vinl =   0.65
Vinh =   0.85
|   typ   min   max
C_comp_pullup   1.335e-12   1.335e-12   1.380e-12
C_comp_pulldown  1.335e-12   1.335e-12   1.380e-12
[Temperature Range]  25C   125C   -55C
[Voltage Range]  1.5   1.425   1.575
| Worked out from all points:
|   GND clamp passes 1 mA (typ) near -0.36 V on its own axis
|   POWER clamp passes 1 mA (typ) near -0.43 V on its own axis
[GND Clamp]
| Voltage   I(typ)   I(min)   I(max)
-984.4mV  -27.52mA   -21.64mA   -37.88mA
-935.2mV  -25.11mA   -19.19mA   -34.26mA
-836.7mV  -19.99mA   -15.05mA   -27.09mA
-738.3mV  -14.86mA   -11.32mA   -20.13mA
-639.8mV  -10.04mA   -7.878mA   -13.59mA
-541.4mV  -5.828mA   -4.867mA   -7.743mA
-443mV    -2.601mA   -2.515mA   -3.122mA
-393.7mV  -1.488mA   -1.649mA   -1.54mA
-344.5mV  -752.5uA   -1.007mA   -611.2uA
-196.9mV  -143.7uA   -195uA     -157.5uA
-49.22mV  -115.8uA   -100.4uA   -145.1uA
3V        0A         0A         0A
[POWER Clamp]
| Voltage   I(typ)   I(min)   I(max)
-1.5V     66.68mA    57.83mA    90.15mA
-1.378V   57.1mA     49.63mA    78.06mA
-1.28V    49.95mA    43.17mA    69.59mA
-984.4mV  29.77mA    25.04mA    42.07mA
-836.7mV  20.27mA    17.03mA    27.95mA
-689.1mV  11.54mA    10.05mA    14.67mA
-590.6mV  6.461mA    6.118mA    7.191mA
-541.4mV  4.305mA    4.424mA    4.25mA
-443mV    1.22mA     1.775mA    783.3uA
-344.5mV  141uA      412.1uA    66.01uA
-49.22mV  6.174uA    9.105uA    8.248uA
3V        0A         0A         0A
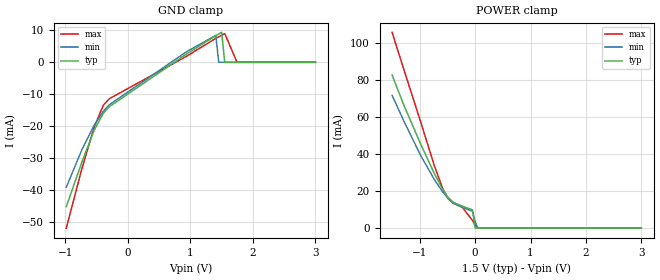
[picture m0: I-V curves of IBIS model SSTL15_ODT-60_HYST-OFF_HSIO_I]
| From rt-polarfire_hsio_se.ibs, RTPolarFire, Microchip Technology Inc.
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|   Model SSTL15_ODT-60_HYST-OFF_HSIO_I
[Model]   SSTL15_ODT-60_HYST-OFF_HSIO_I
Model_type   Input
Vinl =   0.65
Vinh =   0.85
|   typ   min   max
C_comp_pullup   1.335e-12   1.335e-12   1.380e-12
C_comp_pulldown  1.335e-12   1.335e-12   1.380e-12
[Temperature Range]  25C   125C   -55C
[Voltage Range]  1.5   1.425   1.575
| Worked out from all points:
|   POWER clamp passes 1 mA (typ) near -0.00 V on its own axis
[GND Clamp]
| Voltage   I(typ)   I(min)   I(max)
-984.4mV  -45.24mA   -39.16mA   -51.97mA
-738.3mV  -31.48mA   -27.56mA   -33.57mA
-541.4mV  -21.42mA   -19.81mA   -20.49mA
-393.7mV  -15.99mA   -15.35mA   -13.49mA
-295.3mV  -13.9mA    -13.27mA   -11.4mA
937.5mV   2.604mA    3.313mA    1.877mA
1.406V    8.355mA    8.437mA    7.503mA
1.453V    8.866mA    0A         7.99mA
1.5V      9.377mA    0A         8.476mA
1.549V    0A         0A         8.985mA
1.746V    0A         0A         0A
3V        0A         0A         0A
[POWER Clamp]
| Voltage   I(typ)   I(min)   I(max)
-1.5V     82.79mA    71.85mA    105.9mA
-1.28V    65.94mA    57.41mA    85.1mA
-984.4mV  45.49mA    39.33mA    57.47mA
-738.3mV  29.62mA    26.31mA    33.88mA
-590.6mV  21.23mA    19.78mA    21.7mA
-492.2mV  16.78mA    16.16mA    16.07mA
-393.7mV  13.96mA    13.47mA    13.41mA
-246.1mV  12.04mA    11.32mA    11.77mA
-49.22mV  9.913mA    9.153mA    4.194mA
0V        0A         3.572mA    1.442mA
46.88mV   0A         0A         0A
3V        0A         0A         0A
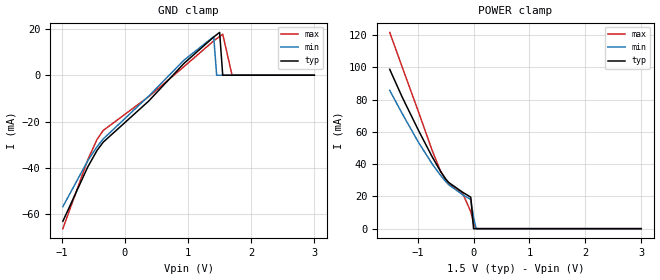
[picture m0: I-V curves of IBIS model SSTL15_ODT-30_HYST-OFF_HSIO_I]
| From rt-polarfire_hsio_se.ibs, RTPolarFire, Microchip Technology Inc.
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|   Model SSTL15_ODT-30_HYST-OFF_HSIO_I
[Model]   SSTL15_ODT-30_HYST-OFF_HSIO_I
Model_type   Input
Vinl =   0.65
Vinh =   0.85
|   typ   min   max
C_comp_pullup   1.335e-12   1.335e-12   1.380e-12
C_comp_pulldown  1.335e-12   1.335e-12   1.380e-12
[Temperature Range]  25C   125C   -55C
[Voltage Range]  1.5   1.425   1.575
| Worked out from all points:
|   POWER clamp passes 1 mA (typ) near -0.00 V on its own axis
[GND Clamp]
| Voltage   I(typ)   I(min)   I(max)
-984.4mV  -62.93mA   -56.63mA   -66.1mA
-590.6mV  -39.57mA   -36.88mA   -36.5mA
-443mV    -32.4mA    -30.81mA   -27.68mA
-344.5mV  -28.83mA   -27.44mA   -23.78mA
375mV     -11.15mA   -9.018mA   -9.246mA
937.5mV   5.166mA    6.55mA     3.76mA
1.406V    16.46mA    16.62mA    14.8mA
1.453V    17.45mA    0A         15.75mA
1.5V      18.45mA    0A         16.69mA
1.549V    0A         0A         17.68mA
1.697V    0A         0A         0A
3V        0A         0A         0A
[POWER Clamp]
| Voltage   I(typ)   I(min)   I(max)
-1.5V     98.79mA    85.76mA    121.7mA
-1.28V    81.79mA    71.53mA    100.5mA
-984.4mV  60.86mA    53.45mA    72.34mA
-738.3mV  44.43mA    40.06mA    48.3mA
-590.6mV  35.53mA    33.07mA    35.67mA
-492.2mV  30.57mA    28.99mA    29.52mA
-443mV    28.59mA    27.21mA    27.5mA
-196.9mV  22.61mA    21.08mA    22.11mA
-49.22mV  19.5mA     18.02mA    10.48mA
0V        0A         7.036mA    3.602mA
46.88mV   0A         0A         0A
3V        0A         0A         0A
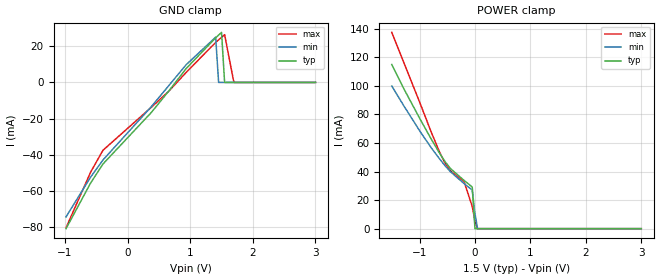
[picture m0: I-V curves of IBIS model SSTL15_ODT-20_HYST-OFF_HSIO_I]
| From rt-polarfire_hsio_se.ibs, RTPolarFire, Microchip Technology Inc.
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|   Model SSTL15_ODT-20_HYST-OFF_HSIO_I
[Model]   SSTL15_ODT-20_HYST-OFF_HSIO_I
Model_type   Input
Vinl =   0.65
Vinh =   0.85
|   typ   min   max
C_comp_pullup   1.335e-12   1.335e-12   1.380e-12
C_comp_pulldown  1.335e-12   1.335e-12   1.380e-12
[Temperature Range]  25C   125C   -55C
[Voltage Range]  1.5   1.425   1.575
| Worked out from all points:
|   POWER clamp passes 1 mA (typ) near -0.00 V on its own axis
[GND Clamp]
| Voltage   I(typ)   I(min)   I(max)
-984.4mV  -80.65mA   -74.18mA   -80.18mA
-590.6mV  -55.45mA   -52.19mA   -49.45mA
-393.7mV  -44.97mA   -42.77mA   -37.41mA
375mV     -16.7mA    -13.5mA    -13.83mA
656.2mV   -4.781mA   -1.799mA   -4.876mA
937.5mV   7.75mA     9.869mA    5.617mA
1.406V    24.62mA    24.94mA    22.07mA
1.453V    26.11mA    0A         23.48mA
1.5V      27.59mA    0A         24.88mA
1.549V    0A         0A         26.35mA
1.697V    0A         0A         0A
3V        0A         0A         0A
[POWER Clamp]
| Voltage   I(typ)   I(min)   I(max)
-1.5V     114.9mA    99.81mA    137.4mA
-1.28V    97.73mA    85.78mA    115.9mA
-984.4mV  76.29mA    67.71mA    87.19mA
-787.5mV  62.61mA    56.56mA    67.47mA
-639.8mV  52.91mA    48.9mA     53.69mA
-541.4mV  47.05mA    44.16mA    45.99mA
-443mV    42.12mA    39.88mA    40.58mA
-196.9mV  33.78mA    31.57mA    32.92mA
-49.22mV  29.15mA    27.03mA    15.61mA
0V        0A         10.55mA    5.365mA
46.88mV   0A         0A         0A
3V        0A         0A         0A
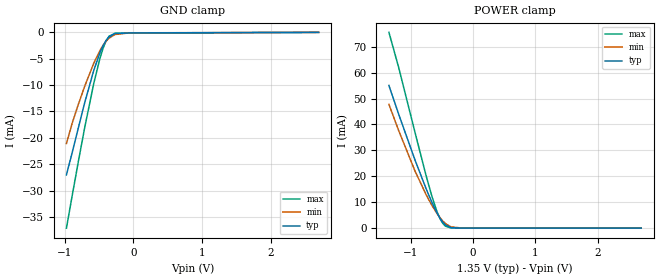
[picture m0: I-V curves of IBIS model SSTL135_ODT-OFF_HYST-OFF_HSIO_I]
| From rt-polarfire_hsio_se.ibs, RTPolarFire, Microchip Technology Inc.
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|   Model SSTL135_ODT-OFF_HYST-OFF_HSIO_I
[Model]   SSTL135_ODT-OFF_HYST-OFF_HSIO_I
Model_type   Input
Vinl =   0.585
Vinh =   0.765
|   typ   min   max
C_comp_pullup   1.335e-12   1.335e-12   1.380e-12
C_comp_pulldown  1.335e-12   1.335e-12   1.380e-12
[Temperature Range]  25C   125C   -55C
[Voltage Range]  1.35   1.2825   1.4175
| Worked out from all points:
|   GND clamp passes 1 mA (typ) near -0.36 V on its own axis
|   POWER clamp passes 1 mA (typ) near -0.43 V on its own axis
[GND Clamp]
| Voltage   I(typ)   I(min)   I(max)
-974.5mV  -27.03mA   -21.1mA    -37.14mA
-885.9mV  -22.56mA   -17.02mA   -30.63mA
-797.3mV  -17.91mA   -13.52mA   -24.25mA
-708.7mV  -13.35mA   -10.24mA   -18.09mA
-575.9mV  -7.195mA   -5.844mA   -9.661mA
-487.3mV  -3.888mA   -3.464mA   -4.983mA
-443mV    -2.585mA   -2.501mA   -3.103mA
-398.7mV  -1.567mA   -1.712mA   -1.651mA
-354.4mV  -854.7uA   -1.105mA   -724.8uA
-265.8mV  -229.7uA   -394.8uA   -177uA
-44.3mV   -100.9uA   -87.18uA   -126.7uA
2.7V      0A         0A         0A
[POWER Clamp]
| Voltage   I(typ)   I(min)   I(max)
-1.35V    55.05mA    47.75mA    75.54mA
-1.196V   44.11mA    37.8mA     62.22mA
-930.2mV  26.21mA    21.98mA    36.85mA
-753mV    15.2mA     12.92mA    20.22mA
-664.5mV  10.19mA    8.994mA    12.64mA
-575.9mV  5.775mA    5.578mA    6.218mA
-531.6mV  3.911mA    4.101mA    3.726mA
-487.3mV  2.366mA    2.815mA    1.89mA
-443mV    1.217mA    1.763mA    762.9uA
-354.4mV  176.9uA    480.4uA    76.43uA
-177.2mV  19.22uA    37.42uA    22.01uA
2.7V      0A         0A         0A
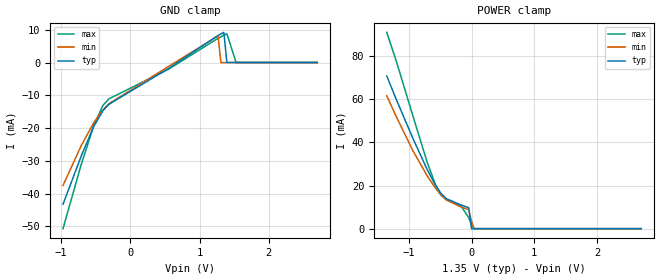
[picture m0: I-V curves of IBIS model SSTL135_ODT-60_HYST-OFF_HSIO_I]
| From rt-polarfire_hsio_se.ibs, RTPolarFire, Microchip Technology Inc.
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|   Model SSTL135_ODT-60_HYST-OFF_HSIO_I
[Model]   SSTL135_ODT-60_HYST-OFF_HSIO_I
Model_type   Input
Vinl =   0.585
Vinh =   0.765
|   typ   min   max
C_comp_pullup   1.335e-12   1.335e-12   1.380e-12
C_comp_pulldown  1.335e-12   1.335e-12   1.380e-12
[Temperature Range]  25C   125C   -55C
[Voltage Range]  1.35   1.2825   1.4175
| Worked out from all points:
|   POWER clamp passes 1 mA (typ) near -0.00 V on its own axis
[GND Clamp]
| Voltage   I(typ)   I(min)   I(max)
-974.5mV  -43.26mA   -37.52mA   -50.7mA
-708.7mV  -28.42mA   -25.27mA   -30.95mA
-531.6mV  -19.56mA   -18.45mA   -19.4mA
-398.7mV  -14.72mA   -14.48mA   -13.12mA
-310.1mV  -12.74mA   -12.57mA   -11.07mA
548.4mV   -1.842mA   -1.223mA   -2.062mA
1.266V    8.254mA    8.116mA    7.381mA
1.308V    8.727mA    0A         7.856mA
1.35V     9.195mA    0A         8.32mA
1.394V    0A         0A         8.798mA
1.527V    0A         0A         0A
2.7V      0A         0A         0A
[POWER Clamp]
| Voltage   I(typ)   I(min)   I(max)
-1.35V    70.87mA    61.65mA    91.03mA
-1.196V   59.77mA    51.82mA    77.51mA
-930.2mV  41.66mA    35.99mA    52mA
-708.7mV  27.62mA    24.64mA    31.05mA
-575.9mV  20.28mA    18.91mA    20.49mA
-487.3mV  16.4mA     15.72mA    15.67mA
-398.7mV  13.87mA    13.29mA    13.3mA
-177.2mV  11.12mA    10.2mA     10.89mA
-44.3mV   9.682mA    8.774mA    5.179mA
0V        0A         3.428mA    1.78mA
42.19mV   0A         0A         0A
2.7V      0A         0A         0A
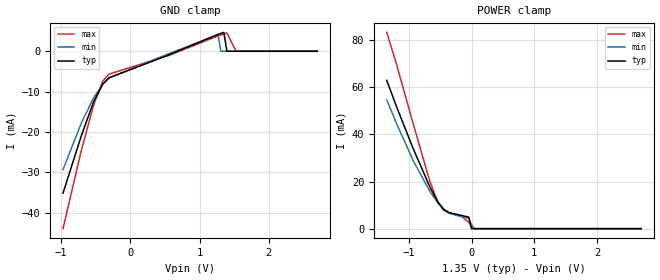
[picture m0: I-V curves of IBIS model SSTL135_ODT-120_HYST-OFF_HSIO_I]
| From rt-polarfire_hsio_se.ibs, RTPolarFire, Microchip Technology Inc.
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|   Model SSTL135_ODT-120_HYST-OFF_HSIO_I
[Model]   SSTL135_ODT-120_HYST-OFF_HSIO_I
Model_type   Input
Vinl =   0.585
Vinh =   0.765
|   typ   min   max
C_comp_pullup   1.335e-12   1.335e-12   1.380e-12
C_comp_pulldown  1.335e-12   1.335e-12   1.380e-12
[Temperature Range]  25C   125C   -55C
[Voltage Range]  1.35   1.2825   1.4175
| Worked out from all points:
|   POWER clamp passes 1 mA (typ) near -0.01 V on its own axis
[GND Clamp]
| Voltage   I(typ)   I(min)   I(max)
-974.5mV  -35.14mA   -29.3mA    -43.92mA
-708.7mV  -20.87mA   -17.75mA   -24.52mA
-531.6mV  -12.49mA   -11.51mA   -13.29mA
-398.7mV  -8.133mA   -8.09mA    -7.38mA
-310.1mV  -6.579mA   -6.614mA   -5.675mA
548.4mV   -943.3uA   -635.7uA   -1.063mA
1.266V    4.181mA    4.088mA    3.777mA
1.308V    4.426mA    0A         4.026mA
1.35V     4.669mA    0A         4.27mA
1.394V    0A         0A         4.521mA
1.527V    0A         0A         0A
2.7V      0A         0A         0A
[POWER Clamp]
| Voltage   I(typ)   I(min)   I(max)
-1.35V    62.96mA    54.67mA    83.32mA
-1.196V   51.95mA    44.78mA    69.96mA
-930.2mV  34.05mA    28.98mA    44.66mA
-664.5mV  17.76mA    15.88mA    20.17mA
-531.6mV  11.2mA     10.75mA    10.98mA
-443mV    8.221mA    8.154mA    7.715mA
-354.4mV  6.785mA    6.521mA    6.613mA
-177.2mV  5.674mA    5.174mA    5.627mA
-44.3mV   4.922mA    4.427mA    2.671mA
0V        0A         1.729mA    918.3uA
42.19mV   0A         0A         0A
2.7V      0A         0A         0A
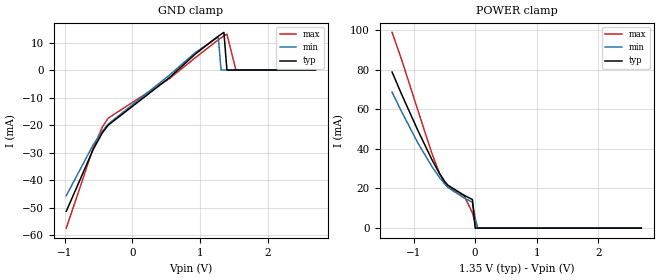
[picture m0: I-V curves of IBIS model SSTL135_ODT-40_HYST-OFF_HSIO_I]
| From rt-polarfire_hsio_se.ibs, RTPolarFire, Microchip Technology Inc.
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|   Model SSTL135_ODT-40_HYST-OFF_HSIO_I
[Model]   SSTL135_ODT-40_HYST-OFF_HSIO_I
Model_type   Input
Vinl =   0.585
Vinh =   0.765
|   typ   min   max
C_comp_pullup   1.335e-12   1.335e-12   1.380e-12
C_comp_pulldown  1.335e-12   1.335e-12   1.380e-12
[Temperature Range]  25C   125C   -55C
[Voltage Range]  1.35   1.2825   1.4175
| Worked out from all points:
|   POWER clamp passes 1 mA (typ) near -0.00 V on its own axis
[GND Clamp]
| Voltage   I(typ)   I(min)   I(max)
-974.5mV  -51.38mA   -45.7mA    -57.5mA
-575.9mV  -28.78mA   -27.1mA    -28.27mA
-443mV    -22.86mA   -22.24mA   -20.75mA
-354.4mV  -19.99mA   -19.63mA   -17.45mA
548.4mV   -2.742mA   -1.825mA   -3.066mA
928.1mV   5.821mA    6.345mA    4.477mA
1.266V    12.29mA    12.08mA    10.99mA
1.308V    12.99mA    0A         11.7mA
1.35V     13.69mA    0A         12.38mA
1.394V    0A         0A         13.09mA
1.527V    0A         0A         0A
2.7V      0A         0A         0A
[POWER Clamp]
| Voltage   I(typ)   I(min)   I(max)
-1.35V    78.74mA    68.56mA    98.75mA
-1.196V   67.56mA    58.78mA    85.07mA
-930.2mV  49.22mA    42.92mA    59.35mA
-708.7mV  34.92mA    31.38mA    38.18mA
-575.9mV  27.34mA    25.43mA    27.4mA
-487.3mV  23.23mA    22.02mA    22.34mA
-443mV    21.63mA    20.56mA    20.72mA
-177.2mV  16.53mA    15.16mA    16.17mA
-44.3mV   14.41mA    13.05mA    7.693mA
0V        0A         5.101mA    2.644mA
42.19mV   0A         0A         0A
2.7V      0A         0A         0A
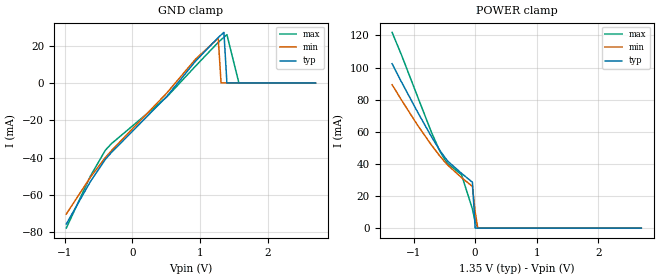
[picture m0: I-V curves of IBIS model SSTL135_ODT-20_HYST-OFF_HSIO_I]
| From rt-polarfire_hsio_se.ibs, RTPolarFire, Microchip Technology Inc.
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|   Model SSTL135_ODT-20_HYST-OFF_HSIO_I
[Model]   SSTL135_ODT-20_HYST-OFF_HSIO_I
Model_type   Input
Vinl =   0.585
Vinh =   0.765
|   typ   min   max
C_comp_pullup   1.335e-12   1.335e-12   1.380e-12
C_comp_pulldown  1.335e-12   1.335e-12   1.380e-12
[Temperature Range]  25C   125C   -55C
[Voltage Range]  1.35   1.2825   1.4175
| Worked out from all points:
|   POWER clamp passes 1 mA (typ) near -0.00 V on its own axis
[GND Clamp]
| Voltage   I(typ)   I(min)   I(max)
-974.5mV  -75.69mA   -70.34mA   -77.89mA
-620.2mV  -52.99mA   -50.65mA   -50.06mA
-398.7mV  -41.01mA   -40.03mA   -36.11mA
-310.1mV  -37.36mA   -36.38mA   -32.62mA
506.2mV   -7.295mA   -5.467mA   -7.55mA
928.1mV   11.57mA    12.64mA    8.917mA
1.266V    24.39mA    24.02mA    21.79mA
1.308V    25.77mA    0A         23.17mA
1.35V     27.14mA    0A         24.52mA
1.394V    0A         0A         25.9mA
1.571V    0A         0A         0A
2.7V      0A         0A         0A
[POWER Clamp]
| Voltage   I(typ)   I(min)   I(max)
-1.35V    102.4mA    89.31mA    121.9mA
-1.196V   90.91mA    79.71mA    107.7mA
-930.2mV  71.9mA     63.77mA    81.33mA
-708.7mV  56.81mA    51.64mA    59.52mA
-575.9mV  48.52mA    45.02mA    48.08mA
-487.3mV  43.71mA    40.98mA    42.29mA
-443mV    41.65mA    39.11mA    40.18mA
-221.5mV  34.12mA    31.49mA    33.24mA
-44.3mV   28.56mA    25.94mA    11.91mA
0V        0A         10.14mA    4.093mA
42.19mV   0A         0A         0A
2.7V      0A         0A         0A
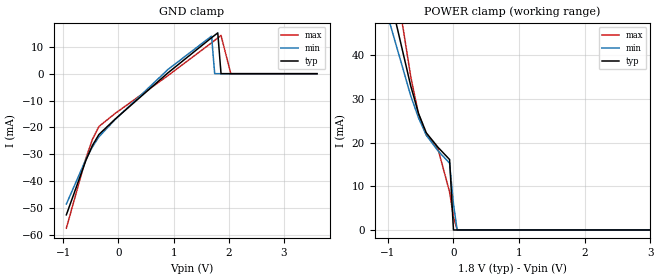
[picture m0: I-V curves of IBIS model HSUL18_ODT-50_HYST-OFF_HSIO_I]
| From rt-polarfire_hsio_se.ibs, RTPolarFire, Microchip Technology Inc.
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|   Model HSUL18_ODT-50_HYST-OFF_HSIO_I
[Model]   HSUL18_ODT-50_HYST-OFF_HSIO_I
Model_type   Input
Vinl =   0.54
Vinh =   1.26
|   typ   min   max
C_comp_pullup   1.335e-12   1.335e-12   1.380e-12
C_comp_pulldown  1.335e-12   1.335e-12   1.380e-12
[Temperature Range]  25C   125C   -55C
[Voltage Range]  1.8   1.71   1.89
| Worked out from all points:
|   POWER clamp passes 1 mA (typ) near -0.00 V on its own axis
[GND Clamp]
| Voltage   I(typ)   I(min)   I(max)
-945mV    -52.51mA   -48.51mA   -57.47mA
-590.6mV  -32.24mA   -31.85mA   -31.45mA
-472.5mV  -26.71mA   -27.25mA   -24.42mA
-354.4mV  -22.62mA   -23.49mA   -19.64mA
-59.06mV  -16.87mA   -17.01mA   -14.76mA
900mV     362.2uA    1.617mA    -671.1uA
1.688V    13.4mA     13.99mA    11.51mA
1.744V    14.29mA    0A         12.4mA
1.8V      15.18mA    0A         13.3mA
1.859V    0A         0A         14.25mA
2.036V    0A         0A         0A
3.6V      0A         0A         0A
[POWER Clamp]
| Voltage   I(typ)   I(min)   I(max)
-1.8V     118mA      100.9mA    153.4mA
-1.595V   99.86mA    86.89mA    126.6mA
-1.477V   90.01mA    78.99mA    113mA
-1.004V   55.72mA    49.14mA    68.58mA
-649.7mV  32.89mA    30.63mA    34.99mA
-531.6mV  26.62mA    25.63mA    26.47mA
-413.4mV  22.21mA    21.67mA    21.71mA
-236.2mV  18.92mA    18.12mA    18.57mA
-59.06mV  16.11mA    15.27mA    8.696mA
0V        0A         5.948mA    2.989mA
56.25mV   0A         0A         0A
3.6V      0A         0A         0A
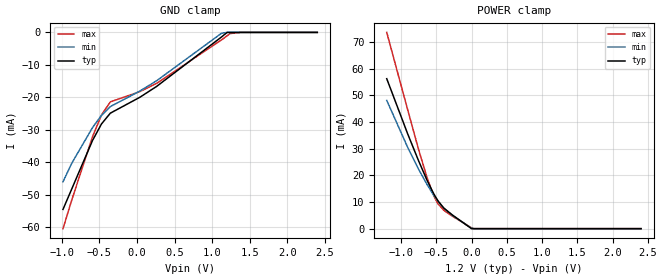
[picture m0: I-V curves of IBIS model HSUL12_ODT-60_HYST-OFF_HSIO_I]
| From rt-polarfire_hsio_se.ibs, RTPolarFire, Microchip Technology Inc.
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|   Model HSUL12_ODT-60_HYST-OFF_HSIO_I
[Model]   HSUL12_ODT-60_HYST-OFF_HSIO_I
Model_type   Input
Vinl =   0.5
Vinh =   0.7
|   typ   min   max
C_comp_pullup   1.335e-12   1.335e-12   1.380e-12
C_comp_pulldown  1.335e-12   1.335e-12   1.380e-12
[Temperature Range]  25C   125C   -55C
[Voltage Range]  1.2   1.14   1.26
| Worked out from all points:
|   POWER clamp passes 1 mA (typ) near -0.05 V on its own axis
[GND Clamp]
| Voltage   I(typ)   I(min)   I(max)
-984.4mV  -54.44mA   -45.94mA   -60.36mA
-866.2mV  -48.07mA   -40.18mA   -51.43mA
-590.6mV  -33.2mA    -29.25mA   -32.02mA
-472.5mV  -28.17mA   -25.52mA   -25.43mA
-354.4mV  -24.84mA   -22.81mA   -21.37mA
37.5mV    -19.97mA   -18.06mA   -18.22mA
262.5mV   -16.6mA    -14.86mA   -15.67mA
1.125V    -1.416mA   -269.5uA   -2.317mA
1.2V      471.4nA    0A         -1.035mA
1.239V    0A         0A         -356.3uA
1.397V    0A         0A         0A
2.4V      0A         0A         0A
[POWER Clamp]
| Voltage   I(typ)   I(min)   I(max)
-1.2V     56.3mA     48.16mA    73.68mA
-905.6mV  35.72mA    30.64mA    44.84mA
-748.1mV  25.4mA     22.25mA    29.62mA
-630mV    18.22mA    16.6mA     19.23mA
-551.3mV  13.94mA    13.21mA    13.45mA
-511.9mV  12.05mA    11.64mA    11.13mA
-472.5mV  10.36mA    10.2mA     9.284mA
-393.7mV  7.762mA    7.726mA    6.919mA
-275.6mV  5.233mA    5.067mA    4.764mA
0V        0A         164uA      310.1uA
37.5mV    0A         0A         0A
2.4V      0A         0A         0A
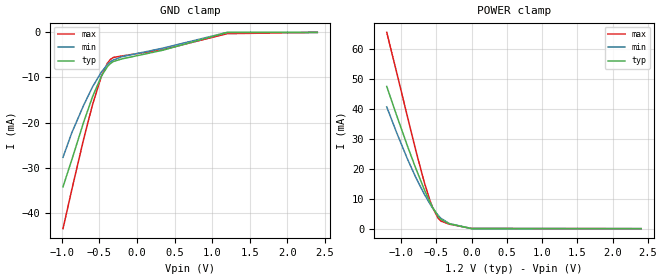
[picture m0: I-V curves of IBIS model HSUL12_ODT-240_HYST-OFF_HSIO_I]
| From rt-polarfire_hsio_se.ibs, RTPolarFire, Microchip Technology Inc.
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|   Model HSUL12_ODT-240_HYST-OFF_HSIO_I
[Model]   HSUL12_ODT-240_HYST-OFF_HSIO_I
Model_type   Input
Vinl =   0.5
Vinh =   0.7
|   typ   min   max
C_comp_pullup   1.335e-12   1.335e-12   1.380e-12
C_comp_pulldown  1.335e-12   1.335e-12   1.380e-12
[Temperature Range]  25C   125C   -55C
[Voltage Range]  1.2   1.14   1.26
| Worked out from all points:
|   POWER clamp passes 1 mA (typ) near -0.20 V on its own axis
[GND Clamp]
| Voltage   I(typ)   I(min)   I(max)
-984.4mV  -34.26mA   -27.71mA   -43.54mA
-866.2mV  -28.21mA   -22.22mA   -34.82mA
-708.7mV  -19.88mA   -16.13mA   -23.62mA
-590.6mV  -14.23mA   -12.07mA   -15.99mA
-472.5mV  -9.682mA   -8.769mA   -9.702mA
-393.7mV  -7.61mA    -7.174mA   -6.838mA
-354.4mV  -6.925mA   -6.583mA   -6.001mA
-315mV    -6.464mA   -6.126mA   -5.564mA
-196.9mV  -5.868mA   -5.366mA   -5.216mA
337.5mV   -3.98mA    -3.524mA   -3.853mA
1.2V      486.4nA    0A         -279.5uA
2.4V      0A         0A         0A
[POWER Clamp]
| Voltage   I(typ)   I(min)   I(max)
-1.2V     47.38mA    40.57mA    65.39mA
-1.063V   37.94mA    32.17mA    52.4mA
-905.6mV  27.45mA    23.15mA    37.18mA
-787.5mV  20mA       17.01mA    25.95mA
-669.4mV  13.06mA    11.54mA    15.52mA
-590.6mV  8.929mA    8.343mA    9.534mA
-551.3mV  7.099mA    6.9mA      7.041mA
-472.5mV  4.126mA    4.422mA    3.506mA
-433.1mV  3.081mA    3.44mA     2.537mA
-315mV    1.626mA    1.699mA    1.489mA
0V        0A         43.72uA    84.32uA
2.4V      0A         0A         0A
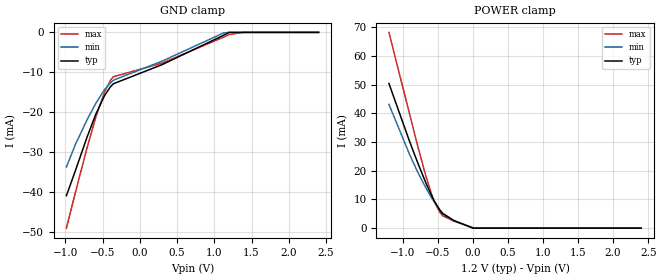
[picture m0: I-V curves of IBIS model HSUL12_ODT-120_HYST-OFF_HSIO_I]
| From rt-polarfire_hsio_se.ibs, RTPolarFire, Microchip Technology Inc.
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|   Model HSUL12_ODT-120_HYST-OFF_HSIO_I
[Model]   HSUL12_ODT-120_HYST-OFF_HSIO_I
Model_type   Input
Vinl =   0.5
Vinh =   0.7
|   typ   min   max
C_comp_pullup   1.335e-12   1.335e-12   1.380e-12
C_comp_pulldown  1.335e-12   1.335e-12   1.380e-12
[Temperature Range]  25C   125C   -55C
[Voltage Range]  1.2   1.14   1.26
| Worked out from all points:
|   POWER clamp passes 1 mA (typ) near -0.10 V on its own axis
[GND Clamp]
| Voltage   I(typ)   I(min)   I(max)
-984.4mV  -40.98mA   -33.8mA    -49.14mA
-866.2mV  -34.82mA   -28.22mA   -40.34mA
-708.7mV  -26.34mA   -21.99mA   -29.04mA
-590.6mV  -20.55mA   -17.81mA   -21.33mA
-472.5mV  -15.85mA   -14.36mA   -14.94mA
-393.7mV  -13.65mA   -12.65mA   -12mA
-354.4mV  -12.9mA    -12mA      -11.13mA
300mV     -8.093mA   -7.212mA   -7.718mA
1.125V    -722uA     -135.9uA   -1.19mA
1.2V      473.9nA    0A         -531.8uA
1.397V    0A         0A         0A
2.4V      0A         0A         0A
[POWER Clamp]
| Voltage   I(typ)   I(min)   I(max)
-1.2V     50.35mA    43.1mA     68.15mA
-905.6mV  30.21mA    25.65mA    39.74mA
-787.5mV  22.64mA    19.43mA    28.42mA
-669.4mV  15.55mA    13.84mA    17.86mA
-590.6mV  11.29mA    10.52mA    11.75mA
-551.3mV  9.384mA    9.006mA    9.182mA
-472.5mV  6.208mA    6.35mA     5.437mA
-433.1mV  5.034mA    5.257mA    4.333mA
-275.6mV  2.681mA    2.628mA    2.457mA
0V        0A         83.86uA    159.8uA
37.5mV    0A         0A         0A
2.4V      0A         0A         0A
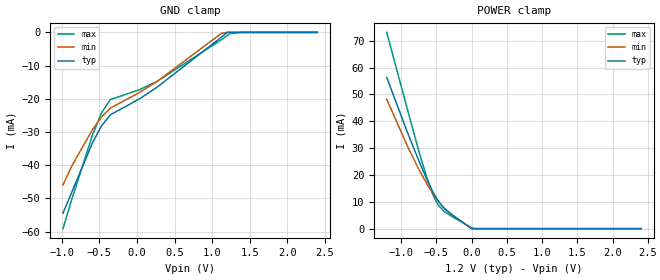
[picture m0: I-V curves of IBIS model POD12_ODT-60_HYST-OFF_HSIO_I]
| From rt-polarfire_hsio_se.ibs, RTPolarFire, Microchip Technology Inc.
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|   Model POD12_ODT-60_HYST-OFF_HSIO_I
[Model]   POD12_ODT-60_HYST-OFF_HSIO_I
Model_type   Input
Vinl =   0.76
Vinh =   0.92
|   typ   min   max
C_comp_pullup   1.335e-12   1.335e-12   1.380e-12
C_comp_pulldown  1.335e-12   1.335e-12   1.380e-12
[Temperature Range]  25C   125C   -55C
[Voltage Range]  1.2   1.14   1.26
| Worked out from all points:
|   POWER clamp passes 1 mA (typ) near -0.05 V on its own axis
[GND Clamp]
| Voltage   I(typ)   I(min)   I(max)
-984.4mV  -54.44mA   -45.94mA   -59.12mA
-866.2mV  -48.07mA   -40.18mA   -50.21mA
-590.6mV  -33.2mA    -29.25mA   -30.84mA
-472.5mV  -28.17mA   -25.52mA   -24.27mA
-354.4mV  -24.84mA   -22.81mA   -20.24mA
37.5mV    -19.97mA   -18.06mA   -17.23mA
262.5mV   -16.6mA    -14.86mA   -14.81mA
1.125V    -1.416mA   -269.5uA   -2.192mA
1.2V      471.4nA    0A         -979uA
1.239V    0A         0A         -337.1uA
1.397V    0A         0A         0A
2.4V      0A         0A         0A
[POWER Clamp]
| Voltage   I(typ)   I(min)   I(max)
-1.2V     56.3mA     48.16mA    73.07mA
-905.6mV  35.72mA    30.64mA    44.27mA
-748.1mV  25.4mA     22.25mA    29.08mA
-630mV    18.22mA    16.6mA     18.72mA
-551.3mV  13.94mA    13.21mA    12.98mA
-511.9mV  12.05mA    11.64mA    10.68mA
-472.5mV  10.36mA    10.2mA     8.857mA
-393.7mV  7.762mA    7.726mA    6.555mA
-275.6mV  5.233mA    5.067mA    4.508mA
0V        0A         164uA      293.5uA
37.5mV    0A         0A         0A
2.4V      0A         0A         0A
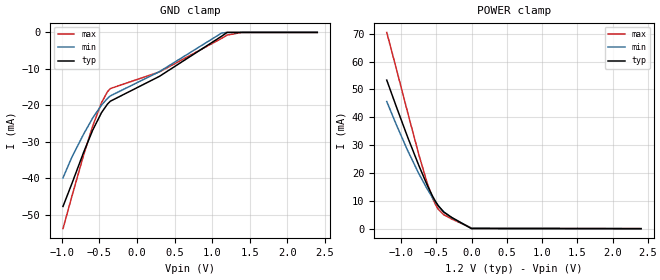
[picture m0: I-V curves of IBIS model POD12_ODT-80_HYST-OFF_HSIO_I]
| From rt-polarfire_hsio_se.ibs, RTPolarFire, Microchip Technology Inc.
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|   Model POD12_ODT-80_HYST-OFF_HSIO_I
[Model]   POD12_ODT-80_HYST-OFF_HSIO_I
Model_type   Input
Vinl =   0.76
Vinh =   0.92
|   typ   min   max
C_comp_pullup   1.335e-12   1.335e-12   1.380e-12
C_comp_pulldown  1.335e-12   1.335e-12   1.380e-12
[Temperature Range]  25C   125C   -55C
[Voltage Range]  1.2   1.14   1.26
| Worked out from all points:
|   POWER clamp passes 1 mA (typ) near -0.07 V on its own axis
[GND Clamp]
| Voltage   I(typ)   I(min)   I(max)
-984.4mV  -47.72mA   -39.88mA   -53.81mA
-866.2mV  -41.46mA   -34.21mA   -44.96mA
-708.7mV  -32.82mA   -27.84mA   -33.57mA
-590.6mV  -26.88mA   -23.53mA   -25.78mA
-472.5mV  -22.02mA   -19.94mA   -19.31mA
-393.7mV  -19.69mA   -18.12mA   -16.31mA
-354.4mV  -18.87mA   -17.41mA   -15.4mA
300mV     -12.04mA   -10.75mA   -10.83mA
1.125V    -1.069mA   -202.7uA   -1.661mA
1.2V      471.4nA    0A         -741.7uA
1.397V    0A         0A         0A
2.4V      0A         0A         0A
[POWER Clamp]
| Voltage   I(typ)   I(min)   I(max)
-1.2V     53.33mA    45.63mA    70.45mA
-1.063V   43.7mA     37.25mA    57.29mA
-905.6mV  32.96mA    28.14mA    41.86mA
-748.1mV  22.81mA    19.87mA    26.8mA
-630mV    15.79mA    14.37mA    16.57mA
-551.3mV  11.66mA    11.11mA    10.96mA
-511.9mV  9.86mA     9.626mA    8.753mA
-472.5mV  8.286mA    8.274mA    7.042mA
-393.7mV  5.963mA    6.039mA    5.008mA
-275.6mV  3.957mA    3.848mA    3.42mA
0V        0A         124uA      222.5uA
2.4V      0A         0A         0A
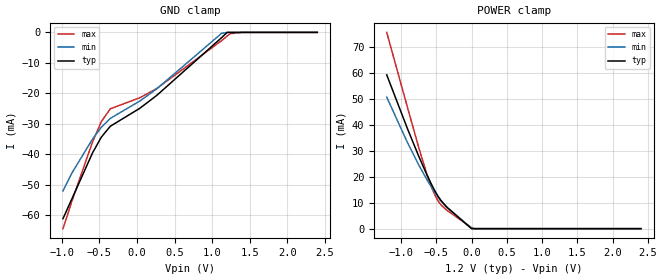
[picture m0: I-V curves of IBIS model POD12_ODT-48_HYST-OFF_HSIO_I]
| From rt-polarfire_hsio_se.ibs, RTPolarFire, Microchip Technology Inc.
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|   Model POD12_ODT-48_HYST-OFF_HSIO_I
[Model]   POD12_ODT-48_HYST-OFF_HSIO_I
Model_type   Input
Vinl =   0.76
Vinh =   0.92
|   typ   min   max
C_comp_pullup   1.335e-12   1.335e-12   1.380e-12
C_comp_pulldown  1.335e-12   1.335e-12   1.380e-12
[Temperature Range]  25C   125C   -55C
[Voltage Range]  1.2   1.14   1.26
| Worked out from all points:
|   POWER clamp passes 1 mA (typ) near -0.04 V on its own axis
[GND Clamp]
| Voltage   I(typ)   I(min)   I(max)
-984.4mV  -61.14mA   -52.02mA   -64.42mA
-866.2mV  -54.66mA   -46.18mA   -55.44mA
-590.6mV  -39.51mA   -34.98mA   -35.89mA
-472.5mV  -34.32mA   -31.1mA    -29.22mA
-354.4mV  -30.8mA    -28.22mA   -25.07mA
37.5mV    -24.92mA   -22.54mA   -21.46mA
262.5mV   -20.7mA    -18.54mA   -18.44mA
1.125V    -1.763mA   -336.2uA   -2.723mA
1.2V      472.4nA    0A         -1.216mA
1.239V    0A         0A         -418.7uA
1.397V    0A         0A         0A
2.4V      0A         0A         0A
[POWER Clamp]
| Voltage   I(typ)   I(min)   I(max)
-1.2V     59.28mA    50.69mA    75.67mA
-905.6mV  38.47mA    33.13mA    46.67mA
-748.1mV  27.99mA    24.63mA    31.36mA
-630mV    20.64mA    18.84mA    20.87mA
-551.3mV  16.22mA    15.31mA    14.99mA
-511.9mV  14.23mA    13.66mA    12.6mA
-472.5mV  12.44mA    12.12mA    10.67mA
-433.1mV  10.88mA    10.7mA     9.201mA
-354.4mV  8.448mA    8.265mA    7.209mA
0V        0A         204.1uA    364.3uA
37.5mV    0A         0A         0A
2.4V      0A         0A         0A
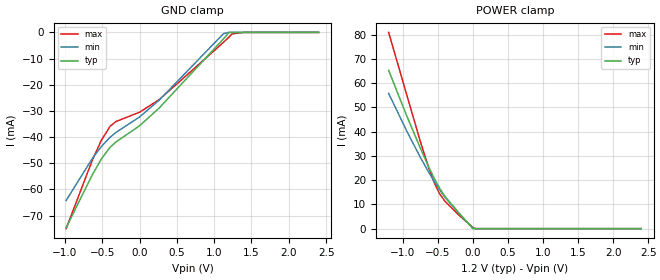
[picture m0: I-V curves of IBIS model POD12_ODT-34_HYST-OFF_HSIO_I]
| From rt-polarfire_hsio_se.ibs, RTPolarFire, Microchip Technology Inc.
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|   Model POD12_ODT-34_HYST-OFF_HSIO_I
[Model]   POD12_ODT-34_HYST-OFF_HSIO_I
Model_type   Input
Vinl =   0.76
Vinh =   0.92
|   typ   min   max
C_comp_pullup   1.335e-12   1.335e-12   1.380e-12
C_comp_pulldown  1.335e-12   1.335e-12   1.380e-12
[Temperature Range]  25C   125C   -55C
[Voltage Range]  1.2   1.14   1.26
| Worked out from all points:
|   POWER clamp passes 1 mA (typ) near -0.03 V on its own axis
[GND Clamp]
| Voltage   I(typ)   I(min)   I(max)
-984.4mV  -74.59mA   -64.22mA   -74.99mA
-630mV    -54.24mA   -48mA      -48.56mA
-511.9mV  -48.34mA   -43.58mA   -41.19mA
-393.7mV  -43.83mA   -40.01mA   -35.81mA
-315mV    -41.83mA   -38.19mA   -34.05mA
0V        -35.68mA   -32.31mA   -30.49mA
262.5mV   -28.9mA    -25.9mA    -25.71mA
1.125V    -2.456mA   -469.7uA   -3.787mA
1.2V      476.1nA    0A         -1.691mA
1.239V    0A         0A         -582.2uA
1.397V    0A         0A         0A
2.4V      0A         0A         0A
[POWER Clamp]
| Voltage   I(typ)   I(min)   I(max)
-1.2V     65.23mA    55.74mA    80.88mA
-945mV    46.73mA    40.4mA     55.44mA
-748.1mV  33.17mA    29.38mA    35.91mA
-630mV    25.5mA     23.3mA     25.16mA
-551.3mV  20.77mA    19.5mA     19.01mA
-472.5mV  16.59mA    15.96mA    14.3mA
-393.7mV  13.15mA    12.79mA    11.19mA
-196.9mV  6.469mA    6.212mA    5.556mA
0V        0A         284.2uA    506.2uA
37.5mV    0A         0A         0A
2.4V      0A         0A         0A
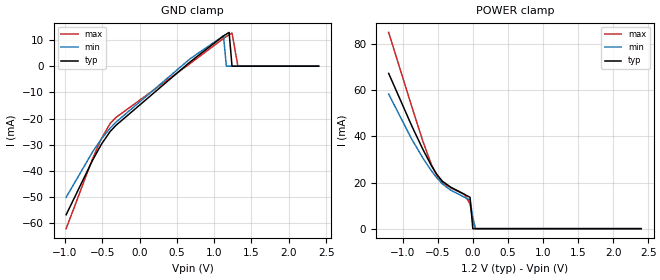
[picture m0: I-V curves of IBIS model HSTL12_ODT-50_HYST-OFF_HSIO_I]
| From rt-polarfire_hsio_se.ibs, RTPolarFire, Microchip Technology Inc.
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|   Model HSTL12_ODT-50_HYST-OFF_HSIO_I
[Model]   HSTL12_ODT-50_HYST-OFF_HSIO_I
Model_type   Input
Vinl =   0.5
Vinh =   0.7
|   typ   min   max
C_comp_pullup   1.335e-12   1.335e-12   1.380e-12
C_comp_pulldown  1.335e-12   1.335e-12   1.380e-12
[Temperature Range]  25C   125C   -55C
[Voltage Range]  1.2   1.14   1.26
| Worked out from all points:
|   POWER clamp passes 1 mA (typ) near -0.00 V on its own axis
[GND Clamp]
| Voltage   I(typ)   I(min)   I(max)
-984.4mV  -56.7mA    -50.03mA   -62.01mA
-630mV    -35.89mA   -32.7mA    -35.31mA
-511.9mV  -29.79mA   -27.8mA    -27.68mA
-393.7mV  -24.9mA    -23.63mA   -21.83mA
-315mV    -22.53mA   -21.34mA   -19.54mA
675mV     1.562mA    2.772mA    972.1uA
1.125V    11.54mA    11.59mA    10.58mA
1.163V    12.23mA    0A         11.29mA
1.2V      12.89mA    0A         11.97mA
1.239V    0A         0A         12.65mA
1.318V    0A         0A         0A
2.4V      0A         0A         0A
[POWER Clamp]
| Voltage   I(typ)   I(min)   I(max)
-1.2V     67.33mA    58.35mA    85.1mA
-866.2mV  44.27mA    38.54mA    52.53mA
-708.7mV  34.18mA    30.47mA    37.59mA
-590.6mV  27.35mA    25.13mA    27.84mA
-511.9mV  23.49mA    22.01mA    22.91mA
-433.1mV  20.54mA    19.39mA    19.87mA
-315mV    17.98mA    16.7mA     17.75mA
-118.1mV  14.86mA    13.63mA    14.87mA
-39.38mV  13.56mA    12.43mA    10.63mA
0V        0A         4.87mA     3.652mA
37.5mV    0A         0A         0A
2.4V      0A         0A         0A
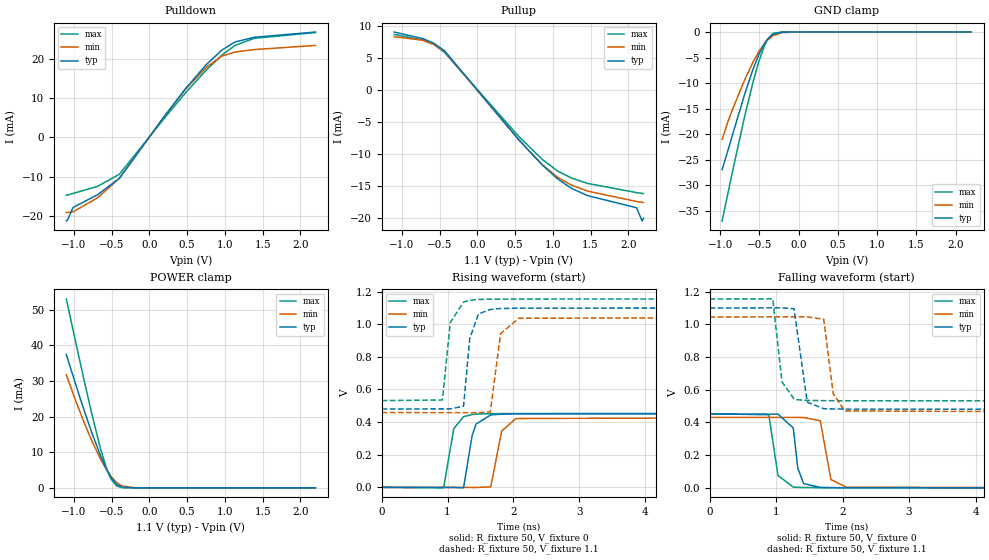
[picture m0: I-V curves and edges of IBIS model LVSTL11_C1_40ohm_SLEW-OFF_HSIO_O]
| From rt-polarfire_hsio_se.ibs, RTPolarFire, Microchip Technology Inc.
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|   Model LVSTL11_C1_40ohm_SLEW-OFF_HSIO_O
[Model]   LVSTL11_C1_40ohm_SLEW-OFF_HSIO_O
Model_type   Output
Polarity   Non-Inverting
Enable   Active-High
Vmeas =   0.55
Cref =   5p
Rref =   50
Vref =   0.55
|   typ   min   max
C_comp_pullup   1.335e-12   1.335e-12   1.380e-12
C_comp_pulldown  1.335e-12   1.335e-12   1.380e-12
[Temperature Range]  25C   125C   -55C
[Voltage Range]  1.1   1.045   1.155
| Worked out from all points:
|   slope of the pulldown table from 0 to 0.165 V, typ, clamps not added: 37.2 ohm
|   slope of the pullup table from 0 to 0.165 V, typ, clamps not added: 69.1 ohm
|   GND clamp passes 1 mA (typ) near -0.37 V on its own axis
|   POWER clamp passes 1 mA (typ) near -0.44 V on its own axis
|   rising waveform, R_fixture 50, V_fixture 0: 20-80 % time 103ps typ, 115ps min, 105ps max; typ from 0 V to 0.451 V
|   rising waveform, R_fixture 50, V_fixture 1.1: 20-80 % time 92.6ps typ, 103ps min, 90.4ps max; typ from 0.48 V to 1.1 V
|   falling waveform, R_fixture 50, V_fixture 0: 20-80 % time 82.4ps typ, 88.4ps min, 78.5ps max; typ from 0.451 V to 0 V
|   falling waveform, R_fixture 50, V_fixture 1.1: 20-80 % time 92ps typ, 101ps min, 88.6ps max; typ from 1.1 V to 0.48 V
[GND Clamp]
| Voltage   I(typ)   I(min)   I(max)
-974.5mV  -26.89mA   -20.99mA   -36.95mA
-902.3mV  -23.27mA   -17.6mA    -31.66mA
-830.2mV  -19.49mA   -14.67mA   -26.42mA
-685.8mV  -12.09mA   -9.316mA   -16.39mA
-577.5mV  -7.136mA   -5.784mA   -9.599mA
-505.3mV  -4.368mA   -3.797mA   -5.695mA
-433.1mV  -2.213mA   -2.208mA   -2.589mA
-397mV    -1.416mA   -1.586mA   -1.459mA
-324.8mV  -429.2uA   -701.1uA   -254.9uA
-216.6mV  -34.07uA   -130.9uA   -6.361uA
-36.09mV  -193.3nA   -2.444uA   -39.83nA
2.2V      0A         0A         0A
[POWER Clamp]
| Voltage   I(typ)   I(min)   I(max)
-1.1V     37.46mA    31.78mA    53.08mA
-974.5mV  29mA       24.39mA    40.83mA
-866.2mV  21.91mA    18.47mA    30.4mA
-758mV    15.25mA    13.04mA    20.38mA
-649.7mV  9.216mA    8.24mA     11.25mA
-577.5mV  5.7mA      5.494mA    6.143mA
-541.4mV  4.17mA     4.282mA    4.067mA
-505.3mV  2.839mA    3.193mA    2.41mA
-433.1mV  941.2uA    1.468mA    503.4uA
-360.9mV  155.7uA    510.6uA    35.77uA
-180.5mV  709.2nA    15.78uA    444.6nA
2.2V      0A         0A         0A
[Pullup]
| Voltage   I(typ)   I(min)   I(max)
-1.1V     9.05mA     8.318mA    8.675mA
-721.9mV  8.022mA    7.771mA    7.794mA
-577.5mV  7.331mA    7.117mA    7.15mA
-433.1mV  6.131mA    6.021mA    5.864mA
550mV     -7.733mA   -7.779mA   -7.237mA
859.4mV   -11.66mA   -11.62mA   -10.8mA
1.066V    -13.87mA   -13.62mA   -12.64mA
1.244V    -15.3mA    -14.8mA    -13.69mA
1.461V    -16.46mA   -15.76mA   -14.56mA
2.111V    -18.36mA   -17.38mA   -15.99mA
2.183V    -20.42mA   -17.5mA    -16.11mA
2.2V      -20mA      -17.53mA   -16.14mA
[Pulldown]
| Voltage   I(typ)   I(min)   I(max)
-1.1V     -21.3mA    -19.1mA    -14.76mA
-1.083V   -21.05mA   -19.13mA   -14.67mA
-1.011V   -17.86mA   -19mA      -14.29mA
-685.8mV  -14.62mA   -15.38mA   -12.49mA
-397mV    -10.43mA   -10.46mA   -9.397mA
206.2mV   5.524mA    5.527mA    5.009mA
481.3mV   12.42mA    12.26mA    11.35mA
756.2mV   18.52mA    17.85mA    17.15mA
962.5mV   22.21mA    20.65mA    20.91mA
1.136V    24.25mA    21.69mA    23.38mA
1.389V    25.43mA    22.31mA    25.17mA
2.2V      26.77mA    23.36mA    26.64mA
[Ramp]
dV/dt_r   0.270859/0.103376n  0.258532/0.115356n  0.271753/0.104852n
dV/dt_f   0.371862/92.0312p  0.351969/0.100996n  0.373889/88.616p
R_load = 50
[Rising Waveform]
R_fixture = 50
V_fixture = 0
V_fixture_min = 0
V_fixture_max = 0
| Time   V(typ)   V(min)   V(max)
0s        1.098uV    2.232uV    1.51uV
940ps     -527.5uV   -550.4uV   -3.013mV
1.094ns   -614.1uV   -641uV     359.7mV
1.243ns   -2.719mV   -728.6uV   433.4mV
1.373ns   317.8mV    -805uV     446mV
1.434ns   388.1mV    -840.9uV   448.7mV
1.656ns   444.3mV    2.713mV    451.7mV
1.821ns   448.3mV    343.9mV    452mV
2.037ns   450.2mV    421.8mV    452.2mV
10ns      451.4mV    430.9mV    452.9mV
[Rising Waveform]
R_fixture = 50
V_fixture = 1.1
V_fixture_min = 1.045
V_fixture_max = 1.155
| Time   V(typ)   V(min)   V(max)
0s        480.2mV    458.3mV    531.8mV
922ps     480.7mV    457.8mV    535.3mV
1.041ns   480.7mV    457.8mV    1.009V
1.243ns   497mV      457.7mV    1.136V
1.337ns   911.9mV    457.6mV    1.146V
1.47ns    1.063V     457.6mV    1.151V
1.649ns   1.09V      462.3mV    1.153V
1.806ns   1.096V     942.3mV    1.153V
2.082ns   1.098V     1.036V     1.154V
10ns      1.1V       1.045V     1.155V
[Falling Waveform]
R_fixture = 50
V_fixture = 0
V_fixture_min = 0
V_fixture_max = 0
| Time   V(typ)   V(min)   V(max)
0s        451.4mV    430.9mV    452.9mV
890ps     450.9mV    430.5mV    447.2mV
1.028ns   450.8mV    430.5mV    75.53mV
1.258ns   366mV      430.4mV    4.603mV
1.326ns   120.6mV    430.4mV    3.047mV
1.413ns   26.12mV    430.3mV    2.055mV
1.664ns   2.686mV    410.5mV    1.07mV
1.825ns   1.265mV    50.49mV    854.1uV
2.062ns   952.5uV    3.496mV    536.9uV
10ns      2.55uV     3.584uV    1.635uV
[Falling Waveform]
R_fixture = 50
V_fixture = 1.1
V_fixture_min = 1.045
V_fixture_max = 1.155
| Time   V(typ)   V(min)   V(max)
0s        1.1V       1.045V     1.155V
949ps     1.101V     1.046V     1.156V
1.088ns   1.101V     1.046V     648.8mV
1.27ns    1.096V     1.046V     543.1mV
1.321ns   947.4mV    1.046V     538.9mV
1.468ns   524.2mV    1.046V     534.9mV
1.716ns   484.4mV    1.031V     533.4mV
1.859ns   482.4mV    576.3mV    533mV
2.033ns   481.6mV    470.2mV    532.9mV
10ns      480.2mV    458.3mV    531.8mV
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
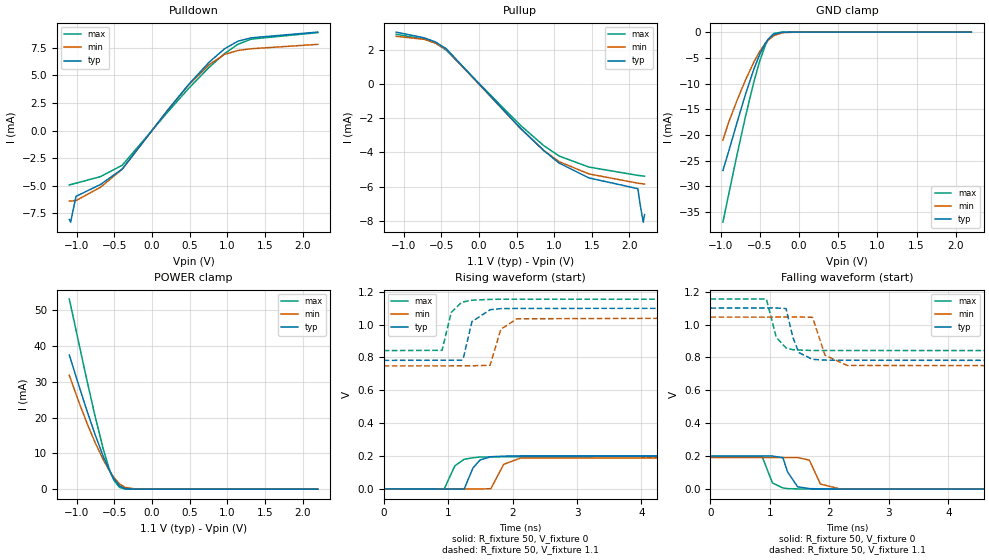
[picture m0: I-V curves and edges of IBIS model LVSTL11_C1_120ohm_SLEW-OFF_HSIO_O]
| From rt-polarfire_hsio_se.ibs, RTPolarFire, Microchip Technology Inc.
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|   Model LVSTL11_C1_120ohm_SLEW-OFF_HSIO_O
[Model]   LVSTL11_C1_120ohm_SLEW-OFF_HSIO_O
Model_type   Output
Polarity   Non-Inverting
Enable   Active-High
Vmeas =   0.55
Cref =   5p
Rref =   50
Vref =   0.55
|   typ   min   max
C_comp_pullup   1.335e-12   1.335e-12   1.380e-12
C_comp_pulldown  1.335e-12   1.335e-12   1.380e-12
[Temperature Range]  25C   125C   -55C
[Voltage Range]  1.1   1.045   1.155
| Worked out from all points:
|   slope of the pulldown table from 0 to 0.165 V, typ, clamps not added: 111 ohm
|   slope of the pullup table from 0 to 0.165 V, typ, clamps not added: 207 ohm
|   GND clamp passes 1 mA (typ) near -0.37 V on its own axis
|   POWER clamp passes 1 mA (typ) near -0.44 V on its own axis
|   rising waveform, R_fixture 50, V_fixture 0: 20-80 % time 147ps typ, 157ps min, 145ps max; typ from 0 V to 0.202 V
|   rising waveform, R_fixture 50, V_fixture 1.1: 20-80 % time 132ps typ, 146ps min, 128ps max; typ from 0.782 V to 1.1 V
|   falling waveform, R_fixture 50, V_fixture 0: 20-80 % time 116ps typ, 133ps min, 109ps max; typ from 0.202 V to 0 V
|   falling waveform, R_fixture 50, V_fixture 1.1: 20-80 % time 142ps typ, 157ps min, 137ps max; typ from 1.1 V to 0.782 V
[GND Clamp]
| Voltage   I(typ)   I(min)   I(max)
-974.5mV  -26.89mA   -20.99mA   -36.95mA
-902.3mV  -23.27mA   -17.6mA    -31.66mA
-794.1mV  -17.59mA   -13.28mA   -23.84mA
-685.8mV  -12.09mA   -9.316mA   -16.39mA
-577.5mV  -7.136mA   -5.784mA   -9.599mA
-505.3mV  -4.368mA   -3.797mA   -5.695mA
-433.1mV  -2.213mA   -2.208mA   -2.589mA
-397mV    -1.416mA   -1.586mA   -1.459mA
-324.8mV  -429.2uA   -701.1uA   -254.9uA
-216.6mV  -34.07uA   -130.9uA   -6.361uA
-36.09mV  -193.3nA   -2.444uA   -39.83nA
2.2V      0A         0A         0A
[POWER Clamp]
| Voltage   I(typ)   I(min)   I(max)
-1.1V     37.46mA    31.78mA    53.08mA
-974.5mV  29mA       24.39mA    40.83mA
-866.2mV  21.91mA    18.47mA    30.4mA
-758mV    15.25mA    13.04mA    20.38mA
-649.7mV  9.216mA    8.24mA     11.25mA
-577.5mV  5.7mA      5.494mA    6.143mA
-541.4mV  4.17mA     4.282mA    4.067mA
-505.3mV  2.839mA    3.193mA    2.41mA
-433.1mV  941.2uA    1.468mA    503.4uA
-360.9mV  155.7uA    510.6uA    35.77uA
-216.6mV  1.401uA    41.48uA    471.7nA
2.2V      0A         0A         0A
[Pullup]
| Voltage   I(typ)   I(min)   I(max)
-1.1V     3.016mA    2.772mA    2.892mA
-721.9mV  2.674mA    2.59mA     2.598mA
-577.5mV  2.443mA    2.373mA    2.384mA
-433.1mV  2.044mA    2.007mA    1.955mA
550mV     -2.578mA   -2.594mA   -2.413mA
859.4mV   -3.887mA   -3.875mA   -3.6mA
1.066V    -4.625mA   -4.541mA   -4.213mA
1.461V    -5.486mA   -5.254mA   -4.855mA
2.111V    -6.116mA   -5.794mA   -5.339mA
2.147V    -7.184mA   -5.815mA   -5.359mA
2.183V    -8.069mA   -5.835mA   -5.378mA
2.2V      -7.627mA   -5.845mA   -5.387mA
[Pulldown]
| Voltage   I(typ)   I(min)   I(max)
-1.1V     -8.06mA    -6.365mA   -4.924mA
-1.083V   -8.295mA   -6.379mA   -4.89mA
-1.011V   -5.956mA   -6.336mA   -4.765mA
-685.8mV  -4.877mA   -5.131mA   -4.165mA
-397mV    -3.484mA   -3.492mA   -3.137mA
206.2mV   1.846mA    1.847mA    1.674mA
481.3mV   4.15mA     4.098mA    3.793mA
756.2mV   6.185mA    5.964mA    5.726mA
962.5mV   7.411mA    6.9mA      6.979mA
1.136V    8.087mA    7.25mA     7.801mA
1.317V    8.403mA    7.413mA    8.287mA
2.2V      8.921mA    7.81mA     8.874mA
[Ramp]
dV/dt_r   0.12108/0.147369n  0.115422/0.157048n  0.117641/0.144686n
dV/dt_f   0.190645/0.141654n  0.17761/0.157248n  0.188057/0.136633n
R_load = 50
[Rising Waveform]
R_fixture = 50
V_fixture = 0
V_fixture_min = 0
V_fixture_max = 0
| Time   V(typ)   V(min)   V(max)
0s        950nV      2.875uV    1.369uV
938ps     -580.7uV   -171.8uV   -1.437mV
1.103ns   -683uV     -202.5uV   140.1mV
1.248ns   -886.2uV   -229.5uV   180.4mV
1.384ns   126.5mV    -254.8uV   189.5mV
1.495ns   176.5mV    -275.5uV   194.2mV
1.663ns   195.9mV    1.595mV    194.8mV
1.861ns   199.4mV    149.6mV    195.4mV
2.12ns    201.1mV    187.3mV    195.7mV
10ns      201.8mV    192.4mV    196.1mV
[Rising Waveform]
R_fixture = 50
V_fixture = 1.1
V_fixture_min = 1.045
V_fixture_max = 1.155
| Time   V(typ)   V(min)   V(max)
0s        782.2mV    748.9mV    841.6mV
905ps     782.9mV    749mV      843.2mV
1.048ns   783mV      749mV      1.074V
1.208ns   783.1mV    749.1mV    1.135V
1.238ns   800.3mV    749.1mV    1.138V
1.37ns    1.018V     749.1mV    1.148V
1.651ns   1.09V      752.1mV    1.153V
1.818ns   1.097V     971.4mV    1.154V
2.065ns   1.098V     1.035V     1.154V
10ns      1.1V       1.045V     1.155V
[Falling Waveform]
R_fixture = 50
V_fixture = 0
V_fixture_min = 0
V_fixture_max = 0
| Time   V(typ)   V(min)   V(max)
0s        201.8mV    192.4mV    196.1mV
873ps     201.2mV    192mV      193.9mV
1.043ns   201.1mV    192mV      37.45mV
1.218ns   191.8mV    191.9mV    7.29mV
1.295ns   105.7mV    191.9mV    3.535mV
1.465ns   14.57mV    191.8mV    1.483mV
1.663ns   3.614mV    176.6mV    746.1uV
1.849ns   1.039mV    31.06mV    729.4uV
2.172ns   803.6uV    1.777mV    700.6uV
10ns      1.156uV    2.895uV    967.9nV
[Falling Waveform]
R_fixture = 50
V_fixture = 1.1
V_fixture_min = 1.045
V_fixture_max = 1.155
| Time   V(typ)   V(min)   V(max)
0s        1.1V       1.045V     1.155V
941ps     1.101V     1.045V     1.155V
1.106ns   1.101V     1.046V     922.3mV
1.271ns   1.097V     1.046V     857.9mV
1.384ns   924.7mV    1.046V     847.1mV
1.484ns   830.3mV    1.046V     845.4mV
1.716ns   788.6mV    1.044V     842.5mV
1.926ns   784.2mV    814.1mV    842.5mV
2.298ns   783.1mV    751.6mV    842.5mV
10ns      782.2mV    748.9mV    841.6mV
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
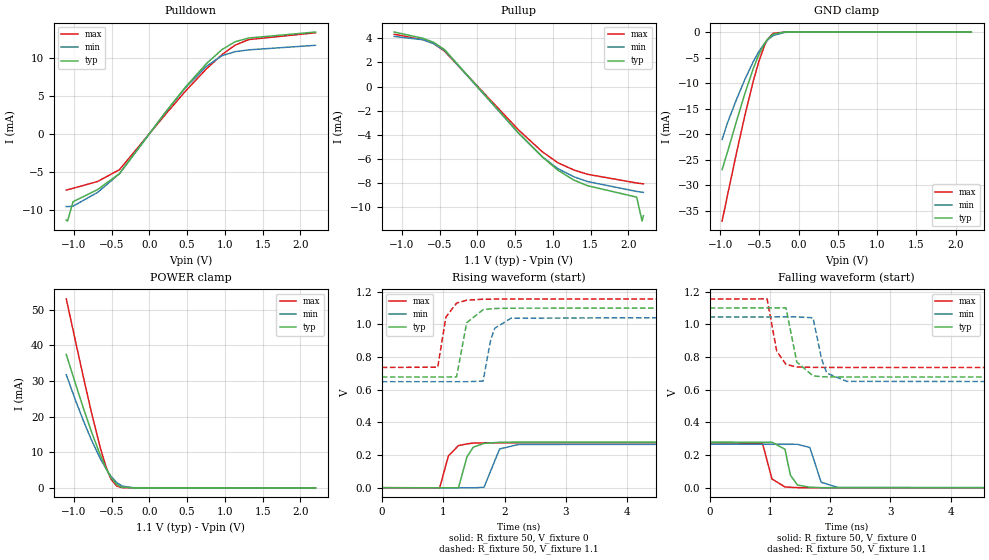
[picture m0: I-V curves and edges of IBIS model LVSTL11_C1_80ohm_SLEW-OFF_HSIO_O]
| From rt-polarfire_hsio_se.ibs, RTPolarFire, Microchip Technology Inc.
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|   Model LVSTL11_C1_80ohm_SLEW-OFF_HSIO_O
[Model]   LVSTL11_C1_80ohm_SLEW-OFF_HSIO_O
Model_type   Output
Polarity   Non-Inverting
Enable   Active-High
Vmeas =   0.55
Cref =   5p
Rref =   50
Vref =   0.55
|   typ   min   max
C_comp_pullup   1.335e-12   1.335e-12   1.380e-12
C_comp_pulldown  1.335e-12   1.335e-12   1.380e-12
[Temperature Range]  25C   125C   -55C
[Voltage Range]  1.1   1.045   1.155
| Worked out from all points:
|   slope of the pulldown table from 0 to 0.165 V, typ, clamps not added: 74.1 ohm
|   slope of the pullup table from 0 to 0.165 V, typ, clamps not added: 138 ohm
|   GND clamp passes 1 mA (typ) near -0.37 V on its own axis
|   POWER clamp passes 1 mA (typ) near -0.44 V on its own axis
|   rising waveform, R_fixture 50, V_fixture 0: 20-80 % time 132ps typ, 144ps min, 131ps max; typ from 0 V to 0.28 V
|   rising waveform, R_fixture 50, V_fixture 1.1: 20-80 % time 120ps typ, 133ps min, 115ps max; typ from 0.677 V to 1.1 V
|   falling waveform, R_fixture 50, V_fixture 0: 20-80 % time 106ps typ, 118ps min, 102ps max; typ from 0.28 V to 0 V
|   falling waveform, R_fixture 50, V_fixture 1.1: 20-80 % time 125ps typ, 139ps min, 121ps max; typ from 1.1 V to 0.677 V
[GND Clamp]
| Voltage   I(typ)   I(min)   I(max)
-974.5mV  -26.89mA   -20.99mA   -36.95mA
-902.3mV  -23.27mA   -17.6mA    -31.66mA
-794.1mV  -17.59mA   -13.28mA   -23.84mA
-685.8mV  -12.09mA   -9.316mA   -16.39mA
-577.5mV  -7.136mA   -5.784mA   -9.599mA
-505.3mV  -4.368mA   -3.797mA   -5.695mA
-433.1mV  -2.213mA   -2.208mA   -2.589mA
-397mV    -1.416mA   -1.586mA   -1.459mA
-324.8mV  -429.2uA   -701.1uA   -254.9uA
-180.5mV  -13.02uA   -66.84uA   -1.727uA
-36.09mV  -193.3nA   -2.444uA   -39.83nA
2.2V      0A         0A         0A
[POWER Clamp]
| Voltage   I(typ)   I(min)   I(max)
-1.1V     37.46mA    31.78mA    53.08mA
-974.5mV  29mA       24.39mA    40.83mA
-866.2mV  21.91mA    18.47mA    30.4mA
-758mV    15.25mA    13.04mA    20.38mA
-649.7mV  9.216mA    8.24mA     11.25mA
-577.5mV  5.7mA      5.494mA    6.143mA
-541.4mV  4.17mA     4.282mA    4.067mA
-505.3mV  2.839mA    3.193mA    2.41mA
-433.1mV  941.2uA    1.468mA    503.4uA
-360.9mV  155.7uA    510.6uA    35.77uA
-216.6mV  1.401uA    41.48uA    471.7nA
2.2V      0A         0A         0A
[Pullup]
| Voltage   I(typ)   I(min)   I(max)
-1.1V     4.524mA    4.159mA    4.338mA
-721.9mV  4.011mA    3.886mA    3.897mA
-577.5mV  3.665mA    3.559mA    3.576mA
-433.1mV  3.066mA    3.011mA    2.933mA
550mV     -3.867mA   -3.89mA    -3.62mA
859.4mV   -5.831mA   -5.812mA   -5.401mA
1.066V    -6.938mA   -6.81mA    -6.319mA
1.28V     -7.766mA   -7.49mA    -6.928mA
1.461V    -8.231mA   -7.883mA   -7.283mA
2.111V    -9.178mA   -8.706mA   -8.004mA
2.183V    -11.16mA   -8.77mA    -8.062mA
2.2V      -10.72mA   -8.785mA   -8.076mA
[Pulldown]
| Voltage   I(typ)   I(min)   I(max)
-1.1V     -11.34mA   -9.545mA   -7.389mA
-1.083V   -11.46mA   -9.566mA   -7.339mA
-1.011V   -8.923mA   -9.502mA   -7.152mA
-685.8mV  -7.313mA   -7.695mA   -6.253mA
-397mV    -5.224mA   -5.236mA   -4.708mA
206.2mV   2.77mA     2.769mA    2.511mA
481.3mV   6.229mA    6.142mA    5.691mA
756.2mV   9.29mA     8.938mA    8.595mA
962.5mV   11.14mA    10.34mA    10.48mA
1.136V    12.17mA    10.86mA    11.72mA
1.317V    12.66mA    11.1mA     12.46mA
2.2V      13.45mA    11.7mA     13.35mA
[Ramp]
dV/dt_r   0.16784/0.132399n  0.160123/0.143744n  0.165114/0.131035n
dV/dt_f   0.253774/0.124643n  0.237952/0.139378n  0.251604/0.12123n
R_load = 50
[Rising Waveform]
R_fixture = 50
V_fixture = 0
V_fixture_min = 0
V_fixture_max = 0
| Time   V(typ)   V(min)   V(max)
0s        1.002uV    2.648uV    1.417uV
943ps     -502uV     -566uV     -859.6uV
1.085ns   -577.7uV   -651.6uV   194.3mV
1.249ns   -413.7uV   -750.5uV   257.6mV
1.388ns   189.1mV    -834.3uV   268mV
1.49ns    247.7mV    -895.8uV   272.9mV
1.665ns   271mV      2.613mV    273.6mV
1.919ns   277.6mV    237.1mV    274.7mV
2.231ns   279.2mV    264.6mV    274.8mV
10ns      279.7mV    266.9mV    275.2mV
[Rising Waveform]
R_fixture = 50
V_fixture = 1.1
V_fixture_min = 1.045
V_fixture_max = 1.155
| Time   V(typ)   V(min)   V(max)
0s        677mV      648.3mV    735.6mV
912ps     677mV      648.4mV    737.2mV
1.044ns   677mV      648.4mV    1.043V
1.218ns   678mV      648.5mV    1.129V
1.383ns   1.009V     648.5mV    1.147V
1.65ns    1.089V     651.8mV    1.153V
1.771ns   1.094V     900.9mV    1.153V
1.84ns    1.096V     975.3mV    1.154V
2.106ns   1.098V     1.037V     1.154V
10ns      1.1V       1.045V     1.155V
[Falling Waveform]
R_fixture = 50
V_fixture = 0
V_fixture_min = 0
V_fixture_max = 0
| Time   V(typ)   V(min)   V(max)
0s        279.7mV    266.9mV    275.2mV
878ps     279.2mV    266.6mV    271.8mV
1.035ns   279.1mV    266.6mV    54.01mV
1.251ns   236.1mV    266.5mV    5.588mV
1.341ns   77.58mV    266.5mV    3.509mV
1.458ns   17.41mV    266.4mV    1.429mV
1.663ns   3.805mV    247.1mV    808.4uV
1.852ns   1.217mV    34.13mV    453.2uV
2.129ns   443.4uV    2.629mV    437.9uV
10ns      1.853uV    4.009uV    2.172uV
[Falling Waveform]
R_fixture = 50
V_fixture = 1.1
V_fixture_min = 1.045
V_fixture_max = 1.155
| Time   V(typ)   V(min)   V(max)
0s        1.1V       1.045V     1.155V
954ps     1.101V     1.045V     1.156V
1.114ns   1.101V     1.046V     835.9mV
1.267ns   1.101V     1.046V     755.4mV
1.447ns   769.9mV    1.046V     739.5mV
1.717ns   684.9mV    1.04V      737.1mV
1.861ns   679.6mV    785.5mV    736.9mV
1.946ns   679mV      701.8mV    736.7mV
2.276ns   678.1mV    651.4mV    736.3mV
10ns      677mV      648.3mV    735.6mV
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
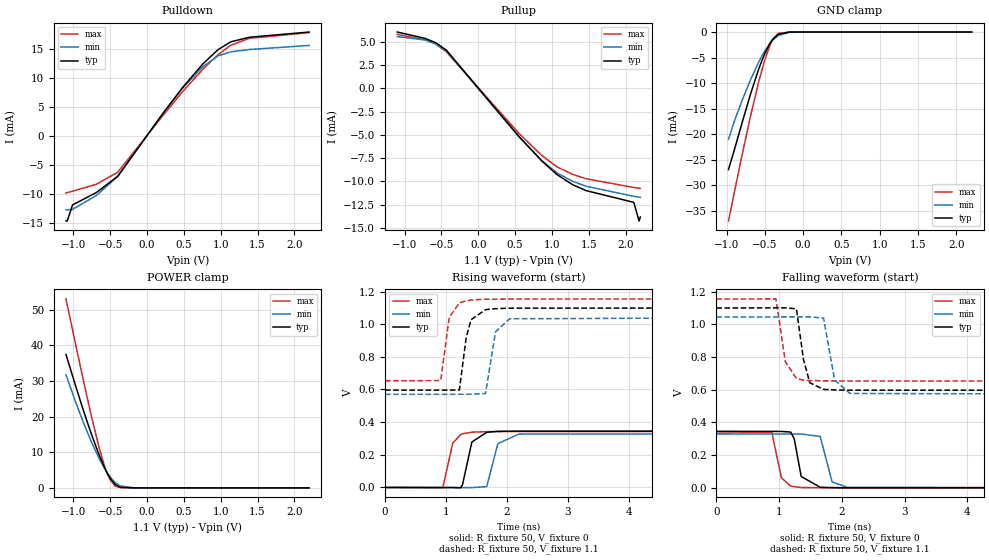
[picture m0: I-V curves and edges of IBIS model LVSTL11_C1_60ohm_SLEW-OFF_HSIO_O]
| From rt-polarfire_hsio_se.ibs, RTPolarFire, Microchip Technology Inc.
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|   Model LVSTL11_C1_60ohm_SLEW-OFF_HSIO_O
[Model]   LVSTL11_C1_60ohm_SLEW-OFF_HSIO_O
Model_type   Output
Polarity   Non-Inverting
Enable   Active-High
Vmeas =   0.55
Cref =   5p
Rref =   50
Vref =   0.55
|   typ   min   max
C_comp_pullup   1.335e-12   1.335e-12   1.380e-12
C_comp_pulldown  1.335e-12   1.335e-12   1.380e-12
[Temperature Range]  25C   125C   -55C
[Voltage Range]  1.1   1.045   1.155
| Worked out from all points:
|   slope of the pulldown table from 0 to 0.165 V, typ, clamps not added: 55.7 ohm
|   slope of the pullup table from 0 to 0.165 V, typ, clamps not added: 104 ohm
|   GND clamp passes 1 mA (typ) near -0.37 V on its own axis
|   POWER clamp passes 1 mA (typ) near -0.44 V on its own axis
|   rising waveform, R_fixture 50, V_fixture 0: 20-80 % time 123ps typ, 131ps min, 122ps max; typ from 0 V to 0.346 V
|   rising waveform, R_fixture 50, V_fixture 1.1: 20-80 % time 109ps typ, 118ps min, 106ps max; typ from 0.596 V to 1.1 V
|   falling waveform, R_fixture 50, V_fixture 0: 20-80 % time 99.3ps typ, 103ps min, 92.1ps max; typ from 0.346 V to 0 V
|   falling waveform, R_fixture 50, V_fixture 1.1: 20-80 % time 110ps typ, 121ps min, 110ps max; typ from 1.1 V to 0.596 V
[GND Clamp]
| Voltage   I(typ)   I(min)   I(max)
-974.5mV  -26.89mA   -20.99mA   -36.95mA
-902.3mV  -23.27mA   -17.6mA    -31.66mA
-794.1mV  -17.59mA   -13.28mA   -23.84mA
-685.8mV  -12.09mA   -9.316mA   -16.39mA
-577.5mV  -7.136mA   -5.784mA   -9.599mA
-505.3mV  -4.368mA   -3.797mA   -5.695mA
-433.1mV  -2.213mA   -2.208mA   -2.589mA
-397mV    -1.416mA   -1.586mA   -1.459mA
-324.8mV  -429.2uA   -701.1uA   -254.9uA
-180.5mV  -13.02uA   -66.84uA   -1.727uA
-36.09mV  -193.3nA   -2.444uA   -39.83nA
2.2V      0A         0A         0A
[POWER Clamp]
| Voltage   I(typ)   I(min)   I(max)
-1.1V     37.46mA    31.78mA    53.08mA
-974.5mV  29mA       24.39mA    40.83mA
-866.2mV  21.91mA    18.47mA    30.4mA
-758mV    15.25mA    13.04mA    20.38mA
-649.7mV  9.216mA    8.24mA     11.25mA
-577.5mV  5.7mA      5.494mA    6.143mA
-541.4mV  4.17mA     4.282mA    4.067mA
-505.3mV  2.839mA    3.193mA    2.41mA
-433.1mV  941.2uA    1.468mA    503.4uA
-360.9mV  155.7uA    510.6uA    35.77uA
-180.5mV  709.2nA    15.78uA    444.6nA
2.2V      0A         0A         0A
[Pullup]
| Voltage   I(typ)   I(min)   I(max)
-1.1V     6.034mA    5.546mA    5.783mA
-721.9mV  5.349mA    5.181mA    5.195mA
-577.5mV  4.888mA    4.745mA    4.767mA
-433.1mV  4.088mA    4.014mA    3.91mA
550mV     -5.156mA   -5.186mA   -4.825mA
859.4mV   -7.774mA   -7.748mA   -7.199mA
1.066V    -9.249mA   -9.079mA   -8.424mA
1.28V     -10.35mA   -9.986mA   -9.237mA
1.461V    -10.98mA   -10.51mA   -9.709mA
2.111V    -12.25mA   -11.6mA    -10.65mA
2.183V    -14.25mA   -11.69mA   -10.73mA
2.2V      -13.82mA   -11.71mA   -10.75mA
[Pulldown]
| Voltage   I(typ)   I(min)   I(max)
-1.1V     -14.65mA   -12.72mA   -9.852mA
-1.083V   -14.67mA   -12.75mA   -9.785mA
-1.011V   -11.9mA    -12.67mA   -9.535mA
-685.8mV  -9.749mA   -10.26mA   -8.333mA
-397mV    -6.961mA   -6.975mA   -6.27mA
206.2mV   3.688mA    3.687mA    3.342mA
481.3mV   8.295mA    8.179mA    7.575mA
756.2mV   12.37mA    11.9mA     11.44mA
962.5mV   14.83mA    13.76mA    13.95mA
1.136V    16.19mA    14.46mA    15.6mA
1.389V    16.98mA    14.87mA    16.8mA
2.2V      17.88mA    15.57mA    17.77mA
[Ramp]
dV/dt_r   0.207508/0.122557n  0.198039/0.131158n  0.205881/0.12247n
dV/dt_f   0.302261/0.109747n  0.284737/0.121052n  0.301221/0.109736n
R_load = 50
[Rising Waveform]
R_fixture = 50
V_fixture = 0
V_fixture_min = 0
V_fixture_max = 0
| Time   V(typ)   V(min)   V(max)
0s        1.042uV    2.477uV    1.455uV
947ps     -574.4uV   -576.9uV   -1.102mV
1.11ns    -673.4uV   -676.6uV   270.7mV
1.238ns   -2.337mV   -754.9uV   323.4mV
1.27ns    16.05mV    -774.5uV   328.3mV
1.424ns   278.3mV    -868.7uV   338.5mV
1.668ns   338mV      5.148mV    341.7mV
1.85ns    343.8mV    268.3mV    342.3mV
2.194ns   344.9mV    326.8mV    342.4mV
10ns      345.8mV    330.1mV    343.1mV
[Rising Waveform]
R_fixture = 50
V_fixture = 1.1
V_fixture_min = 1.045
V_fixture_max = 1.155
| Time   V(typ)   V(min)   V(max)
0s        596.2mV    570.4mV    652.9mV
913ps     596.2mV    570.7mV    654.8mV
1.053ns   596.1mV    570.8mV    1.042V
1.219ns   597.3mV    570.8mV    1.13V
1.33ns    915.2mV    570.9mV    1.143V
1.41ns    1.027V     570.9mV    1.148V
1.648ns   1.089V     575.4mV    1.153V
1.813ns   1.095V     953.8mV    1.153V
2.044ns   1.098V     1.033V     1.154V
10ns      1.1V       1.045V     1.155V
[Falling Waveform]
R_fixture = 50
V_fixture = 0
V_fixture_min = 0
V_fixture_max = 0
| Time   V(typ)   V(min)   V(max)
0s        345.8mV    330.1mV    343.1mV
885ps     345.2mV    329.6mV    338.6mV
1.036ns   345.1mV    329.6mV    61.79mV
1.186ns   341.2mV    329.5mV    10.12mV
1.241ns   299.8mV    329.5mV    7.082mV
1.352ns   69.37mV    329.4mV    2.343mV
1.654ns   3.731mV    314.6mV    650.4uV
1.845ns   1.292mV    36.36mV    538.1uV
2.09ns    531.7uV    3.069mV    522uV
10ns      2.034uV    1.034uV    1.543uV
[Falling Waveform]
R_fixture = 50
V_fixture = 1.1
V_fixture_min = 1.045
V_fixture_max = 1.155
| Time   V(typ)   V(min)   V(max)
0s        1.1V       1.045V     1.155V
950ps     1.101V     1.045V     1.156V
1.099ns   1.101V     1.046V     772.4mV
1.276ns   1.095V     1.046V     668.5mV
1.389ns   784mV      1.046V     658.5mV
1.489ns   642.9mV    1.046V     656.5mV
1.708ns   602.2mV    1.038V     654.6mV
1.885ns   598.7mV    659.4mV    654.1mV
2.13ns    597.5mV    577.3mV    653.8mV
10ns      596.2mV    570.4mV    653mV
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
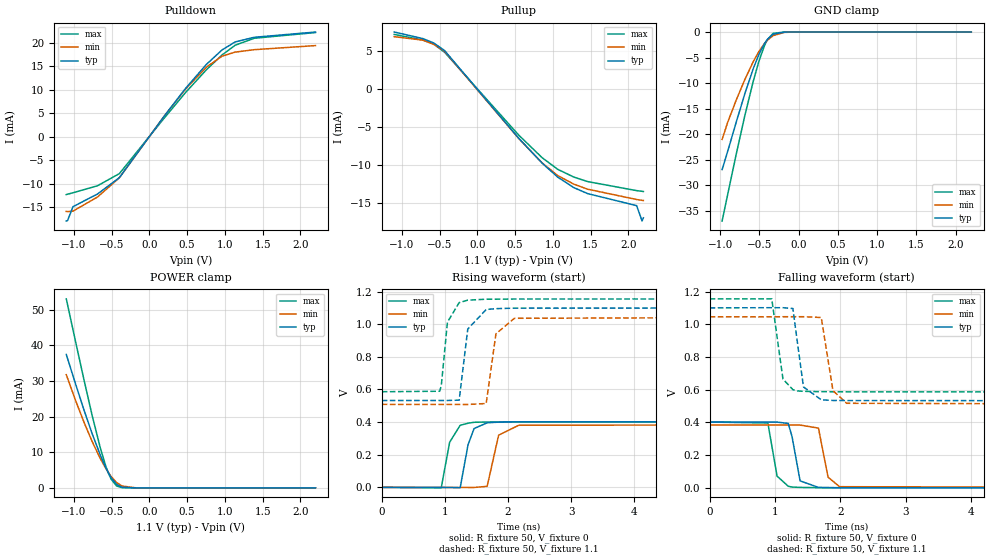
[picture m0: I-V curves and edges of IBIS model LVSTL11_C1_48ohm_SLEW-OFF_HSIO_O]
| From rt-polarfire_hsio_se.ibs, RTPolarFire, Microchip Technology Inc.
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|   Model LVSTL11_C1_48ohm_SLEW-OFF_HSIO_O
[Model]   LVSTL11_C1_48ohm_SLEW-OFF_HSIO_O
Model_type   Output
Polarity   Non-Inverting
Enable   Active-High
Vmeas =   0.55
Cref =   5p
Rref =   50
Vref =   0.55
|   typ   min   max
C_comp_pullup   1.335e-12   1.335e-12   1.380e-12
C_comp_pulldown  1.335e-12   1.335e-12   1.380e-12
[Temperature Range]  25C   125C   -55C
[Voltage Range]  1.1   1.045   1.155
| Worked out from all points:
|   slope of the pulldown table from 0 to 0.165 V, typ, clamps not added: 44.6 ohm
|   slope of the pullup table from 0 to 0.165 V, typ, clamps not added: 83 ohm
|   GND clamp passes 1 mA (typ) near -0.37 V on its own axis
|   POWER clamp passes 1 mA (typ) near -0.44 V on its own axis
|   rising waveform, R_fixture 50, V_fixture 0: 20-80 % time 115ps typ, 124ps min, 117ps max; typ from 0 V to 0.402 V
|   rising waveform, R_fixture 50, V_fixture 1.1: 20-80 % time 101ps typ, 109ps min, 97.6ps max; typ from 0.532 V to 1.1 V
|   falling waveform, R_fixture 50, V_fixture 0: 20-80 % time 90.4ps typ, 95.3ps min, 84.2ps max; typ from 0.402 V to 0 V
|   falling waveform, R_fixture 50, V_fixture 1.1: 20-80 % time 100ps typ, 111ps min, 99.8ps max; typ from 1.1 V to 0.532 V
[GND Clamp]
| Voltage   I(typ)   I(min)   I(max)
-974.5mV  -26.89mA   -20.99mA   -36.95mA
-902.3mV  -23.27mA   -17.6mA    -31.66mA
-794.1mV  -17.59mA   -13.28mA   -23.84mA
-685.8mV  -12.09mA   -9.316mA   -16.39mA
-577.5mV  -7.136mA   -5.784mA   -9.599mA
-505.3mV  -4.368mA   -3.797mA   -5.695mA
-433.1mV  -2.213mA   -2.208mA   -2.589mA
-397mV    -1.416mA   -1.586mA   -1.459mA
-324.8mV  -429.2uA   -701.1uA   -254.9uA
-180.5mV  -13.02uA   -66.84uA   -1.727uA
-36.09mV  -193.3nA   -2.444uA   -39.83nA
2.2V      0A         0A         0A
[POWER Clamp]
| Voltage   I(typ)   I(min)   I(max)
-1.1V     37.46mA    31.78mA    53.08mA
-974.5mV  29mA       24.39mA    40.83mA
-866.2mV  21.91mA    18.47mA    30.4mA
-758mV    15.25mA    13.04mA    20.38mA
-649.7mV  9.216mA    8.24mA     11.25mA
-577.5mV  5.7mA      5.494mA    6.143mA
-541.4mV  4.17mA     4.282mA    4.067mA
-505.3mV  2.839mA    3.193mA    2.41mA
-433.1mV  941.2uA    1.468mA    503.4uA
-360.9mV  155.7uA    510.6uA    35.77uA
-180.5mV  709.2nA    15.78uA    444.6nA
2.2V      0A         0A         0A
[Pullup]
| Voltage   I(typ)   I(min)   I(max)
-1.1V     7.542mA    6.932mA    7.229mA
-721.9mV  6.685mA    6.476mA    6.495mA
-577.5mV  6.109mA    5.932mA    5.959mA
-433.1mV  5.109mA    5.019mA    4.887mA
550mV     -6.443mA   -6.484mA   -6.031mA
859.4mV   -9.715mA   -9.686mA   -8.999mA
1.066V    -11.56mA   -11.35mA   -10.53mA
1.28V     -12.94mA   -12.48mA   -11.55mA
1.461V    -13.72mA   -13.14mA   -12.14mA
2.111V    -15.31mA   -14.5mA    -13.33mA
2.183V    -17.33mA   -14.61mA   -13.42mA
2.2V      -16.91mA   -14.63mA   -13.45mA
[Pulldown]
| Voltage   I(typ)   I(min)   I(max)
-1.1V     -17.94mA   -15.9mA    -12.31mA
-1.083V   -17.85mA   -15.94mA   -12.23mA
-1.011V   -14.88mA   -15.83mA   -11.92mA
-685.8mV  -12.18mA   -12.82mA   -10.42mA
-397mV    -8.698mA   -8.718mA   -7.84mA
206.2mV   4.608mA    4.607mA    4.18mA
481.3mV   10.36mA    10.22mA    9.476mA
756.2mV   15.45mA    14.87mA    14.31mA
962.5mV   18.52mA    17.19mA    17.45mA
1.136V    20.23mA    18.06mA    19.52mA
1.389V    21.22mA    18.58mA    21.01mA
2.2V      22.34mA    19.45mA    22.23mA
[Ramp]
dV/dt_r   0.241495/0.114792n  0.230564/0.123881n  0.241114/0.116858n
dV/dt_f   0.340749/0.100179n  0.321868/0.111042n  0.341408/99.7511p
R_load = 50
[Rising Waveform]
R_fixture = 50
V_fixture = 0
V_fixture_min = 0
V_fixture_max = 0
| Time   V(typ)   V(min)   V(max)
0s        1.073uV    2.342uV    1.485uV
942ps     -665.2uV   -520.1uV   -3.003mV
1.075ns   -759.3uV   -593.8uV   276.5mV
1.242ns   -2.247mV   -686.4uV   380.3mV
1.367ns   261.7mV    -755.7uV   393mV
1.462ns   360.4mV    -808.4uV   398.7mV
1.669ns   395.6mV    6.318mV    400.5mV
1.851ns   399.7mV    319.9mV    400.8mV
2.17ns    401.6mV    380.6mV    401.3mV
10ns      402.5mV    384.3mV    401.9mV
[Rising Waveform]
R_fixture = 50
V_fixture = 1.1
V_fixture_min = 1.045
V_fixture_max = 1.155
| Time   V(typ)   V(min)   V(max)
0s        532.1mV    508.5mV    586mV
917ps     532.3mV    508mV      588.9mV
943ps     532.3mV    508mV      622.8mV
1.04ns    532.3mV    507.9mV    1.012V
1.226ns   534.4mV    507.8mV    1.132V
1.362ns   970mV      507.7mV    1.147V
1.654ns   1.09V      513.9mV    1.153V
1.808ns   1.095V     940.9mV    1.153V
2.101ns   1.098V     1.036V     1.154V
10ns      1.1V       1.045V     1.155V
[Falling Waveform]
R_fixture = 50
V_fixture = 0
V_fixture_min = 0
V_fixture_max = 0
| Time   V(typ)   V(min)   V(max)
0s        402.5mV    384.3mV    401.9mV
890ps     401.9mV    384mV      396.6mV
1.031ns   401.8mV    383.9mV    71.87mV
1.202ns   393.8mV    383.8mV    9.602mV
1.26ns    313.1mV    383.8mV    4.876mV
1.383ns   42.62mV    383.8mV    2.729mV
1.664ns   2.673mV    365mV      1.002mV
1.811ns   1.593mV    65.12mV    920.5uV
1.987ns   603uV      7.056mV    823.3uV
10ns      3.949uV    3.554uV    3.074uV
[Falling Waveform]
R_fixture = 50
V_fixture = 1.1
V_fixture_min = 1.045
V_fixture_max = 1.155
| Time   V(typ)   V(min)   V(max)
0s        1.1V       1.045V     1.155V
950ps     1.101V     1.045V     1.155V
1.121ns   1.101V     1.046V     664.9mV
1.273ns   1.096V     1.046V     600.2mV
1.342ns   888.7mV    1.046V     592.5mV
1.435ns   616.8mV    1.046V     589.8mV
1.707ns   538mV      1.041V     587.7mV
1.886ns   534.1mV    593.8mV    587.2mV
2.096ns   533.5mV    516.8mV    586.9mV
10ns      532.1mV    508.5mV    586mV
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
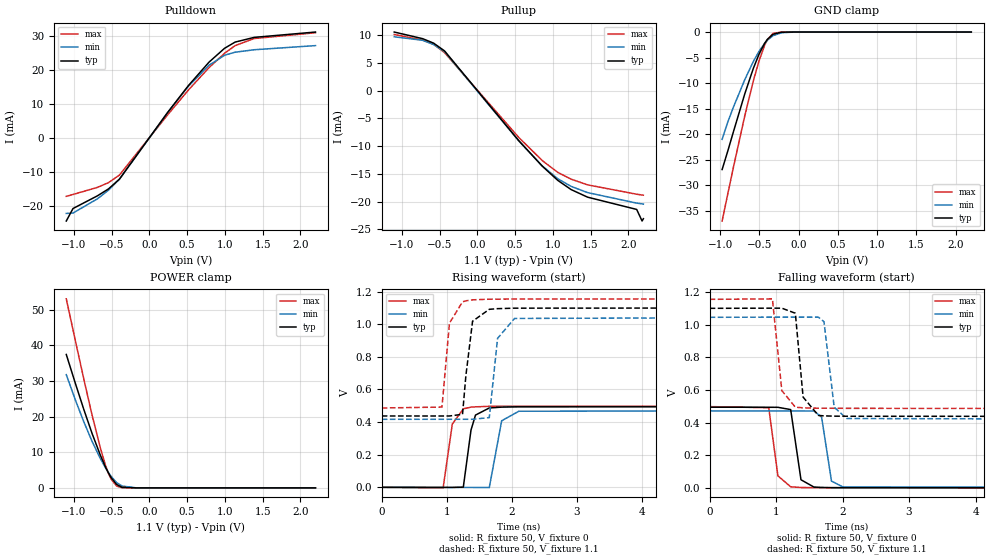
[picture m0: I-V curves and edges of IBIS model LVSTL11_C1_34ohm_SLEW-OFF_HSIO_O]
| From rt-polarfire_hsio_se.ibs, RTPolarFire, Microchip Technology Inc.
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|   Model LVSTL11_C1_34ohm_SLEW-OFF_HSIO_O
[Model]   LVSTL11_C1_34ohm_SLEW-OFF_HSIO_O
Model_type   Output
Polarity   Non-Inverting
Enable   Active-High
Vmeas =   0.55
Cref =   5p
Rref =   50
Vref =   0.55
|   typ   min   max
C_comp_pullup   1.335e-12   1.335e-12   1.380e-12
C_comp_pulldown  1.335e-12   1.335e-12   1.380e-12
[Temperature Range]  25C   125C   -55C
[Voltage Range]  1.1   1.045   1.155
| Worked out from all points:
|   slope of the pulldown table from 0 to 0.165 V, typ, clamps not added: 31.9 ohm
|   slope of the pullup table from 0 to 0.165 V, typ, clamps not added: 59.2 ohm
|   GND clamp passes 1 mA (typ) near -0.37 V on its own axis
|   POWER clamp passes 1 mA (typ) near -0.44 V on its own axis
|   rising waveform, R_fixture 50, V_fixture 0: 20-80 % time 96.7ps typ, 105ps min, 100ps max; typ from 0 V to 0.494 V
|   rising waveform, R_fixture 50, V_fixture 1.1: 20-80 % time 85.7ps typ, 93.7ps min, 85ps max; typ from 0.437 V to 1.1 V
|   falling waveform, R_fixture 50, V_fixture 0: 20-80 % time 78.2ps typ, 81.9ps min, 75.3ps max; typ from 0.494 V to 0 V
|   falling waveform, R_fixture 50, V_fixture 1.1: 20-80 % time 84.4ps typ, 93.4ps min, 83.2ps max; typ from 1.1 V to 0.437 V
[GND Clamp]
| Voltage   I(typ)   I(min)   I(max)
-974.5mV  -26.89mA   -20.99mA   -36.95mA
-902.3mV  -23.27mA   -17.6mA    -31.66mA
-830.2mV  -19.49mA   -14.67mA   -26.42mA
-685.8mV  -12.09mA   -9.316mA   -16.39mA
-577.5mV  -7.136mA   -5.784mA   -9.599mA
-505.3mV  -4.368mA   -3.797mA   -5.695mA
-433.1mV  -2.213mA   -2.208mA   -2.589mA
-397mV    -1.416mA   -1.586mA   -1.459mA
-324.8mV  -429.2uA   -701.1uA   -254.9uA
-216.6mV  -34.07uA   -130.9uA   -6.361uA
-36.09mV  -193.3nA   -2.444uA   -39.83nA
2.2V      0A         0A         0A
[POWER Clamp]
| Voltage   I(typ)   I(min)   I(max)
-1.1V     37.46mA    31.78mA    53.08mA
-974.5mV  29mA       24.39mA    40.83mA
-866.2mV  21.91mA    18.47mA    30.4mA
-758mV    15.25mA    13.04mA    20.38mA
-649.7mV  9.216mA    8.24mA     11.25mA
-577.5mV  5.7mA      5.494mA    6.143mA
-541.4mV  4.17mA     4.282mA    4.067mA
-505.3mV  2.839mA    3.193mA    2.41mA
-433.1mV  941.2uA    1.468mA    503.4uA
-360.9mV  155.7uA    510.6uA    35.77uA
-180.5mV  709.2nA    15.78uA    444.6nA
2.2V      0A         0A         0A
[Pullup]
| Voltage   I(typ)   I(min)   I(max)
-1.1V     10.56mA    9.704mA    10.12mA
-721.9mV  9.359mA    9.066mA    9.095mA
-577.5mV  8.552mA    8.303mA    8.343mA
-433.1mV  7.152mA    7.025mA    6.841mA
550mV     -9.021mA   -9.075mA   -8.442mA
859.4mV   -13.6mA    -13.56mA   -12.6mA
1.066V    -16.18mA   -15.89mA   -14.74mA
1.244V    -17.85mA   -17.27mA   -15.97mA
1.461V    -19.21mA   -18.39mA   -16.99mA
2.111V    -21.42mA   -20.28mA   -18.68mA
2.183V    -23.51mA   -20.42mA   -18.82mA
2.2V      -23.09mA   -20.46mA   -18.85mA
[Pulldown]
| Voltage   I(typ)   I(min)   I(max)
-1.1V     -24.51mA   -22.27mA   -17.23mA
-1.011V   -20.82mA   -22.16mA   -16.67mA
-685.8mV  -17.05mA   -17.93mA   -14.57mA
-541.4mV  -15.04mA   -15.4mA    -13.18mA
-397mV    -12.16mA   -12.2mA    -10.96mA
240.6mV   7.487mA    7.482mA    6.796mA
515.6mV   15.44mA    15.21mA    14.13mA
790.6mV   22.41mA    21.5mA     20.79mA
996.9mV   26.51mA    24.45mA    25.04mA
1.136V    28.33mA    25.34mA    27.29mA
1.389V    29.72mA    26.07mA    29.38mA
2.2V      31.3mA     27.29mA    31.09mA
[Ramp]
dV/dt_r   0.296469/96.7202p  0.28298/0.105146n  0.298686/0.100326n
dV/dt_f   0.397607/84.398p  0.376822/93.3612p  0.401223/83.1749p
R_load = 50
[Rising Waveform]
R_fixture = 50
V_fixture = 0
V_fixture_min = 0
V_fixture_max = 0
| Time   V(typ)   V(min)   V(max)
0s        1.119uV    2.142uV    1.531uV
943ps     -557.5uV   -458.9uV   -3.168mV
1.084ns   -641uV     -527.9uV   388mV
1.253ns   1.193mV    -610.5uV   481mV
1.371ns   350.7mV    -668.2uV   491.6mV
1.44ns    442.8mV    -701.9uV   493.2mV
1.652ns   486.4mV    -1.36mV    496.5mV
1.842ns   491.5mV    407.8mV    496.8mV
2.105ns   493.1mV    466.3mV    497.2mV
10ns      494.1mV    471.6mV    497.8mV
[Rising Waveform]
R_fixture = 50
V_fixture = 1.1
V_fixture_min = 1.045
V_fixture_max = 1.155
| Time   V(typ)   V(min)   V(max)
0s        437.3mV    416.9mV    486.3mV
925ps     437.2mV    417mV      491.8mV
1.04ns    437.2mV    417mV      1.006V
1.241ns   447.5mV    417mV      1.137V
1.292ns   683mV      417mV      1.143V
1.395ns   1.018V     417mV      1.149V
1.652ns   1.091V     427.3mV    1.153V
1.779ns   1.095V     912.8mV    1.153V
2.039ns   1.098V     1.035V     1.154V
10ns      1.1V       1.045V     1.155V
[Falling Waveform]
R_fixture = 50
V_fixture = 0
V_fixture_min = 0
V_fixture_max = 0
| Time   V(typ)   V(min)   V(max)
0s        494.1mV    471.6mV    497.8mV
889ps     493.6mV    471.2mV    491.2mV
1.027ns   493.5mV    471.1mV    73.67mV
1.219ns   479.6mV    471mV      6.391mV
1.374ns   49.57mV    471mV      2.093mV
1.568ns   4.983mV    470.9mV    1.004mV
1.684ns   2.475mV    434.1mV    980.1uV
1.833ns   1.136mV    41.25mV    949uV
2.007ns   980.9uV    5.326mV    912.6uV
10ns      2.578uV    3.272uV    2.369uV
[Falling Waveform]
R_fixture = 50
V_fixture = 1.1
V_fixture_min = 1.045
V_fixture_max = 1.155
| Time   V(typ)   V(min)   V(max)
0s        1.1V       1.045V     1.155V
944ps     1.101V     1.046V     1.158V
1.086ns   1.101V     1.046V     595.8mV
1.289ns   1.07V      1.046V     494.5mV
1.406ns   556mV      1.046V     490.1mV
1.636ns   443.9mV    1.046V     488.1mV
1.72ns    441.1mV    1.018V     487.9mV
1.874ns   439.3mV    493.9mV    487.5mV
2.062ns   438.7mV    424.8mV    487.1mV
10ns      437.3mV    416.9mV    486.3mV
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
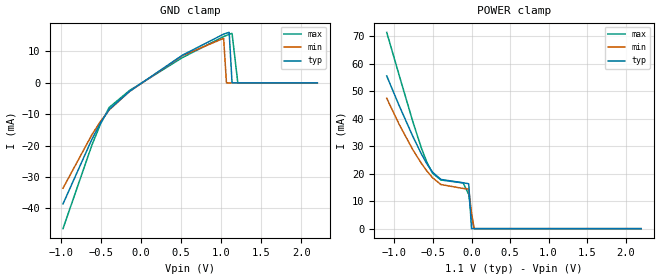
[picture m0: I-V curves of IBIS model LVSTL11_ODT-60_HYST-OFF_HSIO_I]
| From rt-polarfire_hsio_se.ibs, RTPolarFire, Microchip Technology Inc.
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|   Model LVSTL11_ODT-60_HYST-OFF_HSIO_I
[Model]   LVSTL11_ODT-60_HYST-OFF_HSIO_I
Model_type   Input
Vinl =   0.083
Vinh =   0.283
|   typ   min   max
C_comp_pullup   1.335e-12   1.335e-12   1.380e-12
C_comp_pulldown  1.335e-12   1.335e-12   1.380e-12
[Temperature Range]  25C   125C   -55C
[Voltage Range]  1.1   1.045   1.155
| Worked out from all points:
|   GND clamp passes 1 mA (typ) near -0.05 V on its own axis
|   POWER clamp passes 1 mA (typ) near -0.00 V on its own axis
[GND Clamp]
| Voltage   I(typ)   I(min)   I(max)
-974.5mV  -38.61mA   -33.6mA    -46.5mA
-613.6mV  -18mA      -16.54mA   -19.84mA
-505.3mV  -12.7mA    -12.26mA   -13.07mA
-397mV    -8.453mA   -8.626mA   -7.822mA
-144.4mV  -2.714mA   -2.754mA   -2.459mA
515.6mV   8.809mA    8.674mA    8.044mA
1.031V    15.55mA    14.2mA     14.78mA
1.066V    15.84mA    0A         15.13mA
1.1V      16.09mA    0A         15.46mA
1.136V    0A         0A         15.77mA
1.208V    0A         0A         0A
2.2V      0A         0A         0A
[POWER Clamp]
| Voltage   I(typ)   I(min)   I(max)
-1.1V     55.51mA    47.38mA    71.35mA
-938.4mV  44.69mA    37.89mA    55.73mA
-758mV    33.33mA    28.52mA    38.58mA
-649.7mV  27.13mA    23.72mA    29.26mA
-577.5mV  23.49mA    20.91mA    24.02mA
-505.3mV  20.5mA     18.51mA    20.16mA
-397mV    17.89mA    16.04mA    17.69mA
-108.3mV  16.68mA    14.61mA    16.61mA
-36.09mV  16.32mA    14.4mA     12.42mA
0V        0A         5.737mA    4.27mA
34.38mV   0A         0A         0A
2.2V      0A         0A         0A
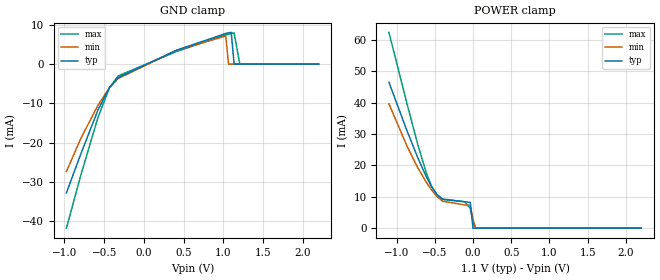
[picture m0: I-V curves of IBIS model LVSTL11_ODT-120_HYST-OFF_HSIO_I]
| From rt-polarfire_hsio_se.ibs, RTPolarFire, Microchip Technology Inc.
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|   Model LVSTL11_ODT-120_HYST-OFF_HSIO_I
[Model]   LVSTL11_ODT-120_HYST-OFF_HSIO_I
Model_type   Input
Vinl =   0.083
Vinh =   0.283
|   typ   min   max
C_comp_pullup   1.335e-12   1.335e-12   1.380e-12
C_comp_pulldown  1.335e-12   1.335e-12   1.380e-12
[Temperature Range]  25C   125C   -55C
[Voltage Range]  1.1   1.045   1.155
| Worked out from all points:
|   GND clamp passes 1 mA (typ) near -0.10 V on its own axis
|   POWER clamp passes 1 mA (typ) near -0.00 V on its own axis
[GND Clamp]
| Voltage   I(typ)   I(min)   I(max)
-974.5mV  -32.8mA    -27.34mA   -41.79mA
-794.1mV  -22.92mA   -18.97mA   -28.35mA
-577.5mV  -11.68mA   -10.46mA   -13.59mA
-433.1mV  -6.011mA   -6.018mA   -6.015mA
-324.8mV  -3.439mA   -3.7mA     -3mA
412.5mV   3.559mA    3.536mA    3.232mA
1.031V    7.814mA    7.159mA    7.45mA
1.066V    7.963mA    0A         7.632mA
1.1V      8.095mA    0A         7.803mA
1.136V    0A         0A         7.968mA
1.208V    0A         0A         0A
2.2V      0A         0A         0A
[POWER Clamp]
| Voltage   I(typ)   I(min)   I(max)
-1.1V     46.53mA    39.64mA    62.43mA
-866.2mV  31.19mA    26.3mA     39.94mA
-721.9mV  22.4mA     19.26mA    26.59mA
-613.6mV  16.52mA    14.72mA    17.81mA
-541.4mV  13.21mA    12.14mA    13.23mA
-469.2mV  10.71mA    10.04mA    10.29mA
-397mV    9.293mA    8.596mA    9.126mA
-108.3mV  8.409mA    7.39mA     8.409mA
-36.09mV  8.216mA    7.267mA    6.288mA
0V        0A         2.895mA    2.161mA
34.38mV   0A         0A         0A
2.2V      0A         0A         0A
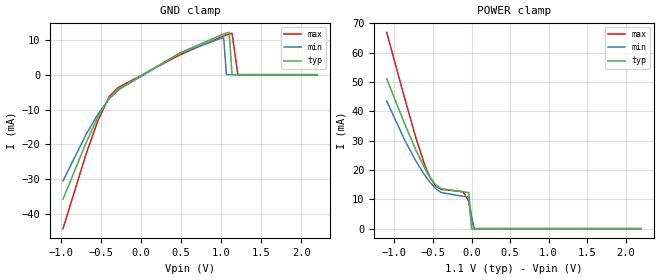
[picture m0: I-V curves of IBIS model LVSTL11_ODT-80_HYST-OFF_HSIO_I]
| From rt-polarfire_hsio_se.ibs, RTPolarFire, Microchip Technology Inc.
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|   Model LVSTL11_ODT-80_HYST-OFF_HSIO_I
[Model]   LVSTL11_ODT-80_HYST-OFF_HSIO_I
Model_type   Input
Vinl =   0.083
Vinh =   0.283
|   typ   min   max
C_comp_pullup   1.335e-12   1.335e-12   1.380e-12
C_comp_pulldown  1.335e-12   1.335e-12   1.380e-12
[Temperature Range]  25C   125C   -55C
[Voltage Range]  1.1   1.045   1.155
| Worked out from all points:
|   GND clamp passes 1 mA (typ) near -0.07 V on its own axis
|   POWER clamp passes 1 mA (typ) near -0.00 V on its own axis
[GND Clamp]
| Voltage   I(typ)   I(min)   I(max)
-974.5mV  -35.7mA    -30.48mA   -44.14mA
-685.8mV  -19.49mA   -17.09mA   -22.75mA
-541.4mV  -12.22mA   -11.43mA   -13.33mA
-397mV    -6.716mA   -6.887mA   -6.26mA
-288.8mV  -4.218mA   -4.439mA   -3.731mA
481.3mV   6.198mA    6.119mA    5.651mA
1.031V    11.71mA    10.69mA    11.13mA
1.066V    11.93mA    0A         11.4mA
1.1V      12.13mA    0A         11.65mA
1.136V    0A         0A         11.89mA
1.208V    0A         0A         0A
2.2V      0A         0A         0A
[POWER Clamp]
| Voltage   I(typ)   I(min)   I(max)
-1.1V     51.08mA    43.52mA    66.92mA
-866.2mV  35.67mA    30.14mA    44.38mA
-721.9mV  26.84mA    23.06mA    30.99mA
-613.6mV  20.93mA    18.51mA    22.19mA
-541.4mV  17.6mA     15.9mA     17.58mA
-469.2mV  15.08mA    13.79mA    14.63mA
-397mV    13.64mA    12.33mA    13.44mA
-108.3mV  12.58mA    11.01mA    12.54mA
-36.09mV  12.3mA     10.84mA    9.372mA
0V        0A         4.319mA    3.222mA
34.38mV   0A         0A         0A
2.2V      0A         0A         0A
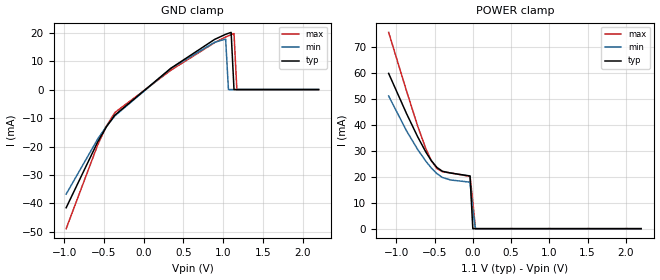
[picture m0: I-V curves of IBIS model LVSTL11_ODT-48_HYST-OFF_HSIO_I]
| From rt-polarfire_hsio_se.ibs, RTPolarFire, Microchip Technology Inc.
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|   Model LVSTL11_ODT-48_HYST-OFF_HSIO_I
[Model]   LVSTL11_ODT-48_HYST-OFF_HSIO_I
Model_type   Input
Vinl =   0.083
Vinh =   0.283
|   typ   min   max
C_comp_pullup   1.335e-12   1.335e-12   1.380e-12
C_comp_pulldown  1.335e-12   1.335e-12   1.380e-12
[Temperature Range]  25C   125C   -55C
[Voltage Range]  1.1   1.045   1.155
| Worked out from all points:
|   GND clamp passes 1 mA (typ) near -0.04 V on its own axis
|   POWER clamp passes 1 mA (typ) near -0.00 V on its own axis
[GND Clamp]
| Voltage   I(typ)   I(min)   I(max)
-974.5mV  -41.51mA   -36.73mA   -48.85mA
-577.5mV  -18.37mA   -17.35mA   -19.41mA
-469.2mV  -13.11mA   -12.95mA   -12.86mA
-360.9mV  -8.942mA   -9.192mA   -8.05mA
343.8mV   7.511mA    7.473mA    6.825mA
893.8mV   17.64mA    16.62mA    16.51mA
1.031V    19.41mA    17.72mA    18.46mA
1.066V    19.76mA    0A         18.89mA
1.1V      20.08mA    0A         19.29mA
1.136V    0A         0A         19.68mA
1.172V    0A         0A         0A
2.2V      0A         0A         0A
[POWER Clamp]
| Voltage   I(typ)   I(min)   I(max)
-1.1V     59.97mA    51.25mA    75.82mA
-866.2mV  44.45mA    37.78mA    53.18mA
-721.9mV  35.56mA    30.65mA    39.72mA
-613.6mV  29.59mA    26.05mA    30.86mA
-541.4mV  26.22mA    23.41mA    26.22mA
-469.2mV  23.65mA    21.26mA    23.22mA
-397mV    22.17mA    19.76mA    21.98mA
-288.8mV  21.48mA    18.8mA     21.52mA
-36.09mV  20.36mA    17.96mA    20.18mA
0V        0A         7.158mA    10.49mA
34.38mV   0A         0A         0A
2.2V      0A         0A         0A
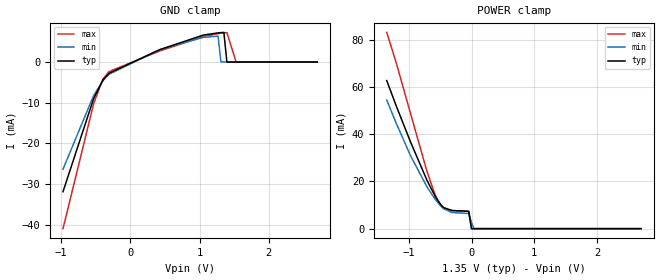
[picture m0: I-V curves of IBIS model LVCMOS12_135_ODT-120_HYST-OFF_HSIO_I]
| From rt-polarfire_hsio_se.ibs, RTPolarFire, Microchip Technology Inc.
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|   LVCMOS12_135_ODT-120_HYST-OFF_HSIO_I
[Model]   LVCMOS12_135_ODT-120_HYST-OFF_HSIO_I
Model_type  Input
Vinl =   0.42
Vinh =   0.78
|   typ   min   max
C_comp_pullup   1.335e-12   1.335e-12   1.380e-12
C_comp_pulldown  1.335e-12   1.335e-12   1.380e-12
[Temperature Range]   25   125   -55
[Voltage Range]   1.35   1.2825   1.4175
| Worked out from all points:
|   GND clamp passes 1 mA (typ) near -0.12 V on its own axis
|   POWER clamp passes 1 mA (typ) near -0.01 V on its own axis
[GND Clamp]
| Voltage   I(typ)   I(min)   I(max)
-974.5mV  -31.9mA    -26.36mA   -40.98mA
-531.6mV  -8.985mA   -8.229mA   -10.25mA
-398.7mV  -4.472mA   -4.642mA   -4.214mA
-310.1mV  -2.766mA   -3.023mA   -2.369mA
421.9mV   3.03mA     3.024mA    2.704mA
1.055V    6.631mA    6.071mA    6.249mA
1.266V    7.156mA    6.353mA    6.974mA
1.308V    7.221mA    0A         7.068mA
1.35V     7.281mA    0A         7.149mA
1.394V    0A         0A         7.224mA
1.527V    0A         0A         0A
2.7V      0A         0A         0A
[POWER Clamp]
| Voltage   I(typ)   I(min)   I(max)
-1.35V    62.72mA    54.46mA    83.13mA
-1.196V   51.79mA    44.46mA    69.98mA
-974.5mV  36.94mA    31.11mA    49.09mA
-708.7mV  20.47mA    17.65mA    24.2mA
-575.9mV  13.54mA    12.31mA    14.03mA
-487.3mV  10.09mA    9.514mA    9.658mA
-443mV    8.914mA    8.441mA    8.505mA
-310.1mV  7.672mA    6.821mA    7.671mA
-44.3mV   7.339mA    6.415mA    7.326mA
0V        0A         2.558mA    0A
42.19mV   0A         0A         0A
2.7V      0A         0A         0A
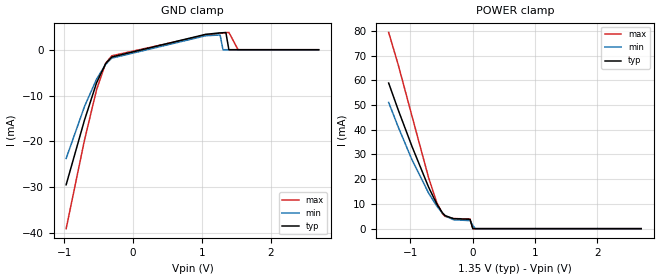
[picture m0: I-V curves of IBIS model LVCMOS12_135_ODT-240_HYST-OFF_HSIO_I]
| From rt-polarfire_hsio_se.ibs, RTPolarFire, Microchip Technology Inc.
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|   LVCMOS12_135_ODT-240_HYST-OFF_HSIO_I
[Model]   LVCMOS12_135_ODT-240_HYST-OFF_HSIO_I
Model_type  Input
Vinl =   0.42
Vinh =   0.78
|   typ   min   max
C_comp_pullup   1.335e-12   1.335e-12   1.380e-12
C_comp_pulldown  1.335e-12   1.335e-12   1.380e-12
[Temperature Range]   25   125   -55
[Voltage Range]   1.35   1.2825   1.4175
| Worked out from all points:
|   GND clamp passes 1 mA (typ) near -0.22 V on its own axis
|   POWER clamp passes 1 mA (typ) near -0.01 V on its own axis
[GND Clamp]
| Voltage   I(typ)   I(min)   I(max)
-974.5mV  -29.46mA   -23.72mA   -39.04mA
-708.7mV  -15.41mA   -12.43mA   -19.8mA
-531.6mV  -7.2mA     -6.398mA   -8.706mA
-398.7mV  -3.007mA   -3.167mA   -2.919mA
-310.1mV  -1.587mA   -1.837mA   -1.323mA
1.055V    3.357mA    3.047mA    3.188mA
1.266V    3.667mA    3.221mA    3.614mA
1.308V    3.71mA     0A         3.674mA
1.35V     3.75mA     0A         3.728mA
1.394V    0A         0A         3.78mA
1.527V    0A         0A         0A
2.7V      0A         0A         0A
[POWER Clamp]
| Voltage   I(typ)   I(min)   I(max)
-1.35V    58.9mA     51.07mA    79.39mA
-1.196V   47.99mA    41.1mA     66.26mA
-974.5mV  33.18mA    27.78mA    45.41mA
-708.7mV  16.76mA    14.36mA    20.57mA
-575.9mV  9.86mA     9.049mA    10.42mA
-487.3mV  6.422mA    6.265mA    6.068mA
-443mV    5.257mA    5.2mA      4.923mA
-310.1mV  4.044mA    3.605mA    4.118mA
-44.3mV   3.79mA     3.263mA    3.854mA
0V        0A         1.3mA      0A
42.19mV   0A         0A         0A
2.7V      0A         0A         0A
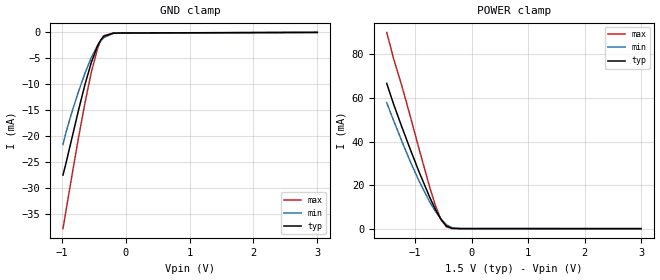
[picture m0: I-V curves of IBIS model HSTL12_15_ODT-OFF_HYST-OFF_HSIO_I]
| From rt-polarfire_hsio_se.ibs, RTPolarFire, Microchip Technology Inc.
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|   HSTL12_15_ODT-OFF_HYST-OFF_HSIO_I
[Model]   HSTL12_15_ODT-OFF_HYST-OFF_HSIO_I
Model_type  Input
Vinl =   0.5
Vinh =   0.7
|   typ   min   max
C_comp_pullup   1.335e-12   1.335e-12   1.380e-12
C_comp_pulldown  1.335e-12   1.335e-12   1.380e-12
[Temperature Range]   25   125   -55
[Voltage Range]   1.5   1.425   1.575
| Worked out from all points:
|   GND clamp passes 1 mA (typ) near -0.36 V on its own axis
|   POWER clamp passes 1 mA (typ) near -0.43 V on its own axis
[GND Clamp]
| Voltage   I(typ)   I(min)   I(max)
-984.4mV  -27.52mA   -21.63mA   -37.86mA
-935.2mV  -25.12mA   -19.18mA   -34.24mA
-836.7mV  -19.99mA   -15.04mA   -27.07mA
-738.3mV  -14.86mA   -11.32mA   -20.12mA
-639.8mV  -10.04mA   -7.876mA   -13.58mA
-541.4mV  -5.828mA   -4.866mA   -7.74mA
-443mV    -2.601mA   -2.514mA   -3.121mA
-393.7mV  -1.488mA   -1.649mA   -1.539mA
-344.5mV  -752.6uA   -1.007mA   -611uA
-196.9mV  -143.8uA   -195.1uA   -157.5uA
-49.22mV  -116uA     -100.6uA   -145.1uA
3V        0A         0A         0A
[POWER Clamp]
| Voltage   I(typ)   I(min)   I(max)
-1.5V     66.68mA    57.79mA    90.11mA
-1.378V   57.1mA     49.6mA     78.03mA
-1.23V    46.5mA     39.96mA    65.3mA
-1.083V   36.37mA    30.78mA    51.54mA
-935.2mV  26.53mA    22.25mA    37.31mA
-738.3mV  14.34mA    12.24mA    18.91mA
-639.8mV  8.895mA    7.998mA    10.72mA
-541.4mV  4.304mA    4.423mA    4.248mA
-443mV    1.219mA    1.774mA    782uA
-344.5mV  140.1uA    411.1uA    64.87uA
-196.9mV  20.92uA    33.7uA     23.72uA
3V        0A         0A         0A
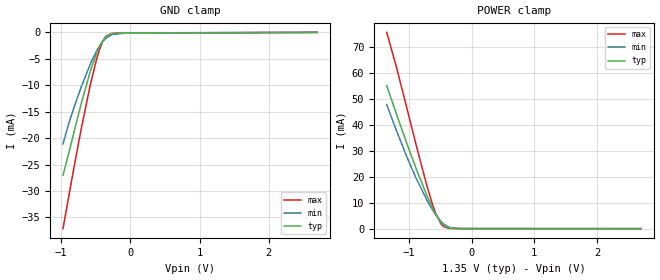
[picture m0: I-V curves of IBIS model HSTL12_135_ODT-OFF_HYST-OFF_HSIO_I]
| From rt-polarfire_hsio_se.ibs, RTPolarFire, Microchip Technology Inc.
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|   HSTL12_135_ODT-OFF_HYST-OFF_HSIO_I
[Model]   HSTL12_135_ODT-OFF_HYST-OFF_HSIO_I
Model_type  Input
Vinl =   0.5
Vinh =   0.7
|   typ   min   max
C_comp_pullup   1.335e-12   1.335e-12   1.380e-12
C_comp_pulldown  1.335e-12   1.335e-12   1.380e-12
[Temperature Range]   25   125   -55
[Voltage Range]   1.35   1.2825   1.4175
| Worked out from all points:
|   GND clamp passes 1 mA (typ) near -0.36 V on its own axis
|   POWER clamp passes 1 mA (typ) near -0.43 V on its own axis
[GND Clamp]
| Voltage   I(typ)   I(min)   I(max)
-974.5mV  -27.04mA   -21.09mA   -37.11mA
-885.9mV  -22.56mA   -17.01mA   -30.62mA
-797.3mV  -17.91mA   -13.51mA   -24.23mA
-708.7mV  -13.35mA   -10.24mA   -18.08mA
-575.9mV  -7.195mA   -5.842mA   -9.657mA
-487.3mV  -3.888mA   -3.463mA   -4.981mA
-443mV    -2.585mA   -2.501mA   -3.102mA
-398.7mV  -1.567mA   -1.712mA   -1.651mA
-354.4mV  -854.8uA   -1.105mA   -724.7uA
-265.8mV  -229.8uA   -394.9uA   -177uA
-44.3mV   -101uA     -87.28uA   -126.7uA
2.7V      0A         0A         0A
[POWER Clamp]
| Voltage   I(typ)   I(min)   I(max)
-1.35V    55.02mA    47.73mA    75.51mA
-1.196V   44.11mA    37.77mA    62.2mA
-1.019V   32.06mA    26.99mA    45.37mA
-885.9mV  23.35mA    19.58mA    32.59mA
-708.7mV  12.63mA    10.89mA    16.33mA
-620.2mV  7.886mA    7.215mA    9.231mA
-575.9mV  5.774mA    5.577mA    6.216mA
-487.3mV  2.365mA    2.814mA    1.889mA
-443mV    1.216mA    1.762mA    761.8uA
-354.4mV  176.1uA    479.5uA    75.41uA
-177.2mV  18.34uA    26.3uA     21.09uA
2.7V      0A         0A         0A
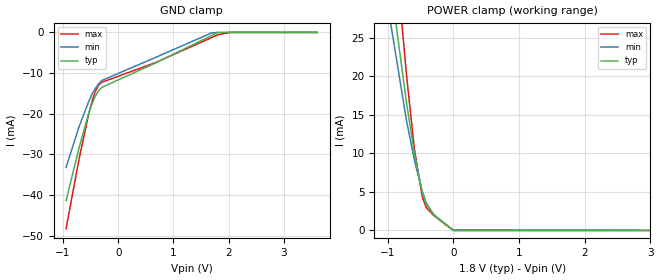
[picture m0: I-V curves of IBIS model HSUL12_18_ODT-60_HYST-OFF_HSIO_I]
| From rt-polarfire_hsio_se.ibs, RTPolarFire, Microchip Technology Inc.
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|   HSUL12_18_ODT-60_HYST-OFF_HSIO_I
[Model]   HSUL12_18_ODT-60_HYST-OFF_HSIO_I
Model_type  Input
Vinl =   0.5
Vinh =   0.7
|   typ   min   max
C_comp_pullup   1.335e-12   1.335e-12   1.380e-12
C_comp_pulldown  1.335e-12   1.335e-12   1.380e-12
[Temperature Range]   25   125   -55
[Voltage Range]   1.8   1.71   1.89
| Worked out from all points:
|   POWER clamp passes 1 mA (typ) near -0.14 V on its own axis
[GND Clamp]
| Voltage   I(typ)   I(min)   I(max)
-945mV    -41.38mA   -33.21mA   -48.31mA
-708.7mV  -28.37mA   -23.19mA   -31.08mA
-531.6mV  -19.75mA   -16.88mA   -19.88mA
-472.5mV  -17.48mA   -15.17mA   -16.87mA
-413.4mV  -15.65mA   -13.75mA   -14.47mA
-354.4mV  -14.34mA   -12.64mA   -12.94mA
-295.3mV  -13.52mA   -11.82mA   -12.27mA
675mV     -7.529mA   -6.162mA   -7.422mA
1.688V    -784.6uA   -137.4uA   -1.304mA
1.8V      222.5nA    0A         -581.7uA
2.036V    0A         0A         0A
3.6V      0A         0A         0A
[POWER Clamp]
| Voltage   I(typ)   I(min)   I(max)
-1.8V     97.61mA    81.86mA    133mA
-1.595V   79.25mA    67.67mA    105.7mA
-1.417V   64.65mA    55.69mA    86.13mA
-1.181V   47.43mA    40.33mA    64.9mA
-1.004V   35.23mA    29.58mA    47.93mA
-708.7mV  16.42mA    14.1mA     19.93mA
-590.6mV  9.951mA    9.092mA    10.54mA
-472.5mV  5.01mA     5.082mA    4.407mA
-413.4mV  3.475mA    3.626mA    3.002mA
-295.3mV  2.087mA    1.955mA    1.918mA
0V        0A         84.64uA    0A
3.6V      0A         0A         0A
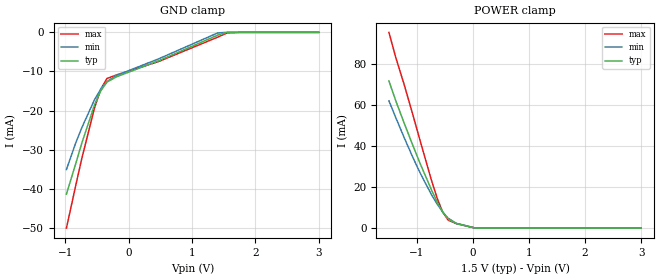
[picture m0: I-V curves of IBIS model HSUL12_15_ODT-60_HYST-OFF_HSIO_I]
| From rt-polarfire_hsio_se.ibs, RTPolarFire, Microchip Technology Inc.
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|   HSUL12_15_ODT-60_HYST-OFF_HSIO_I
[Model]   HSUL12_15_ODT-60_HYST-OFF_HSIO_I
Model_type  Input
Vinl =   0.5
Vinh =   0.7
|   typ   min   max
C_comp_pullup   1.335e-12   1.335e-12   1.380e-12
C_comp_pulldown  1.335e-12   1.335e-12   1.380e-12
[Temperature Range]   25   125   -55
[Voltage Range]   1.5   1.425   1.575
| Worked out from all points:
|   POWER clamp passes 1 mA (typ) near -0.13 V on its own axis
[GND Clamp]
| Voltage   I(typ)   I(min)   I(max)
-984.4mV  -41.39mA   -35.1mA    -50.09mA
-836.7mV  -33.55mA   -28.23mA   -39.12mA
-738.3mV  -28.18mA   -24.28mA   -32.03mA
-541.4mV  -18.57mA   -17.24mA   -19.36mA
-443mV    -14.99mA   -14.52mA   -14.55mA
-344.5mV  -12.73mA   -12.59mA   -11.81mA
-196.9mV  -11.39mA   -11.04mA   -10.9mA
468.8mV   -7.287mA   -6.794mA   -7.489mA
1.406V    -697.8uA   -137.9uA   -1.222mA
1.549V    0A         0A         -187.9uA
1.746V    0A         0A         0A
3V        0A         0A         0A
[POWER Clamp]
| Voltage   I(typ)   I(min)   I(max)
-1.5V     71.51mA    61.85mA    95.14mA
-1.378V   61.89mA    53.72mA    82.93mA
-1.23V    51.16mA    44.13mA    69.93mA
-1.083V   40.87mA    34.95mA    56.04mA
-935.2mV  30.89mA    26.35mA    41.69mA
-738.3mV  18.42mA    16.12mA    23mA
-639.8mV  12.76mA    11.7mA     14.61mA
-541.4mV  7.869mA    7.845mA    7.833mA
-443mV    4.354mA    4.803mA    3.896mA
-295.3mV  2.228mA    2.318mA    2.158mA
46.88mV   0A         0A         0A
3V        0A         0A         0A
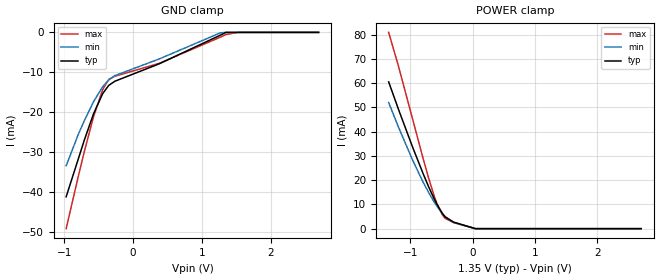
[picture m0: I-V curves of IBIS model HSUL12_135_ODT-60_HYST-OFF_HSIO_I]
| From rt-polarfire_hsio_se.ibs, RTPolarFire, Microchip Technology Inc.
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|   HSUL12_135_ODT-60_HYST-OFF_HSIO_I
[Model]   HSUL12_135_ODT-60_HYST-OFF_HSIO_I
Model_type  Input
Vinl =   0.5
Vinh =   0.7
|   typ   min   max
C_comp_pullup   1.335e-12   1.335e-12   1.380e-12
C_comp_pulldown  1.335e-12   1.335e-12   1.380e-12
[Temperature Range]   25   125   -55
[Voltage Range]   1.35   1.2825   1.4175
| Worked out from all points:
|   POWER clamp passes 1 mA (typ) near -0.12 V on its own axis
[GND Clamp]
| Voltage   I(typ)   I(min)   I(max)
-974.5mV  -41.09mA   -33.34mA   -49.06mA
-797.3mV  -31.61mA   -25.47mA   -35.96mA
-708.7mV  -26.85mA   -22.03mA   -29.69mA
-575.9mV  -20.35mA   -17.32mA   -21.08mA
-443mV    -15.31mA   -13.59mA   -14.31mA
-354.4mV  -13.24mA   -11.88mA   -11.74mA
-265.8mV  -12.21mA   -10.81mA   -10.96mA
379.7mV   -7.853mA   -6.645mA   -7.741mA
1.266V    -723.6uA   -129.6uA   -1.224mA
1.35V     140.4nA    0A         -546.6uA
1.527V    0A         0A         0A
2.7V      0A         0A         0A
[POWER Clamp]
| Voltage   I(typ)   I(min)   I(max)
-1.35V    60.51mA    51.99mA    80.9mA
-1.196V   49.44mA    42.09mA    67.3mA
-974.5mV  34.18mA    28.74mA    46.02mA
-797.3mV  22.68mA    19.17mA    28.92mA
-708.7mV  17.28mA    14.9mA     20.83mA
-620.2mV  12.29mA    11.03mA    13.51mA
-575.9mV  10.03mA    9.268mA    10.36mA
-487.3mV  6.239mA    6.186mA    5.633mA
-443mV    4.842mA    4.933mA    4.24mA
-310.1mV  2.703mA    2.571mA    2.524mA
42.19mV   0A         0A         0A
2.7V      0A         0A         0A
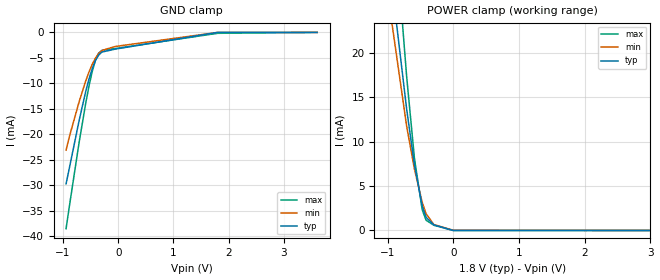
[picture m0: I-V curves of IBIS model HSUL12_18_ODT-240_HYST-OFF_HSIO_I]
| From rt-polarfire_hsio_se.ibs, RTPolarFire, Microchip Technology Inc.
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|   HSUL12_18_ODT-240_HYST-OFF_HSIO_I
[Model]   HSUL12_18_ODT-240_HYST-OFF_HSIO_I
Model_type  Input
Vinl =   0.5
Vinh =   0.7
|   typ   min   max
C_comp_pullup   1.335e-12   1.335e-12   1.380e-12
C_comp_pulldown  1.335e-12   1.335e-12   1.380e-12
[Temperature Range]   25   125   -55
[Voltage Range]   1.8   1.71   1.89
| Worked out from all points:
|   POWER clamp passes 1 mA (typ) near -0.37 V on its own axis
[GND Clamp]
| Voltage   I(typ)   I(min)   I(max)
-945mV    -29.69mA   -23.09mA   -38.48mA
-885.9mV  -26.62mA   -20.46mA   -34.13mA
-708.7mV  -17.28mA   -13.6mA    -21.55mA
-590.6mV  -11.65mA   -9.561mA   -13.97mA
-531.6mV  -9.216mA   -7.802mA   -10.62mA
-472.5mV  -7.145mA   -6.287mA   -7.719mA
-413.4mV  -5.529mA   -5.059mA   -5.451mA
-354.4mV  -4.441mA   -4.146mA   -4.054mA
-295.3mV  -3.856mA   -3.538mA   -3.523mA
-59.06mV  -3.284mA   -2.767mA   -3.171mA
1.8V      228.7nA    0A         -176.6uA
3.6V      0A         0A         0A
[POWER Clamp]
| Voltage   I(typ)   I(min)   I(max)
-1.8V     94.25mA    79.41mA    129.7mA
-1.595V   75.81mA    65.13mA    102.4mA
-1.417V   61.24mA    53.1mA     82.82mA
-1.181V   44.18mA    37.72mA    61.86mA
-1.004V   32.13mA    27.01mA    44.97mA
-708.7mV  13.66mA    11.74mA    17.32mA
-590.6mV  7.41mA     6.918mA    8.141mA
-472.5mV  2.788mA    3.171mA    2.333mA
-413.4mV  1.473mA    1.89mA     1.155mA
-295.3mV  630.8uA    666uA      588.2uA
0V        0A         25.36uA    0A
3.6V      0A         0A         0A
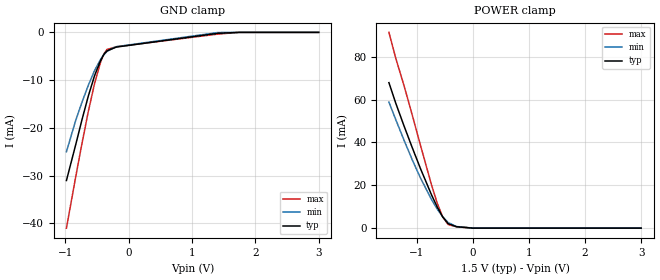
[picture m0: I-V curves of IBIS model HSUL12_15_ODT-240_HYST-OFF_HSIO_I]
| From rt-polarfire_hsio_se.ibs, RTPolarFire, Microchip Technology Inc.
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|   HSUL12_15_ODT-240_HYST-OFF_HSIO_I
[Model]   HSUL12_15_ODT-240_HYST-OFF_HSIO_I
Model_type  Input
Vinl =   0.5
Vinh =   0.7
|   typ   min   max
C_comp_pullup   1.335e-12   1.335e-12   1.380e-12
C_comp_pulldown  1.335e-12   1.335e-12   1.380e-12
[Temperature Range]   25   125   -55
[Voltage Range]   1.5   1.425   1.575
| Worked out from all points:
|   POWER clamp passes 1 mA (typ) near -0.36 V on its own axis
[GND Clamp]
| Voltage   I(typ)   I(min)   I(max)
-984.4mV  -31.05mA   -25.02mA   -41.02mA
-836.7mV  -23.47mA   -18.39mA   -30.19mA
-738.3mV  -18.28mA   -14.62mA   -23.22mA
-639.8mV  -13.4mA    -11.12mA   -16.65mA
-541.4mV  -9.125mA   -8.04mA    -10.8mA
-443mV    -5.819mA   -5.603mA   -6.148mA
-393.7mV  -4.659mA   -4.689mA   -4.541mA
-344.5mV  -3.872mA   -3.995mA   -3.583mA
-196.9mV  -3.081mA   -2.999mA   -3.015mA
1.406V    -200.8uA   -37.31uA   -361.2uA
1.746V    0A         0A         0A
3V        0A         0A         0A
[POWER Clamp]
| Voltage   I(typ)   I(min)   I(max)
-1.5V     67.89mA    58.8mA     91.36mA
-1.378V   58.3mA     50.63mA    79.26mA
-1.23V    47.66mA    41mA       66.46mA
-1.083V   37.5mA     31.83mA    52.68mA
-935.2mV  27.65mA    23.28mA    38.46mA
-738.3mV  15.42mA    13.23mA    20.01mA
-639.8mV  9.928mA    8.964mA    11.78mA
-541.4mV  5.268mA    5.326mA    5.241mA
-443mV    2.078mA    2.58mA     1.662mA
-295.3mV  661.3uA    747.5uA    647.2uA
0V        0A         24.56uA    0A
3V        0A         0A         0A
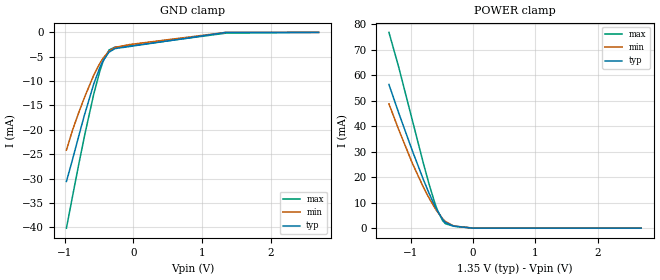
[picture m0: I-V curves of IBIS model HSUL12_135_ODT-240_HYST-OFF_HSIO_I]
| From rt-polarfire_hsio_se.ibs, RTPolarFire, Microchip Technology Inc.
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|   HSUL12_135_ODT-240_HYST-OFF_HSIO_I
[Model]   HSUL12_135_ODT-240_HYST-OFF_HSIO_I
Model_type  Input
Vinl =   0.5
Vinh =   0.7
|   typ   min   max
C_comp_pullup   1.335e-12   1.335e-12   1.380e-12
C_comp_pulldown  1.335e-12   1.335e-12   1.380e-12
[Temperature Range]   25   125   -55
[Voltage Range]   1.35   1.2825   1.4175
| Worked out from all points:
|   POWER clamp passes 1 mA (typ) near -0.35 V on its own axis
[GND Clamp]
| Voltage   I(typ)   I(min)   I(max)
-974.5mV  -30.6mA    -24.17mA   -40.18mA
-885.9mV  -26.1mA    -20.07mA   -33.66mA
-797.3mV  -21.4mA    -16.54mA   -27.25mA
-708.7mV  -16.8mA    -13.24mA   -21.08mA
-575.9mV  -10.57mA   -8.771mA   -12.63mA
-487.3mV  -7.203mA   -6.335mA   -7.935mA
-443mV    -5.865mA   -5.34mA    -6.039mA
-354.4mV  -4.052mA   -3.87mA    -3.619mA
-265.8mV  -3.327mA   -3.071mA   -3.014mA
-44.3mV   -2.884mA   -2.48mA    -2.767mA
1.35V     145.8nA    0A         -158.9uA
2.7V      0A         0A         0A
[POWER Clamp]
| Voltage   I(typ)   I(min)   I(max)
-1.35V    56.4mA     48.79mA    76.86mA
-1.196V   45.44mA    38.85mA    63.49mA
-974.5mV  30.4mA     25.52mA    42.38mA
-797.3mV  19.11mA    16.09mA    25.49mA
-708.7mV  13.86mA    11.93mA    17.54mA
-620.2mV  9.059mA    8.211mA    10.4mA
-575.9mV  6.912mA    6.545mA    7.349mA
-487.3mV  3.41mA     3.705mA    2.928mA
-443mV    2.199mA    2.602mA    1.734mA
-310.1mV  791.9uA    844.5uA    744.7uA
0V        0A         22.85uA    0A
2.7V      0A         0A         0A
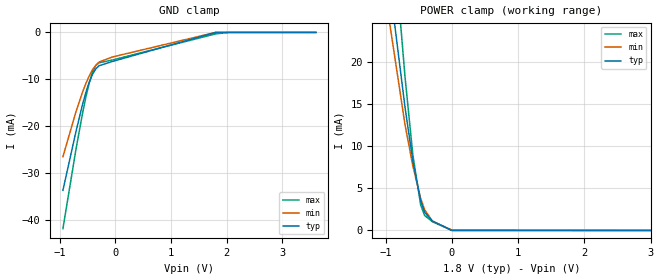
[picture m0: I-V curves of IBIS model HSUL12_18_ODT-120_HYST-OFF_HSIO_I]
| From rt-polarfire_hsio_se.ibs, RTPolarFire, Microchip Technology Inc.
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|   HSUL12_18_ODT-120_HYST-OFF_HSIO_I
[Model]   HSUL12_18_ODT-120_HYST-OFF_HSIO_I
Model_type  Input
Vinl =   0.5
Vinh =   0.7
|   typ   min   max
C_comp_pullup   1.335e-12   1.335e-12   1.380e-12
C_comp_pulldown  1.335e-12   1.335e-12   1.380e-12
[Temperature Range]   25   125   -55
[Voltage Range]   1.8   1.71   1.89
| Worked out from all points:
|   POWER clamp passes 1 mA (typ) near -0.26 V on its own axis
[GND Clamp]
| Voltage   I(typ)   I(min)   I(max)
-945mV    -33.61mA   -26.47mA   -41.77mA
-708.7mV  -21mA      -16.81mA   -24.74mA
-590.6mV  -15.25mA   -12.66mA   -17.11mA
-531.6mV  -12.75mA   -10.84mA   -13.73mA
-472.5mV  -10.61mA   -9.262mA   -10.79mA
-413.4mV  -8.925mA   -7.969mA   -8.487mA
-354.4mV  -7.761mA   -6.988mA   -7.047mA
-295.3mV  -7.099mA   -6.31mA    -6.468mA
-59.06mV  -6.199mA   -5.245mA   -5.882mA
1.8V      218.7nA    0A         -314.5uA
2.036V    0A         0A         0A
3.6V      0A         0A         0A
[POWER Clamp]
| Voltage   I(typ)   I(min)   I(max)
-1.8V     95.37mA    80.23mA    130.8mA
-1.595V   76.96mA    65.98mA    103.5mA
-1.417V   62.37mA    53.96mA    83.93mA
-1.181V   45.27mA    38.59mA    62.88mA
-1.004V   33.18mA    27.87mA    45.99mA
-708.7mV  14.6mA     12.54mA    18.22mA
-590.6mV  8.273mA    7.654mA    8.963mA
-472.5mV  3.54mA     3.817mA    3.041mA
-413.4mV  2.15mA     2.476mA    1.785mA
-295.3mV  1.123mA    1.101mA    1.042mA
0V        0A         45.31uA    0A
3.6V      0A         0A         0A
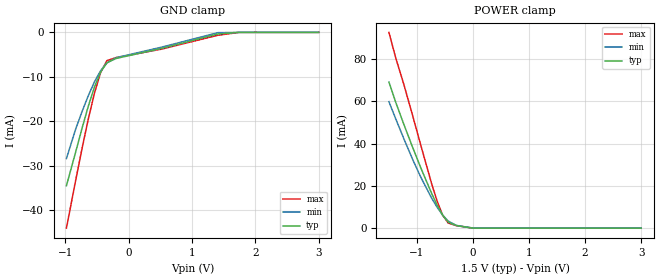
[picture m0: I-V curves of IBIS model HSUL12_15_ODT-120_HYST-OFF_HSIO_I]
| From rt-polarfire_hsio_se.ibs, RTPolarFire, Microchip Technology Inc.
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|   HSUL12_15_ODT-120_HYST-OFF_HSIO_I
[Model]   HSUL12_15_ODT-120_HYST-OFF_HSIO_I
Model_type  Input
Vinl =   0.5
Vinh =   0.7
|   typ   min   max
C_comp_pullup   1.335e-12   1.335e-12   1.380e-12
C_comp_pulldown  1.335e-12   1.335e-12   1.380e-12
[Temperature Range]   25   125   -55
[Voltage Range]   1.5   1.425   1.575
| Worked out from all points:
|   POWER clamp passes 1 mA (typ) near -0.25 V on its own axis
[GND Clamp]
| Voltage   I(typ)   I(min)   I(max)
-984.4mV  -34.51mA   -28.39mA   -44.05mA
-836.7mV  -26.84mA   -21.67mA   -33.17mA
-738.3mV  -21.6mA    -17.85mA   -26.16mA
-639.8mV  -16.65mA   -14.28mA   -19.56mA
-541.4mV  -12.29mA   -11.11mA   -13.67mA
-443mV    -8.891mA   -8.583mA   -8.965mA
-344.5mV  -6.837mA   -6.868mA   -6.341mA
-196.9mV  -5.862mA   -5.685mA   -5.66mA
515.6mV   -3.62mA    -3.337mA   -3.781mA
1.406V    -368.1uA   -71.11uA   -652.3uA
1.746V    0A         0A         0A
3V        0A         0A         0A
[POWER Clamp]
| Voltage   I(typ)   I(min)   I(max)
-1.5V     69.1mA     59.82mA    92.62mA
-1.378V   59.5mA     51.66mA    80.48mA
-1.23V    48.83mA    42.05mA    67.62mA
-1.083V   38.63mA    32.87mA    53.82mA
-935.2mV  28.75mA    24.3mA     39.57mA
-738.3mV  16.44mA    14.2mA     21.03mA
-639.8mV  10.88mA    9.884mA    12.74mA
-541.4mV  6.147mA    6.173mA    6.122mA
-443mV    2.846mA    3.327mA    2.42mA
-295.3mV  1.189mA    1.275mA    1.159mA
0V        0A         44.74uA    0A
3V        0A         0A         0A
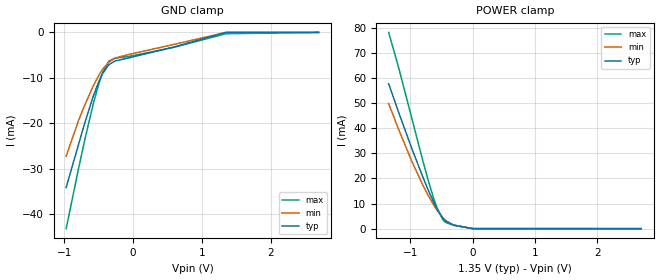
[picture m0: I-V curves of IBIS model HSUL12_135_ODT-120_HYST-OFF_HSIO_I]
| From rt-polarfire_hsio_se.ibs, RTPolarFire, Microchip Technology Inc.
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|   HSUL12_135_ODT-120_HYST-OFF_HSIO_I
[Model]   HSUL12_135_ODT-120_HYST-OFF_HSIO_I
Model_type  Input
Vinl =   0.5
Vinh =   0.7
|   typ   min   max
C_comp_pullup   1.335e-12   1.335e-12   1.380e-12
C_comp_pulldown  1.335e-12   1.335e-12   1.380e-12
[Temperature Range]   25   125   -55
[Voltage Range]   1.35   1.2825   1.4175
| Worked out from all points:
|   POWER clamp passes 1 mA (typ) near -0.22 V on its own axis
[GND Clamp]
| Voltage   I(typ)   I(min)   I(max)
-974.5mV  -34.11mA   -27.22mA   -43.16mA
-797.3mV  -24.81mA   -19.51mA   -30.18mA
-708.7mV  -20.16mA   -16.16mA   -23.97mA
-575.9mV  -13.84mA   -11.62mA   -15.47mA
-487.3mV  -10.4mA    -9.12mA    -10.73mA
-443mV    -9.022mA   -8.091mA   -8.815mA
-354.4mV  -7.121mA   -6.544mA   -6.342mA
-265.8mV  -6.295mA   -5.655mA   -5.678mA
-44.3mV   -5.54mA    -4.781mA   -5.235mA
590.6mV   -3.224mA   -2.659mA   -3.297mA
1.35V     139.9nA    0A         -289.7uA
2.7V      0A         0A         0A
[POWER Clamp]
| Voltage   I(typ)   I(min)   I(max)
-1.35V    57.77mA    49.86mA    78.21mA
-1.196V   46.78mA    39.93mA    64.77mA
-974.5mV  31.67mA    26.6mA     43.62mA
-797.3mV  20.32mA    17.12mA    26.66mA
-708.7mV  15.01mA    12.92mA    18.65mA
-620.2mV  10.15mA    9.157mA    11.45mA
-575.9mV  7.961mA    7.459mA    8.367mA
-487.3mV  4.361mA    4.537mA    3.842mA
-443mV    3.087mA    3.384mA    2.581mA
-310.1mV  1.434mA    1.423mA    1.346mA
0V        0A         41.88uA    0A
2.7V      0A         0A         0A
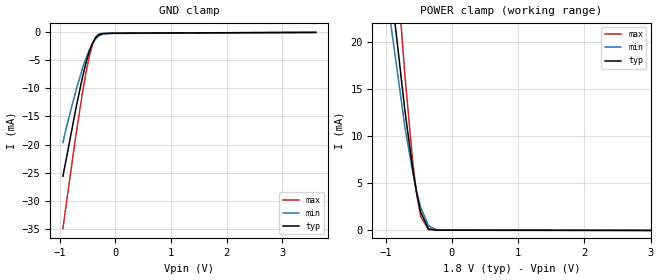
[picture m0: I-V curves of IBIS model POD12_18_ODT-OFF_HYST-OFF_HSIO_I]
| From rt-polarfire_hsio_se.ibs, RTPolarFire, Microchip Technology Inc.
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|   POD12_18_ODT-OFF_HYST-OFF_HSIO_I
[Model]   POD12_18_ODT-OFF_HYST-OFF_HSIO_I
Model_type  Input
Vinl =   0.76
Vinh =   0.92
|   typ   min   max
C_comp_pullup   1.335e-12   1.335e-12   1.380e-12
C_comp_pulldown  1.335e-12   1.335e-12   1.380e-12
[Temperature Range]   25   125   -55
[Voltage Range]   1.8   1.71   1.89
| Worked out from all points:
|   GND clamp passes 1 mA (typ) near -0.36 V on its own axis
|   POWER clamp passes 1 mA (typ) near -0.43 V on its own axis
[GND Clamp]
| Voltage   I(typ)   I(min)   I(max)
-945mV    -25.65mA   -19.67mA   -35.01mA
-885.9mV  -22.62mA   -17.05mA   -30.68mA
-708.7mV  -13.41mA   -10.28mA   -18.15mA
-590.6mV  -7.869mA   -6.332mA   -10.59mA
-531.6mV  -5.486mA   -4.626mA   -7.251mA
-472.5mV  -3.472mA   -3.165mA   -4.371mA
-413.4mV  -1.919mA   -1.995mA   -2.136mA
-354.4mV  -899.9uA   -1.144mA   -780.2uA
-295.3mV  -390.4uA   -603.1uA   -297.1uA
-236.2mV  -212uA     -316.1uA   -206.4uA
-59.06mV  -146.2uA   -127.5uA   -182.2uA
3.6V      0A         0A         0A
[POWER Clamp]
| Voltage   I(typ)   I(min)   I(max)
-1.8V     93.12mA    78.59mA    128.6mA
-1.595V   74.67mA    64.28mA    101.2mA
-1.417V   60.1mA     52.23mA    81.72mA
-1.181V   43.09mA    36.85mA    60.84mA
-1.004V   31.09mA    26.15mA    43.96mA
-708.7mV  12.66mA    10.92mA    16.36mA
-590.6mV  6.469mA    6.137mA    7.226mA
-531.6mV  3.923mA    4.132mA    3.797mA
-472.5mV  1.944mA    2.471mA    1.511mA
-354.4mV  179.4uA    509.1uA    86.53uA
-236.2mV  27.5uA     61.89uA    29.14uA
3.6V      0A         0A         0A
